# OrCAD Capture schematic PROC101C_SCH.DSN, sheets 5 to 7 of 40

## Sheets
5 30.PCIe INTERFACE: size C; title: PCIe INTERFACE; note: PROC067
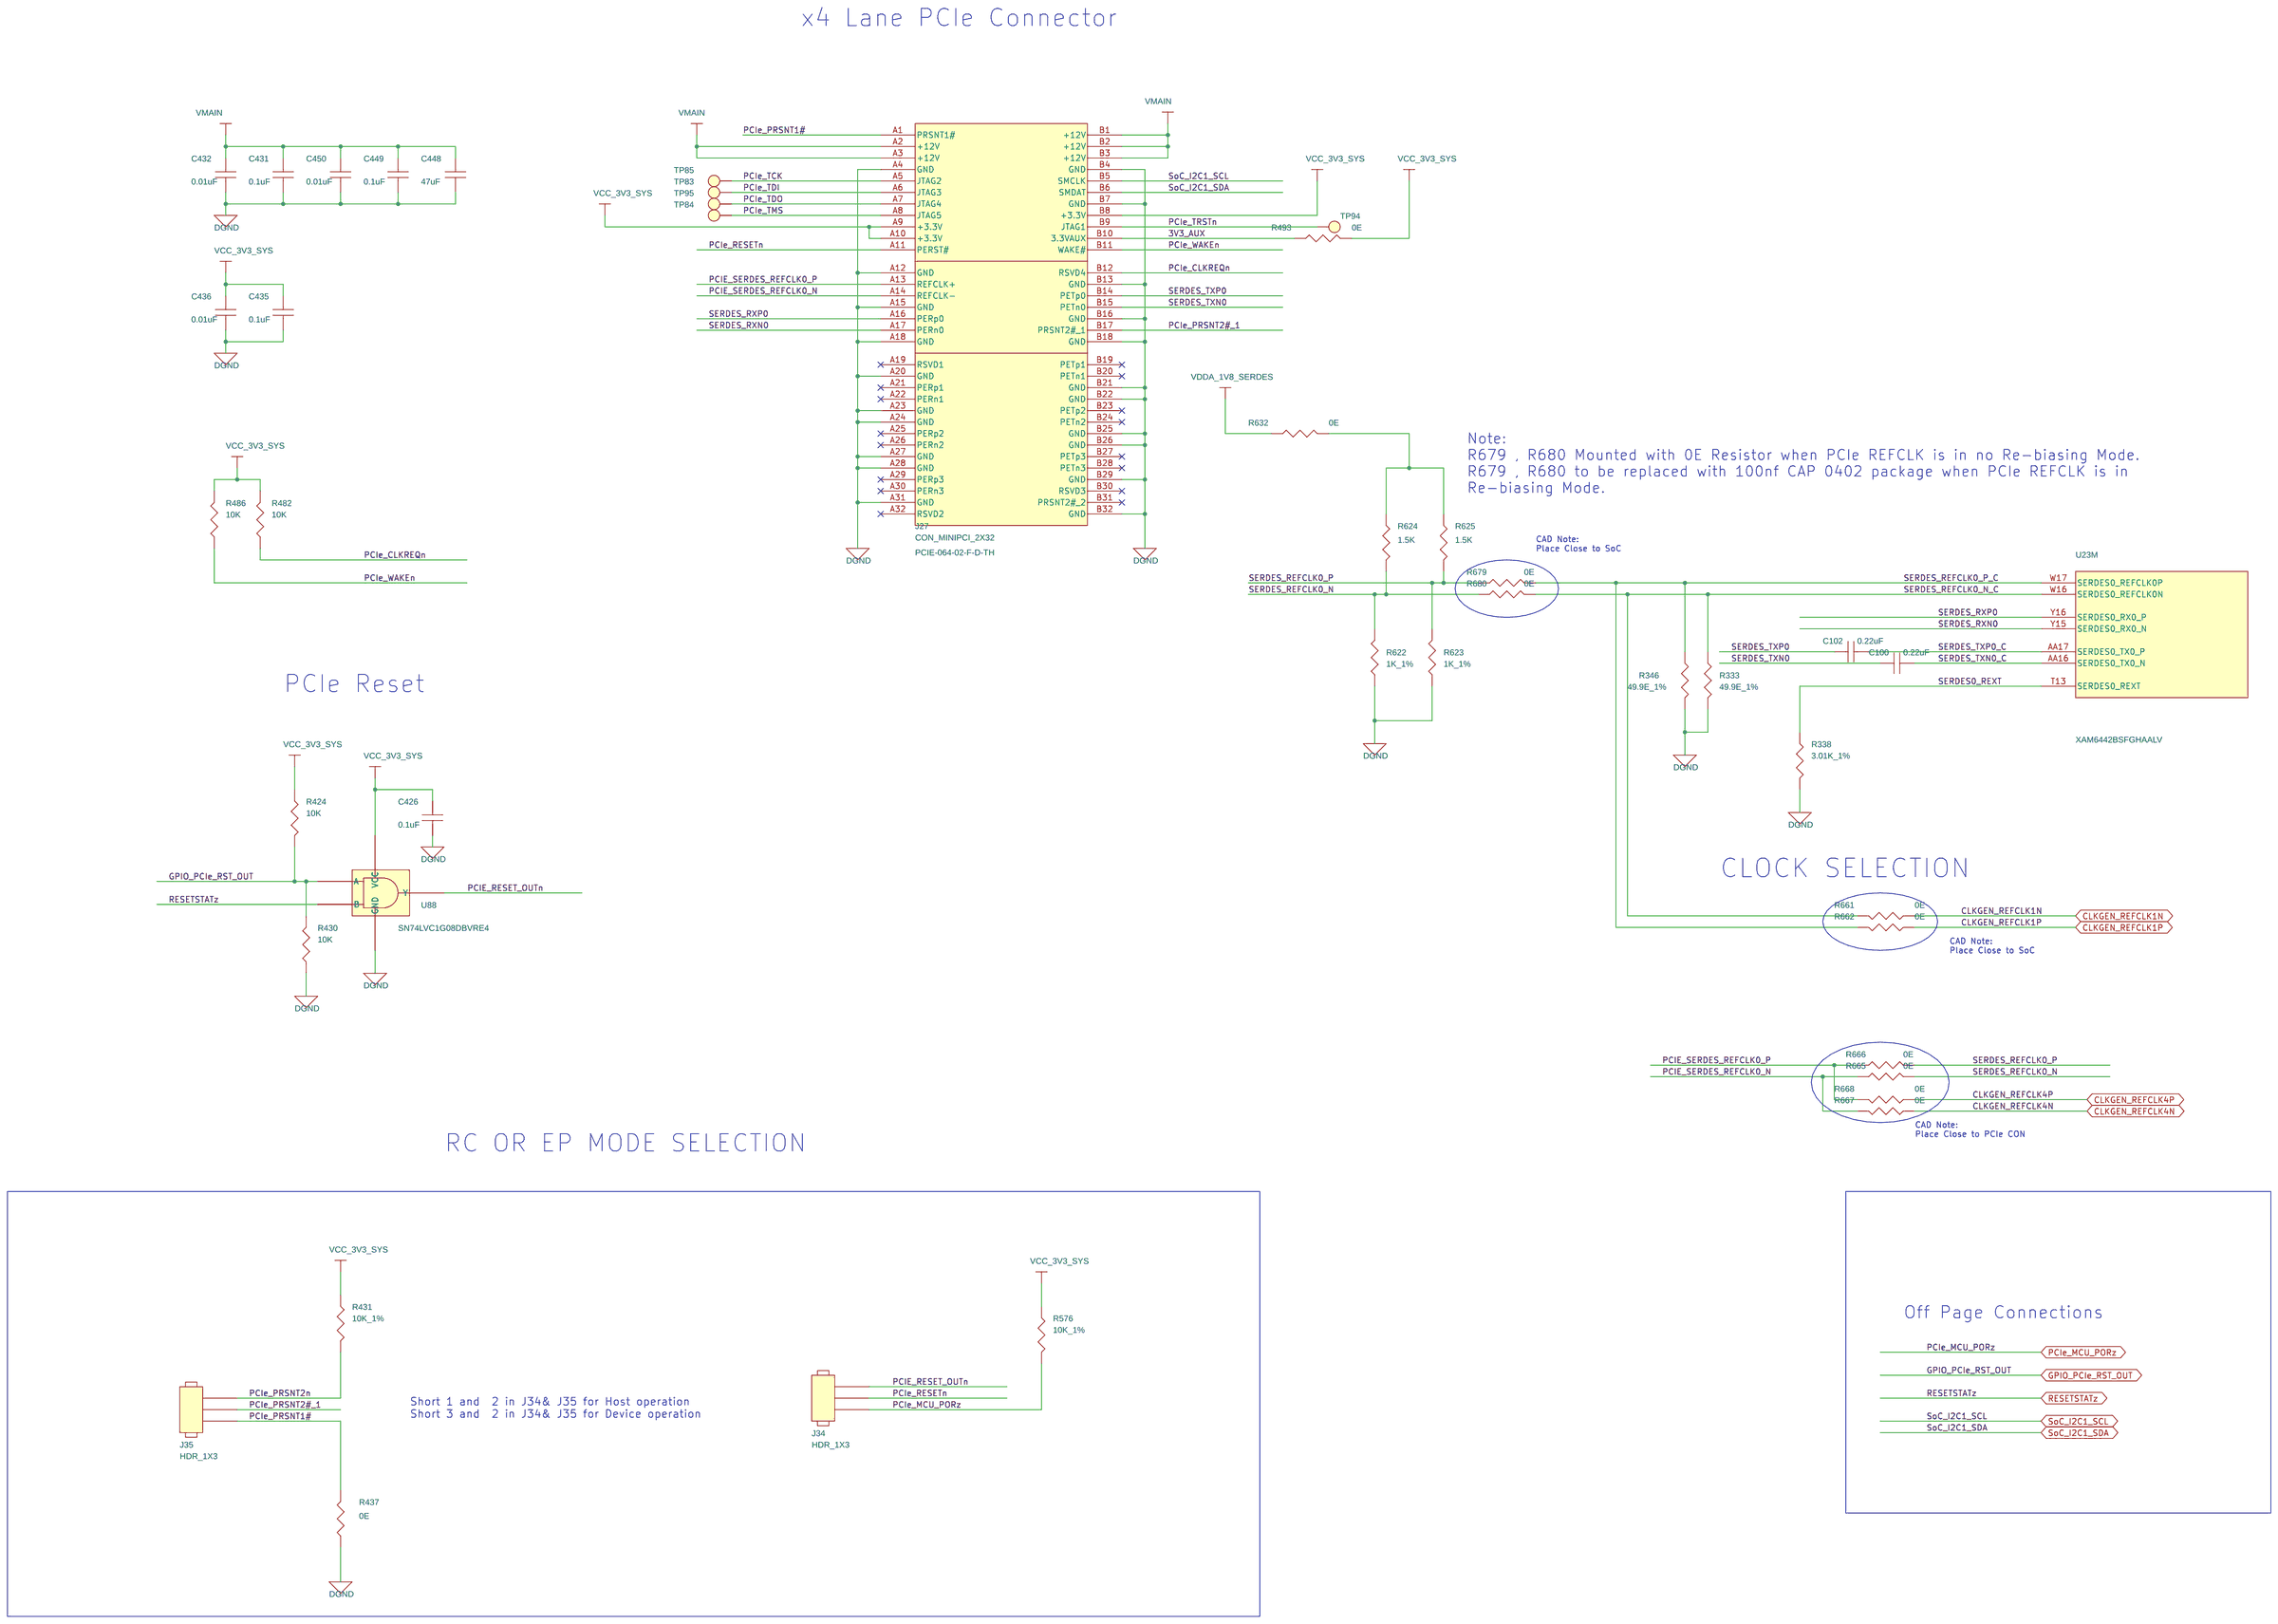
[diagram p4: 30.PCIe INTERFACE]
6 29. CAN & DISPLAY INTERFACE: size C; title: CAN & DISPLAY INTERFACE; note: MS_TI_MAXIE_APPLICATION_CARD_SCH_REVA
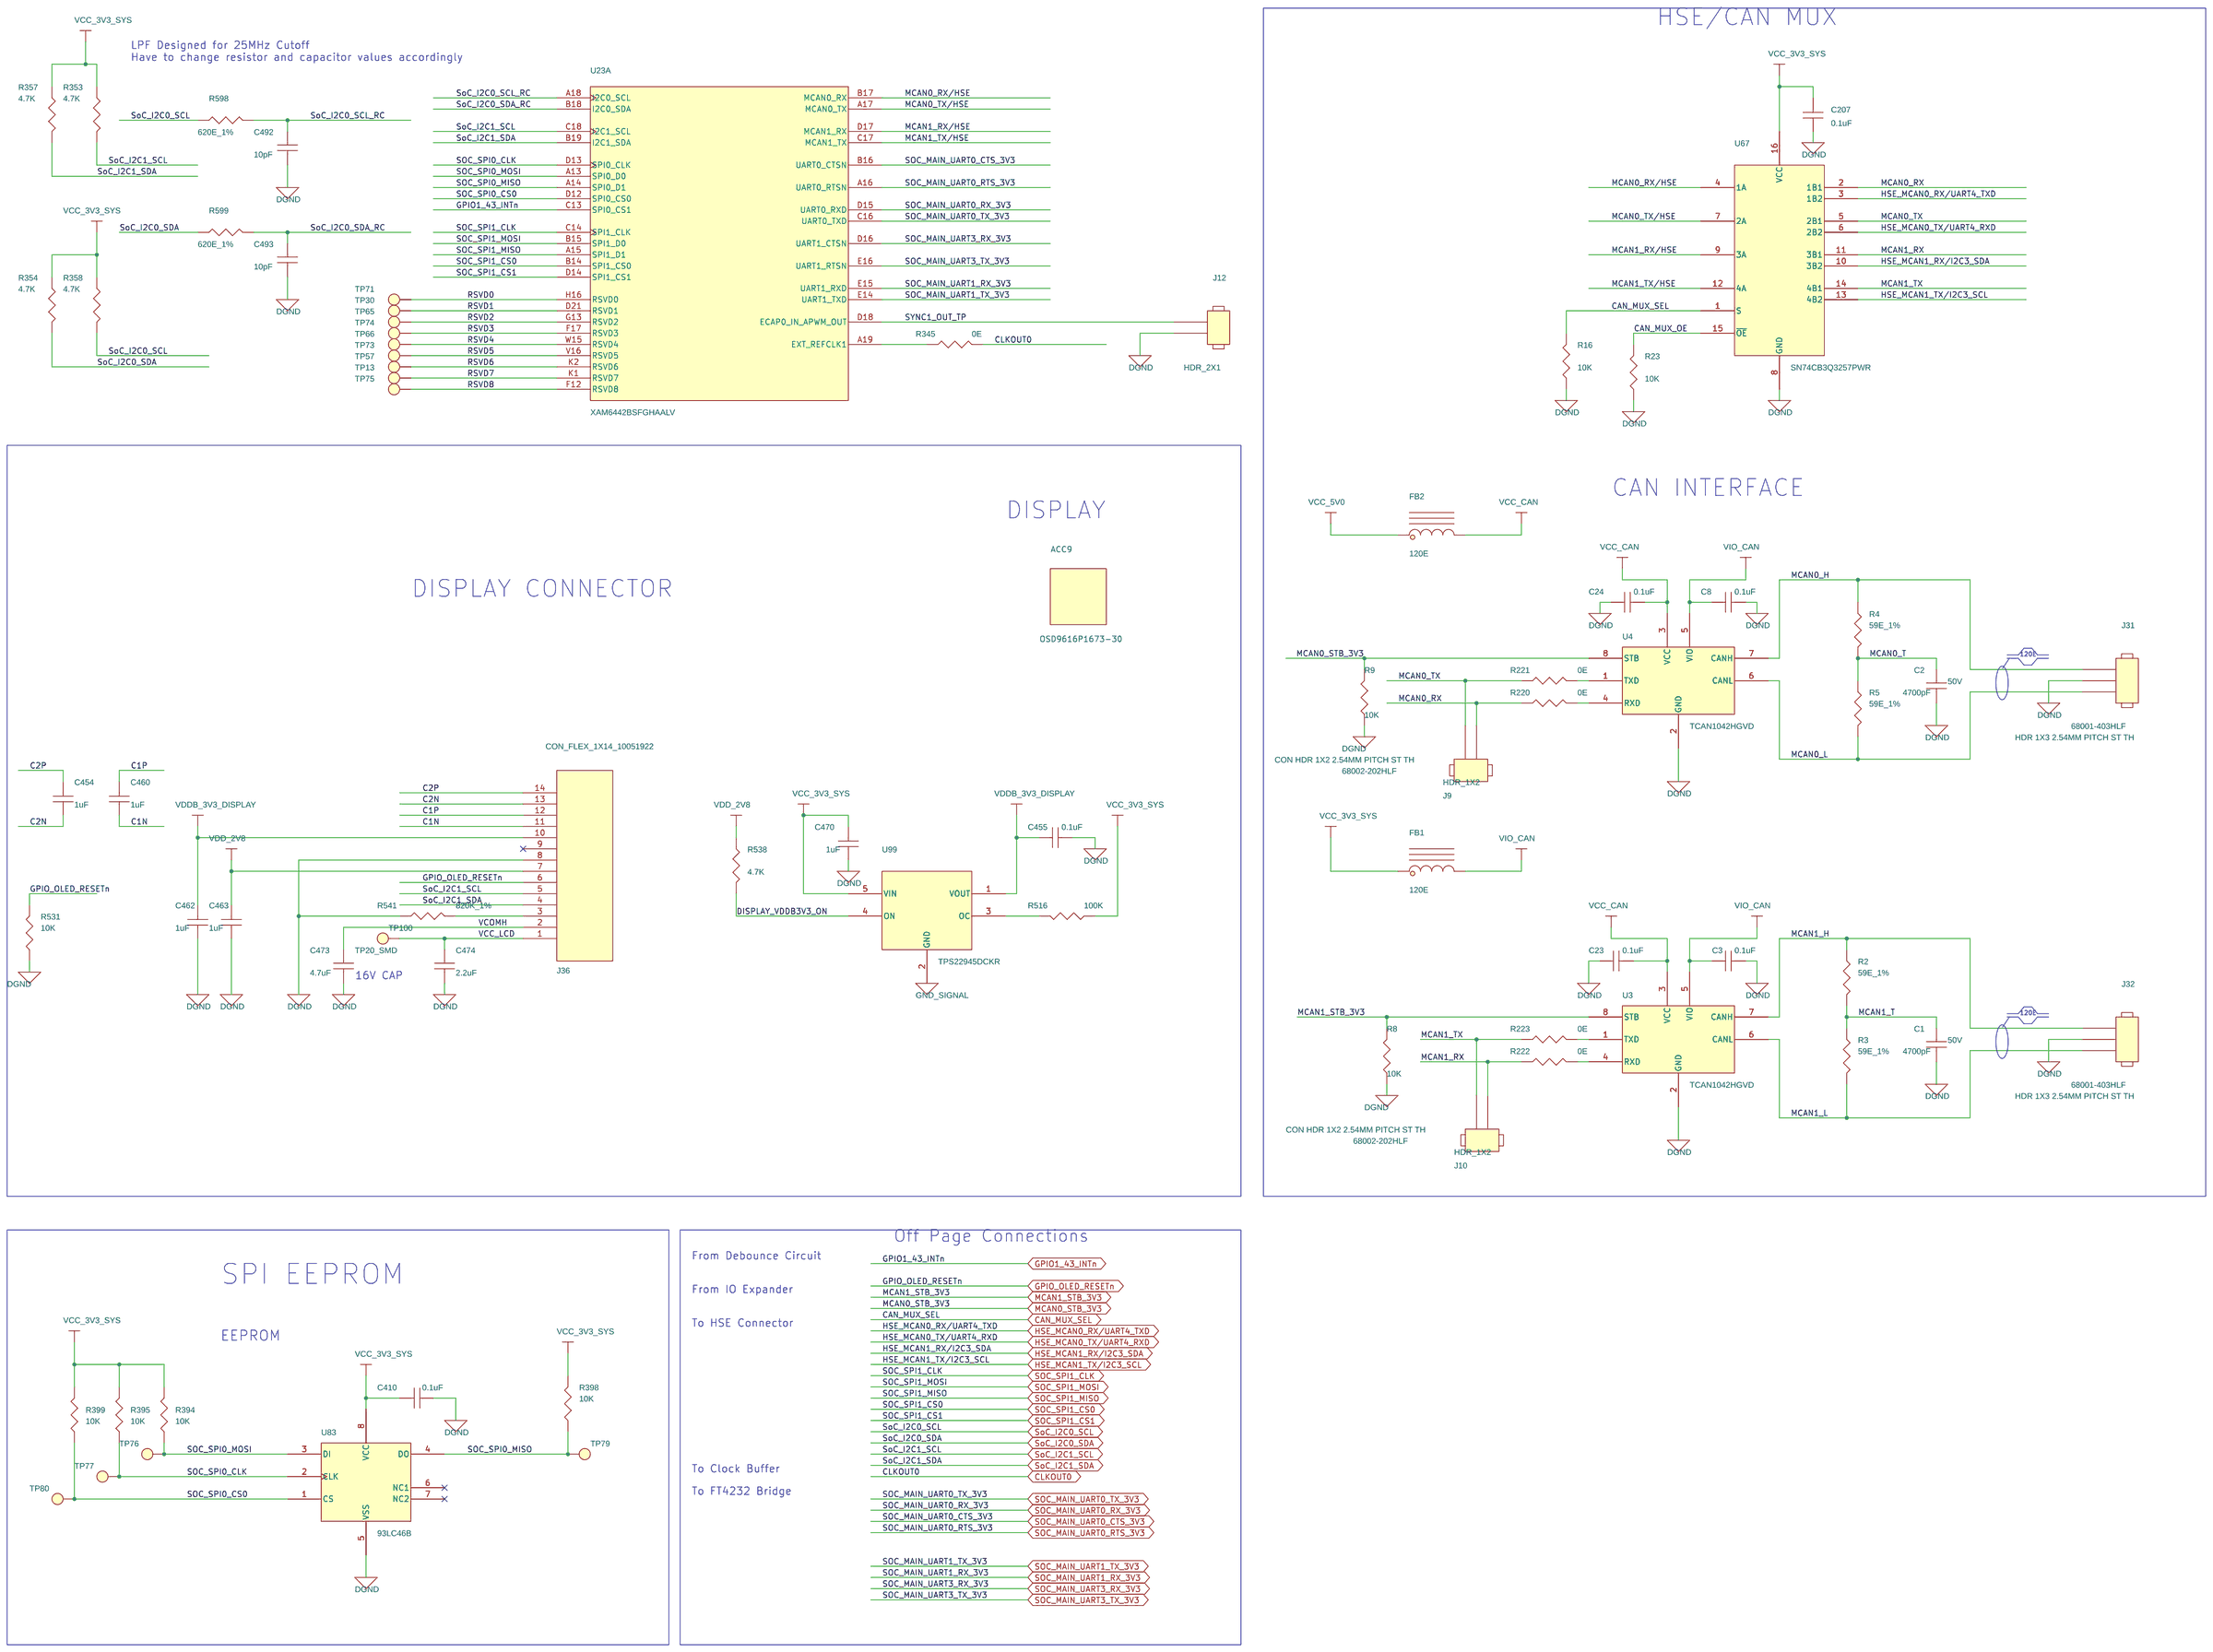
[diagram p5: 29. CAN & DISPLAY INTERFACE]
7 32.ETHERNET LED's&ADC CONNECTOR: size C; title: ETHERNET LEDs

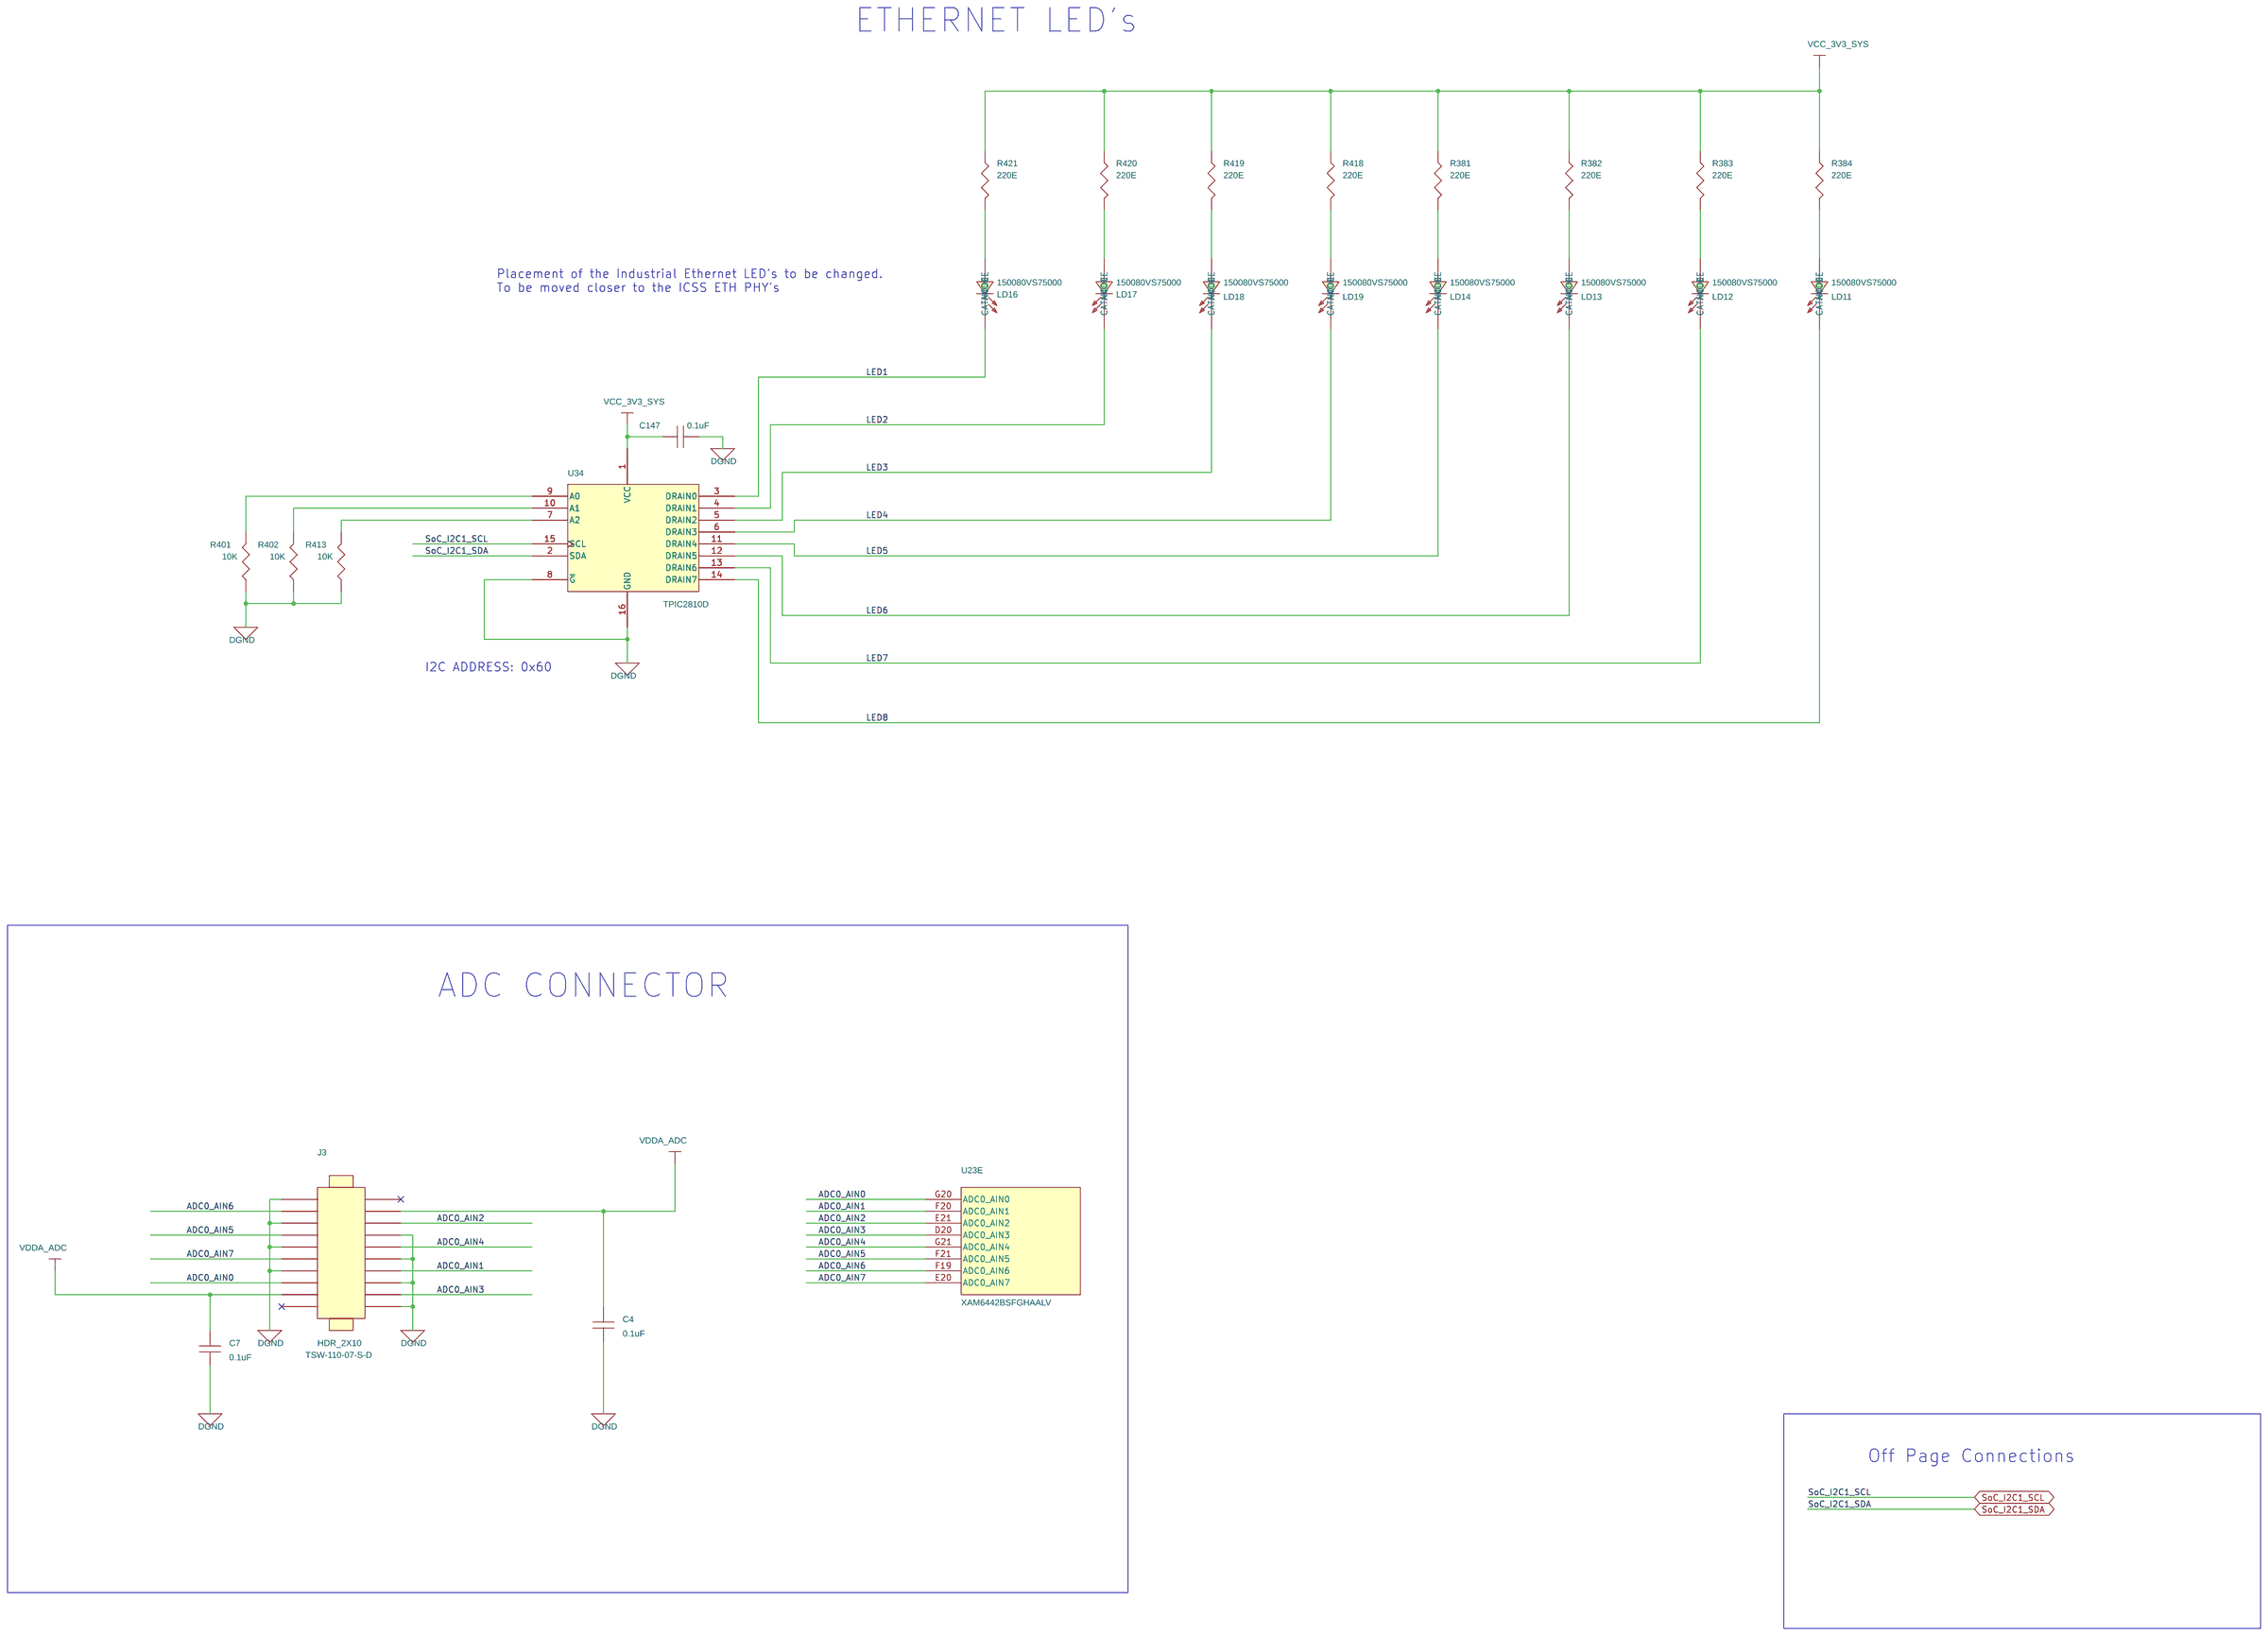
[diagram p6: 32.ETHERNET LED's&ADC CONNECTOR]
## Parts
sheet 28.GPMC & FSI CONNECTOR
U23  XAM6442BSFGHAALV  [FCBGA441_31-49_680X680_2-6]  (sections A,B,C,D,E,F,G,H,I,J,K,L,M,N,O,P)
sheet 29. CAN & DISPLAY INTERFACE
ACC9  OSD9616P1673-30  [NA]
C1  4700pF  [CAP0402_0-75]
C2  4700pF  [CAP0402_0-75]
C3  0.1uF  [CAP0402_0-75]
C8  0.1uF  [CAP0402_0-75]
C23  0.1uF  [CAP0402_0-75]
C24  0.1uF  [CAP0402_0-75]
C207  0.1uF  [CAP0402_0-75]
C410  0.1uF  [CAP0402_0-75]
C454  1uF  [CAP0402_0-75]
C455  0.1uF  [CAP0402_0-75]
C460  1uF  [CAP0402_0-75]
C462  1uF  [CAP0402_0-75]
C463  1uF  [CAP0402_0-75]
C470  1uF  [CAP0402_0-75]
C473  4.7uF  [CAP0603_1]
C474  2.2uF  [CAP0603_1]
C492  10pF  [CAP0402_0-75]
C493  10pF  [CAP0402_0-75]
FB1  120E  [IND0603_1]
FB2  120E  [IND0603_1]
J9  HDR_1X2  [HDR_1X2_68002-202_S_T_8-6]
J10  HDR_1X2  [HDR_1X2_68002-202_S_T_8-6]
J12  HDR_2X1  [HDR_2X1_100_S_T]
J31  HDR_1X3  [HDR_3X1_100_S_T]
J32  HDR_1X3  [HDR_3X1_100_S_T]
J36  CON_FLEX_1X14_10051922  [CON_FLEX1X14_10051922_S_R_S]
R2  59E_1%  [RES0402_0-5]
R3  59E_1%  [RES0402_0-5]
R4  59E_1%  [RES0402_0-5]
R5  59E_1%  [RES0402_0-5]
R8  10K  [RES0402_0-5]
R9  10K  [RES0402_0-5]
R16  10K  [RES0402_0-5]
R23  10K  [RES0402_0-5]
R220  0E  [RES0402_0-5]
R221  0E  [RES0402_0-5]
R222  0E  [RES0402_0-5]
R223  0E  [RES0402_0-5]
R345  0E  [RES0402_0-5]
R353  4.7K  [RES0402_0-5]
R354  4.7K  [RES0402_0-5]
R357  4.7K  [RES0402_0-5]
R358  4.7K  [RES0402_0-5]
R394  10K  [RES0402_0-5]
R395  10K  [RES0402_0-5]
R398  10K  [RES0402_0-5]
R399  10K  [RES0402_0-5]
R516  100K  [RES0402_0-5]
R531  10K  [RES0402_0-5]
R538  4.7K  [RES0402_0-5]
R541  820K_1%  [RES0402_0-5]
R598  620E_1%  [RES0402_0-5]
R599  620E_1%  [RES0402_0-5]
TP13  TP20_SMD  [TP20_SMD]
TP30  TP20_SMD  [TP20_SMD]
TP57  TP20_SMD  [TP20_SMD]
TP65  TP20_SMD  [TP20_SMD]
TP66  TP20_SMD  [TP20_SMD]
TP71  TP20_SMD  [TP20_SMD]
TP73  TP20_SMD  [TP20_SMD]
TP74  TP20_SMD  [TP20_SMD]
TP75  TP20_SMD  [TP20_SMD]
TP76  TP20_SMD  [TP20_SMD]
TP77  TP20_SMD  [TP20_SMD]
TP79  TP20_SMD  [TP20_SMD]
TP80  TP20_SMD  [TP20_SMD]
TP100  TP20_SMD  [TP20_SMD]
U3  TCAN1042HGVD  [SOIC8_1-8]
U4  TCAN1042HGVD  [SOIC8_1-8]
U67  SN74CB3Q3257PWR  [TSSOP16_25-59_205X180]
U83  93LC46B  [MSOP8_25-59_125X125_1-1]
U99  TPS22945DCKR  [SC70-5_1-1]
sheet 30.PCIe INTERFACE
C100  0.22uF  [CAP0201_0-5]
C102  0.22uF  [CAP0201_0-5]
C426  0.1uF  [CAP0402_0-75]
C431  0.1uF  [CAP0402_0-75]
C432  0.01uF  [CAP0402_0-75]
C435  0.1uF  [CAP0402_0-75]
C436  0.01uF  [CAP0402_0-75]
C448  47uF  [CAP1206_2]
C449  0.1uF  [CAP0402_0-75]
C450  0.01uF  [CAP0402_0-75]
J27  CON_MINIPCI_2X32  [CON_MINIPCI2X32_PCIE-064-02_S_S_T_11]
J34  HDR_1X3  [HDR_3X1_100_S_T]
J35  HDR_1X3  [HDR_3X1_100_S_T]
R333  49.9E_1%  [RES0402_0-5]
R338  3.01K_1%  [RES0402_0-5]
R346  49.9E_1%  [RES0402_0-5]
R424  10K  [RES0402_0-5]
R430  10K  [RES0402_0-5]
R431  10K_1%  [RES0402_0-5]
R437  0E  [RES0402_0-5]
R482  10K  [RES0402_0-5]
R486  10K  [RES0402_0-5]
R493  0E  [RES0402_0-5]
R576  10K_1%  [RES0402_0-5]
R622  1K_1%  [RES0402_0-5]
R623  1K_1%  [RES0402_0-5]
R624  1.5K  [RES0402_0-5]
R625  1.5K  [RES0402_0-5]
R632  0E  [RES0402_0-5]
R661  0E  [RES0402_0-5]
R662  0E  [RES0402_0-5]
R665  0E  [RES0402_0-5]
R666  0E  [RES0402_0-5]
R667  0E  [RES0402_0-5]
R668  0E  [RES0402_0-5]
R679  0E  [RES0402_0-5]
R680  0E  [RES0402_0-5]
TP83  TP20_SMD  [TP20_SMD]
TP84  TP20_SMD  [TP20_SMD]
TP85  TP20_SMD  [TP20_SMD]
TP94  TP20_SMD  [TP20_SMD]
TP95  TP20_SMD  [TP20_SMD]
U88  SN74LVC1G08DBVRE4  [SOT23-5]
sheet 32.ETHERNET LED's&ADC CONNECTOR
C4  0.1uF  [CAP0402_0-75]
C7  0.1uF  [CAP0402_0-75]
C147  0.1uF  [CAP0402_0-75]
J3  HDR_2X10  [HDR_2X10_TSW_100_S_T]
LD11  150080VS75000  [LED_150080VS75000_80X50_SMD_0-8]
LD12  150080VS75000  [LED_150080VS75000_80X50_SMD_0-8]
LD13  150080VS75000  [LED_150080VS75000_80X50_SMD_0-8]
LD14  150080VS75000  [LED_150080VS75000_80X50_SMD_0-8]
LD16  150080VS75000  [LED_150080VS75000_80X50_SMD_0-8]
LD17  150080VS75000  [LED_150080VS75000_80X50_SMD_0-8]
LD18  150080VS75000  [LED_150080VS75000_80X50_SMD_0-8]
LD19  150080VS75000  [LED_150080VS75000_80X50_SMD_0-8]
R381  220E  [RES0402_0-5]
R382  220E  [RES0402_0-5]
R383  220E  [RES0402_0-5]
R384  220E  [RES0402_0-5]
R401  10K  [RES0402_0-5]
R402  10K  [RES0402_0-5]
R413  10K  [RES0402_0-5]
R418  220E  [RES0402_0-5]
R419  220E  [RES0402_0-5]
R420  220E  [RES0402_0-5]
R421  220E  [RES0402_0-5]
U34  TPIC2810D  [SOIC16_1-8]

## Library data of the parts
U23 = XAM6442BSFGGAALV_BGA441: IC AM64x SoC MICROPROCESSOR BGA441; Chkd/date: ALVY/300322; Crtd /date: ALVY/300322; Custom_Duty: 15%; Customs_HS_Code: 85423100; Distributor_name: NA; Distributor_part_number: NA; Footprint Path: Y:\MIS_DATABASE\Library\ALTIUM_TOOL\PCB_FOOTPRINTS\Altium_Footprint_Lib.PcbLib; Height: 2.57MM; Library Path: Y:\MIS_DATABASE\Library\ALTIUM_TOOL\SCHEMATICS_PARTS\MS_MICROPROCESSOR_Library.schlib; Mfr_name: TEXAS INSTRUMENTS; Mistral Part No: 141220080002; Package: BGA441; Part_type: ICS\DIGITAL\MICROPROCESSOR; Project: AM64x-GP_EVM BRD; RoHS: NA; Temperature: NA; Tolerance: NA; Voltage: NA; Wattage: NA; Weight: NA; Datasheet: Y:\MIS_DATABASE\DATASHEETS\ICS\DIGITAL\MICROCONTROLLER\AM64-SoC_SVB.PDF
ACC9 = ACCESSORY: ACCESSORIE PASSIVE MATRIX MONOCHROME WHITE DISPLAY; Chkd/date: MANIRAJA/150221; Crtd /date: ALVY/150221; Mfr_name: OSD DISPLAYS; Mistral Part No: 160021020059; Part_type: ACCESSORIES; Project: TI_AM64x_EVM; Temperature: -40°C+70°C; Weight: 720mg; Datasheet: Y:\MIS_DATABASE\DATASHEETS\MISC\ACCESSORIES\OSD9616P1673-30.PDF
C1 C2 = CAP: CAP CERAMIC 4700pF 50V 10% X7R 0402; Chkd/date: MANIRAJA/170820; Crtd /date: ALVY/170820; Custom_Duty: 15%; Customs_HS_Code: 85322990; Distributor_name: DIGIKEY; Distributor_part_number: 732-7560-1-ND; Footprint Path: Y:\MIS_DATABASE\Library\ALTIUM_TOOL\PCB_FOOTPRINTS\Altium_Footprint_Lib.PcbLib; Height: 0.55MM; Library Path: Y:\MIS_DATABASE\Library\ALTIUM_TOOL\SCHEMATICS_PARTS\MS_DISCRETE_Library.schlib; Mfr_name: WURTH ELECTRONICS; Mfr_part_number: 885012205065; Mistral Part No: 120009030440-R; Package: 0402; Part_type: CAPACITORS\CERAMIC; Project: AM64x_EVM_BRD; RoHS: RoHS; Temperature: -55°C+125°C; Tolerance: 10%; Voltage: 50V; Wattage: NA; Weight: 12mg; Datasheet: Y:\MIS_DATABASE\DATASHEETS\CAPACITORS\885012205065.PDF
C3 C4 C7 C8 C23 C24 C147 C207 C410 C426 C431 C435 C449 C455 = CAP: CAP CERAMIC 0.1uF 25V 20% X5R 0402; Alt_Mfr_name: YAGEO AMERICA; Alt_Mfr_part_number: CC0402KRX5R8BB104; Chkd/date: MANIRAJA/170820; Crtd /date: ALVY/170820; Custom_Duty: 15%; Customs_HS_Code: 85322990; Distributor_name: DIGIKEY; Distributor_part_number: 732-7495-1-ND; Footprint Path: Y:\MIS_DATABASE\Library\ALTIUM_TOOL\PCB_FOOTPRINTS\Altium_Footprint_Lib.PcbLib; Height: 0.55MM; Library Path: Y:\MIS_DATABASE\Library\ALTIUM_TOOL\SCHEMATICS_PARTS\MS_DISCRETE_Library.schlib; Mfr_name: WURTH ELECTRONICS; Mfr_part_number: 885012105018; Mistral Part No: 120020080003-R; Package: 0402; Part_type: CAPACITORS\CERAMIC; Project: AM64x_EVM_BRD; RoHS: RoHS; Temperature: -55°C+85°C; Tolerance: 20%; Voltage: 25V; Wattage: NA; Weight: 0.65mg; Datasheet: Y:\MIS_DATABASE\DATASHEETS\CAPACITORS\885012105018.PDF
C454 C460 C462 C463 C470 = CAP: CAP CERAMIC 1uF 10V 20% X5R 0402; Chkd/date: MANIRAJA/210820; Crtd /date: ALVY/190820; Custom_Duty: 15%; Customs_HS_Code: 85322990; Distributor_name: DIGIKEY; Distributor_part_number: 732-7489-1-ND; Footprint Path: Y:\MIS_DATABASE\Library\ALTIUM_TOOL\PCB_FOOTPRINTS\Altium_Footprint_Lib.PcbLib; Height: 0.55MM; Library Path: Y:\MIS_DATABASE\Library\ALTIUM_TOOL\SCHEMATICS_PARTS\MS_DISCRETE_Library.schlib; Mfr_name: WURTH ELECTRONICS; Mfr_part_number: 885012105012; Mistral Part No: 120020080009-R; Package: 0402; Part_type: CAPACITORS\CERAMIC; Project: AM64x_EVM_BRD; RoHS: RoHS; Temperature: -55°C+85°C; Tolerance: 20%; Voltage: 10V; Wattage: NA; Weight: 0.65mg; Datasheet: Y:\MIS_DATABASE\DATASHEETS\CAPACITORS\885012105012.PDF
C473 = CAP: CAP CERAMIC 4.7uF 16V 10% X5R 0603; Chkd/date: MANIRAJA/131217; Crtd /date: ALVY/131217; Custom_Duty: 15%; Customs_HS_Code: 85322990; Distributor_name: DIGIKEY; Distributor_part_number: 311-1785-1-ND; Footprint Path: Y:\MIS_DATABASE\Library\ALTIUM_TOOL\PCB_FOOTPRINTS\Altium_Footprint_Lib.PcbLib; Height: 0.95MM; Library Path: Y:\MIS_DATABASE\Library\ALTIUM_TOOL\SCHEMATICS_PARTS\MS_DISCRETE_Library.schlib; Mfr_name: YAGEO AMERICA; Mfr_part_number: CC0603KRX5R7BB475; Mistral Part No: 120011050004-R; Package: 0603; Part_type: CAPACITORS\CERAMIC; Project: ASL_LIU_TYPE-II; RoHS: RoHS; Temperature: -55°C+85°C; Tolerance: 10%; Voltage: 16V; Wattage: NA; Weight: 2mg; Datasheet: Y:\MIS_DATABASE\DATASHEETS\CAPACITORS\YACC-X5R.PDF
C474 = CAP: CAP CERAMIC 2.2uF 35V 10% X5R 0603; Chkd/date: VASANTHA/270117; Crtd /date: MANIRAJA/270117; Custom_Duty: 15%; Customs_HS_Code: 85322990; Distributor_name: DIGIKEY; Distributor_part_number: 490-7204-1-ND; Footprint Path: Y:\MIS_DATABASE\Library\ALTIUM_TOOL\PCB_FOOTPRINTS\Altium_Footprint_Lib.PcbLib; Height: 0.90MM; Library Path: Y:\MIS_DATABASE\Library\ALTIUM_TOOL\SCHEMATICS_PARTS\MS_DISCRETE_Library.schlib; Mfr_name: MURATA; Mfr_part_number: GRM188R6YA225KA12D; Mistral Part No: 120017010016-R; Package: 0603; Part_type: CAPACITORS\CERAMIC; Project: SD820_NANO_SOM; RoHS: RoHS; Temperature: -55°C+85°C; Tolerance: 10%; Voltage: 35V; Wattage: NA; Weight: 6.3mg; Datasheet: Y:\MIS_DATABASE\DATASHEETS\CAPACITORS\MURATA-GXX-SER_NOV17.PDF
C492 C493 = CAP: CAP CERAMIC 10pF 16V 5% C0G(NP0) 0402; Chkd/date: MANIRAJA/100918; Crtd /date: ALVY/100918; Custom_Duty: 15%; Customs_HS_Code: 85322990; Distributor_name: DIGIKEY; Distributor_part_number: 732-7441-1-ND; Footprint Path: Y:\MIS_DATABASE\Library\ALTIUM_TOOL\PCB_FOOTPRINTS\Altium_Footprint_Lib.PcbLib; Height: 0.55MM; Library Path: Y:\MIS_DATABASE\Library\ALTIUM_TOOL\SCHEMATICS_PARTS\MS_DISCRETE_Library.schlib; Mfr_name: WURTH ELECTRONICS; Mfr_part_number: 885012005025; Mistral Part No: 120018030015-R; Package: 0402; Part_type: CAPACITORS\CERAMIC; Project: SMART-M_SCRIPTALK_PB; RoHS: RoHS; Temperature: -55°C+125°C; Tolerance: 5%; Voltage: 16V; Wattage: NA; Weight: 0.65mg; Datasheet: Y:\MIS_DATABASE\DATASHEETS\CAPACITORS\885012005025.PDF
FB1 FB2 = INDUCTOR_FERRITE: IND FERRITE BEAD CHIP 120E 2A 0603; Chkd/date: MANIRAJA/180820; Crtd /date: ALVY/180820; Custom_Duty: 24%; Customs_HS_Code: 85437099; Distributor_name: DIGIKEY; Distributor_part_number: 732-782631141CT-ND; Footprint Path: Y:\MIS_DATABASE\Library\ALTIUM_TOOL\PCB_FOOTPRINTS\Altium_Footprint_Lib.PcbLib; Height: 1.00MM; Library Path: Y:\MIS_DATABASE\Library\ALTIUM_TOOL\SCHEMATICS_PARTS\MS_FILTER_Library.schlib; Mfr_name: WURTH ELECTRONICS; Mfr_part_number: 782631141; Mistral Part No: 130020080015-R; Package: 0603; Part_type: INDUCTOR; Project: AM64x_EVM_BRD; RoHS: RoHS; Temperature: -55°C+125°C; Tolerance: 25%; Voltage: NA; Wattage: NA; Weight: NA; Datasheet: Y:\MIS_DATABASE\DATASHEETS\DISCRETES\INDUCTORS\782631141.PDF
J9 J10 = HEADER_2X1: CON HDR 1X2 2.54MM PITCH ST TH; Chkd/date: MANIRAJA/190118; Crtd /date: ALVY/190118; Custom_Duty: 24%; Customs_HS_Code: 85369090; Distributor_name: DIGIKEY; Distributor_part_number: 68002-202HLF-ND; Height: 8.58MM; Mfr_name: AMPHENOL; Mfr_part_number: 68002-202HLF; Mistral Part No: 150018010012-R; Package: THRU HOLE; Part_type: CONNECTOR\HEADERS; Project: TI_SVB_MAXWELL_DUT; RoHS: RoHS; Temperature: NA; Tolerance: NA; Voltage: NA; Wattage: NA; Weight: NA; Datasheet: Y:\MIS_DATABASE\DATASHEETS\CONNECTORS\68002.PDF
J12 = HEADER_2X1: CON HDR 2X1 2.54MM PITCH ST TH; Chkd/date: NAVEED/210714; Crtd /date: USMAN/031012; Custom_Duty: 24%; Customs_HS_Code: 85369090; Distributor_name: DIGIKEY; Distributor_part_number: WM8072-ND; Height: 5.60MM; Mfr_name: MOLEX; Mfr_part_number: 90120-0122; Mistral Part No: 150012100005-R; Package: THRU-HOLE; Part_type: CONNECTOR\HEADERS; Project: NPOL_FEP; RoHS: RoHS; Temperature: -55°C+125°C; Tolerance: NA; Voltage: NA; Wattage: NA; Weight: NA; Datasheet: Y:\MIS_DATABASE\DATASHEETS\CONNECTORS\90120-SERIES.PDF
J31 J32 = HEADER_3X1: HDR 1X3 2.54MM PITCH ST TH; Chkd/date: VASANTHA/290616; Crtd /date: VASANTHA/290616; Custom_Duty: 15%; Customs_HS_Code: 85322990; Distributor_name: DIGIKEY; Distributor_part_number: 609-3471-ND; Height: 8.58MM; Mfr_name: FCI; Mfr_part_number: 68001-403HLF; Mistral Part No: 150016060025-R; Package: THRU-HOLE; Part_type: CONNECTOR\HEADERS; Project: IKEYP; RoHS: RoHS; Temperature: -40°C+105°C; Tolerance: NA; Voltage: NA; Wattage: NA; Weight: NA; Datasheet: Y:\MIS_DATABASE\DATASHEETS\CONNECTORS\68000.PDF
J36 = CON_FLEX_14X1_FH19: CON FPC 1X14 0.50MM PITCH RT SMD; Chkd/date: VASANTHA/261115; Crtd /date: VASANTHA/261115; Custom_Duty: 24%; Customs_HS_Code: 85369090; Distributor_name: DIGIKEY; Distributor_part_number: 609-1237-1-ND; Height: 1.50MM; Mfr_name: FCI; Mfr_part_number: 10051922-1410ELF; Mistral Part No: 150015110023-R; Package: SMD; Part_type: CONNECTOR\FPC; Project: TI_C5545; RoHS: RoHS; Temperature: NA; Tolerance: NA; Voltage: NA; Wattage: NA; Weight: NA; Datasheet: Y:\MIS_DATABASE\DATASHEETS\CONNECTORS\10051922.PDF
R2-R5 = RESISTOR: RES 59E 1/10W 1% 0402; Chkd/date: MAZHAR/151208; Crtd /date: USMAN/031208; Custom_Duty: 15%; Customs_HS_Code: 85332119; Distributor_name: DIGIKEY; Distributor_part_number: P59.0LCT-ND; Footprint Path: Y:\MIS_DATABASE\Library\ALTIUM_TOOL\PCB_FOOTPRINTS\Altium_Footprint_Lib.PcbLib; Height: 0.40MM; Library Path: Y:\MIS_DATABASE\Library\ALTIUM_TOOL\SCHEMATICS_PARTS\MS_DISCRETE_Library.schlib; Mfr_name: PANASONIC-ECG; Mfr_part_number: ERJ-2RKF59R0X; Mistral Part No: 110009031010-R; Package: 0402; Part_type: RESISTORS\FIXED; Project: KHAN_HSST; RoHS: RoHS; Temperature: -55°C+155°C; Tolerance: 1%; Voltage: NA; Wattage: 1/10W; Weight: 0.8mg; Datasheet: Y:\MIS_DATABASE\DATASHEETS\RESISTORS\PAN-ERJSER_NOV17.PDF
R8 R9 R16 R23 R394 R395 R398 R399 R401 R402 R413 R424 R430 R482 R486 R531 = RESISTOR: RES 10K 1/16W 5% 0402; Chkd/date: VASANTHA/061216; Crtd /date: MAZHAR/230805; Custom_Duty: 15%; Customs_HS_Code: 85332119; Distributor_name: DIGIKEY; Distributor_part_number: 311-10KJRCT-ND; Footprint Path: Y:\MIS_DATABASE\Library\ALTIUM_TOOL\PCB_FOOTPRINTS\Altium_Footprint_Lib.PcbLib; Height: 0.40MM; Library Path: Y:\MIS_DATABASE\Library\ALTIUM_TOOL\SCHEMATICS_PARTS\MS_DISCRETE_Library.schlib; Mfr_name: YAGEO AMERICA; Mfr_part_number: RC0402JR-0710KL; Mistral Part No: 110011060021-R; Package: 0402; Part_type: RESISTORS\FIXED; Project: HSE; RoHS: RoHS; Temperature: -55°C+155°C; Tolerance: 5%; Voltage: NA; Wattage: 1/16W; Weight: 0.65mg; Datasheet: Y:\MIS_DATABASE\DATASHEETS\RESISTORS\RCXXXXL-SER_MAR18.PDF
R220-R223 R345 R437 R493 R632 R661 R662 R665-R668 R679 R680 = RESISTOR: RES 0E 1/16W JUMPER 0402; Chkd/date: VASANTHA/201216; Crtd /date: MUDDU/190810; Custom_Duty: 15%; Customs_HS_Code: 85332119; Distributor_name: DIGIKEY; Distributor_part_number: 541-0.0JCT-ND; Footprint Path: Y:\MIS_DATABASE\Library\ALTIUM_TOOL\PCB_FOOTPRINTS\Altium_Footprint_Lib.PcbLib; Height: 0.40MM; Library Path: Y:\MIS_DATABASE\Library\ALTIUM_TOOL\SCHEMATICS_PARTS\MS_DISCRETE_Library.schlib; Mfr_name: VISHAY; Mfr_part_number: CRCW04020000Z0ED; Mistral Part No: 110010080019-R; Package: 0402; Part_type: RESISTORS\FIXED; Project: PB_BUGBASE; RoHS: RoHS; Temperature: -55°C+155°C; Tolerance: NA; Voltage: NA; Wattage: 1/16W; Weight: 0.65mg; Datasheet: Y:\MIS_DATABASE\DATASHEETS\RESISTORS\CRCW0603.PDF
R353 R354 R357 R358 R538 = RESISTOR: RES 4.7K 1/16W 5% 0402; Chkd/date: VASANTHA/130516; Crtd /date: VASANTHA/130516; Custom_Duty: 15%; Customs_HS_Code: 85332119; Distributor_name: DIGIKEY; Distributor_part_number: 311-4.7KJRCT-ND; Footprint Path: Y:\MIS_DATABASE\Library\ALTIUM_TOOL\PCB_FOOTPRINTS\Altium_Footprint_Lib.PcbLib; Height: 0.40MM; Library Path: Y:\MIS_DATABASE\Library\ALTIUM_TOOL\SCHEMATICS_PARTS\MS_DISCRETE_Library.schlib; Mfr_name: YAGEO AMERICA; Mfr_part_number: RC0402JR-074K7L; Mistral Part No: 110011060001-R; Package: 0402; Part_type: RESISTORS\FIXED; Project: TMDXCSK368; RoHS: RoHS; Temperature: -55°C+155°C; Tolerance: 5%; Voltage: NA; Wattage: 1/16W; Weight: 0.65mg; Datasheet: Y:\MIS_DATABASE\DATASHEETS\RESISTORS\RCXXXXL-SER_MAR18.PDF
R516 = RESISTOR: RES 100K 1/16W 5% 0402; Chkd/date: VASANTHA/061216; Crtd /date: BAVISH/010611; Custom_Duty: 15%; Customs_HS_Code: 85332119; Distributor_name: DIGIKEY; Distributor_part_number: 541-100KJCT-ND; Footprint Path: Y:\MIS_DATABASE\Library\ALTIUM_TOOL\PCB_FOOTPRINTS\Altium_Footprint_Lib.PcbLib; Height: 0.40MM; Library Path: Y:\MIS_DATABASE\Library\ALTIUM_TOOL\SCHEMATICS_PARTS\MS_DISCRETE_Library.schlib; Mfr_name: VISHAY; Mfr_part_number: CRCW0402100KJNED; Mistral Part No: 110011060002-R; Package: 0402; Part_type: RESISTORS\FIXED; Project: AM4515_EVM_LCD; RoHS: RoHS; Temperature: -55°C+155°C; Tolerance: 5%; Voltage: NA; Wattage: 1/16W; Weight: 0.65mg; Datasheet: Y:\MIS_DATABASE\DATASHEETS\RESISTORS\CRCW0603.PDF
R541 = RESISTOR: RES 820K 1/10W 1% 0402; Chkd/date: SUHAS/270910; Crtd /date: MAZHAR/310809; Custom_Duty: 15%; Customs_HS_Code: 85332119; Distributor_name: DIGIKEY; Distributor_part_number: P820KLCT-ND; Footprint Path: Y:\MIS_DATABASE\Library\ALTIUM_TOOL\PCB_FOOTPRINTS\Altium_Footprint_Lib.PcbLib; Height: 0.40MM; Library Path: Y:\MIS_DATABASE\Library\ALTIUM_TOOL\SCHEMATICS_PARTS\MS_DISCRETE_Library.schlib; Mfr_name: PANASONIC-ECG; Mfr_part_number: ERJ-2RKF8203X; Mistral Part No: 110009080033-R; Package: 0402; Part_type: RESISTORS\FIXED; Project: BUG_BASE-II; RoHS: RoHS; Temperature: -55°C+155°C; Tolerance: 1%; Voltage: NA; Wattage: 1/10W; Weight: 0.8mg; Datasheet: Y:\MIS_DATABASE\DATASHEETS\RESISTORS\PAN-ERJSER_NOV17.PDF
R598 R599 = RESISTOR: RES 620E 1/10W 1% 0402; Chkd/date: USMAN/120313; Crtd /date: CHAITHANYA/270912; Custom_Duty: 15%; Customs_HS_Code: 85332119; Distributor_name: DIGIKEY; Distributor_part_number: P620LCT-ND; Footprint Path: Y:\MIS_DATABASE\Library\ALTIUM_TOOL\PCB_FOOTPRINTS\Altium_Footprint_Lib.PcbLib; Height: 0.40MM; Library Path: Y:\MIS_DATABASE\Library\ALTIUM_TOOL\SCHEMATICS_PARTS\MS_DISCRETE_Library.schlib; Mfr_name: PANASONIC-ECG; Mfr_part_number: ERJ-2RKF6200X; Mistral Part No: 110012090013-R; Package: 0402; Part_type: RESISTORS\FIXED; Project: ITS-CONTROLER_CARD; RoHS: RoHS; Temperature: -55°C+155°C; Tolerance: 1%; Voltage: NA; Wattage: 1/10W; Weight: 0.8mg; Datasheet: Y:\MIS_DATABASE\DATASHEETS\RESISTORS\PAN-ERJSER_NOV17.PDF
TP13 TP30 TP57 TP65 TP66 TP71 TP73-TP77 TP79 TP80 TP83-TP85 TP94 TP95 TP100 = TESTPOINT: TESTPOINT CIR 20 SMD; Chkd/date: SHREESHAIL/171006; Crtd /date: MAZHAR/171006; Custom_Duty: NA; Customs_HS_Code: NA; Distributor_name: NA; Distributor_part_number: NA; Footprint Path: Y:\MIS_DATABASE\Library\ALTIUM_TOOL\PCB_FOOTPRINTS\Altium_Footprint_Lib.PcbLib; Height: NA; Library Path: Y:\MIS_DATABASE\Library\ALTIUM_TOOL\SCHEMATICS_PARTS\MS_DISCRETE_Library.schlib; MECHANICAL 3D STEP FILE: NA; Mfr_name: LOCAL; Mistral Part No: NA; Package: SMD; Project: BT MODULE_CSRBC04; RoHS: NA; Temperature: NA; Tolerance: NA; Voltage: NA; Wattage: NA; Weight: NA; Datasheet: NA
U3 U4 = TCAN1042HGVD_SOIC8: IC FAULT PROTECTED CAN TRANSCEIVER WITH CAN FD SOIC8; Chkd/date: MANIRAJA/030717; Crtd /date: MANIRAJA/030717; Custom_Duty: 15%; Customs_HS_Code: 85423100; Distributor_name: DIGIKEY; Distributor_part_number: 296-43979-5-ND; Footprint Path: Y:\MIS_DATABASE\Library\ALTIUM_TOOL\PCB_FOOTPRINTS\Altium_Footprint_Lib.PcbLib; Height: 1.75MM; Library Path: Y:\MIS_DATABASE\Library\ALTIUM_TOOL\SCHEMATICS_PARTS\MS_TELECOM_Library.schlib; Mfr_name: TEXAS INSTRUMENTS; Mistral Part No: 143017070001-R; Package: SOIC8; Part_type: ICS\TELECOM\TRANSCEIVER; Project: TI_SVB_CONTROLLER CARD; RoHS: RoHS; Temperature: -55°C+125°C; Tolerance: NA; Voltage: NA; Wattage: NA; Weight: 540mg; Datasheet: Y:\MIS_DATABASE\DATASHEETS\ICS\DIGITAL\BUSTRANSCEIVER\TCAN1042.PDF
U67 = SN74CB3Q3257PWR_TSSOP16: IC 4BIT 1-OF-2 FET MULTIPLEXER/DEMULTIPLEXER TSSOP16; Chkd/date: SUHAS/251010; Crtd /date: USMAN/060109; Custom_Duty: 15%; Customs_HS_Code: 85423100; Distributor_name: DIGIKEY; Distributor_part_number: 296-19138-1-ND; Height: 1.20MM; Mfr_name: TEXAS INSTRUMENTS; Mistral Part No: 141009030117-R; Package: TSSOP16; Part_type: ICS\DIGITAL\COMBINATIONAL; Project: OMAP_EVM; RoHS: Sb/ Br FREE; Temperature: -40°C+85°C; Datasheet: Y:\MIS_DATABASE\DATASHEETS\ICS\DIGITAL\COMBINATIONAL\SN74CB3Q3257.PDF
U83 = 93LC46B_MSOP8: IC 1K MICROWIRE COMPATIBLE SERIAL EEPROM MSOP8; Chkd/date: MANIRAJA/150218; Crtd /date: ALVY/150218; Custom_Duty: 15%; Customs_HS_Code: 85423100; Distributor_name: DIGIKEY; Distributor_part_number: 93LC46B-I/MS-ND; Footprint Path: Y:\MIS_DATABASE\Library\ALTIUM_TOOL\PCB_FOOTPRINTS\Altium_Footprint_Lib.PcbLib; Height: 1.10MM; Library Path: Y:\MIS_DATABASE\Library\ALTIUM_TOOL\SCHEMATICS_PARTS\MS_MISCMEMORY_Library.schlib; Mfr_name: MICROCHIP; Mfr_part_number: 93LC46B-I/MS; Mistral Part No: 141118020002-R; Package: MSOP8; Part_type: ICS\DIGITAL\MEMORY; Project: TI_MAXIE_CPB; RoHS: RoHS; Temperature: -40°C+85°C; Tolerance: NA; Voltage: NA; Wattage: NA; Weight: 140mg; Datasheet: Y:\MIS_DATABASE\DATASHEETS\ICS\MEMORY\93LC46B.PDF
U99 = TPS22945DCKR_SC70-5: IC LOW INPUT VOLTAGE CURRENT LIMITED LOAD SWITCH SC70-5; Chkd/date: VASANTHA/010117; Crtd /date: USMAN/020409; Custom_Duty: 15%; Customs_HS_Code: 85423100; Distributor_name: DIGIKEY; Distributor_part_number: 296-24475-1-ND; Height: 1.10MM; Mfr_name: TEXAS INSTRUMENTS; Mistral Part No: 142009030143-R; Package: SC70-5; Part_type: ICS\POWER; Project: AXON; RoHS: RoHS; Temperature: -40°C+85°C; Tolerance: NA; Voltage: NA; Wattage: NA; Weight: 2.5mg; Datasheet: Y:\MIS_DATABASE\DATASHEETS\ICS\POWER\TPS2294.PDF
C100 C102 = CAP: CAP CERAMIC 0.22uF 6.3V 10% X6S 0201; Chkd/date: ALVY/290621; Crtd /date: MANIRAJA/290621; Custom_Duty: 15%; Customs_HS_Code: 85322990; Distributor_name: DIGIKEY; Distributor_part_number: 490-10392-1-ND; Footprint Path: Y:\MIS_DATABASE\Library\ALTIUM_TOOL\PCB_FOOTPRINTS\Altium_Footprint_Lib.PcbLib; Height: 0.33MM; Library Path: Y:\MIS_DATABASE\Library\ALTIUM_TOOL\SCHEMATICS_PARTS\MS_DISCRETE_Library.schlib; Mfr_name: MURATA; Mfr_part_number: GRM033C80J224KE90D; Mistral Part No: 120021060017-R; Package: 0201; Part_type: CAPACITORS\CERAMIC; Project: TI_J7AEP_EVM; RoHS: RoHS; Temperature: -55°C+105°C; Tolerance: 10%; Voltage: 6.3V; Wattage: NA; Weight: 0.33mg; Datasheet: Y:\MIS_DATABASE\DATASHEETS\CAPACITORS\GRM033C80J224KE90.PDF
C432 C436 C450 = CAP: CAP CERAMIC 0.01uF 25V 10% X7R 0402; Chkd/date: MANIRAJA/170820; Crtd /date: ALVY/170820; Custom_Duty: 15%; Customs_HS_Code: 85322990; Distributor_name: DIGIKEY; Distributor_part_number: 732-7545-1-ND; Footprint Path: Y:\MIS_DATABASE\Library\ALTIUM_TOOL\PCB_FOOTPRINTS\Altium_Footprint_Lib.PcbLib; Height: 0.55MM; Library Path: Y:\MIS_DATABASE\Library\ALTIUM_TOOL\SCHEMATICS_PARTS\MS_DISCRETE_Library.schlib; Mfr_name: WURTH ELECTRONICS; Mfr_part_number: 885012205050; Mistral Part No: 120011090040-R; Package: 0402; Part_type: CAPACITORS\CERAMIC; Project: AM64x_EVM_BRD; RoHS: RoHS; Temperature: -55°C+125°C; Tolerance: 10%; Voltage: 25V; Wattage: NA; Weight: 0.65mg; Datasheet: Y:\MIS_DATABASE\DATASHEETS\CAPACITORS\885012205050.PDF
C448 = CAP: CAP CERAMIC 47uF 25V 20% X5R 1206; Chkd/date: MANIRAJA/230118; Crtd /date: MANIRAJA/230118; Custom_Duty: 15%; Customs_HS_Code: 85322990; Distributor_name: DIGIKEY; Distributor_part_number: 490-16268-1-ND; Footprint Path: Y:\MIS_DATABASE\Library\ALTIUM_TOOL\PCB_FOOTPRINTS\Altium_Footprint_Lib.PcbLib; Height: 1.80MM; Library Path: Y:\MIS_DATABASE\Library\ALTIUM_TOOL\SCHEMATICS_PARTS\MS_DISCRETE_Library.schlib; Mfr_name: MURATA; Mfr_part_number: GRM31CR61E476ME44L; Mistral Part No: 120013050002-R; Package: 1206; Part_type: CAPACITORS\CERAMIC; Project: TI_MAXIE_CPB; RoHS: RoHS; Temperature: -55°C+85°C; Tolerance: 20%; Voltage: 25V; Wattage: NA; Weight: 40mg; Datasheet: Y:\MIS_DATABASE\DATASHEETS\CAPACITORS\MURATA-GXX-SER_NOV17.PDF
J27 = CON_MINIPCI_32X2: CON MINIPCI 2X32 1.00MM PITCH SOCKET ST TH; Chkd/date: MANIRAJA/101017; Crtd /date: MANIRAJA/101017; Custom_Duty: 24%; Customs_HS_Code: 85369090; Distributor_name: DIGIKEY; Distributor_part_number: SAM9742-ND; Height: 11.00MM; Mfr_name: SAMTEC; Mfr_part_number: PCIE-064-02-F-D-TH; Mistral Part No: 150017100015-R; Package: THRU-HOLE; Part_type: CONNECTOR\PCI; Project: TI_SVB_MAXWELL_SPM; RoHS: RoHS; TEXT: PCIe x2; Temperature: -55°C+125°C; Tolerance: NA; Voltage: NA; Wattage: NA; Weight: NA; Datasheet: Y:\MIS_DATABASE\DATASHEETS\CONNECTORS\SAMTEC-PCIE-TH.PDF
J34 J35 = HEADER_3X1: HDR 1X3 2.54MM PITCH ST TH; Chkd/date: VASANTHA/290616; Crtd /date: VASANTHA/290616; Custom_Duty: 15%; Customs_HS_Code: 85322990; Distributor_name: DIGIKEY; Distributor_part_number: 609-3471-ND; Height: 8.58MM; Mfr_name: FCI; Mfr_part_number: 68001-403HLF; Mistral Part No: 150016060025-R; Package: THRU-HOLE; Part_type: CONNECTOR\HEADERS; Project: IKEYP; RoHS: RoHS; TEXT: REST; TEXT1: INT; TEXT2: EXT; Temperature: -40°C+105°C; Tolerance: NA; Voltage: NA; Wattage: NA; Weight: NA; Datasheet: Y:\MIS_DATABASE\DATASHEETS\CONNECTORS\68000.PDF
R333 R346 = RESISTOR: RES 49.9E 1/16W 1% 0402; Chkd/date: MANIRAJA/210519; Crtd /date: MANIRAJA/210519; Custom_Duty: 15%; Customs_HS_Code: 85332119; Distributor_name: DIGIKEY; Distributor_part_number: 541-3967-1-ND; Footprint Path: Y:\MIS_DATABASE\Library\ALTIUM_TOOL\PCB_FOOTPRINTS\Altium_Footprint_Lib.PcbLib; Height: 0.35MM; Library Path: Y:\MIS_DATABASE\Library\ALTIUM_TOOL\SCHEMATICS_PARTS\MS_DISCRETE_Library.schlib; Mfr_name: VISHAY; Mfr_part_number: CRCW040249R9FKEDC; Mistral Part No: 110009030846-R; Package: 0402; Part_type: RESISTORS\FIXED; Project: RFSU_RFTJ_CARD; RoHS: RoHS; Temperature: -55°C+155°C; Tolerance: 1%; Voltage: NA; Wattage: 1/16W; Weight: 0.65mg; Datasheet: Y:\MIS_DATABASE\DATASHEETS\RESISTORS\CRCW_C-SER.PDF
R338 = RESISTOR: RES 3.01K 1/16W 1% 0402; Chkd/date: MANIRAJA/150620; Crtd /date: ALVY/120620; Custom_Duty: 15%; Customs_HS_Code: 85332119; Distributor_name: DIGIKEY; Distributor_part_number: 541-3.01KLCT-ND; Footprint Path: Y:\MIS_DATABASE\Library\ALTIUM_TOOL\PCB_FOOTPRINTS\Altium_Footprint_Lib.PcbLib; Height: 0.40MM; Library Path: Y:\MIS_DATABASE\Library\ALTIUM_TOOL\SCHEMATICS_PARTS\MS_DISCRETE_Library.schlib; Mfr_name: VISHAY; Mfr_part_number: CRCW04023K01FKED; Mistral Part No: 110020060037-R; Package: 0402; Part_type: RESISTORS\FIXED; Project: AM64x-GP_EVM BRD; RoHS: RoHS; Temperature: -55°C+155°C; Tolerance: 1%; Voltage: NA; Wattage: 1/16W; Weight: 0.65mg; Datasheet: Y:\MIS_DATABASE\DATASHEETS\RESISTORS\CRCW0603.PDF
R431 R576 = RESISTOR: RES 10K 1/16W 1% 0402; Chkd/date: VASANTHA/201216; Crtd /date: GEETHA/290506; Custom_Duty: 15%; Customs_HS_Code: 85332119; Distributor_name: DIGIKEY; Distributor_part_number: 311-10.0KLRTR-ND; Footprint Path: Y:\MIS_DATABASE\Library\ALTIUM_TOOL\PCB_FOOTPRINTS\Altium_Footprint_Lib.PcbLib; Height: 0.40MM; Library Path: Y:\MIS_DATABASE\Library\ALTIUM_TOOL\SCHEMATICS_PARTS\MS_DISCRETE_Library.schlib; Mfr_name: YAGEO AMERICA; Mfr_part_number: RC0402FR-0710KL; Mistral Part No: 110015090015-R; Package: 0402; Part_type: RESISTORS\FIXED; Project: VOCERA; RoHS: RoHS; Temperature: -55°C+155°C; Tolerance: 1%; Voltage: NA; Wattage: 1/16W; Weight: 0.65mg; Datasheet: Y:\MIS_DATABASE\DATASHEETS\RESISTORS\RCXXXXL-SER_MAR18.PDF
R622 R623 = RESISTOR: RES 1K 1/10W 1% 0402; Chkd/date: VASANTHA/281216; Crtd /date: MAZHAR/150506; Custom_Duty: 15%; Customs_HS_Code: 85332119; Distributor_name: DIGIKEY; Distributor_part_number: P1.00KLCT-ND; Footprint Path: Y:\MIS_DATABASE\Library\ALTIUM_TOOL\PCB_FOOTPRINTS\Altium_Footprint_Lib.PcbLib; Height: 0.40MM; Library Path: Y:\MIS_DATABASE\Library\ALTIUM_TOOL\SCHEMATICS_PARTS\MS_DISCRETE_Library.schlib; Mfr_name: PANASONIC-ECG; Mfr_part_number: ERJ-2RKF1001X; Mistral Part No: 110009030411-R; Package: 0402; Part_type: RESISTORS\FIXED; Project: VOCERA; RoHS: RoHS; Temperature: -55°C+155°C; Tolerance: 1%; Voltage: NA; Wattage: 1/10W; Weight: 0.8mg; Datasheet: Y:\MIS_DATABASE\DATASHEETS\RESISTORS\PAN-ERJSER_NOV17.PDF
R624 R625 = RESISTOR: RES 1.5K 1/16W 5% 0402; Chkd/date: MANIRAJA/310718; Crtd /date: BAVISH/021210; Custom_Duty: 15%; Customs_HS_Code: 85332119; Distributor_name: DIGIKEY; Distributor_part_number: 311-1.5KJRCT-ND; Footprint Path: Y:\MIS_DATABASE\Library\ALTIUM_TOOL\PCB_FOOTPRINTS\Altium_Footprint_Lib.PcbLib; Height: 0.40MM; Library Path: Y:\MIS_DATABASE\Library\ALTIUM_TOOL\SCHEMATICS_PARTS\MS_DISCRETE_Library.schlib; Mfr_name: YAGEO AMERICA; Mfr_part_number: RC0402JR-071K5L; Mistral Part No: 110010120012-R; Package: 0402; Part_type: RESISTORS\FIXED; Project: TE4; RoHS: RoHS; Temperature: -55°C+155°C; Tolerance: 5%; Voltage: NA; Wattage: 1/16W; Weight: 0.65mg; Datasheet: Y:\MIS_DATABASE\DATASHEETS\RESISTORS\RCXXXXL-SER_MAR18.PDF
U88 = SN74LVC1G08DBVRE4_SOT23-5: IC SINGLE 2-INPUT POSITIVE AND GATE SOT23-5; Chkd/date: SUHAS/221010; Crtd /date: USMAN/151008; Custom_Duty: 15%; Customs_HS_Code: 85423100; Distributor_name: DIGIKEY; Distributor_part_number: SN74LVC1G08DBVRE4-ND; Height: 1.45MM; Mfr_name: TEXAS INSTRUMENTS; Mistral Part No: 141009060026-R; Part_type: ICS\DIGITAL\GATES; Project: KHAN_MAIN; RoHS: Sb/ Br FREE; Temperature: -40°C+85°C; Datasheet: Y:\MIS_DATABASE\DATASHEETS\ICS\DIGITAL\GATES\SN74LVC1G08.PDF
J3 = HEADER_10X2: CON HDR 2X10 2.54MM PITCH ST TH; Chkd/date: NAVEED/140515; Crtd /date: MAZHAR/020909; Custom_Duty: 0.24; Customs_HS_Code: 85369090; Distributor_name: DIGIKEY; Distributor_part_number: SAM1032-10-ND; Height: 5.02MM; Mfr_name: SAMTEC; Mfr_part_number: TSW-110-07-S-D; Mistral Part No: 150009090001-R; Package: THRU-HOLE; Part_type: CONNECTOR\HEADERS; Project: SMART VIEW_NVR; RoHS: RoHS; Temperature: NA; Tolerance: NA; Voltage: NA; Wattage: NA; Weight: NA; Datasheet: Y:\MIS_DATABASE\DATASHEETS\CONNECTORS\TSW-106-23-T-S.PDF
LD11-LD14 LD16-LD19 = DIODE_LED: DIODE LED BRIGHT GREEN SMD; Chkd/date: MANIRAJA/180820; Crtd /date: ALVY/180820; Custom_Duty: 24%; Customs_HS_Code: 85439000; Distributor_name: DIGIKEY; Distributor_part_number: 732-4986-1-ND; Footprint Path: Y:\MIS_DATABASE\Library\ALTIUM_TOOL\PCB_FOOTPRINTS\Altium_Footprint_Lib.PcbLib; Height: 0.80MM; Library Path: Y:\MIS_DATABASE\Library\ALTIUM_TOOL\SCHEMATICS_PARTS\MS_OPTO_Library.schlib; Mfr_name: WURTH ELECTRONICS; Mistral Part No: 130020080012-R; Package: SMD; Part_type: OPTO\LED; Project: AM64x_EVM_BRD; RoHS: RoHS; Temperature: -40°C+85°C; Tolerance: NA; Voltage: NA; Wattage: NA; Weight: 10mg; Datasheet: Y:\MIS_DATABASE\DATASHEETS\DISCRETES\LEDS\150080VS75000.PDF
R381-R384 R418-R421 = RESISTOR: RES 220E 1/10W 5% 0402; Chkd/date: VASANTHA/291216; Crtd /date: GEETHA/260406; Custom_Duty: 15%; Customs_HS_Code: 85332119; Distributor_name: DIGIKEY; Distributor_part_number: P220JCT-ND; Footprint Path: Y:\MIS_DATABASE\Library\ALTIUM_TOOL\PCB_FOOTPRINTS\Altium_Footprint_Lib.PcbLib; Height: 0.40MM; Library Path: Y:\MIS_DATABASE\Library\ALTIUM_TOOL\SCHEMATICS_PARTS\MS_DISCRETE_Library.schlib; Mfr_name: PANASONIC-ECG; Mfr_part_number: ERJ-2GEJ221X; Mistral Part No: 110009030506-R; Package: 0402; Part_type: RESISTORS\FIXED; Project: RED EYE; RoHS: RoHS; Temperature: -55°C+155°C; Tolerance: 5%; Voltage: NA; Wattage: 1/10W; Weight: 0.8mg; Datasheet: Y:\MIS_DATABASE\DATASHEETS\RESISTORS\PAN-ERJSER_NOV17.PDF
U34 = TPIC2810D_SOIC16: IC 8-BIT LED DRIVER WITH I2C INTERFACE SOIC16; Chkd/date: MANIRAJA/230817; Crtd /date: MANIRAJA/220817; Custom_Duty: 15%; Customs_HS_Code: 85423100; Distributor_name: DIGIKEY; Distributor_part_number: 296-13746-5-ND; Height: 1.75MM; Mfr_name: TEXAS INSTRUMENTS; Mistral Part No: 141017080026-R; Package: SOIC16; Part_type: ICS\INTERFACE; Project: TI_MAXIE_CPB; RoHS: RoHS; Temperature: -40°C+125°C; Tolerance: NA; Voltage: NA; Wattage: NA; Weight: NA; Datasheet: Y:\MIS_DATABASE\DATASHEETS\ICS\INTERFACE\TPIC2810D.PDF

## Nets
3V3_AUX: J27.B10(3.3VAUX) R493.2
DGND: C1.2 C2.2 C3.2 C4.1 C7.1 C8.2 C23.1 C24.1 C147.2 C207.1 C410.1 C426.2 C431.2 C432.2 C435.2 C436.2 C448.2 C449.2 C450.2 C455.2 C462.1 C463.1 C470.1 C473.2 C474.2 C492.2 C493.2 J3.1 J3.5 J3.8 J3.9 J3.12 J3.13 J3.16 J3.20 J12.2 J27.A4(GND) J27.A12(GND) J27.A15(GND) J27.A18(GND) J27.A20(GND) J27.A23(GND) J27.A24(GND) J27.A27(GND) J27.A28(GND) J27.A31(GND) J27.B4(GND) J27.B7(GND) J27.B13(GND) J27.B16(GND) J27.B18(GND) J27.B21(GND) J27.B22(GND) J27.B25(GND) J27.B26(GND) J27.B29(GND) J27.B32(GND) J31.2 J32.2 J36.8 R8.1 R9.1 R16.2 R23.2 R333.2 R338.2 R346.2 R401.1 R402.1 R413.1 R430.2 R437.1 R531.1 R541.1 R622.1 R623.1 U3.2(GND) U4.2(GND) U34.8(~{G}) U34.16(GND) U67.8(GND) U83.5(VSS) U88.3(GND) U99.2(GND) ; also on sheet 2 3 4 8 9 10 11 12 13 14 15 16 17 18 19 20 21 22 23 24 25 26 27 28 29 30 39 40
VCC_3V3_SYS: C147.1 C207.2 C410.2 C426.1 C435.1 C436.1 C470.2 FB1.1 J27.A9(+3.3V) J27.A10(+3.3V) J27.B8(+3.3V) R353.1 R354.1 R357.1 R358.1 R381.1 R382.1 R383.1 R384.1 R394.2 R395.2 R398.2 R399.2 R418.1 R419.1 R420.1 R421.1 R424.1 R431.1 R482.2 R486.2 R493.1 R516.1 R576.1 U34.1(VCC) U67.16(VCC) U83.8(VCC) U88.5(VCC) U99.5(VIN) ; also on sheet 2 8 10 11 12 13 14 15 16 17 18 19 20 21 23 24 25 26 27 29 30 39 40
VCC_5V0: FB2.1 ; also on sheet 4 17 18 20 25
VCC_CAN: C23.2 C24.2 FB2.2 U3.3(VCC) U4.3(VCC)
VCC_LCD: C474.1 J36.1 TP100.1(TP)
VDD_2V8: C463.2 J36.7 R538.1 ; also on sheet 16
VDDA_1V8_SERDES: R632.2 ; also on sheet 4
VDDA_ADC: C4.2 C7.2 J3.4 J3.17 ; also on sheet 4
VDDB_3V3_DISPLAY: C455.1 C462.2 J36.10 U99.1(VOUT)
ADC0_AIN0: J3.15 U23.G20(ADC0_AIN0)
ADC0_AIN1: J3.14 U23.F20(ADC0_AIN1)
ADC0_AIN2: J3.6 U23.E21(ADC0_AIN2)
ADC0_AIN3: J3.18 U23.D20(ADC0_AIN3)
ADC0_AIN4: J3.10 U23.G21(ADC0_AIN4)
ADC0_AIN5: J3.7 U23.F21(ADC0_AIN5)
ADC0_AIN6: J3.3 U23.F19(ADC0_AIN6)
ADC0_AIN7: J3.11 U23.E20(ADC0_AIN7)
C1N: C460.1 J36.11
C1P: C460.2 J36.12
C2N: C454.1 J36.13
C2P: C454.2 J36.14
CAN_MUX_OE: R23.1 U67.15(~{OE})
CAN_MUX_SEL: R16.1 U67.1(S) ; also on sheet 13
CLKGEN_REFCLK1N: R661.1 ; also on sheet 11
CLKGEN_REFCLK1P: R662.1 ; also on sheet 11
CLKGEN_REFCLK4N: R667.1 ; also on sheet 11
CLKGEN_REFCLK4P: R668.1 ; also on sheet 11
CLKOUT0: R345.2 ; also on sheet 11
DISPLAY_VDDB3V3_ON: R538.2 U99.4(ON)
GPIO1_43_INTn: U23.C13(SPI0_CS1) ; also on sheet 25
GPIO_OLED_RESETn: J36.6 R531.2 ; also on sheet 13
GPIO_PCIe_RST_OUT: R424.2 R430.1 U88.1(A) ; also on sheet 13
HSE_MCAN0_RX/UART4_TXD: U67.3(1B2) ; also on sheet 18
HSE_MCAN0_TX/UART4_RXD: U67.6(2B2) ; also on sheet 18
HSE_MCAN1_RX/I2C3_SDA: U67.10(3B2) ; also on sheet 18
HSE_MCAN1_TX/I2C3_SCL: U67.13(4B2) ; also on sheet 18
LED1: LD16.1(CATHODE) U34.3(DRAIN0)
LED2: LD17.1(CATHODE) U34.4(DRAIN1)
LED3: LD18.1(CATHODE) U34.5(DRAIN2)
LED4: LD19.1(CATHODE) U34.6(DRAIN3)
LED5: LD14.1(CATHODE) U34.11(DRAIN4)
LED6: LD13.1(CATHODE) U34.12(DRAIN5)
LED7: LD12.1(CATHODE) U34.13(DRAIN6)
LED8: LD11.1(CATHODE) U34.14(DRAIN7)
MCAN0_H: J31.1 R4.1 U4.7(CANH)
MCAN0_L: J31.3 R5.2 U4.6(CANL)
MCAN0_RX: J9.1 R220.1 U67.2(1B1)
MCAN0_RX/HSE: U23.B17(MCAN0_RX) U67.4(1A)
MCAN0_STB_3V3: R9.2 U4.8(STB) ; also on sheet 13
MCAN0_T: C2.1 R4.2 R5.1
MCAN0_TX: J9.2 R221.1 U67.5(2B1)
MCAN0_TX/HSE: U23.A17(MCAN0_TX) U67.7(2A)
MCAN1_H: J32.1 R2.1 U3.7(CANH)
MCAN1_L: J32.3 R3.2 U3.6(CANL)
MCAN1_RX: J10.1 R222.1 U67.11(3B1)
MCAN1_RX/HSE: U23.D17(MCAN1_RX) U67.9(3A)
MCAN1_STB_3V3: R8.2 U3.8(STB) ; also on sheet 13
MCAN1_T: C1.1 R2.2 R3.1
MCAN1_TX: J10.2 R223.1 U67.14(4B1)
MCAN1_TX/HSE: U23.C17(MCAN1_TX) U67.12(4A)
PCIe_CLKREQn: J27.B12(RSVD4) R482.1
PCIe_MCU_PORz: J34.3 R576.2 ; also on sheet 12
PCIe_PRSNT1#: J27.A1(PRSNT1#) J35.3 R437.2
PCIe_PRSNT2#_1: J27.B17(PRSNT2#_1) J35.2
PCIe_PRSNT2n: J35.1 R431.2
PCIE_RESET_OUTn: J34.1 U88.4(Y)
PCIe_RESETn: J27.A11(PERST#) J34.2
PCIE_SERDES_REFCLK0_N: J27.A14(REFCLK-) R665.1 R667.2
PCIE_SERDES_REFCLK0_P: J27.A13(REFCLK+) R666.1 R668.2
PCIe_TCK: J27.A5(JTAG2) TP85.1(TP)
PCIe_TDI: J27.A6(JTAG3) TP83.1(TP)
PCIe_TDO: J27.A7(JTAG4) TP95.1(TP)
PCIe_TMS: J27.A8(JTAG5) TP84.1(TP)
PCIe_TRSTn: J27.B9(JTAG1) TP94.1(TP)
PCIe_WAKEn: J27.B11(WAKE#) R486.1
RESETSTATz: U88.2(B) ; also on sheet 11 12 13 21 24 29
RSVD0: TP71.1(TP) U23.H16(RSVD0)
RSVD1: TP30.1(TP) U23.D21(RSVD1)
RSVD2: TP65.1(TP) U23.G13(RSVD2)
RSVD3: TP74.1(TP) U23.F17(RSVD3)
RSVD4: TP66.1(TP) U23.W15(RSVD4)
RSVD5: TP73.1(TP) U23.V16(RSVD5)
RSVD6: TP57.1(TP) U23.K2(RSVD6)
RSVD7: TP13.1(TP) U23.K1(RSVD7)
RSVD8: TP75.1(TP) U23.F12(RSVD8)
SERDES0_REXT: R338.1 U23.T13(SERDES0_REXT)
SERDES_REFCLK0_N: R622.2 R624.2 R665.2 R680.1
SERDES_REFCLK0_N_C: R333.1 R661.2 R680.2 U23.W16(SERDES0_REFCLK0N)
SERDES_REFCLK0_P: R623.2 R625.2 R666.2 R679.1
SERDES_REFCLK0_P_C: R346.1 R662.2 R679.2 U23.W17(SERDES0_REFCLK0P)
SERDES_RXN0: J27.A17(PERn0) U23.Y15(SERDES0_RX0_N)
SERDES_RXP0: J27.A16(PERp0) U23.Y16(SERDES0_RX0_P)
SERDES_TXN0: C100.1 J27.B15(PETn0)
SERDES_TXN0_C: C100.2 U23.AA16(SERDES0_TX0_N)
SERDES_TXP0: C102.1 J27.B14(PETp0)
SERDES_TXP0_C: C102.2 U23.AA17(SERDES0_TX0_P)
SoC_I2C0_SCL: R358.2 R598.1 ; also on sheet 10 13 18
SoC_I2C0_SCL_RC: C492.1 R598.2 U23.A18(I2C0_SCL)
SoC_I2C0_SDA: R354.2 R599.1 ; also on sheet 10 13 18
SoC_I2C0_SDA_RC: C493.1 R599.2 U23.B18(I2C0_SDA)
SoC_I2C1_SCL: J27.B5(SMCLK) J36.5 R353.2 U23.C18(I2C1_SCL) U34.15(SCL) ; also on sheet 10 11 13 14 30
SoC_I2C1_SDA: J27.B6(SMDAT) J36.4 R357.2 U23.B19(I2C1_SDA) U34.2(SDA) ; also on sheet 10 11 13 14 30
SOC_MAIN_UART0_CTS_3V3: U23.B16(UART0_CTSN) ; also on sheet 23
SOC_MAIN_UART0_RTS_3V3: U23.A16(UART0_RTSN) ; also on sheet 23
SOC_MAIN_UART0_RX_3V3: U23.D15(UART0_RXD) ; also on sheet 23
SOC_MAIN_UART0_TX_3V3: U23.C16(UART0_TXD) ; also on sheet 23
SOC_MAIN_UART1_RX_3V3: U23.E15(UART1_RXD) ; also on sheet 23
SOC_MAIN_UART1_TX_3V3: U23.E14(UART1_TXD) ; also on sheet 23
SOC_MAIN_UART3_RX_3V3: U23.D16(UART1_CTSN) ; also on sheet 23
SOC_MAIN_UART3_TX_3V3: U23.E16(UART1_RTSN) ; also on sheet 23
SOC_SPI0_CLK: R395.1 TP77.1(TP) U23.D13(SPI0_CLK) U83.2(CLK)
SOC_SPI0_CS0: R399.1 TP80.1(TP) U23.D12(SPI0_CS0) U83.1(CS)
SOC_SPI0_MISO: R398.1 TP79.1(TP) U23.A14(SPI0_D1) U83.4(DO)
SOC_SPI0_MOSI: R394.1 TP76.1(TP) U23.A13(SPI0_D0) U83.3(DI)
SOC_SPI1_CLK: U23.C14(SPI1_CLK) ; also on sheet 18
SOC_SPI1_CS0: U23.B14(SPI1_CS0) ; also on sheet 18
SOC_SPI1_CS1: U23.D14(SPI1_CS1) ; also on sheet 18
SOC_SPI1_MISO: U23.A15(SPI1_D1) ; also on sheet 18
SOC_SPI1_MOSI: U23.B15(SPI1_D0) ; also on sheet 18
SYNC1_OUT_TP: J12.1 U23.D18(ECAP0_IN_APWM_OUT)
VCOMH: C473.1 J36.2
VIO_CAN: C3.1 C8.1 FB1.2 U3.5(VIO) U4.5(VIO)
VMAIN: C431.1 C432.1 C448.1 C449.1 C450.1 J27.A2(+12V) J27.A3(+12V) J27.B1(+12V) J27.B2(+12V) J27.B3(+12V) ; also on sheet 4 8 16 17
N17247526: LD16.2(ANODE) R421.2
N17247539: LD17.2(ANODE) R420.2
N17247599: LD18.2(ANODE) R419.2
N17247637: LD19.2(ANODE) R418.2
N17247662: LD14.2(ANODE) R381.2
N17247701: LD13.2(ANODE) R382.2
N17247743: LD12.2(ANODE) R383.2
N17247786: LD11.2(ANODE) R384.2
N17248427: R413.2 U34.7(A2)
N17248432: R402.2 U34.10(A1)
N17248439: R401.2 U34.9(A0)
N25657961: J36.3 R541.2
N25658118: R516.2 U99.3(OC)
N26118637: R221.2 U4.1(TXD)
N26118639: R220.2 U4.4(RXD)
N26120249: R223.2 U3.1(TXD)
N26120251: R222.2 U3.4(RXD)
N28887698: R624.1 R625.1 R632.1
N29650235: R345.1 U23.A19(EXT_REFCLK1)

Not connected (* = marked no-connect by the designer): J3 2* 19*; J27 A19(RSVD1)* A21(PERp1)* A22(PERn1)* A25(PERp2)* A26(PERn2)* A29(PERp3)* A30(PERn3)* A32(RSVD2)* B19(PETp1)* B20(PETn1)* B23(PETp2)* B24(PETn2)* B27(PETp3)* B28(PETn3)* B30(RSVD3)* B31(PRSNT2#_2)*; J36 9*; U83 6(NC1)* 7(NC2)*

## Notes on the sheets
sheet 5
- x4 Lane PCIe Connector
- Note:
  R679 , R680 Mounted with 0E Resistor when PCIe REFCLK is in no Re-biasing Mode.
  R679 , R680 to be replaced with 100nf CAP 0402 package when PCIe REFCLK is in
  Re-biasing Mode.
- CAD Note:
  Place Close to SoC
- PCIe Reset
- CLOCK SELECTION
- CAD Note:
  Place Close to SoC
- CAD Note:
  Place Close to PCIe CON
- RC OR EP MODE SELECTION
- Off Page Connections
- Short 1 and  2 in J34& J35 for Host operation
  Short 3 and  2 in J34& J35 for Device operation
sheet 6
- HSE/CAN MUX
- LPF Designed for 25MHz Cutoff
  Have to change resistor and capacitor values accordingly
- CAN INTERFACE
- DISPLAY
- DISPLAY CONNECTOR
- 120E
- 16V CAP
- 120E
- Off Page Connections
- SPI EEPROM
- From Debounce Circuit
- From IO Expander
- To HSE Connector
- EEPROM
- To Clock Buffer
- To FT4232 Bridge
sheet 7
- ETHERNET LED's
- Placement of the Industrial Ethernet LED's to be changed.
  To be moved closer to the ICSS ETH PHY's
- I2C ADDRESS: 0x60
- ADC CONNECTOR
- Off Page Connections
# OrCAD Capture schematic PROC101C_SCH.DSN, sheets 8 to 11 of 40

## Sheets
8 36. MAIN INPUT 12V DC: size C; title: MAIN 12V POWERSUPPLY
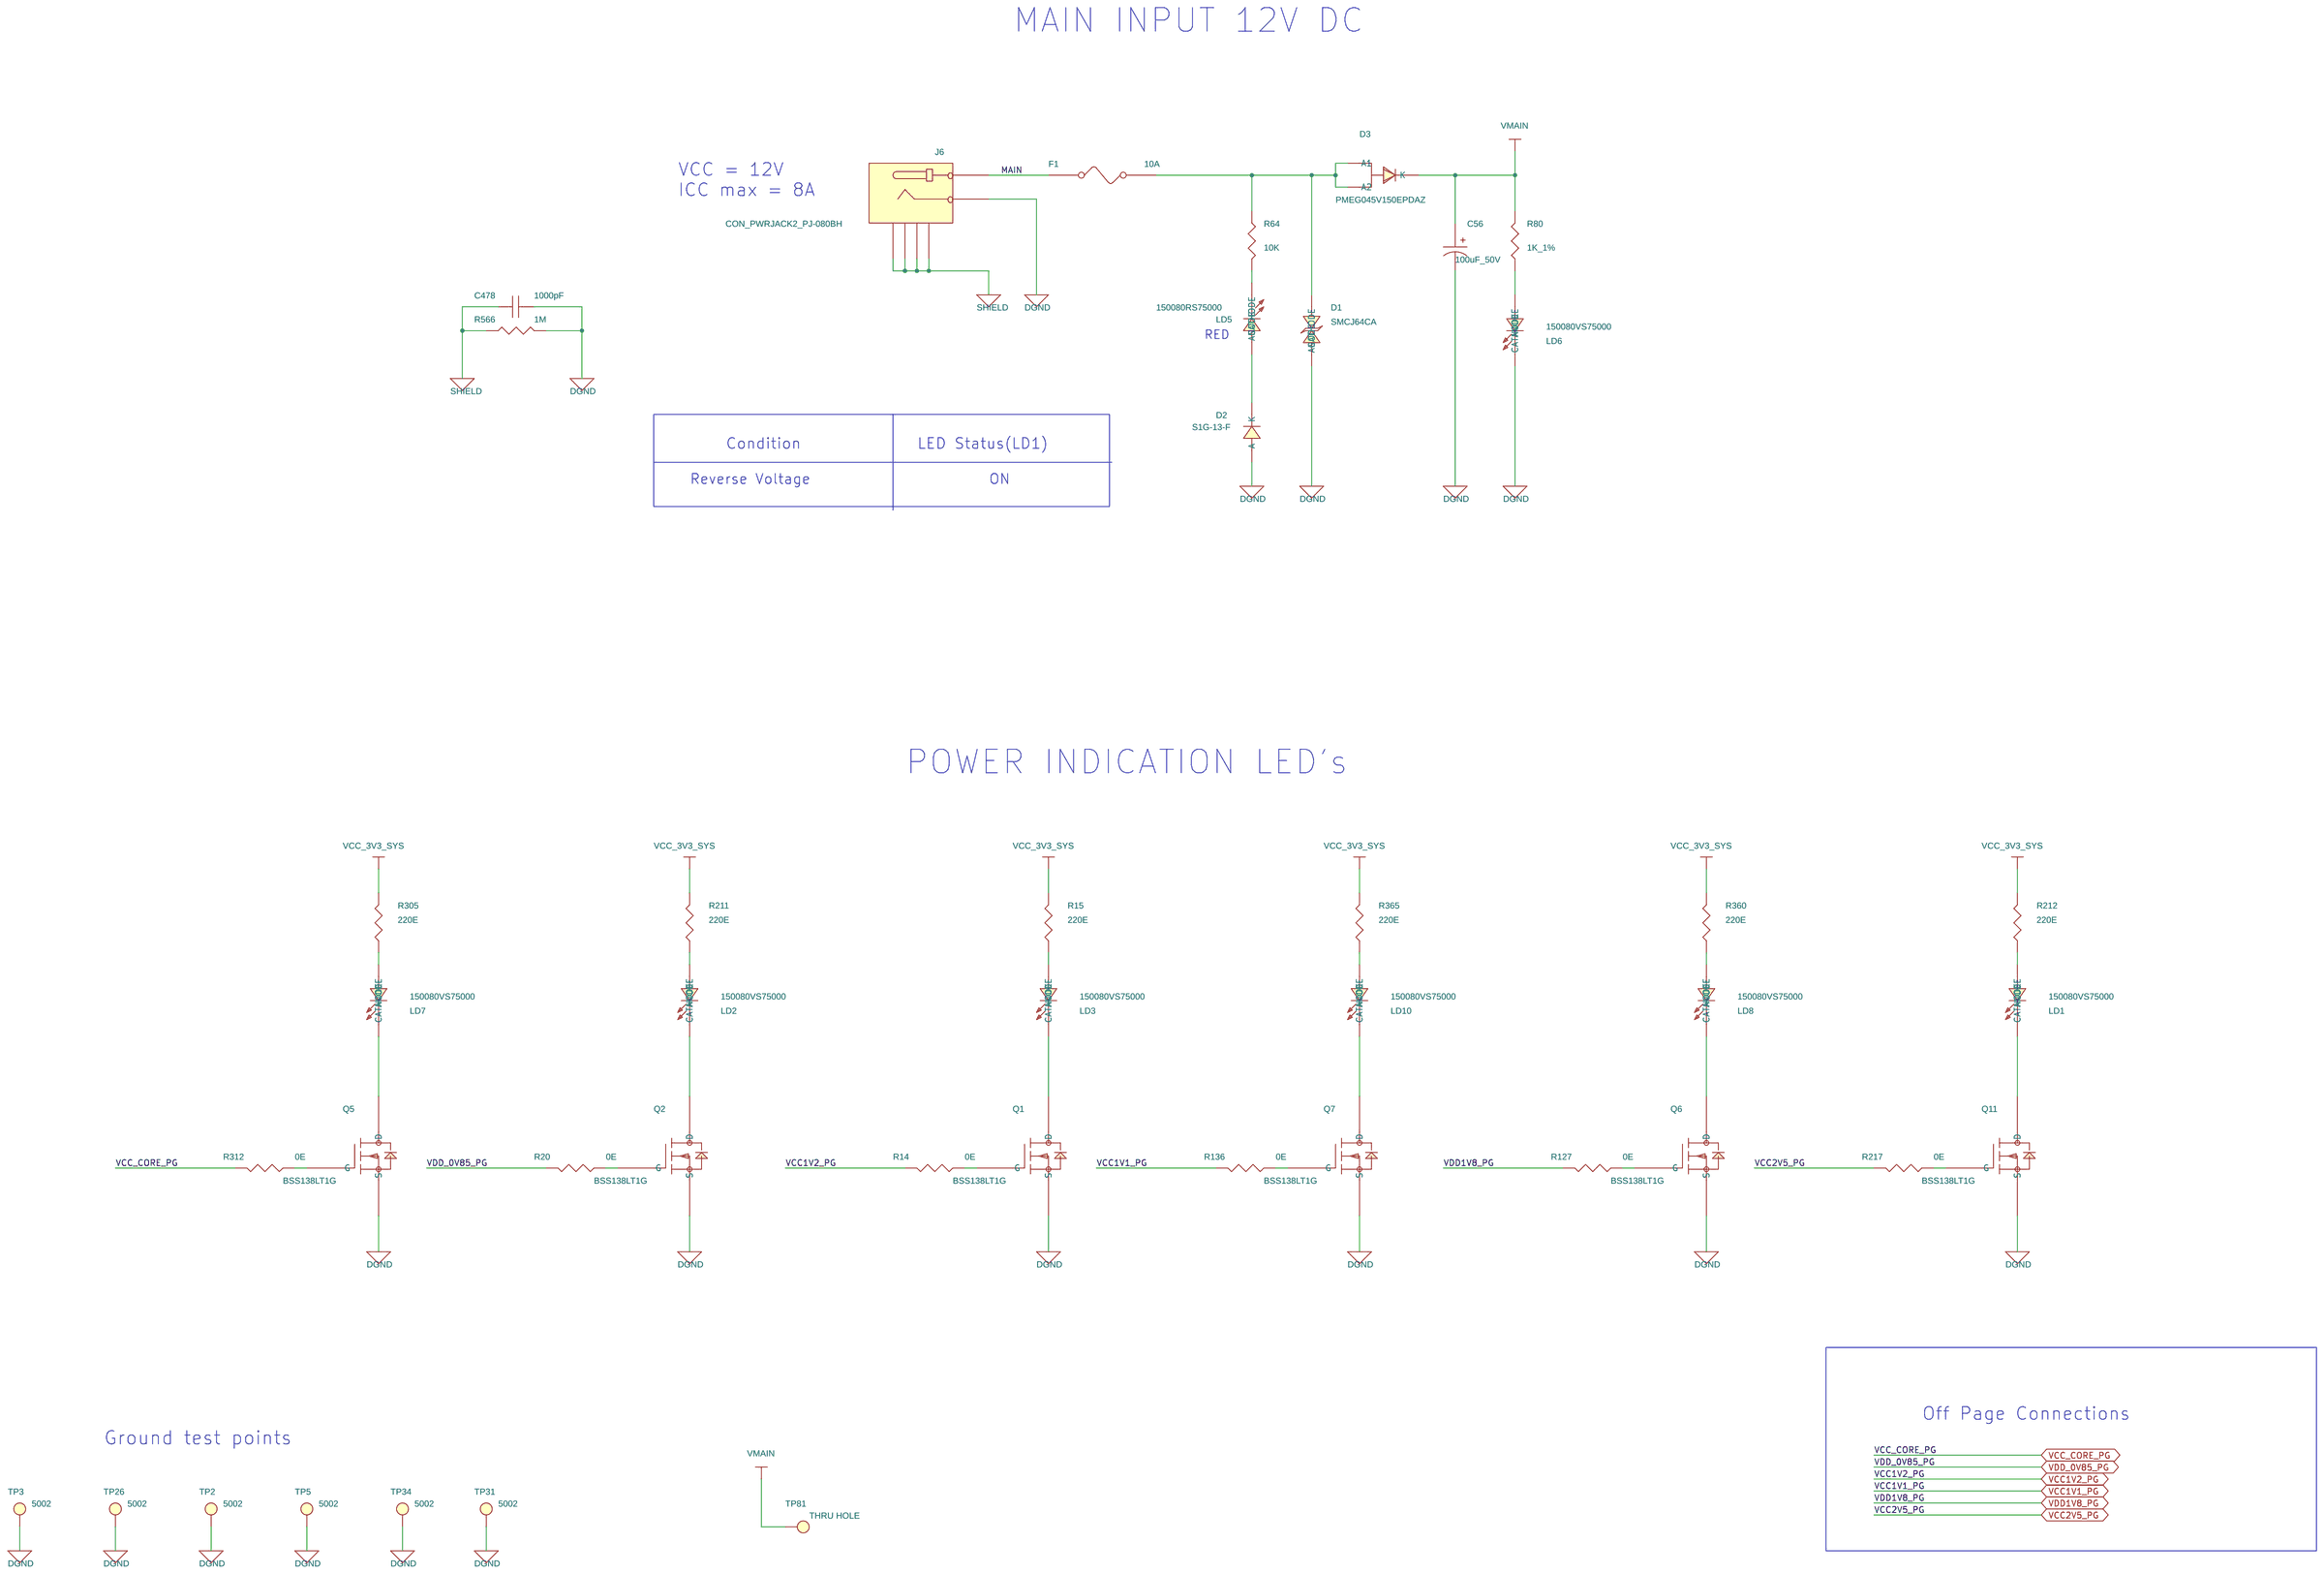
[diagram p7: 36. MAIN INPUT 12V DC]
9 11.SOC VSS: size C; title: SOC VSS
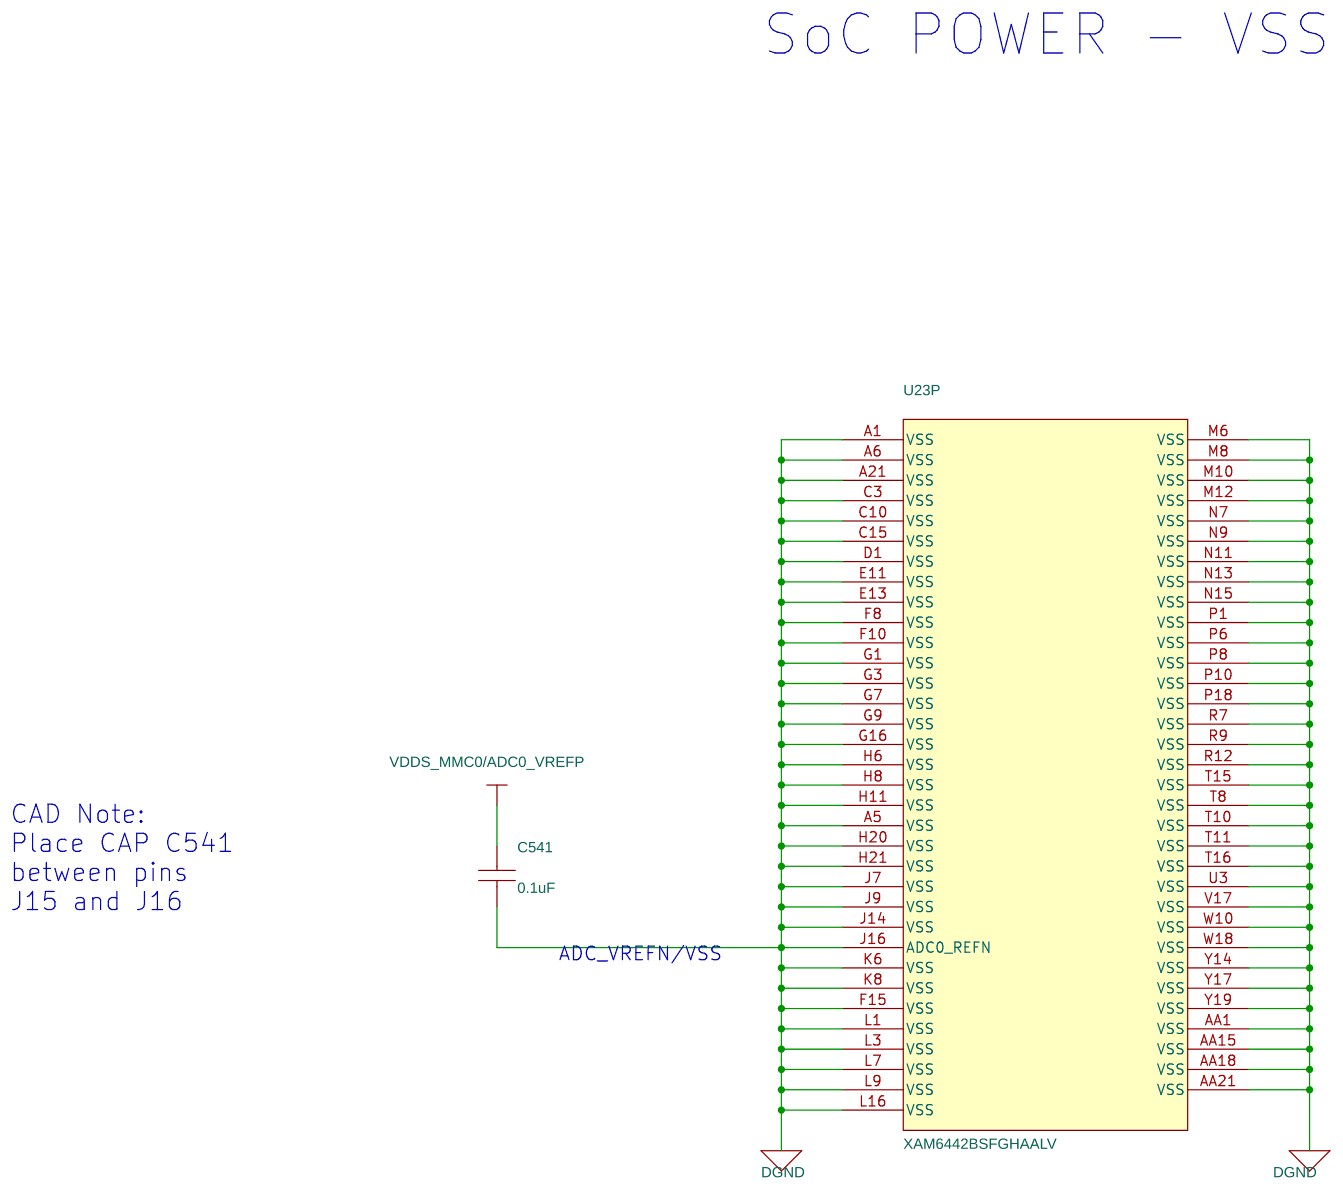
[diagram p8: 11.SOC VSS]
10 15.EEPROM,PRESENCE DETECT&TEMP: size C; title: EEPROM,PRESENCE DETECTION & TEMP SENSOR
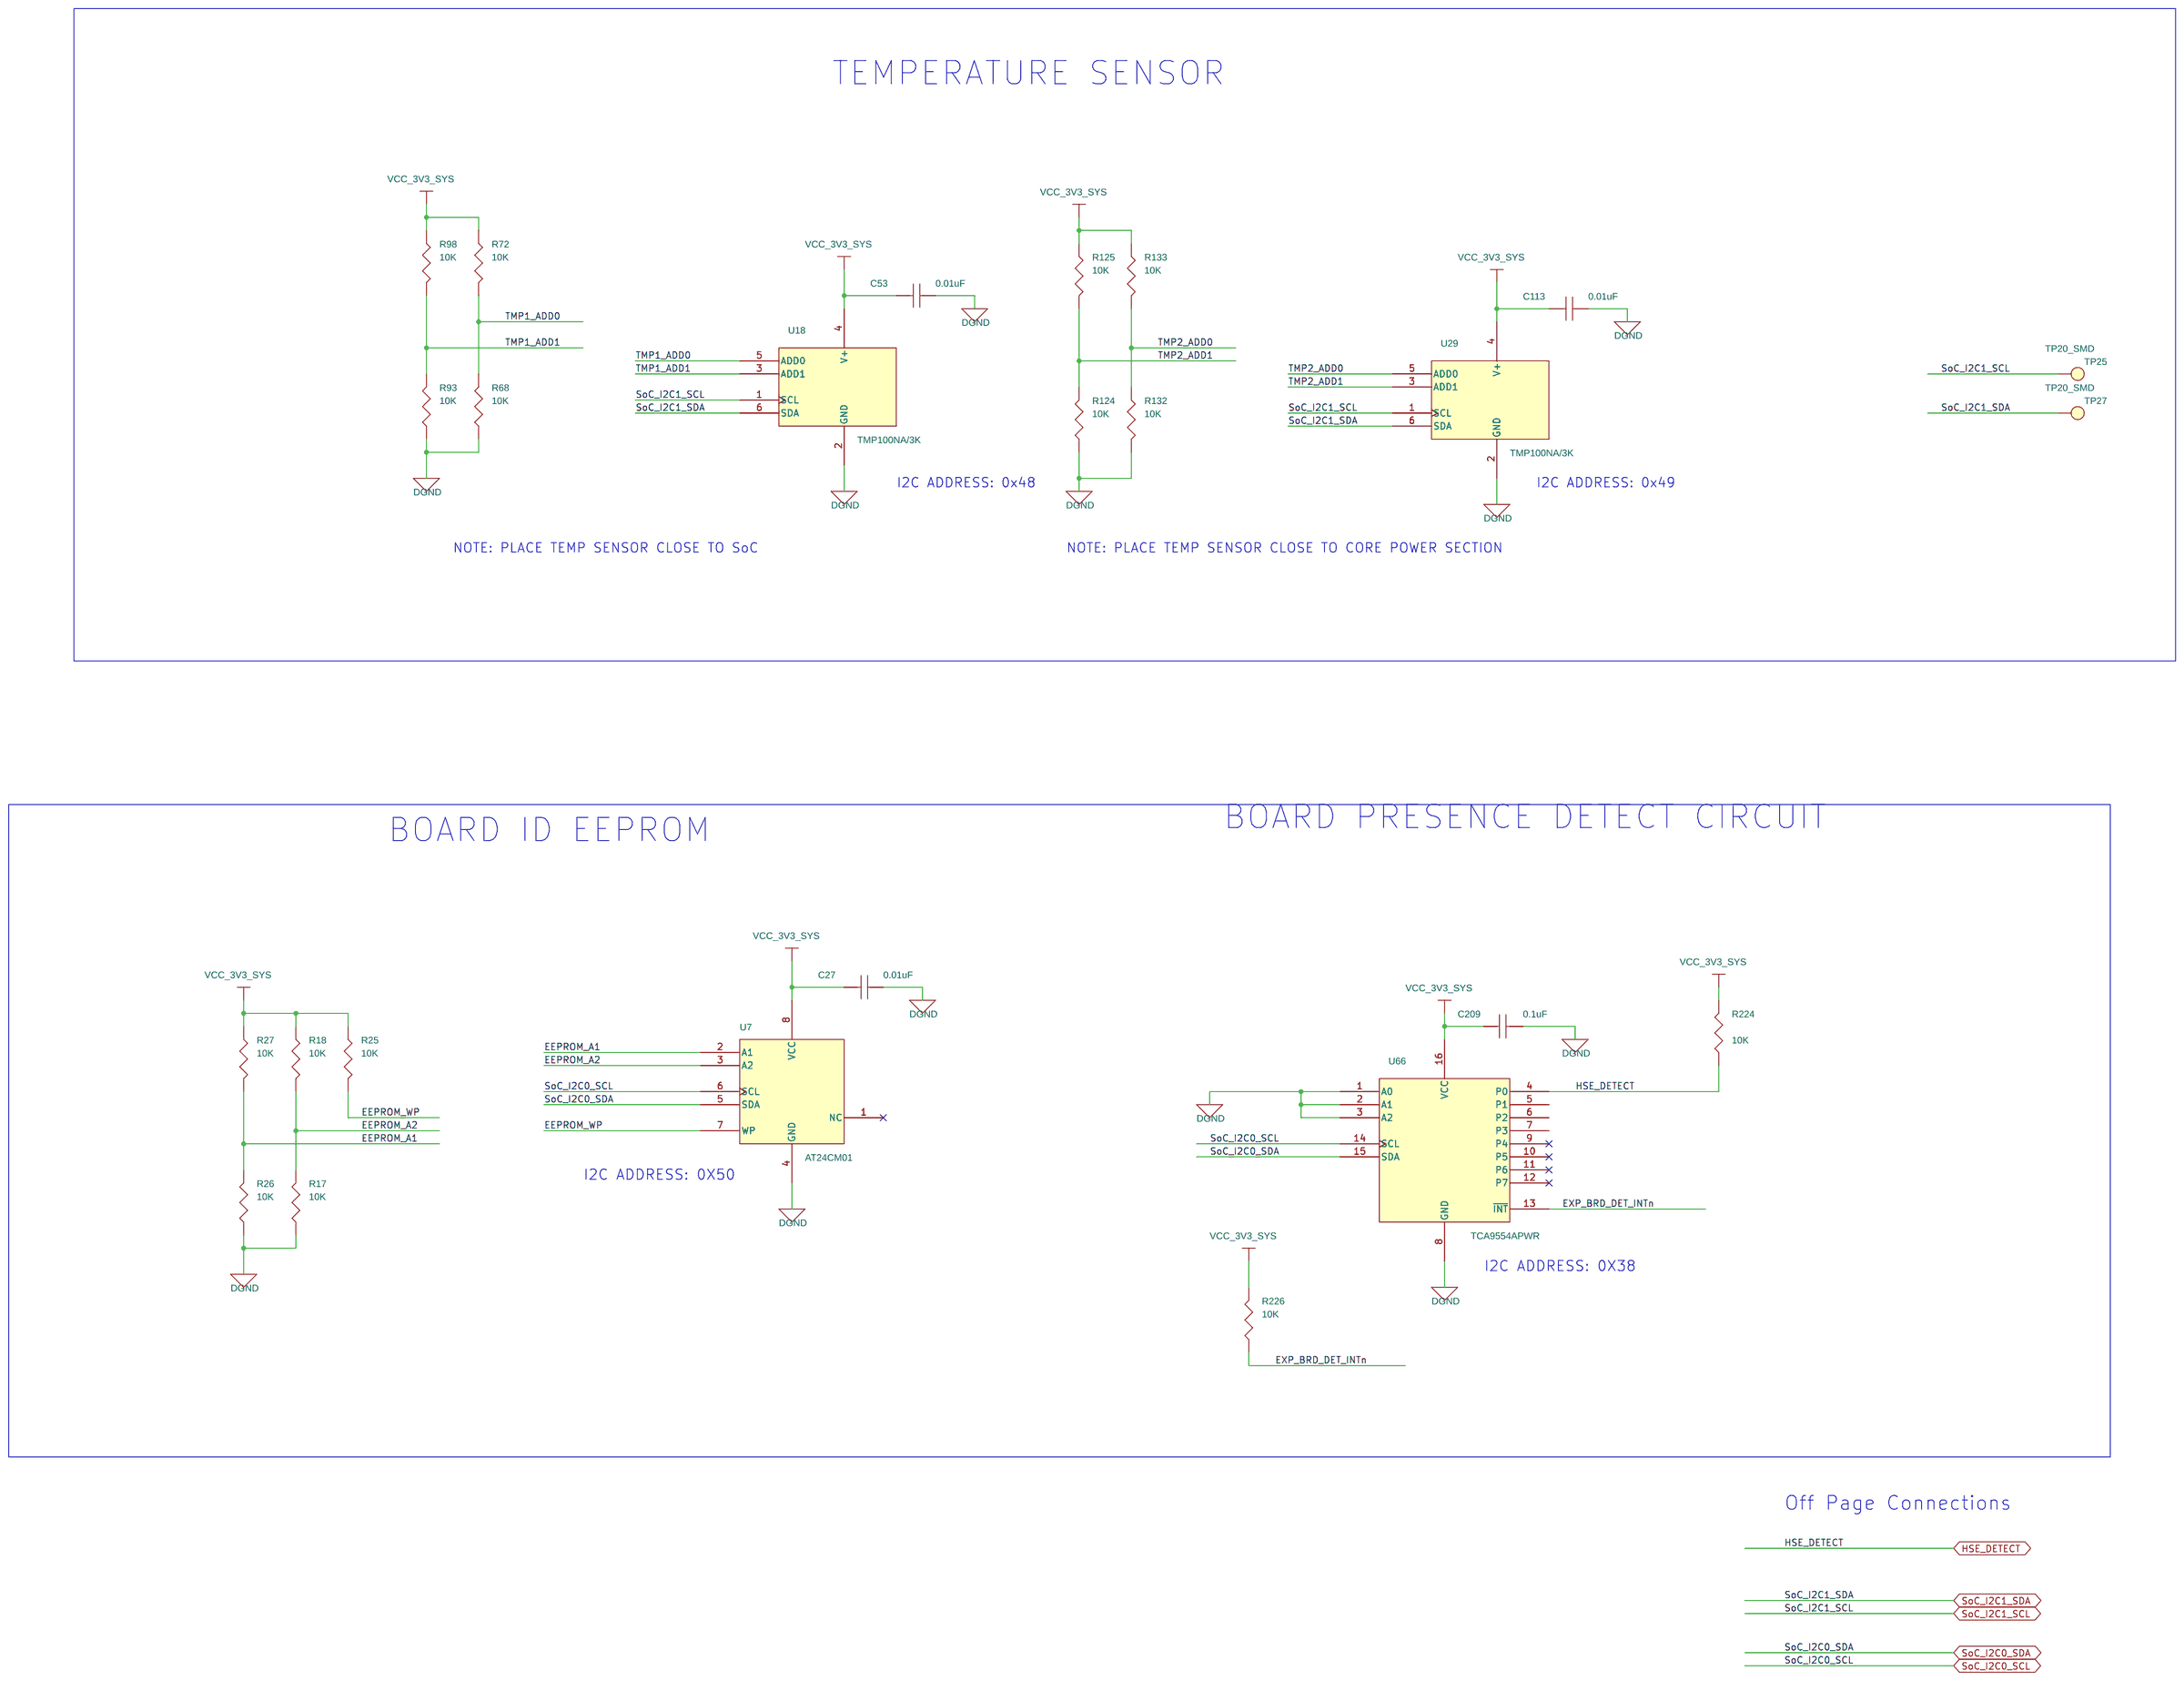
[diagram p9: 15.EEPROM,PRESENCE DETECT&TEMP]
11 31.ETHERNET & PCIe CLOCK BUFFER: size C; title: ETHERNET PHY & PCIe CLOCK GENERATOR

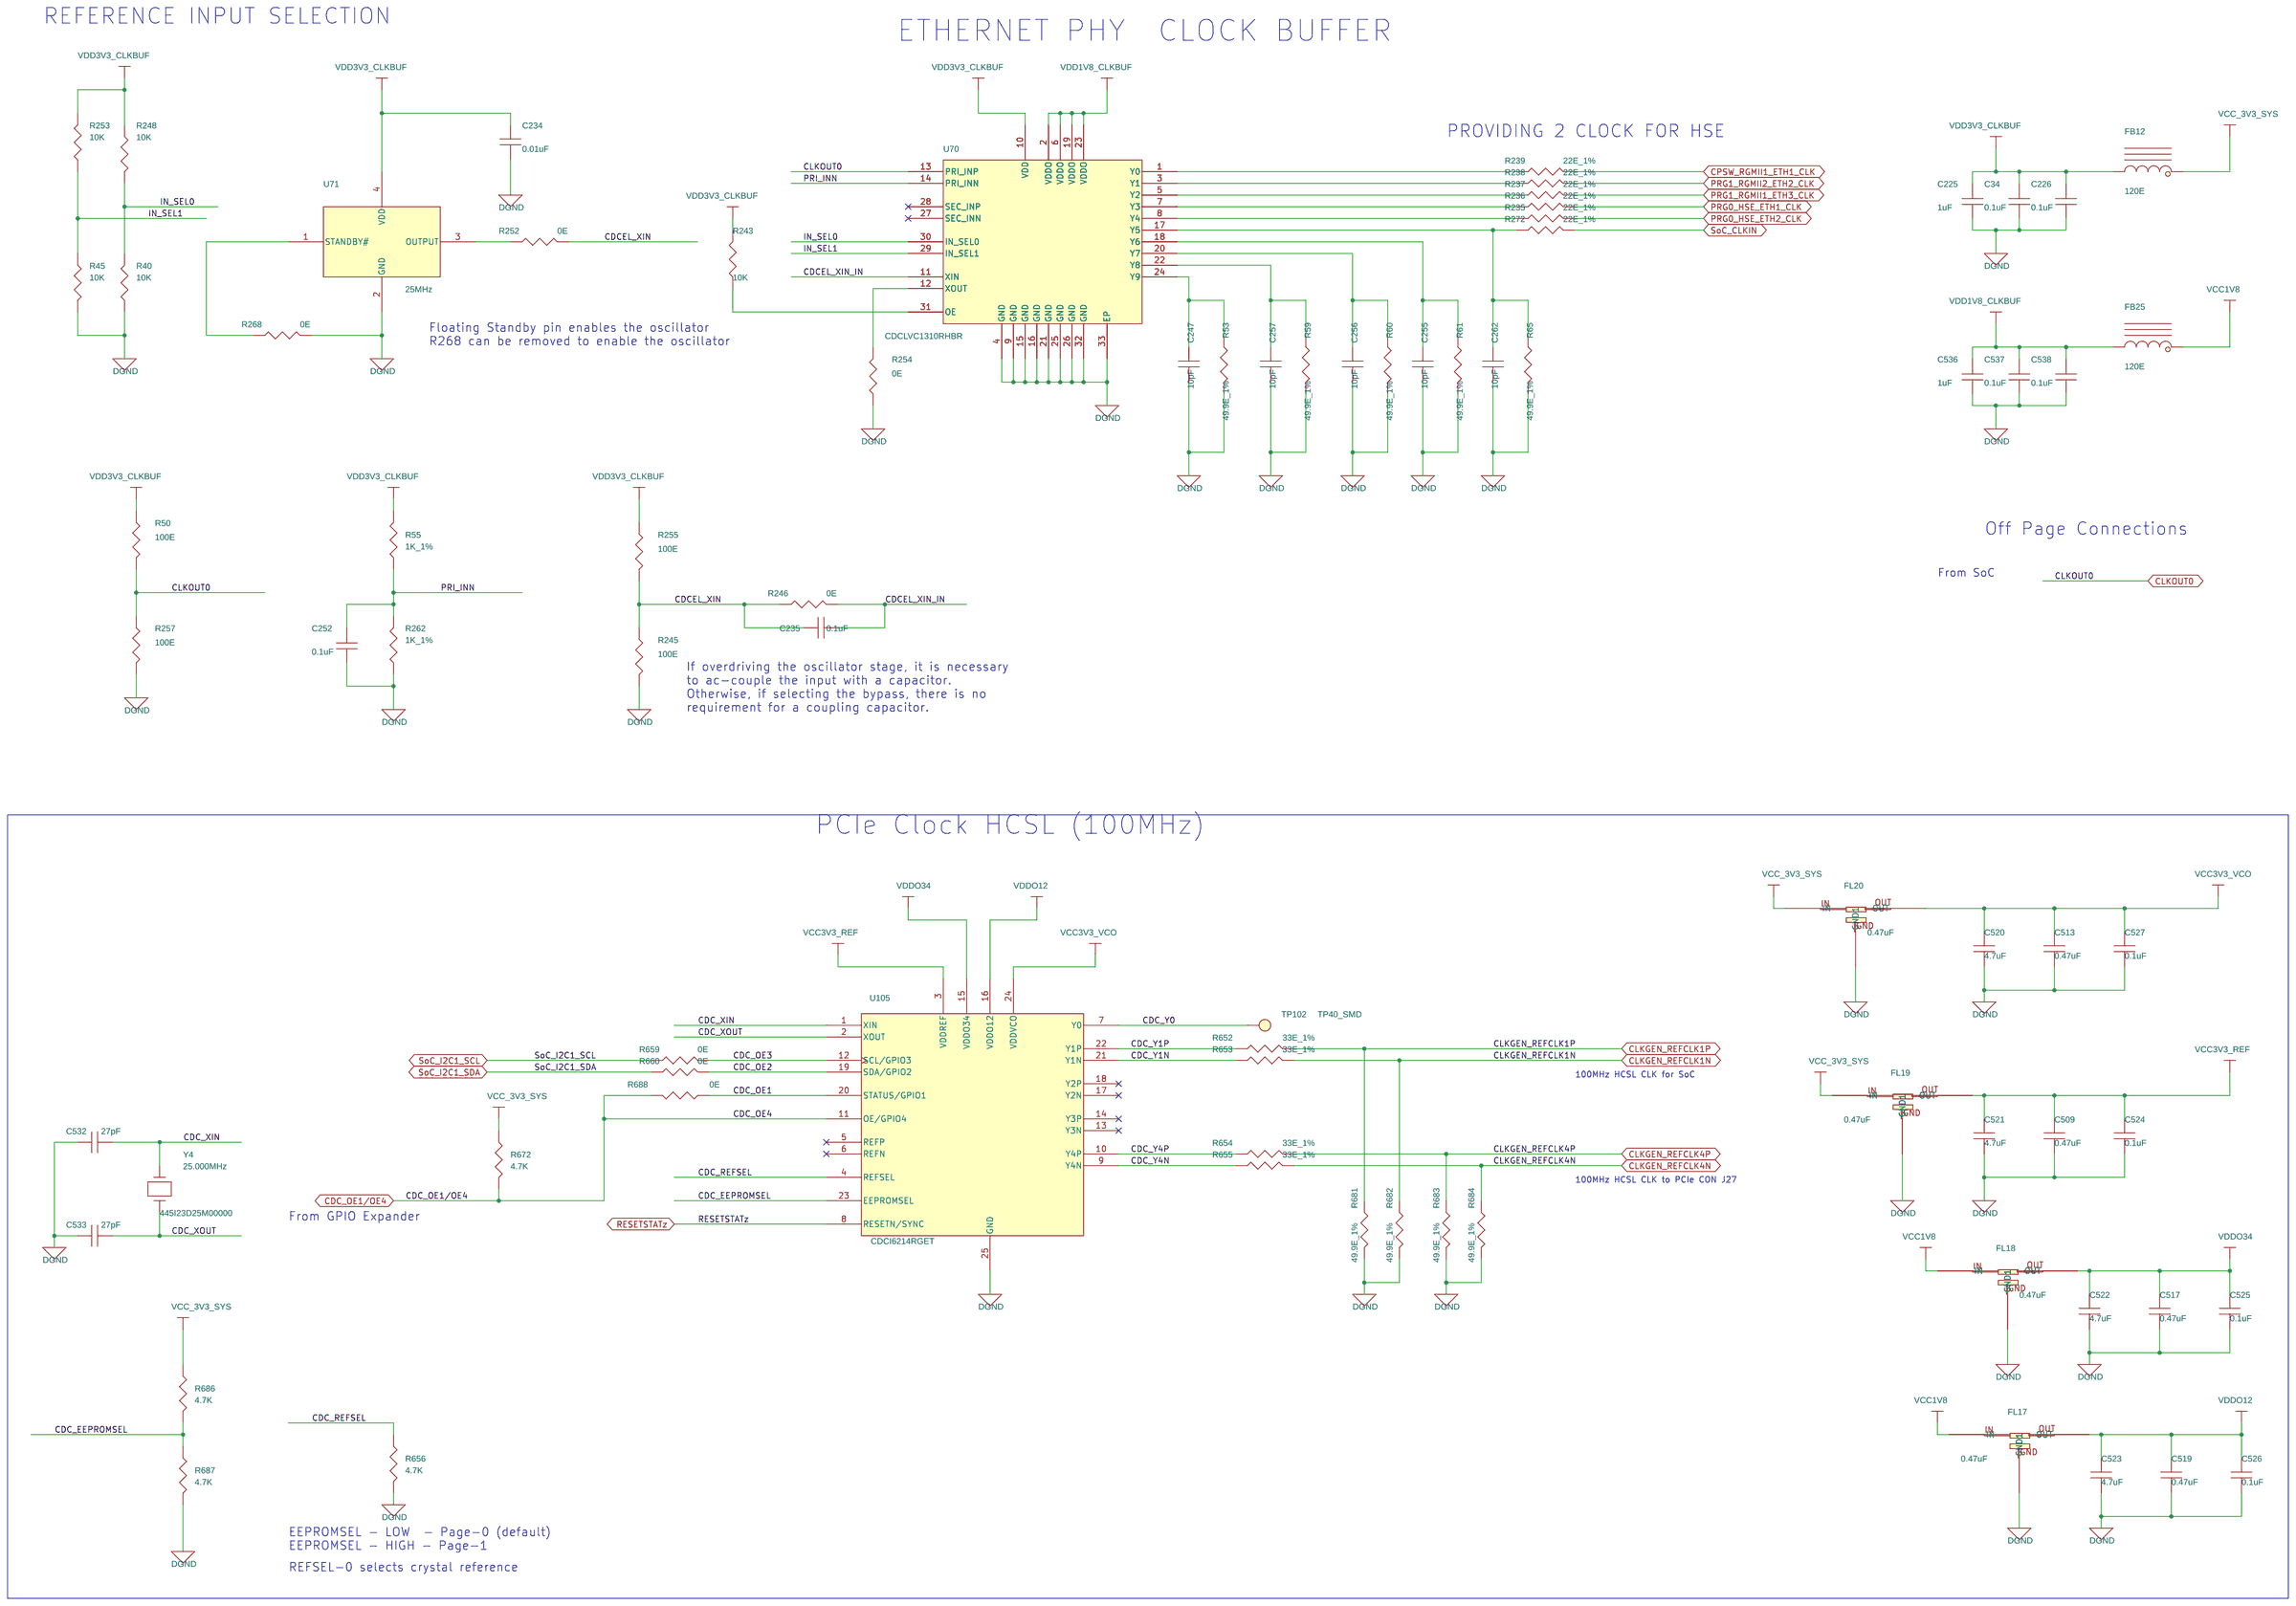
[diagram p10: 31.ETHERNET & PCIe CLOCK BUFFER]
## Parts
sheet 11.SOC VSS
C541  0.1uF  [CAP0201_0-5]
sheet 15.EEPROM,PRESENCE DETECT&TEMP
C27  0.01uF  [CAP0402_0-75]
C53  0.01uF  [CAP0402_0-75]
C113  0.01uF  [CAP0402_0-75]
C209  0.1uF  [CAP0402_0-75]
R17  10K  [RES0402_0-5]
R18  10K  [RES0402_0-5]
R25  10K  [RES0402_0-5]
R26  10K  [RES0402_0-5]
R27  10K  [RES0402_0-5]
R68  10K  [RES0402_0-5]
R72  10K  [RES0402_0-5]
R93  10K  [RES0402_0-5]
R98  10K  [RES0402_0-5]
R124  10K  [RES0402_0-5]
R125  10K  [RES0402_0-5]
R132  10K  [RES0402_0-5]
R133  10K  [RES0402_0-5]
R224  10K  [RES0402_0-5]
R226  10K  [RES0402_0-5]
TP25  TP20_SMD  [TP20_SMD]
TP27  TP20_SMD  [TP20_SMD]
U7  AT24CM01  [TSSOP8_25-59_125X180_1-2]
U18  TMP100NA/3K  [SOT23-6_1-5]
U29  TMP100NA/3K  [SOT23-6_1-5]
U66  TCA9554APWR  [TSSOP16_25-59_205X180_1-2]
sheet 28.GPMC & FSI CONNECTOR
U23  XAM6442BSFGHAALV  [FCBGA441_31-49_680X680_2-6]  (sections A,B,C,D,E,F,G,H,I,J,K,L,M,N,O,P)
sheet 31.ETHERNET & PCIe CLOCK BUFFER
C34  0.1uF  [CAP0402_0-75]
C225  1uF  [CAP0402_0-75]
C226  0.1uF  [CAP0402_0-75]
C234  0.01uF  [CAP0201_0-5]
C235  0.1uF  [CAP0402_0-75]
C247  10pF  [CAP0402_0-75]
C252  0.1uF  [CAP0402_0-75]
C255  10pF  [CAP0402_0-75]
C256  10pF  [CAP0402_0-75]
C257  10pF  [CAP0402_0-75]
C262  10pF  [CAP0402_0-75]
C509  0.47uF  [CAP0402_0-75]
C513  0.47uF  [CAP0402_0-75]
C517  0.47uF  [CAP0402_0-75]
C519  0.47uF  [CAP0402_0-75]
C520  4.7uF  [CAP0402_0-75]
C521  4.7uF  [CAP0402_0-75]
C522  4.7uF  [CAP0402_0-75]
C523  4.7uF  [CAP0402_0-75]
C524  0.1uF  [CAP0402_0-75]
C525  0.1uF  [CAP0402_0-75]
C526  0.1uF  [CAP0402_0-75]
C527  0.1uF  [CAP0402_0-75]
C532  27pF  [CAP0402_0-75]
C533  27pF  [CAP0402_0-75]
C536  1uF  [CAP0402_0-75]
C537  0.1uF  [CAP0402_0-75]
C538  0.1uF  [CAP0402_0-75]
FB12  120E  [IND0603_1]
FB25  120E  [IND0603_1]
FL17  0.47uF  [EMIFIL_NFM21P_0805]
FL18  0.47uF  [EMIFIL_NFM21P_0805]
FL19  0.47uF  [EMIFIL_NFM21P_0805]
FL20  0.47uF  [EMIFIL_NFM21P_0805]
R40  10K  [RES0402_0-5]
R45  10K  [RES0402_0-5]
R50  100E  [RES0402_0-5]
R53  49.9E_1%  [RES0402_0-5]
R55  1K_1%  [RES0402_0-5]
R59  49.9E_1%  [RES0402_0-5]
R60  49.9E_1%  [RES0402_0-5]
R61  49.9E_1%  [RES0402_0-5]
R65  49.9E_1%  [RES0402_0-5]
R235  22E_1%  [RES0402_0-5]
R236  22E_1%  [RES0402_0-5]
R237  22E_1%  [RES0402_0-5]
R238  22E_1%  [RES0402_0-5]
R239  22E_1%  [RES0402_0-5]
R243  10K  [RES0402_0-5]
R245  100E  [RES0402_0-5]
R246  0E  [RES0402_0-5]
R248  10K  [RES0402_0-5]
R252  0E  [RES0402_0-5]
R253  10K  [RES0402_0-5]
R254  0E  [RES0402_0-5]
R255  100E  [RES0402_0-5]
R257  100E  [RES0402_0-5]
R262  1K_1%  [RES0402_0-5]
R268  0E  [RES0402_0-5]
R272  22E_1%  [RES0402_0-5]
R652  33E_1%  [RES0402_0-5]
R653  33E_1%  [RES0402_0-5]
R654  33E_1%  [RES0402_0-5]
R655  33E_1%  [RES0402_0-5]
R656  4.7K  [RES0402_0-5]
R659  0E  [RES0402_0-5]
R660  0E  [RES0402_0-5]
R672  4.7K  [RES0402_0-5]
R681  49.9E_1%  [RES0402_0-5]
R682  49.9E_1%  [RES0402_0-5]
R683  49.9E_1%  [RES0402_0-5]
R684  49.9E_1%  [RES0402_0-5]
R686  4.7K  [RES0402_0-5]
R687  4.7K  [RES0402_0-5]
R688  0E  [RES0402_0-5]
TP102  TP40_SMD  [TP40_SMD]
U70  CDCLVC1310RHBR  [QFN32_19-68_200X200_1]
U71  25MHz  [OSC4_ASFLMB_200X130_SMD]
U105  CDCI6214RGET  [QFN24_19-68_160X160_1]
Y4  25.000MHz  [XTAL_ABM3_205X130_SMD_1-4]
sheet 36. MAIN INPUT 12V DC
C56  100uF_50V  [CAPAE_D8CASE_8]
C478  1000pF  [CAP1206_1-75]
D1  SMCJ64CA  [DIO_SMC]
D2  S1G-13-F  [DIO_SMA]
D3  PMEG045V150EPDAZ  [CFP15_PMEG045V150EPD_0-9]
F1  10A  [FUSE_397_410X110_SMD_2-9]
J6  CON_PWRJACK2_PJ-080BH  [CON_PWRJACK2_PJ-080BH_P_R_T_13-4]
LD1  150080VS75000  [LED_150080VS75000_80X50_SMD_0-8]
LD2  150080VS75000  [LED_150080VS75000_80X50_SMD_0-8]
LD3  150080VS75000  [LED_150080VS75000_80X50_SMD_0-8]
LD5  150080RS75000  [LED_150080VS75000_80X50_SMD_0-8]
LD6  150080VS75000  [LED_150080VS75000_80X50_SMD_0-8]
LD7  150080VS75000  [LED_150080VS75000_80X50_SMD_0-8]
LD8  150080VS75000  [LED_150080VS75000_80X50_SMD_0-8]
LD10  150080VS75000  [LED_150080VS75000_80X50_SMD_0-8]
Q1  BSS138LT1G  [SOT23-123_1-2]
Q2  BSS138LT1G  [SOT23-123_1-2]
Q5  BSS138LT1G  [SOT23-123_1-2]
Q6  BSS138LT1G  [SOT23-123_1-2]
Q7  BSS138LT1G  [SOT23-123_1-2]
Q11  BSS138LT1G  [SOT23-123_1-2]
R14  0E  [RES0402_0-5]
R15  220E  [RES0402_0-5]
R20  0E  [RES0402_0-5]
R64  10K  [RES1206_0-75]
R80  1K_1%  [RES0402_0-5]
R127  0E  [RES0402_0-5]
R136  0E  [RES0402_0-5]
R211  220E  [RES0402_0-5]
R212  220E  [RES0402_0-5]
R217  0E  [RES0402_0-5]
R305  220E  [RES0402_0-5]
R312  0E  [RES0402_0-5]
R360  220E  [RES0402_0-5]
R365  220E  [RES0402_0-5]
R566  1M  [RES0603_0-75]
TP2  5002  [TP_CIR67D40_TH_4-6]
TP3  5002  [TP_CIR67D40_TH_4-6]
TP5  5002  [TP_CIR67D40_TH_4-6]
TP26  5002  [TP_CIR67D40_TH_4-6]
TP31  5002  [TP_CIR67D40_TH_4-6]
TP34  5002  [TP_CIR67D40_TH_4-6]
TP81  THRU HOLE  [TP_40X65]

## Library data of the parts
C541 = CAP: CAP CERAMIC 0.1uF 16V 10% X5R 0201; Chkd/date: MANIRAJA/120218; Crtd /date: MANIRAJA/120218; Custom_Duty: 15%; Customs_HS_Code: 85322990; Distributor_name: DIGIKEY; Distributor_part_number: 490-16742-1-ND; Footprint Path: Y:\MIS_DATABASE\Library\ALTIUM_TOOL\PCB_FOOTPRINTS\Altium_Footprint_Lib.PcbLib; Height: 0.33MM; Library Path: Y:\MIS_DATABASE\Library\ALTIUM_TOOL\SCHEMATICS_PARTS\MS_DISCRETE_Library.schlib; Mfr_name: MURATA; Mfr_part_number: GRM033R61C104KE84J; Mistral Part No: 120009030072-R; Package: 0201; Part_type: CAPACITORS\CERAMIC; Project: TI_MAXIE_CPB; RoHS: RoHS; Temperature: -55°C+85°C; Tolerance: 10%; Voltage: 16V; Wattage: NA; Weight: 0.33mg; Datasheet: Y:\MIS_DATABASE\DATASHEETS\CAPACITORS\GRM033R61C104KE84.PDF
C27 C53 C113 = CAP: CAP CERAMIC 0.01uF 25V 10% X7R 0402; Chkd/date: MANIRAJA/170820; Crtd /date: ALVY/170820; Custom_Duty: 15%; Customs_HS_Code: 85322990; Distributor_name: DIGIKEY; Distributor_part_number: 732-7545-1-ND; Footprint Path: Y:\MIS_DATABASE\Library\ALTIUM_TOOL\PCB_FOOTPRINTS\Altium_Footprint_Lib.PcbLib; Height: 0.55MM; Library Path: Y:\MIS_DATABASE\Library\ALTIUM_TOOL\SCHEMATICS_PARTS\MS_DISCRETE_Library.schlib; Mfr_name: WURTH ELECTRONICS; Mfr_part_number: 885012205050; Mistral Part No: 120011090040-R; Package: 0402; Part_type: CAPACITORS\CERAMIC; Project: AM64x_EVM_BRD; RoHS: RoHS; Temperature: -55°C+125°C; Tolerance: 10%; Voltage: 25V; Wattage: NA; Weight: 0.65mg; Datasheet: Y:\MIS_DATABASE\DATASHEETS\CAPACITORS\885012205050.PDF
C34 C209 C226 C235 C252 C524-C527 C537 C538 = CAP: CAP CERAMIC 0.1uF 25V 20% X5R 0402; Alt_Mfr_name: YAGEO AMERICA; Alt_Mfr_part_number: CC0402KRX5R8BB104; Chkd/date: MANIRAJA/170820; Crtd /date: ALVY/170820; Custom_Duty: 15%; Customs_HS_Code: 85322990; Distributor_name: DIGIKEY; Distributor_part_number: 732-7495-1-ND; Footprint Path: Y:\MIS_DATABASE\Library\ALTIUM_TOOL\PCB_FOOTPRINTS\Altium_Footprint_Lib.PcbLib; Height: 0.55MM; Library Path: Y:\MIS_DATABASE\Library\ALTIUM_TOOL\SCHEMATICS_PARTS\MS_DISCRETE_Library.schlib; Mfr_name: WURTH ELECTRONICS; Mfr_part_number: 885012105018; Mistral Part No: 120020080003-R; Package: 0402; Part_type: CAPACITORS\CERAMIC; Project: AM64x_EVM_BRD; RoHS: RoHS; Temperature: -55°C+85°C; Tolerance: 20%; Voltage: 25V; Wattage: NA; Weight: 0.65mg; Datasheet: Y:\MIS_DATABASE\DATASHEETS\CAPACITORS\885012105018.PDF
R17 R18 R25-R27 R40 R45 R68 R72 R93 R98 R124 R125 R132 R133 R224 R226 R243 R248 R253 = RESISTOR: RES 10K 1/16W 5% 0402; Chkd/date: VASANTHA/061216; Crtd /date: MAZHAR/230805; Custom_Duty: 15%; Customs_HS_Code: 85332119; Distributor_name: DIGIKEY; Distributor_part_number: 311-10KJRCT-ND; Footprint Path: Y:\MIS_DATABASE\Library\ALTIUM_TOOL\PCB_FOOTPRINTS\Altium_Footprint_Lib.PcbLib; Height: 0.40MM; Library Path: Y:\MIS_DATABASE\Library\ALTIUM_TOOL\SCHEMATICS_PARTS\MS_DISCRETE_Library.schlib; Mfr_name: YAGEO AMERICA; Mfr_part_number: RC0402JR-0710KL; Mistral Part No: 110011060021-R; Package: 0402; Part_type: RESISTORS\FIXED; Project: HSE; RoHS: RoHS; Temperature: -55°C+155°C; Tolerance: 5%; Voltage: NA; Wattage: 1/16W; Weight: 0.65mg; Datasheet: Y:\MIS_DATABASE\DATASHEETS\RESISTORS\RCXXXXL-SER_MAR18.PDF
TP25 TP27 = TESTPOINT: TESTPOINT CIR 20 SMD; Chkd/date: SHREESHAIL/171006; Crtd /date: MAZHAR/171006; Custom_Duty: NA; Customs_HS_Code: NA; Distributor_name: NA; Distributor_part_number: NA; Footprint Path: Y:\MIS_DATABASE\Library\ALTIUM_TOOL\PCB_FOOTPRINTS\Altium_Footprint_Lib.PcbLib; Height: NA; Library Path: Y:\MIS_DATABASE\Library\ALTIUM_TOOL\SCHEMATICS_PARTS\MS_DISCRETE_Library.schlib; MECHANICAL 3D STEP FILE: NA; Mfr_name: LOCAL; Mistral Part No: NA; Package: SMD; Project: BT MODULE_CSRBC04; RoHS: NA; Temperature: NA; Tolerance: NA; Voltage: NA; Wattage: NA; Weight: NA; Datasheet: NA
U7 = AT24HC04B-TH-B_TSSOP8: IC 1MBIT I2C SERIAL EEPROM TSSOP8; Chkd/date: NAVEED/241114; Crtd /date: VASANTHA/230914; Custom_Duty: 15%; Customs_HS_Code: 85423100; Distributor_name: DIGIKEY; Distributor_part_number: AT24CM01-XHD-TCT-ND; Height: 1.20MM; Mfr_name: ATMEL; Mfr_part_number: AT24CM01-XHD-T; Mistral Part No: 141114090006-R; Package: TSSOP8; Part_type: ICS\DIGITAL\MEMORY; Project: GALILEO_EVM; RoHS: RoHS; Temperature: -40°C+85°C; Tolerance: NA; Voltage: NA; Wattage: NA; Weight: 158mg; Datasheet: Y:\MIS_DATABASE\DATASHEETS\ICS\MEMORY\AT24CM01.PDF
U18 U29 = TMP100NA_3K_SOT23-6: IC TEMPERATURE SENSOR WITH I2C AND SMBUS INTERFACE SOT23-6; Chkd/date: MANIRAJA/290817; Crtd /date: MANIRAJA/290817; Custom_Duty: 15%; Customs_HS_Code: 85423100; Distributor_name: DIGIKEY; Distributor_part_number: 296-26833-1-ND; Height: 1.45MM; Library Ref: TMP100NA/3K_SOT23-6; Mfr_name: TEXAS INSTRUMENTS; Mistral Part No: 141017080030-R; Package: SOT23-6; Part_type: ICS\DIGITAL\PERIPHERAL; Project: TI_MAXIE_CPB; RoHS: RoHS; Temperature: -55°C+125°C; Tolerance: NA; Voltage: NA; Wattage: NA; Weight: 120mg; Datasheet: Y:\MIS_DATABASE\DATASHEETS\ICS\DIGITAL\PERIPHERAL\TMP10XX.PDF
U66 = TCA9554APWR_TSSOP16: IC 8-BIT I2C AND SMBUS I/O EXPANDER WITH INTERRUPT O/P TSSOP16; Chkd/date: MANIRAJA/110917; Crtd /date: MANIRAJA/110917; Custom_Duty: 15%; Customs_HS_Code: 85423100; Distributor_name: DIGIKEY; Distributor_part_number: 296-28120-1-ND; Height: 1.20MM; Mfr_name: TEXAS INSTRUMENTS; Mistral Part No: 141017090007-R; Package: TSSOP16; Part_type: ICS\DIGITAL\BUSTRANSCEIVER; Project: TI_MAXIE_CPB; RoHS: RoHS; Temperature: -40°C+85°C; Tolerance: NA; Voltage: NA; Wattage: NA; Weight: 173mg; Datasheet: Y:\MIS_DATABASE\DATASHEETS\ICS\DIGITAL\BUSTRANSCEIVER\TCA9554.PDF
U23 = XAM6442BSFGGAALV_BGA441: IC AM64x SoC MICROPROCESSOR BGA441; Chkd/date: ALVY/300322; Crtd /date: ALVY/300322; Custom_Duty: 15%; Customs_HS_Code: 85423100; Distributor_name: NA; Distributor_part_number: NA; Footprint Path: Y:\MIS_DATABASE\Library\ALTIUM_TOOL\PCB_FOOTPRINTS\Altium_Footprint_Lib.PcbLib; Height: 2.57MM; Library Path: Y:\MIS_DATABASE\Library\ALTIUM_TOOL\SCHEMATICS_PARTS\MS_MICROPROCESSOR_Library.schlib; Mfr_name: TEXAS INSTRUMENTS; Mistral Part No: 141220080002; Package: BGA441; Part_type: ICS\DIGITAL\MICROPROCESSOR; Project: AM64x-GP_EVM BRD; RoHS: NA; Temperature: NA; Tolerance: NA; Voltage: NA; Wattage: NA; Weight: NA; Datasheet: Y:\MIS_DATABASE\DATASHEETS\ICS\DIGITAL\MICROCONTROLLER\AM64-SoC_SVB.PDF
C225 C536 = CAP: CAP CERAMIC 1uF 10V 20% X5R 0402; Chkd/date: MANIRAJA/210820; Crtd /date: ALVY/190820; Custom_Duty: 15%; Customs_HS_Code: 85322990; Distributor_name: DIGIKEY; Distributor_part_number: 732-7489-1-ND; Footprint Path: Y:\MIS_DATABASE\Library\ALTIUM_TOOL\PCB_FOOTPRINTS\Altium_Footprint_Lib.PcbLib; Height: 0.55MM; Library Path: Y:\MIS_DATABASE\Library\ALTIUM_TOOL\SCHEMATICS_PARTS\MS_DISCRETE_Library.schlib; Mfr_name: WURTH ELECTRONICS; Mfr_part_number: 885012105012; Mistral Part No: 120020080009-R; Package: 0402; Part_type: CAPACITORS\CERAMIC; Project: AM64x_EVM_BRD; RoHS: RoHS; Temperature: -55°C+85°C; Tolerance: 20%; Voltage: 10V; Wattage: NA; Weight: 0.65mg; Datasheet: Y:\MIS_DATABASE\DATASHEETS\CAPACITORS\885012105012.PDF
C234 = CAP: CAP CERAMIC 0.01uF 25V 10% X5R 0201; Chkd/date: MANIRAJA/230118; Crtd /date: MANIRAJA/230118; Custom_Duty: 15%; Customs_HS_Code: 85322990; Distributor_name: DIGIKEY; Distributor_part_number: GRM033R61E103KA12J-ND; Footprint Path: Y:\MIS_DATABASE\Library\ALTIUM_TOOL\PCB_FOOTPRINTS\Altium_Footprint_Lib.PcbLib; Height: 0.33MM; Library Path: Y:\MIS_DATABASE\Library\ALTIUM_TOOL\SCHEMATICS_PARTS\MS_DISCRETE_Library.schlib; Mfr_name: MURATA; Mfr_part_number: GRM033R61E103KA12J; Mistral Part No: 120018010007-R; Package: 0201; Part_type: CAPACITORS\CERAMIC; Project: TI_MAXIE_CPB; RoHS: RoHS; Temperature: -55°C+85°C; Tolerance: 10%; Voltage: 25V; Wattage: NA; Weight: 0.33mg; Datasheet: Y:\MIS_DATABASE\DATASHEETS\CAPACITORS\GRM033R61E103KA12.PDF
C247 C255-C257 C262 = CAP: CAP CERAMIC 10pF 16V 5% C0G(NP0) 0402; Chkd/date: MANIRAJA/100918; Crtd /date: ALVY/100918; Custom_Duty: 15%; Customs_HS_Code: 85322990; Distributor_name: DIGIKEY; Distributor_part_number: 732-7441-1-ND; Footprint Path: Y:\MIS_DATABASE\Library\ALTIUM_TOOL\PCB_FOOTPRINTS\Altium_Footprint_Lib.PcbLib; Height: 0.55MM; Library Path: Y:\MIS_DATABASE\Library\ALTIUM_TOOL\SCHEMATICS_PARTS\MS_DISCRETE_Library.schlib; Mfr_name: WURTH ELECTRONICS; Mfr_part_number: 885012005025; Mistral Part No: 120018030015-R; Package: 0402; Part_type: CAPACITORS\CERAMIC; Project: SMART-M_SCRIPTALK_PB; RoHS: RoHS; Temperature: -55°C+125°C; Tolerance: 5%; Voltage: 16V; Wattage: NA; Weight: 0.65mg; Datasheet: Y:\MIS_DATABASE\DATASHEETS\CAPACITORS\885012005025.PDF
C509 C513 C517 C519 = CAP: CAP CERAMIC 0.47uF 10V 10% X7S AUTO 0402; Chkd/date: MANIRAJA/190220; Crtd /date: ALVY/190220; Custom_Duty: 15%; Customs_HS_Code: 85322990; Distributor_name: DIGIKEY; Distributor_part_number: 445-16100-1-ND; Footprint Path: Y:\MIS_DATABASE\Library\ALTIUM_TOOL\PCB_FOOTPRINTS\Altium_Footprint_Lib.PcbLib; Height: 0.55MM; Library Path: Y:\MIS_DATABASE\Library\ALTIUM_TOOL\SCHEMATICS_PARTS\MS_DISCRETE_Library.schlib; Mfr_name: TDK CORPORATION; Mfr_part_number: CGA2B3X7S1A474K050BB; Mistral Part No: 120018090057-R; Package: 0402; Part_type: CAPACITORS\CERAMIC; Project: TI_MAXIE_CPB; RoHS: RoHS; Temperature: -55°C+125°C; Tolerance: 10%; Voltage: 10V; Wattage: NA; Weight: 0.65mg; Datasheet: Y:\MIS_DATABASE\DATASHEETS\CAPACITORS\CGA2B3X7S1A474K050BB.PDF
C520-C523 = CAP: CAP CERAMIC 4.7uF 10V 20% X5R 0402; Chkd/date: MANIRAJA/230118; Crtd /date: MANIRAJA/230118; Custom_Duty: 15%; Customs_HS_Code: 85322990; Distributor_name: DIGIKEY; Distributor_part_number: 478-10791-1-ND; Footprint Path: Y:\MIS_DATABASE\Library\ALTIUM_TOOL\PCB_FOOTPRINTS\Altium_Footprint_Lib.PcbLib; Height: 0.71MM; Library Path: Y:\MIS_DATABASE\Library\ALTIUM_TOOL\SCHEMATICS_PARTS\MS_DISCRETE_Library.schlib; Mfr_name: AVX CORPORATION; Mfr_part_number: 0402ZD475MAT2A; Mistral Part No: 120012060002-R; Package: 0402; Part_type: CAPACITORS\CERAMIC; Project: TI_MAXIE_CPB; RoHS: RoHS; Temperature: -55°C+85°C; Tolerance: 20%; Voltage: 10V; Wattage: NA; Weight: 0.65mg; Datasheet: Y:\MIS_DATABASE\DATASHEETS\CAPACITORS\AVX_MLC.PDF
C532 C533 = CAP: CAP CERAMIC 27pF 16V 5% C0G(NP0) 0402; Chkd/date: ALVY/100221; Crtd /date: MANIRAJA/100221; Custom_Duty: 15%; Customs_HS_Code: 85322990; Distributor_name: DIGIKEY; Distributor_part_number: 478-0402YA270JAT2ACT-ND; Footprint Path: Y:\MIS_DATABASE\Library\ALTIUM_TOOL\PCB_FOOTPRINTS\Altium_Footprint_Lib.PcbLib; Height: 0.56MM; Library Path: Y:\MIS_DATABASE\Library\ALTIUM_TOOL\SCHEMATICS_PARTS\MS_DISCRETE_Library.schlib; Mfr_name: AVX CORPORATION; Mfr_part_number: 0402YA270JAT2A; Mistral Part No: 120021020020-R; Package: 0402; Part_type: CAPACITORS\CERAMIC; Project: TI_AM64x_EVM; RoHS: RoHS; Temperature: -55°C+125°C; Tolerance: 5%; Voltage: 16V; Wattage: NA; Weight: 1.5mg; Datasheet: Y:\MIS_DATABASE\DATASHEETS\CAPACITORS\AVX_MLC.PDF
FB12 FB25 = INDUCTOR_FERRITE: IND FERRITE BEAD CHIP 120E 2A 0603; Chkd/date: MANIRAJA/180820; Crtd /date: ALVY/180820; Custom_Duty: 24%; Customs_HS_Code: 85437099; Distributor_name: DIGIKEY; Distributor_part_number: 732-782631141CT-ND; Footprint Path: Y:\MIS_DATABASE\Library\ALTIUM_TOOL\PCB_FOOTPRINTS\Altium_Footprint_Lib.PcbLib; Height: 1.00MM; Library Path: Y:\MIS_DATABASE\Library\ALTIUM_TOOL\SCHEMATICS_PARTS\MS_FILTER_Library.schlib; Mfr_name: WURTH ELECTRONICS; Mfr_part_number: 782631141; Mistral Part No: 130020080015-R; Package: 0603; Part_type: INDUCTOR; Project: AM64x_EVM_BRD; RoHS: RoHS; Temperature: -55°C+125°C; Tolerance: 25%; Voltage: NA; Wattage: NA; Weight: NA; Datasheet: Y:\MIS_DATABASE\DATASHEETS\DISCRETES\INDUCTORS\782631141.PDF
FL17-FL20 = CAP_FILTER: PASSIVE FILTER EMI 0.47uF 0805; Chkd/date: RAGESH/121010; Crtd /date: MUDDU/010210; Custom_Duty: 24%; Customs_HS_Code: 85437099; Distributor_name: DIGIKEY; Distributor_part_number: 490-2537-1-ND; Height: 0.95MM; Mfr_name: MURATA; Mfr_part_number: NFM21PC474R1C3D; Mistral Part No: 130010010009; Package: 0805; Part_type: MISC\FILTER; Project: KOPIN_MODULS; Temperature: -55°C+125°C; Weight: NA; Datasheet: Y:\MIS_DATABASE\DATASHEETS\ICS\MISC\NFM21P.PDF
R50 R245 R255 R257 = RESISTOR: RES 100E 1/16W 5% 0402; Chkd/date: MANIRAJA/230817; Crtd /date: MANIRAJA/230817; Custom_Duty: 15%; Customs_HS_Code: 85332119; Distributor_name: DIGIKEY; Distributor_part_number: 541-100JCT-ND; Footprint Path: Y:\MIS_DATABASE\Library\ALTIUM_TOOL\PCB_FOOTPRINTS\Altium_Footprint_Lib.PcbLib; Height: 0.40MM; Library Path: Y:\MIS_DATABASE\Library\ALTIUM_TOOL\SCHEMATICS_PARTS\MS_DISCRETE_Library.schlib; Mfr_name: VISHAY; Mfr_part_number: CRCW0402100RJNED; Mistral Part No: 110014060039-R; Package: 0402; Part_type: RESISTORS\FIXED; Project: TI_MAXIE_CPB; RoHS: RoHS; Temperature: -55°C+155°C; Tolerance: 5%; Voltage: NA; Wattage: 1/16W; Weight: 0.65mg; Datasheet: Y:\MIS_DATABASE\DATASHEETS\RESISTORS\CRCW0603.PDF
R53 R59-R61 R65 R681-R684 = RESISTOR: RES 49.9E 1/16W 1% 0402; Chkd/date: MANIRAJA/210519; Crtd /date: MANIRAJA/210519; Custom_Duty: 15%; Customs_HS_Code: 85332119; Distributor_name: DIGIKEY; Distributor_part_number: 541-3967-1-ND; Footprint Path: Y:\MIS_DATABASE\Library\ALTIUM_TOOL\PCB_FOOTPRINTS\Altium_Footprint_Lib.PcbLib; Height: 0.35MM; Library Path: Y:\MIS_DATABASE\Library\ALTIUM_TOOL\SCHEMATICS_PARTS\MS_DISCRETE_Library.schlib; Mfr_name: VISHAY; Mfr_part_number: CRCW040249R9FKEDC; Mistral Part No: 110009030846-R; Package: 0402; Part_type: RESISTORS\FIXED; Project: RFSU_RFTJ_CARD; RoHS: RoHS; Temperature: -55°C+155°C; Tolerance: 1%; Voltage: NA; Wattage: 1/16W; Weight: 0.65mg; Datasheet: Y:\MIS_DATABASE\DATASHEETS\RESISTORS\CRCW_C-SER.PDF
R55 R80 R262 = RESISTOR: RES 1K 1/10W 1% 0402; Chkd/date: VASANTHA/281216; Crtd /date: MAZHAR/150506; Custom_Duty: 15%; Customs_HS_Code: 85332119; Distributor_name: DIGIKEY; Distributor_part_number: P1.00KLCT-ND; Footprint Path: Y:\MIS_DATABASE\Library\ALTIUM_TOOL\PCB_FOOTPRINTS\Altium_Footprint_Lib.PcbLib; Height: 0.40MM; Library Path: Y:\MIS_DATABASE\Library\ALTIUM_TOOL\SCHEMATICS_PARTS\MS_DISCRETE_Library.schlib; Mfr_name: PANASONIC-ECG; Mfr_part_number: ERJ-2RKF1001X; Mistral Part No: 110009030411-R; Package: 0402; Part_type: RESISTORS\FIXED; Project: VOCERA; RoHS: RoHS; Temperature: -55°C+155°C; Tolerance: 1%; Voltage: NA; Wattage: 1/10W; Weight: 0.8mg; Datasheet: Y:\MIS_DATABASE\DATASHEETS\RESISTORS\PAN-ERJSER_NOV17.PDF
R235-R239 R272 = RESISTOR: RES 22E 1/16W 1% 0402; Chkd/date: SUHAS/290910; Crtd /date: MAZHAR/090909; Cust_part_number: 4700-80047E; Custom_Duty: 15%; Customs_HS_Code: 85332119; Distributor_name: DIGIKEY; Distributor_part_number: 311-22.0LRCT-ND; Footprint Path: Y:\MIS_DATABASE\Library\ALTIUM_TOOL\PCB_FOOTPRINTS\Altium_Footprint_Lib.PcbLib; Height: 0.40MM; Library Path: Y:\MIS_DATABASE\Library\ALTIUM_TOOL\SCHEMATICS_PARTS\MS_DISCRETE_Library.schlib; Mfr_name: YAGEO AMERICA; Mfr_part_number: RC0402FR-0722RL; Mistral Part No: 110009090004-R; Package: 0402; Part_type: RESISTORS\FIXED; Project: VMEFMCD; RoHS: RoHS; SIGNAL_MODEL: RESISTOR_RES0402_22E_22E; Temperature: -55°C+155°C; Tolerance: 1%; Voltage: NA; Wattage: 1/16W; Weight: 0.65mg; Datasheet: Y:\MIS_DATABASE\DATASHEETS\RESISTORS\RCXXXXL-SER_MAR18.PDF
R14 R20 R127 R136 R217 R246 R252 R254 R268 R312 R659 R660 R688 = RESISTOR: RES 0E 1/16W JUMPER 0402; Chkd/date: VASANTHA/201216; Crtd /date: MUDDU/190810; Custom_Duty: 15%; Customs_HS_Code: 85332119; Distributor_name: DIGIKEY; Distributor_part_number: 541-0.0JCT-ND; Footprint Path: Y:\MIS_DATABASE\Library\ALTIUM_TOOL\PCB_FOOTPRINTS\Altium_Footprint_Lib.PcbLib; Height: 0.40MM; Library Path: Y:\MIS_DATABASE\Library\ALTIUM_TOOL\SCHEMATICS_PARTS\MS_DISCRETE_Library.schlib; Mfr_name: VISHAY; Mfr_part_number: CRCW04020000Z0ED; Mistral Part No: 110010080019-R; Package: 0402; Part_type: RESISTORS\FIXED; Project: PB_BUGBASE; RoHS: RoHS; Temperature: -55°C+155°C; Tolerance: NA; Voltage: NA; Wattage: 1/16W; Weight: 0.65mg; Datasheet: Y:\MIS_DATABASE\DATASHEETS\RESISTORS\CRCW0603.PDF
R652-R655 = RESISTOR: RES 33E 1/10W 1% 0402; Chkd/date: VASANTHA/061216; Crtd /date: JEBRAN/171114; Custom_Duty: 15%; Customs_HS_Code: 85332119; Distributor_name: DIGIKEY; Distributor_part_number: P33.0LCT-ND; Footprint Path: Y:\MIS_DATABASE\Library\ALTIUM_TOOL\PCB_FOOTPRINTS\Altium_Footprint_Lib.PcbLib; Height: 0.40MM; Library Path: Y:\MIS_DATABASE\Library\ALTIUM_TOOL\SCHEMATICS_PARTS\MS_DISCRETE_Library.schlib; Mfr_name: PANASONIC-ECG; Mfr_part_number: ERJ-2RKF33R0X; Mistral Part No: 110014110006-R; Package: 0402; Part_type: RESISTORS\FIXED; Project: ZK BIOMETRIC; RoHS: RoHS; Temperature: -55°C+155°C; Tolerance: 1%; Voltage: NA; Wattage: 1/10W; Weight: 0.8mg; Datasheet: Y:\MIS_DATABASE\DATASHEETS\RESISTORS\PAN-ERJSER_NOV17.PDF
R656 R672 R686 R687 = RESISTOR: RES 4.7K 1/16W 5% 0402; Chkd/date: VASANTHA/130516; Crtd /date: VASANTHA/130516; Custom_Duty: 15%; Customs_HS_Code: 85332119; Distributor_name: DIGIKEY; Distributor_part_number: 311-4.7KJRCT-ND; Footprint Path: Y:\MIS_DATABASE\Library\ALTIUM_TOOL\PCB_FOOTPRINTS\Altium_Footprint_Lib.PcbLib; Height: 0.40MM; Library Path: Y:\MIS_DATABASE\Library\ALTIUM_TOOL\SCHEMATICS_PARTS\MS_DISCRETE_Library.schlib; Mfr_name: YAGEO AMERICA; Mfr_part_number: RC0402JR-074K7L; Mistral Part No: 110011060001-R; Package: 0402; Part_type: RESISTORS\FIXED; Project: TMDXCSK368; RoHS: RoHS; Temperature: -55°C+155°C; Tolerance: 5%; Voltage: NA; Wattage: 1/16W; Weight: 0.65mg; Datasheet: Y:\MIS_DATABASE\DATASHEETS\RESISTORS\RCXXXXL-SER_MAR18.PDF
TP102 = TESTPOINT: TESTPOINT CIR 40 SMD; Chkd/date: MAZHAR/190505; Crtd /date: MAZHAR/190505; Distributor_name: NA; Distributor_part_number: NA; Footprint Path: Y:\MIS_DATABASE\Library\ALTIUM_TOOL\PCB_FOOTPRINTS\Altium_Footprint_Lib.PcbLib; Height: NA; Library Path: Y:\MIS_DATABASE\Library\ALTIUM_TOOL\SCHEMATICS_PARTS\MS_DISCRETE_Library.schlib; MECHANICAL 3D STEP FILE: NA; Mfr_name: LOCAL; Mistral Part No: 130009030933; Package: SMD; Project: RAINIER-3; RoHS: NA; Temperature: NA; Tolerance: NA; Voltage: NA; Wattage: NA; Weight: NA; Datasheet: NA
U70 = CDCLVC1310RHBR_VQFN32: IC LOW JITTER,LOW POWER CLK BUFFER LEVEL TRANSLATOR VQFN32; Chkd/date: MANIRAJA/061017; Crtd /date: MANIRAJA/061017; Custom_Duty: 15%; Customs_HS_Code: 85423100; Distributor_name: DIGIKEY; Distributor_part_number: 296-30105-1-ND; Height: 1.00MM; Mfr_name: TEXAS INSTRUMENTS; Mistral Part No: 141017100003-R; Package: VQFN32; Part_type: ICS\INTERFACE\LEVEL TRANSLATOR; Project: TI_MAXIE_CPB; RoHS: RoHS; Temperature: -40°C+85°C; Tolerance: NA; Voltage: NA; Wattage: NA; Weight: 72.2mg; Datasheet: Y:\MIS_DATABASE\DATASHEETS\ICS\INTERFACE\CDCLVC1310RHBR.PDF
U71 = OSC_ASFLMB_SMD4: OSC 25MHz 15pF SMD; Chkd/date: USMAN/231113; Crtd /date: USMAN/231113; Custom_Duty: 24%; Customs_HS_Code: 85437099; Distributor_name: DIGIKEY; Distributor_part_number: 535-11025-1-ND; Height: 0.90MM; Mfr_name: ABRACON CORPORATION; Mfr_part_number: ASFLMB-25.000MHZ-LY-T; Mistral Part No: 130013110024-R; Package: SMD; Part_type: OSCILLATORS; Project: DMP; RoHS: RoHS; Temperature: -40°C+85°C; Tolerance: NA; Voltage: NA; Wattage: NA; Weight: NA; Datasheet: Y:\MIS_DATABASE\DATASHEETS\MISC\CRY_OSC\ASFLMB.PDF
U105 = CDCI6214RGET_VQFN24: IC PCIE GEN4 CLOCK GENERATOR WITH PROGRAMMABLE O/P AND EEPROM VQFN24; Chkd/date: MANIRAJA/051017; Crtd /date: MANIRAJA/051017; Custom_Duty: 15%; Customs_HS_Code: 85423100; Distributor_name: NA; Distributor_part_number: NA; Height: 1.00MM; Mfr_name: TEXAS INSTRUMENTS; Mistral Part No: 141017100002-R; Package: VQFN24; Part_type: ICS\DIGITAL\PERIPHERAL; Project: TI_SVB_MAXWELL_DUT; RoHS: RoHS; Temperature: -40°C+85°C; Tolerance: NA; Voltage: NA; Wattage: NA; Weight: NA; Datasheet: Y:\MIS_DATABASE\DATASHEETS\ICS\DIGITAL\PERIPHERAL\CDCI6214.PDF
Y4 = CRY: CRY 25.000MHz 18pF SMD; Chkd/date: VASANTHA/110316; Crtd /date: JEBRAN/090216; Custom_Duty: 24%; Customs_HS_Code: 85439000; Distributor_name: DIGIKEY; Distributor_part_number: CTX1175CT-ND; Footprint Path: Y:\MIS_DATABASE\Library\ALTIUM_TOOL\PCB_FOOTPRINTS\Altium_Footprint_Lib.PcbLib; Height: 1.35MM; Library Path: Y:\MIS_DATABASE\Library\ALTIUM_TOOL\SCHEMATICS_PARTS\MS_DISCRETE_Library.schlib; Mfr_name: CTS; Mfr_part_number: 445I23D25M00000; Mistral Part No: 130016020016-R; Package: SMD; Part_type: CRYSTAL; Project: PDI_MINIPCB; RoHS: RoHS; Temperature: -40°C+85°C; Tolerance: NA; Voltage: NA; Wattage: NA; Weight: 50mg; Datasheet: Y:\MIS_DATABASE\DATASHEETS\MISC\CRY_OSC\445.PDF
C56 = CAP_POL: CAP ELECTROLYTIC 100uF 50V 20% D8CASE_6666; Chkd/date: MANIRAJA/051018; Crtd /date: ALVY/051018; Custom_Duty: 15%; Customs_HS_Code: 85322990; Distributor_name: DIGIKEY; Distributor_part_number: PCE5024CT-ND; Footprint Path: Y:\MIS_DATABASE\Library\ALTIUM_TOOL\PCB_FOOTPRINTS\Altium_Footprint_Lib.PcbLib; Height: 8.00MM; Library Path: Y:\MIS_DATABASE\Library\ALTIUM_TOOL\SCHEMATICS_PARTS\MS_DISCRETE_Library.schlib; Mfr_name: PANASONIC-ECG; Mfr_part_number: EEE-FTH101XAP; Mistral Part No: 120018100013-R; Package: D8CASE_6666; Part_type: CAPACITORS\ELECTROLYTIC; Project: TI_J7_SVB-DUT; RoHS: RoHS; Temperature: -55°C+105°C; Tolerance: 20%; Voltage: 50V; Wattage: NA; Weight: 440mg; Datasheet: Y:\MIS_DATABASE\DATASHEETS\CAPACITORS\FTV-SER.PDF
C478 = CAP: CAP CERAMIC 1000pF 2KV 10% X7R 1206; Chkd/date: SHREESHAIL/291106; Crtd /date: MAZHAR/281106; Custom_Duty: 15%; Customs_HS_Code: 85322990; Distributor_name: DIGIKEY; Distributor_part_number: 478-2956-1-ND; Footprint Path: Y:\MIS_DATABASE\Library\ALTIUM_TOOL\PCB_FOOTPRINTS\Altium_Footprint_Lib.PcbLib; Height: 1.52MM; Library Path: Y:\MIS_DATABASE\Library\ALTIUM_TOOL\SCHEMATICS_PARTS\MS_DISCRETE_Library.schlib; Mfr_name: AVX CORPORATION; Mfr_part_number: 1206GC102KAT1A; Mistral Part No: 120015080006-R; Package: 1206; Part_type: CAPACITORS\CERAMIC; Project: ADR1B; RoHS: RoHS; Temperature: -55°C+125°C; Tolerance: 10%; Voltage: 2KV; Wattage: NA; Weight: 16.2mg; Datasheet: Y:\MIS_DATABASE\DATASHEETS\CAPACITORS\AVX_HV-MLC.PDF
D1 = DIODE_TVS_DUAL: DIODE TVS BI-DIE 1500W 64V SMC; Chkd/date: VASANTHA/101015; Crtd /date: VASANTHA/101015; Custom_Duty: 15%; Customs_HS_Code: 85412900; Distributor_name: DIGIKEY; Distributor_part_number: SMCJ64CALFCT-ND; Height: 2.62MM; Mfr_name: LITTLE FUSE; Mistral Part No: 130015100009-R; Package: SMC; Part_type: DIODE\TVS; Project: GALILEO_EVM; RoHS: RoHS; Temperature: -55°C+150°C; Tolerance: NA; Voltage: 64V; Wattage: NA; Weight: NA; Datasheet: Y:\MIS_DATABASE\DATASHEETS\DISCRETES\DIODES\LTFUSE-SMCJ.PDF
D2 = DIODE: DIODE RECTIFIER 400V 1A SMA; Chkd/date: SUHAS/061010; Crtd /date: USMAN/220808; Custom_Duty: 15%; Customs_HS_Code: 85412900; Distributor_name: DIGIKEY; Distributor_part_number: S1G-FDICT-ND; Height: 2.30MM; Mfr_name: DIODES INC; Mistral Part No: 130009030153; Package: SMA; Part_type: DIODE\RECTIFIER; Project: CPB; Temperature: -65°C+150°C; Voltage: 400V; Weight: 0.0064g; Datasheet: Y:\MIS_DATABASE\DATASHEETS\DISCRETES\DIODES\S1.PDF
D3 = DIODE_SCHOTTKY_POWERMITE-3: DIODE SCHOTTKY RECTIFIER 45V 15A CFP15 (SOT1289); Chkd/date: MANIRAJA/070220; Crtd /date: ALVY/070220; Custom_Duty: 15%; Customs_HS_Code: 85412900; Distributor_name: DIGIKEY; Distributor_part_number: 1727-1905-1-ND; Footprint Path: Y:\MIS_DATABASE\Library\ALTIUM_TOOL\PCB_FOOTPRINTS\Altium_Footprint_Lib.PcbLib; Height: 0.82MM; Library Path: Y:\MIS_DATABASE\Library\ALTIUM_TOOL\SCHEMATICS_PARTS\MS_DISCRETE_Library.schlib; Mfr_name: NEXPERIA; Mistral Part No: 130020020003-R; Package: CFP15; Part_type: DIODE\SCHOTTKY; Project: TI_MAXIE_CPB; RoHS: RoHS; Temperature: -55°C+175°C; Tolerance: NA; Voltage: NA; Wattage: NA; Weight: 87.3mg; Datasheet: Y:\MIS_DATABASE\DATASHEETS\DISCRETES\DIODES\PMEG045V150EPD.PDF
F1 = FUSE: FUSE 10A 60V FAST SMD; Chkd/date: RAGESH/151010; Crtd /date: MAZHAR/220907; Distributor_name: DIGIKEY; Distributor_part_number: TR2/1025FA10-R-ND; Height: 2.90MM; Mfr_name: COOPER BUSSMANN; Mfr_part_number: 1025FA10-R; Mistral Part No: 130009030821-R; Package: SMD; Project: SMART VIEW_NVR; RoHS: RoHS; Voltage: 60V; Datasheet: Y:\MIS_DATABASE\DATASHEETS\MISC\FUSE\1025FA-SER.PDF
J6 = CON_PWRJACK2_PJ-082BH: CON POWER JACK 2POS MALE RT TH; Chkd/date: ALVY/100221; Crtd /date: MANIRAJA/100221; Custom_Duty: 24%; Customs_HS_Code: 85369090; Distributor_name: DIGIKEY; Distributor_part_number: CP-080BHCT-ND; Footprint Path: Y:\MIS_DATABASE\Library\ALTIUM_TOOL\PCB_FOOTPRINTS\Altium_Footprint_Lib.PcbLib; Height: 13.40MM; Library Path: Y:\MIS_DATABASE\Library\ALTIUM_TOOL\SCHEMATICS_PARTS\MS_CONNECTOR_Library.schlib; Mfr_name: CUI INC; Mfr_part_number: PJ-080BH; Mistral Part No: 150021020035-R; Package: THRU-HOLE; Part_type: CONNECTOR\JACK; Project: TI_AM64x_EVM; RoHS: RoHS; Temperature: -25°C+85°C; Tolerance: NA; Voltage: NA; Wattage: NA; Weight: 9090mg; Datasheet: Y:\MIS_DATABASE\DATASHEETS\CONNECTORS\PJ-080BH.PDF
LD1-LD3 LD6-LD8 LD10 = DIODE_LED: DIODE LED BRIGHT GREEN SMD; Chkd/date: MANIRAJA/180820; Crtd /date: ALVY/180820; Custom_Duty: 24%; Customs_HS_Code: 85439000; Distributor_name: DIGIKEY; Distributor_part_number: 732-4986-1-ND; Footprint Path: Y:\MIS_DATABASE\Library\ALTIUM_TOOL\PCB_FOOTPRINTS\Altium_Footprint_Lib.PcbLib; Height: 0.80MM; Library Path: Y:\MIS_DATABASE\Library\ALTIUM_TOOL\SCHEMATICS_PARTS\MS_OPTO_Library.schlib; Mfr_name: WURTH ELECTRONICS; Mistral Part No: 130020080012-R; Package: SMD; Part_type: OPTO\LED; Project: AM64x_EVM_BRD; RoHS: RoHS; Temperature: -40°C+85°C; Tolerance: NA; Voltage: NA; Wattage: NA; Weight: 10mg; Datasheet: Y:\MIS_DATABASE\DATASHEETS\DISCRETES\LEDS\150080VS75000.PDF
LD5 = DIODE_LED: DIODE LED RED SMD; Chkd/date: MANIRAJA/180820; Crtd /date: ALVY/180820; Custom_Duty: 24%; Customs_HS_Code: 85439000; Distributor_name: DIGIKEY; Distributor_part_number: 732-4984-1-ND; Footprint Path: Y:\MIS_DATABASE\Library\ALTIUM_TOOL\PCB_FOOTPRINTS\Altium_Footprint_Lib.PcbLib; Height: 0.80MM; Library Path: Y:\MIS_DATABASE\Library\ALTIUM_TOOL\SCHEMATICS_PARTS\MS_OPTO_Library.schlib; Mfr_name: WURTH ELECTRONICS; Mistral Part No: 130020080013-R; Package: SMD; Part_type: OPTO\LED; Project: AM64x_EVM_BRD; RoHS: RoHS; Temperature: -40°C+85°C; Tolerance: NA; Voltage: NA; Wattage: NA; Weight: 25mg; Datasheet: Y:\MIS_DATABASE\DATASHEETS\DISCRETES\LEDS\150080RS75000.PDF
Q1 Q2 Q5-Q7 Q11 = MOSFET_BSS138LT1G: IC MOSFET N-CHANNEL 50V 200mA SOT23-3; Chkd/date: MANIRAJA/250219; Crtd /date: JEBRAN/060416; Custom_Duty: 15%; Customs_HS_Code: 85423100; Distributor_name: DIGIKEY; Distributor_part_number: BSS138LT1GOSCT-ND; Footprint Path: Y:\MIS_DATABASE\Library\ALTIUM_TOOL\PCB_FOOTPRINTS\Altium_Footprint_Lib.PcbLib; Height: 1.11MM; Library Path: Y:\MIS_DATABASE\Library\ALTIUM_TOOL\SCHEMATICS_PARTS\MS_MOSFET_Library.schlib; Library Ref: MOSFET_BSS138W; Mfr_name: ON SEMICONDUCTOR; Mistral Part No: 142016040001-R; Package: SOT23-3; Part_type: ICS\POWER\MOSFET; Project: LRDE_ABCM; RoHS: RoHS; Temperature: -55°C+150°C; Tolerance: NA; Voltage: NA; Wattage: NA; Weight: 8mg; Datasheet: Y:\MIS_DATABASE\DATASHEETS\DISCRETES\TRANSISTORS_FETS\BSS138LT1G.PDF
R15 R211 R212 R305 R360 R365 = RESISTOR: RES 220E 1/10W 5% 0402; Chkd/date: VASANTHA/291216; Crtd /date: GEETHA/260406; Custom_Duty: 15%; Customs_HS_Code: 85332119; Distributor_name: DIGIKEY; Distributor_part_number: P220JCT-ND; Footprint Path: Y:\MIS_DATABASE\Library\ALTIUM_TOOL\PCB_FOOTPRINTS\Altium_Footprint_Lib.PcbLib; Height: 0.40MM; Library Path: Y:\MIS_DATABASE\Library\ALTIUM_TOOL\SCHEMATICS_PARTS\MS_DISCRETE_Library.schlib; Mfr_name: PANASONIC-ECG; Mfr_part_number: ERJ-2GEJ221X; Mistral Part No: 110009030506-R; Package: 0402; Part_type: RESISTORS\FIXED; Project: RED EYE; RoHS: RoHS; Temperature: -55°C+155°C; Tolerance: 5%; Voltage: NA; Wattage: 1/10W; Weight: 0.8mg; Datasheet: Y:\MIS_DATABASE\DATASHEETS\RESISTORS\PAN-ERJSER_NOV17.PDF
R64 = RESISTOR: RES 10K 2/3W 5% 1206; Chkd/date: VASANTHA/101015; Crtd /date: VASANTHA/101015; Custom_Duty: 15%; Customs_HS_Code: 85332119; Distributor_name: DIGIKEY; Distributor_part_number: P10KALCT-ND; Footprint Path: Y:\MIS_DATABASE\Library\ALTIUM_TOOL\PCB_FOOTPRINTS\Altium_Footprint_Lib.PcbLib; Height: 0.70MM; Library Path: Y:\MIS_DATABASE\Library\ALTIUM_TOOL\SCHEMATICS_PARTS\MS_DISCRETE_Library.schlib; Mfr_name: PANASONIC-ECG; Mfr_part_number: ERJ-P08J103V; Mistral Part No: 110015090016-R; Package: 1206; Part_type: RESISTORS\FIXED; Project: GALILEO_EVM; RoHS: RoHS; Temperature: -55°C+155°C; Tolerance: 5%; Voltage: NA; Wattage: 2/3W; Weight: 10mg; Datasheet: Y:\MIS_DATABASE\DATASHEETS\RESISTORS\ERJ-PA_P0-SER.PDF
R566 = RESISTOR: RES 1M 1/10W 5% 0603; Chkd/date: VASANTHA/060217; Crtd /date: USMAN/111207; Custom_Duty: 15%; Customs_HS_Code: 85332119; Distributor_name: DIGIKEY; Distributor_part_number: P1.0MGCT-ND; Footprint Path: Y:\MIS_DATABASE\Library\ALTIUM_TOOL\PCB_FOOTPRINTS\Altium_Footprint_Lib.PcbLib; Height: 0.55MM; Library Path: Y:\MIS_DATABASE\Library\ALTIUM_TOOL\SCHEMATICS_PARTS\MS_DISCRETE_Library.schlib; Mfr_name: PANASONIC-ECG; Mfr_part_number: ERJ-3GEYJ105V; Mistral Part No: 110009030413-R; Package: 0603; Part_type: RESISTORS\FIXED; Project: BSN; RoHS: RoHS; Temperature: -55°C+155°C; Tolerance: 5%; Voltage: NA; Wattage: 1/10W; Weight: 2mg; Datasheet: Y:\MIS_DATABASE\DATASHEETS\RESISTORS\PAN-ERJSER_NOV17.PDF
TP2 TP3 TP5 TP26 TP31 TP34 = TESTPOINT: ACCESSORIE PC TEST POINT; Chkd/date: VASANTHA/121216; Crtd /date: MANIRAJA/121216; Custom_Duty: NA; Customs_HS_Code: NA; Distributor_name: DIGIKEY; Distributor_part_number: 36-5002-ND; Footprint Path: Y:\MIS_DATABASE\Library\ALTIUM_TOOL\PCB_FOOTPRINTS\Altium_Footprint_Lib.PcbLib; Height: 4.57MM; Library Path: Y:\MIS_DATABASE\Library\ALTIUM_TOOL\SCHEMATICS_PARTS\MS_DISCRETE_Library.schlib; Mfr_name: KEYSTONE; Mistral Part No: 160016120008-R; Package: NA; Part_type: ACCESSORIES; Project: EPOS_EVM; RoHS: RoHS; Temperature: NA; Tolerance: NA; Voltage: NA; Wattage: NA; Weight: NA; Datasheet: Y:\MIS_DATABASE\DATASHEETS\MISC\ACCESSORIES\5002.PDF
TP81 = TESTPOINT: TESTPOINT 1.0MM DRILL PTH; Chkd/date: MAZHAR/271211; Crtd /date: SHREESHAIL/041005; Distributor_name: NA; Distributor_part_number: NA; Height: NA; Mfr_name: LOCAL; Mistral Part No: 130009030938; Package: THRU-HOLE; Project: HSE; Datasheet: NA

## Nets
DGND: C27.1 C34.1 C53.1 C56.2 C113.1 C209.2 C225.1 C226.1 C234.2 C247.2 C252.1 C255.2 C256.2 C257.2 C262.2 C478.2 C509.2 C513.2 C517.2 C519.2 C520.2 C521.2 C522.2 C523.2 C524.2 C525.2 C526.2 C527.2 C532.1 C533.1 C536.1 C537.1 C538.1 C541.2 D1.2(ANODE) D2.2(A) FL17.2(GND1) FL18.2(GND1) FL19.2(GND1) FL20.2(GND1) J6.2 LD6.1(CATHODE) Q1.2(S) Q2.2(S) Q5.2(S) Q6.2(S) Q7.2(S) Q11.2(S) R17.1 R26.1 R40.1 R45.2 R53.2 R59.2 R60.2 R61.2 R65.2 R68.1 R93.1 R124.1 R132.2 R245.2 R254.1 R257.2 R262.1 R268.2 R566.2 R656.2 R681.2 R682.2 R683.2 R684.2 R687.2 TP2.1(TP) TP3.1(TP) TP5.1(TP) TP26.1(TP) TP31.1(TP) TP34.1(TP) U7.4(GND) U18.2(GND) U23.A1(VSS) U23.A5(VSS) U23.A6(VSS) U23.A21(VSS) U23.AA1(VSS) U23.AA15(VSS) U23.AA18(VSS) U23.AA21(VSS) U23.C3(VSS) U23.C10(VSS) U23.C15(VSS) U23.D1(VSS) U23.E11(VSS) U23.E13(VSS) U23.F8(VSS) U23.F10(VSS) U23.F15(VSS) U23.G1(VSS) U23.G3(VSS) U23.G7(VSS) U23.G9(VSS) U23.G16(VSS) U23.H6(VSS) U23.H8(VSS) U23.H11(VSS) U23.H20(VSS) U23.H21(VSS) U23.J7(VSS) U23.J9(VSS) U23.J14(VSS) U23.J16(ADC0_REFN) U23.K6(VSS) U23.K8(VSS) U23.L1(VSS) U23.L3(VSS) U23.L7(VSS) U23.L9(VSS) U23.L16(VSS) U23.M6(VSS) U23.M8(VSS) U23.M10(VSS) U23.M12(VSS) U23.N7(VSS) U23.N9(VSS) U23.N11(VSS) U23.N13(VSS) U23.N15(VSS) U23.P1(VSS) U23.P6(VSS) U23.P8(VSS) U23.P10(VSS) U23.P18(VSS) U23.R7(VSS) U23.R9(VSS) U23.R12(VSS) U23.T8(VSS) U23.T10(VSS) U23.T11(VSS) U23.T15(VSS) U23.T16(VSS) U23.U3(VSS) U23.V17(VSS) U23.W10(VSS) U23.W18(VSS) U23.Y14(VSS) U23.Y17(VSS) U23.Y19(VSS) U29.2(GND) U66.1(A0) U66.2(A1) U66.3(A2) U66.8(GND) U70.4(GND) U70.9(GND) U70.15(GND) U70.16(GND) U70.21(GND) U70.25(GND) U70.26(GND) U70.32(GND) U70.33(EP) U71.2(GND) U105.25(GND) ; also on sheet 2 3 4 5 6 7 12 13 14 15 16 17 18 19 20 21 22 23 24 25 26 27 28 29 30 39 40
VCC1V1_PG: R136.2 ; also on sheet 16
VCC1V2_PG: R14.2 ; also on sheet 15
VCC1V8: FB25.1 FL17.1(IN) FL18.1(IN) ; also on sheet 12 13 14 15 18 21 24
VCC2V5_PG: R217.2 ; also on sheet 16
VCC3V3_REF: C509.1 C521.1 C524.1 FL19.3(OUT) U105.3(VDDREF)
VCC3V3_VCO: C513.1 C520.1 C527.1 FL20.3(OUT) U105.24(VDDVCO)
VCC_3V3_SYS: C27.2 C53.2 C113.2 C209.1 FB12.1 FL19.1(IN) FL20.1(IN) R15.2 R18.1 R25.1 R27.1 R72.1 R98.1 R125.1 R133.1 R211.2 R212.2 R224.2 R226.2 R305.2 R360.2 R365.2 R672.1 R686.1 U7.8(VCC) U18.4(V+) U29.4(V+) U66.16(VCC) ; also on sheet 2 5 6 7 12 13 14 15 16 17 18 19 20 21 23 24 25 26 27 29 30 39 40
VCC_CORE_PG: R312.2 ; also on sheet 15 17
VDD1V8_CLKBUF: C536.2 C537.2 C538.2 FB25.2 U70.2(VDDO) U70.6(VDDO) U70.19(VDDO) U70.23(VDDO)
VDD1V8_PG: R127.2 ; also on sheet 15
VDD3V3_CLKBUF: C34.2 C225.2 C226.2 C234.1 FB12.2 R50.1 R55.2 R243.2 R248.1 R253.2 R255.1 U70.10(VDD) U71.4(VDD)
VDD_0V85_PG: R20.2 ; also on sheet 15
VDDO12: C519.1 C523.1 C526.1 FL17.3(OUT) U105.16(VDDO12)
VDDO34: C517.1 C522.1 C525.1 FL18.3(OUT) U105.15(VDDO34)
CDC_EEPROMSEL: R686.2 R687.1 U105.23(EEPROMSEL)
CDC_OE1: R688.1 U105.20(STATUS/GPIO1)
CDC_OE1/OE4: R672.2 R688.2 U105.11(OE/GPIO4) ; also on sheet 13
CDC_OE2: R660.2 U105.19(SDA/GPIO2)
CDC_OE3: R659.2 U105.12(SCL/GPIO3)
CDC_REFSEL: R656.1 U105.4(REFSEL)
CDC_XIN: C532.2 U105.1(XIN) Y4.2
CDC_XOUT: C533.2 U105.2(XOUT) Y4.1
CDC_Y0: TP102.1(TP) U105.7(Y0)
CDC_Y1N: R653.1 U105.21(Y1N)
CDC_Y1P: R652.1 U105.22(Y1P)
CDC_Y4N: R655.1 U105.9(Y4N)
CDC_Y4P: R654.1 U105.10(Y4P)
CDCEL_XIN: C235.2 R245.1 R246.1 R252.2 R255.2
CDCEL_XIN_IN: C235.1 R246.2 U70.11(XIN)
CLKGEN_REFCLK1N: R653.2 R682.1 ; also on sheet 5
CLKGEN_REFCLK1P: R652.2 R681.1 ; also on sheet 5
CLKGEN_REFCLK4N: R655.2 R684.1 ; also on sheet 5
CLKGEN_REFCLK4P: R654.2 R683.1 ; also on sheet 5
CLKOUT0: R50.2 R257.1 U70.13(PRI_INP) ; also on sheet 6
CPSW_RGMII1_ETH1_CLK: R239.2 ; also on sheet 2
EEPROM_A1: R26.2 R27.2 U7.2(A1)
EEPROM_A2: R17.2 R18.2 U7.3(A2)
EEPROM_WP: R25.2 U7.7(WP)
EXP_BRD_DET_INTn: R226.1 U66.13(~{INT})
HSE_DETECT: R224.1 U66.4(P0) ; also on sheet 18
IN_SEL0: R40.2 R248.2 U70.30(IN_SEL0)
IN_SEL1: R45.1 R253.1 U70.29(IN_SEL1)
MAIN: F1.1 J6.1
PRG0_HSE_ETH1_CLK: R236.2 ; also on sheet 18
PRG0_HSE_ETH2_CLK: R235.2 ; also on sheet 18
PRG1_RGMII1_ETH3_CLK: R237.2 ; also on sheet 40
PRG1_RGMII2_ETH2_CLK: R238.2 ; also on sheet 39
PRI_INN: C252.2 R55.1 R262.2 U70.14(PRI_INN)
RESETSTATz: U105.8(RESETN/SYNC) ; also on sheet 5 12 13 21 24 29
SHIELD: C478.1 J6.SH1 J6.SH2 J6.SH3 J6.SH4 R566.1
SoC_CLKIN: R272.2 ; also on sheet 12
SoC_I2C0_SCL: U7.6(SCL) U66.14(SCL) ; also on sheet 6 13 18
SoC_I2C0_SDA: U7.5(SDA) U66.15(SDA) ; also on sheet 6 13 18
SoC_I2C1_SCL: R659.1 TP25.1(TP) U18.1(SCL) U29.1(SCL) ; also on sheet 5 6 7 13 14 30
SoC_I2C1_SDA: R660.1 TP27.1(TP) U18.6(SDA) U29.6(SDA) ; also on sheet 5 6 7 13 14 30
TMP1_ADD0: R68.2 R72.2 U18.5(ADD0)
TMP1_ADD1: R93.2 R98.2 U18.3(ADD1)
TMP2_ADD0: R132.1 R133.2 U29.5(ADD0)
TMP2_ADD1: R124.2 R125.2 U29.3(ADD1)
VDDS_MMC0/ADC0_VREFP: C541.1 ; also on sheet 4
VMAIN: C56.1 D3.3(K) R80.2 TP81.1(TP) ; also on sheet 4 5 16 17
N16248811: C256.1 R60.1 U70.20(Y7)
N16248833: C255.1 R61.1 U70.18(Y6)
N16248855: C262.1 R65.1 R272.1 U70.17(Y5)
N16248877: R235.1 U70.8(Y4)
N16248899: R236.1 U70.7(Y3)
N16248921: R237.1 U70.5(Y2)
N16248943: R238.1 U70.3(Y1)
N16248965: R239.1 U70.1(Y0)
N18321769: R243.1 U70.31(OE)
N18546005: D1.1(CATHODE) D3.1(A1) D3.2(A2) F1.2 R64.1
N18546027: LD5.1(CATHODE) R64.2
N18546044: D2.1(K) LD5.2(ANODE)
N23484157: C247.1 R53.1 U70.24(Y9)
N23484680: C257.1 R59.1 U70.22(Y8)
N25209998: R268.1 U71.1(STANDBY#)
N25294505: LD6.2(ANODE) R80.1
N25526660: R254.2 U70.12(XOUT)
N26145534: Q5.1(G) R312.1
N26145544: LD7.2(ANODE) R305.1
N26145600: Q2.1(G) R20.1
N26145606: LD2.2(ANODE) R211.1
N26145666: Q1.1(G) R14.1
N26145672: LD3.2(ANODE) R15.1
N26145732: Q7.1(G) R136.1
N26145738: LD10.2(ANODE) R365.1
N26145798: Q6.1(G) R127.1
N26145804: LD8.2(ANODE) R360.1
N26145856: Q11.1(G) R217.1
N26145862: LD1.2(ANODE) R212.1
N27030520: R252.1 U71.3(OUTPUT)
N28118242: LD7.1(CATHODE) Q5.3(D)
N28118245: LD2.1(CATHODE) Q2.3(D)
N28118248: LD3.1(CATHODE) Q1.3(D)
N28118251: LD10.1(CATHODE) Q7.3(D)
N28118254: LD8.1(CATHODE) Q6.3(D)
N28118257: LD1.1(CATHODE) Q11.3(D)

Not connected (* = marked no-connect by the designer): U7 1(NC)*; U66 5(P1) 6(P2) 7(P3) 9(P4)* 10(P5)* 11(P6)* 12(P7)*; U70 27(SEC_INN)* 28(SEC_INP)*; U105 5(REFP)* 6(REFN)* 13(Y3N)* 14(Y3P)* 17(Y2N)* 18(Y2P)*

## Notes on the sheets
sheet 8
- MAIN INPUT 12V DC
- VCC = 12V
  ICC max = 8A
- RED
- Condition
- LED Status(LD1)
- Reverse Voltage
- ON
- POWER INDICATION LED's
- Off Page Connections
- Ground test points
sheet 9
- SoC POWER - VSS
- CAD Note:
  Place CAP C541
  between pins
  J15 and J16
- ADC_VREFN/VSS
sheet 10
- TEMPERATURE SENSOR
- I2C ADDRESS: 0x48
- I2C ADDRESS: 0x49
- NOTE: PLACE TEMP SENSOR CLOSE TO SoC
- NOTE: PLACE TEMP SENSOR CLOSE TO CORE POWER SECTION
- BOARD ID EEPROM
- BOARD PRESENCE DETECT CIRCUIT
- I2C ADDRESS: 0X50
- I2C ADDRESS: 0X38
- Off Page Connections
sheet 11
- REFERENCE INPUT SELECTION
- ETHERNET PHY  CLOCK BUFFER
- PROVIDING 2 CLOCK FOR HSE
- Floating Standby pin enables the oscillator
  R268 can be removed to enable the oscillator
- Off Page Connections
- From SoC
- If overdriving the oscillator stage, it is necessary
  to ac-couple the input with a capacitor.
  Otherwise, if selecting the bypass, there is no
  requirement for a coupling capacitor.
- PCIe Clock HCSL (100MHz)
- 100MHz HCSL CLK for SoC
- 100MHz HCSL CLK to PCIe CON J27
- From GPIO Expander
- EEPROMSEL - LOW  - Page-0 (default)
  EEPROMSEL - HIGH - Page-1
- REFSEL-0 selects crystal reference
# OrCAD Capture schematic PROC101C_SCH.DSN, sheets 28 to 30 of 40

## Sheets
28 22. XDS110 DEBUGGER: size C; title: XDS110 DEBUGGER
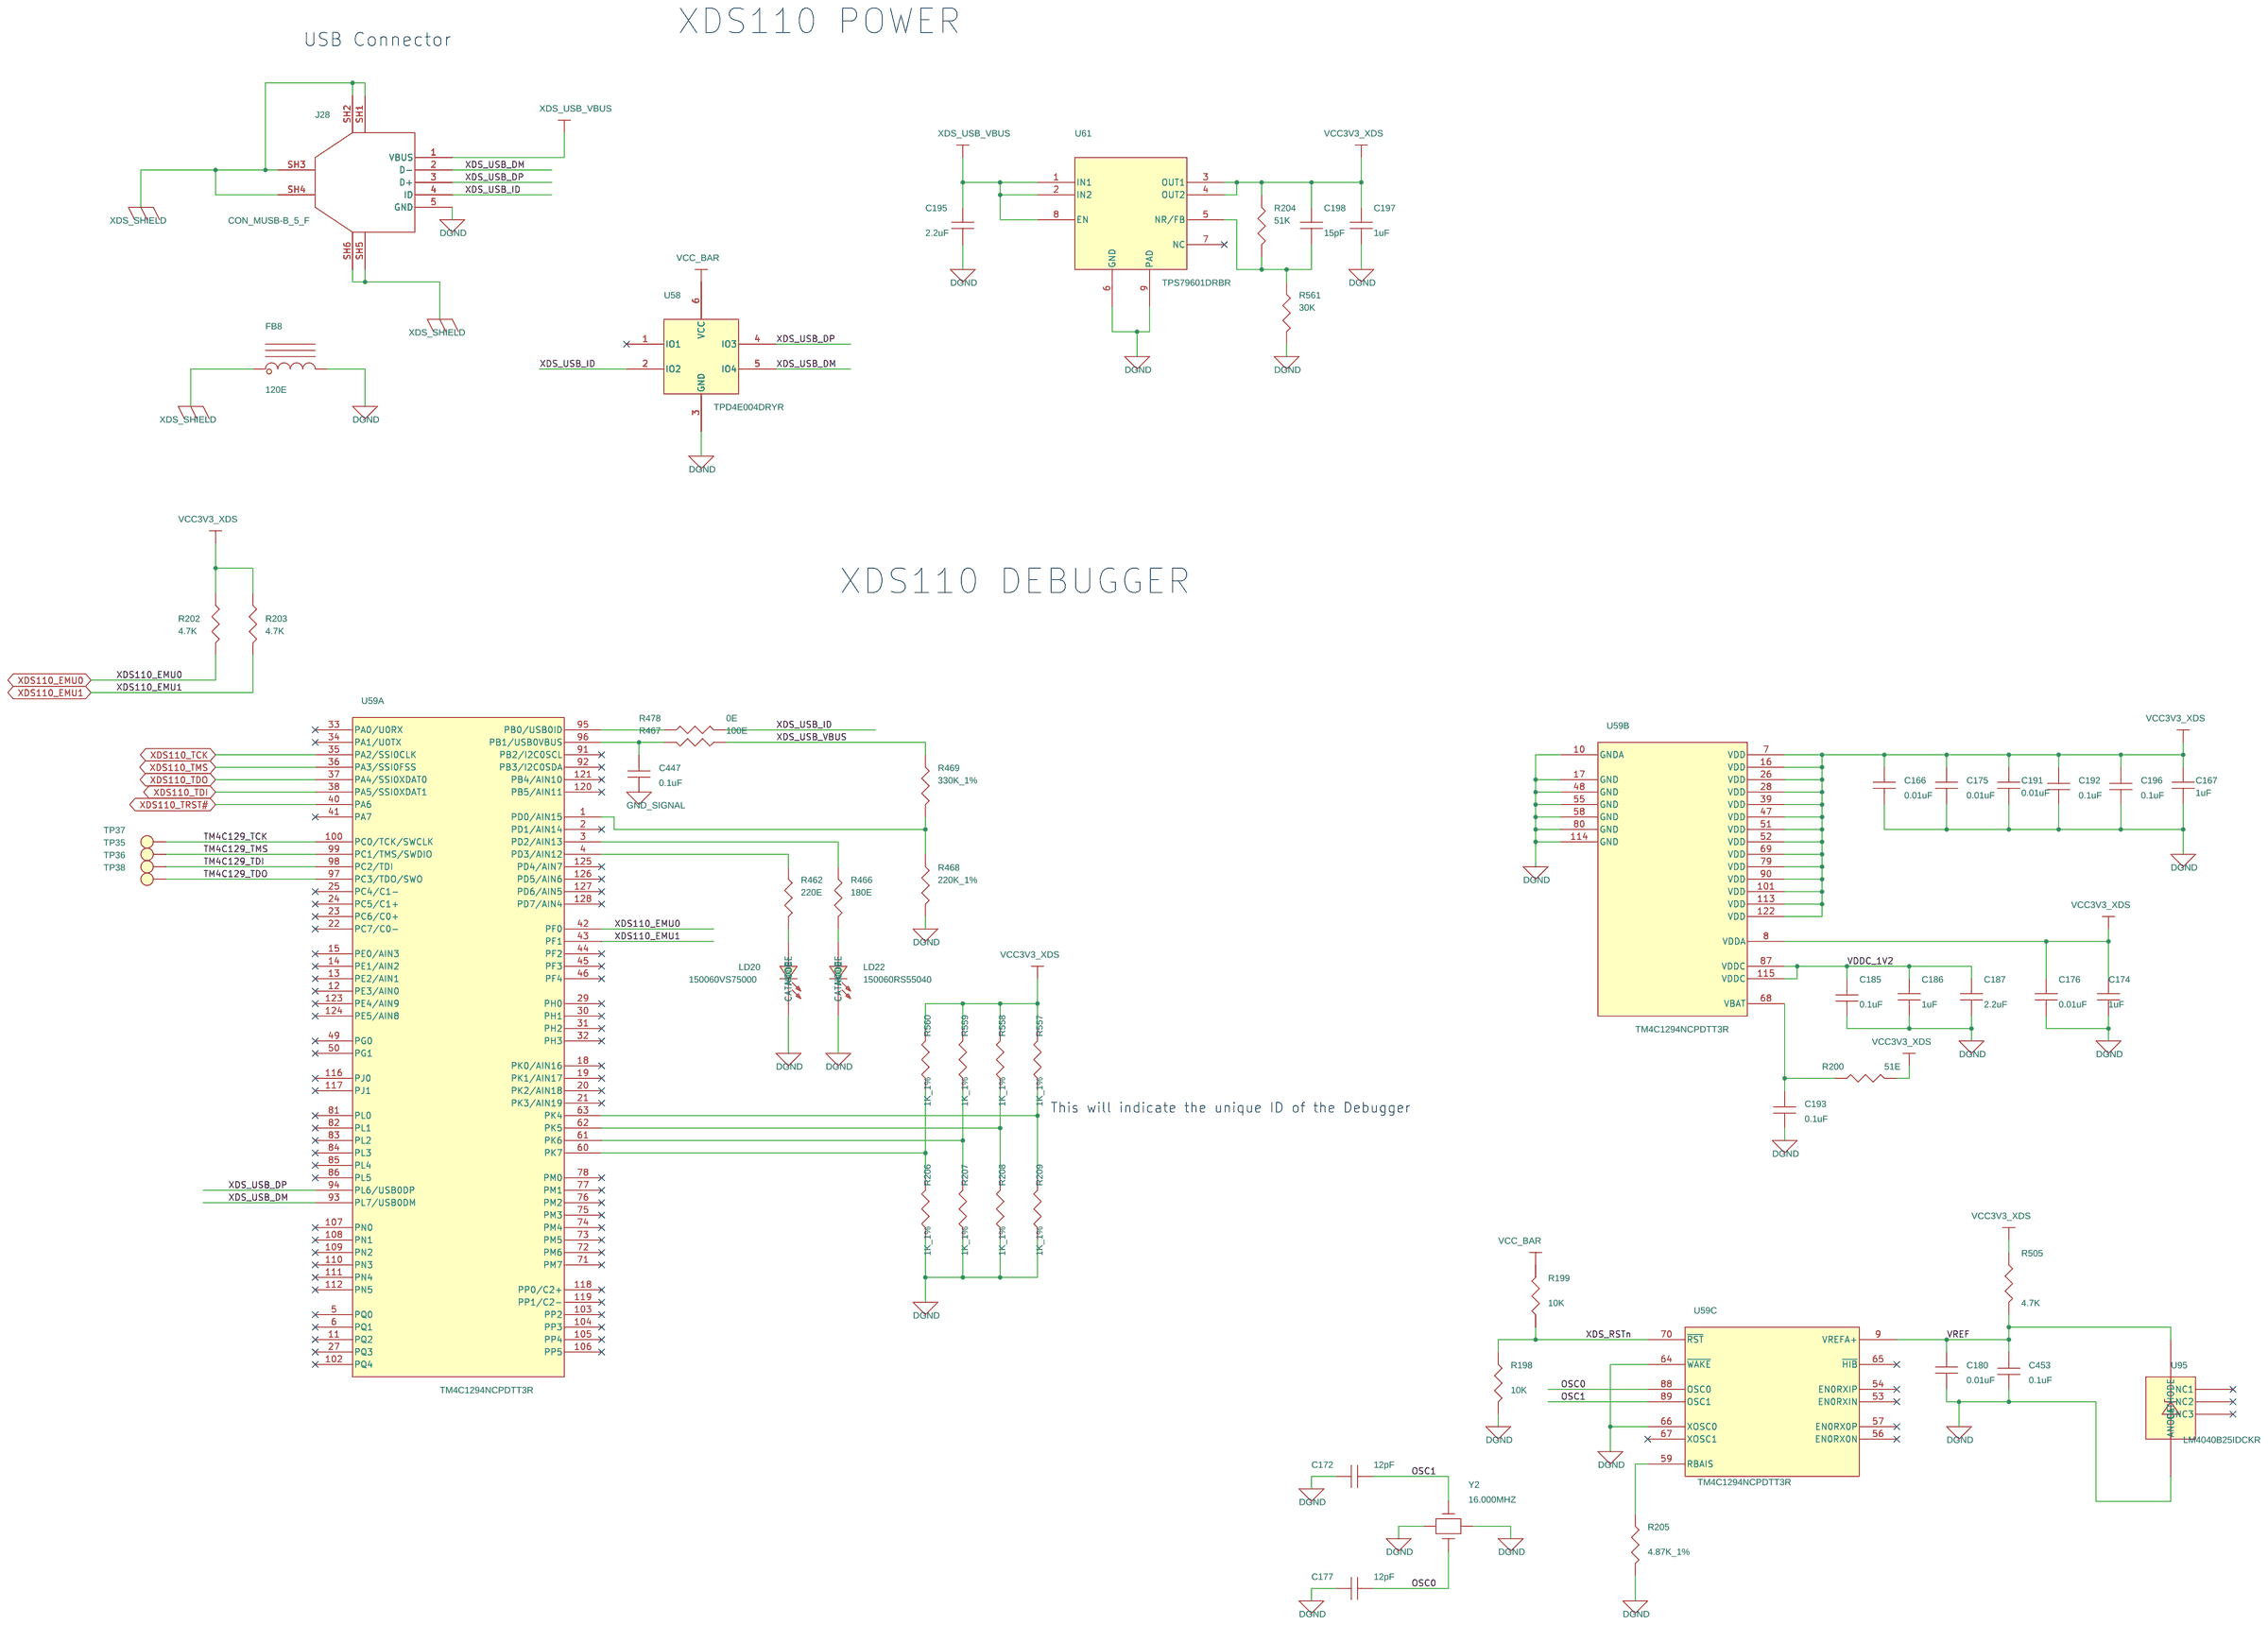
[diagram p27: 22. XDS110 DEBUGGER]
29 20. BOOT MODE BUFFER & SWITCHES: size C; title: BOOT MODE BUFFER & SWITCHES
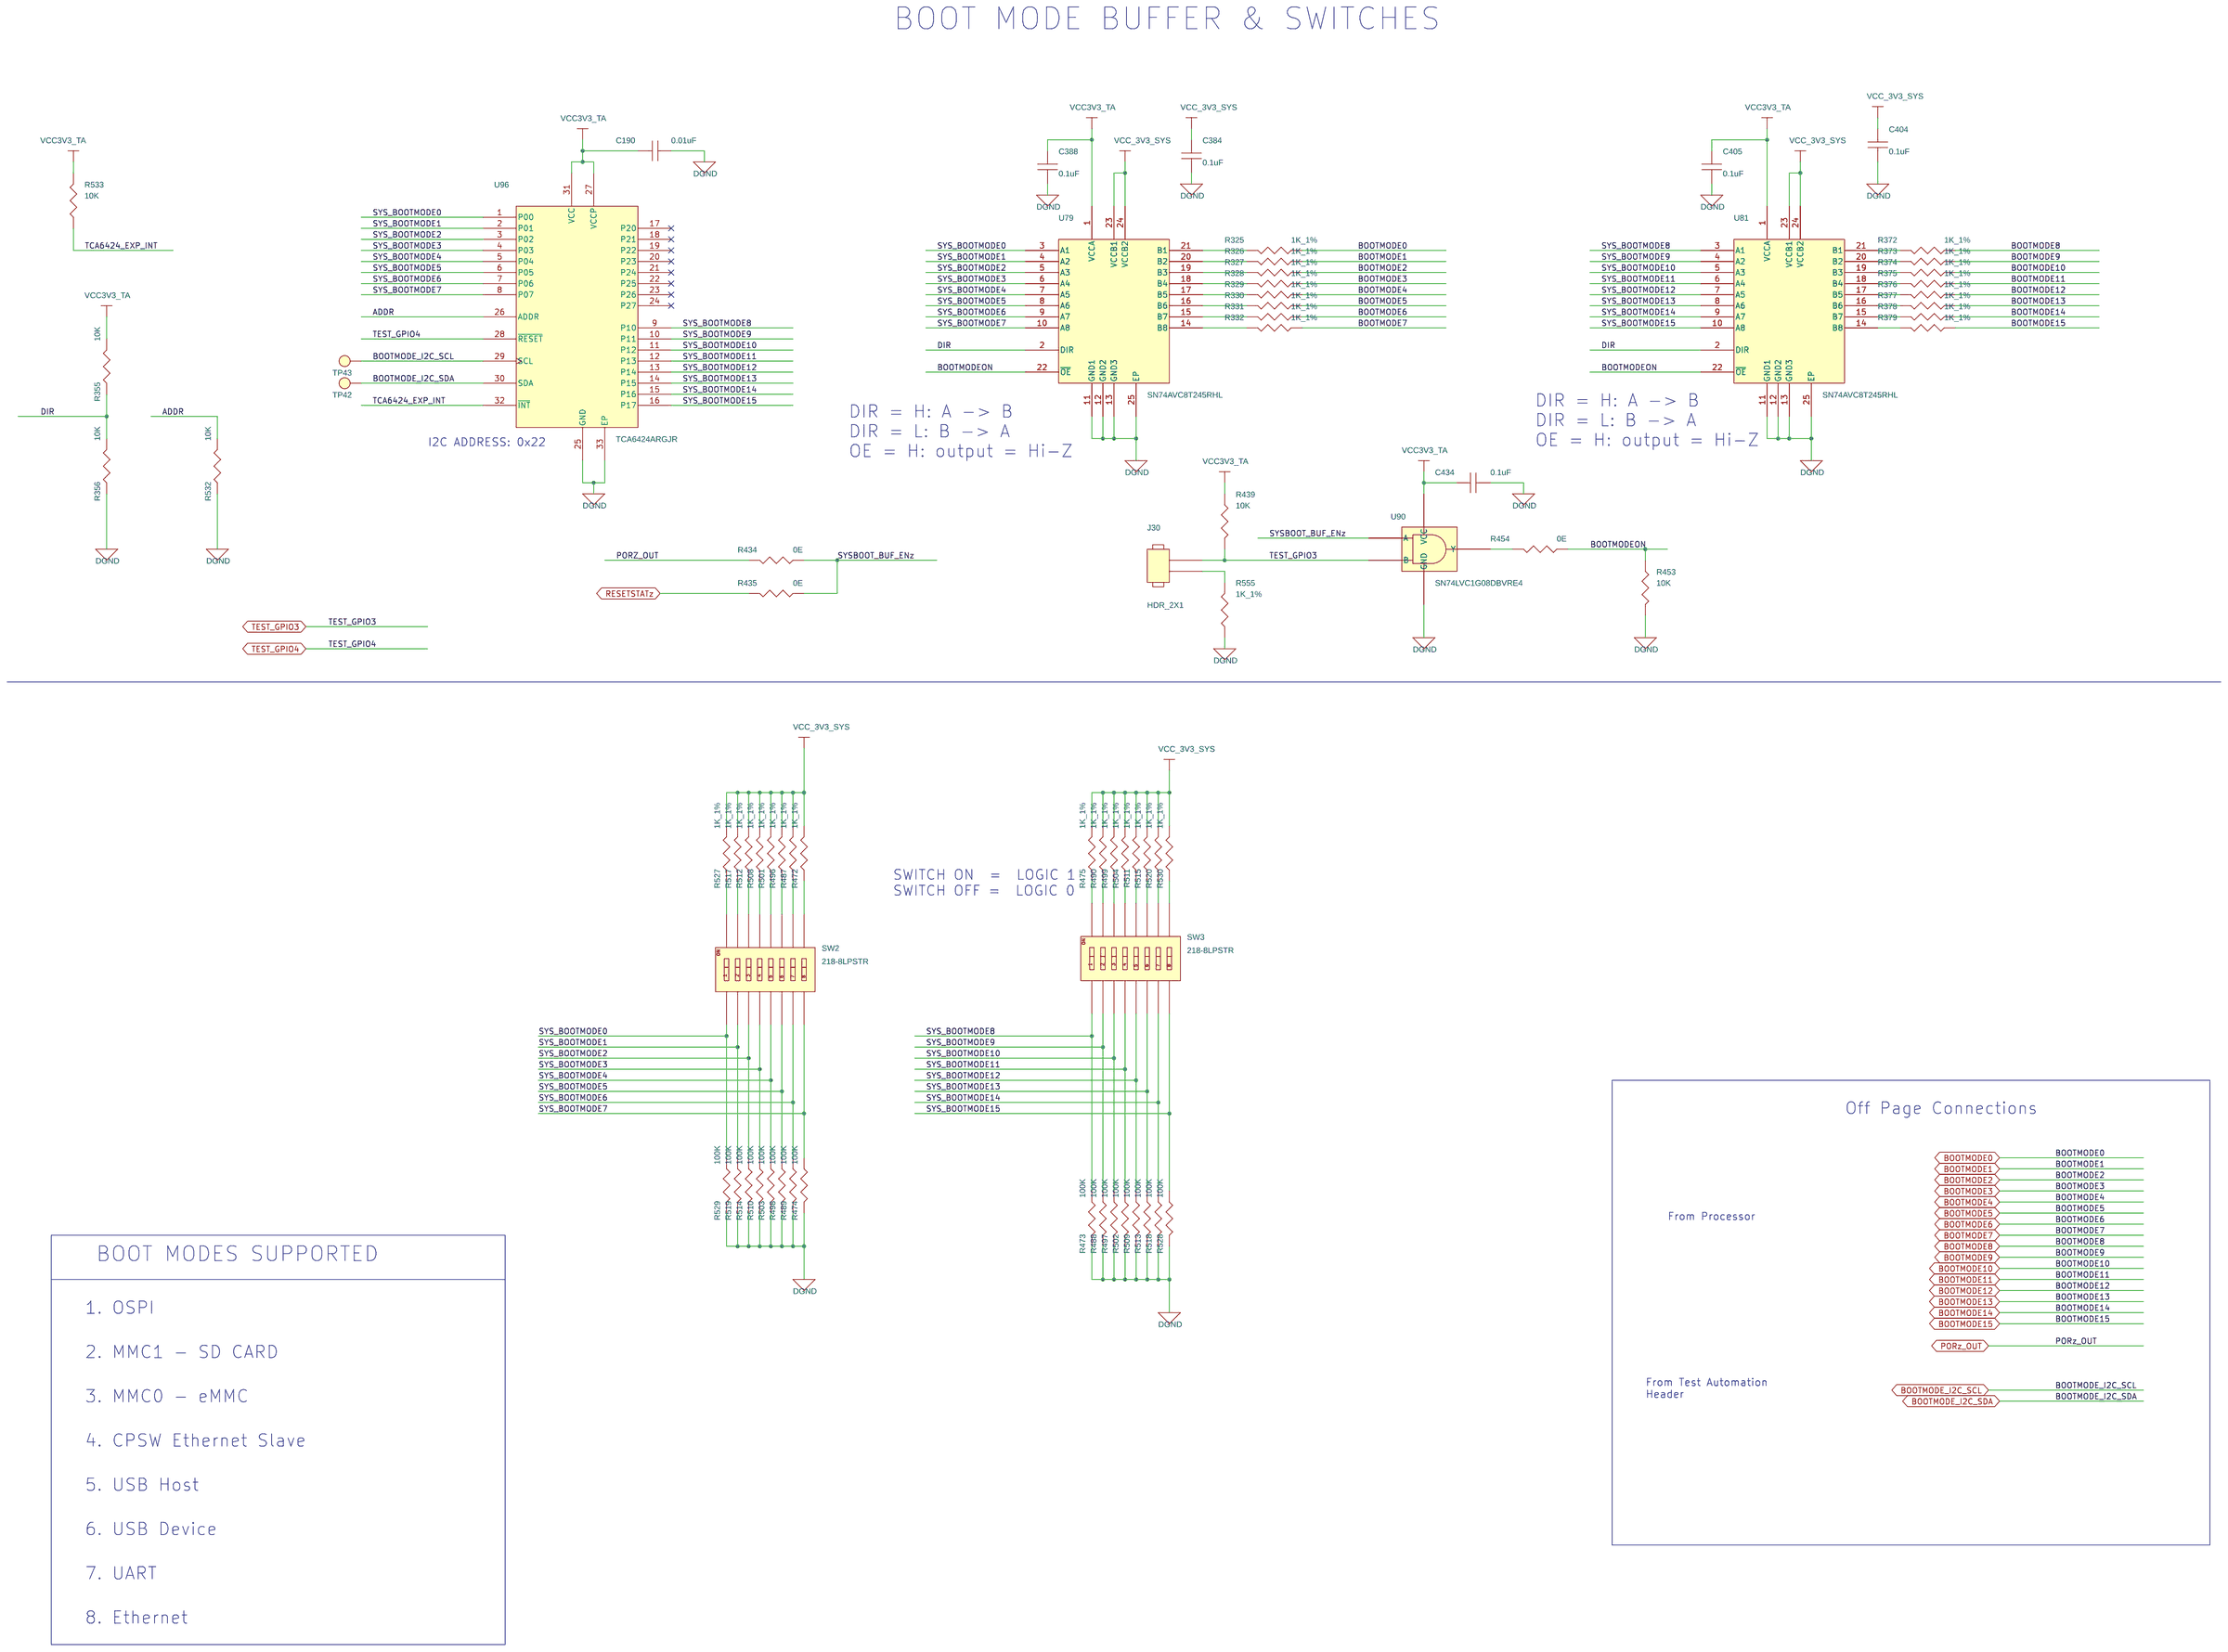
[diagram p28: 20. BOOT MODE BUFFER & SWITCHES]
30 19. TEST AUTOMATION: size C; title: TEST AUTOMATION

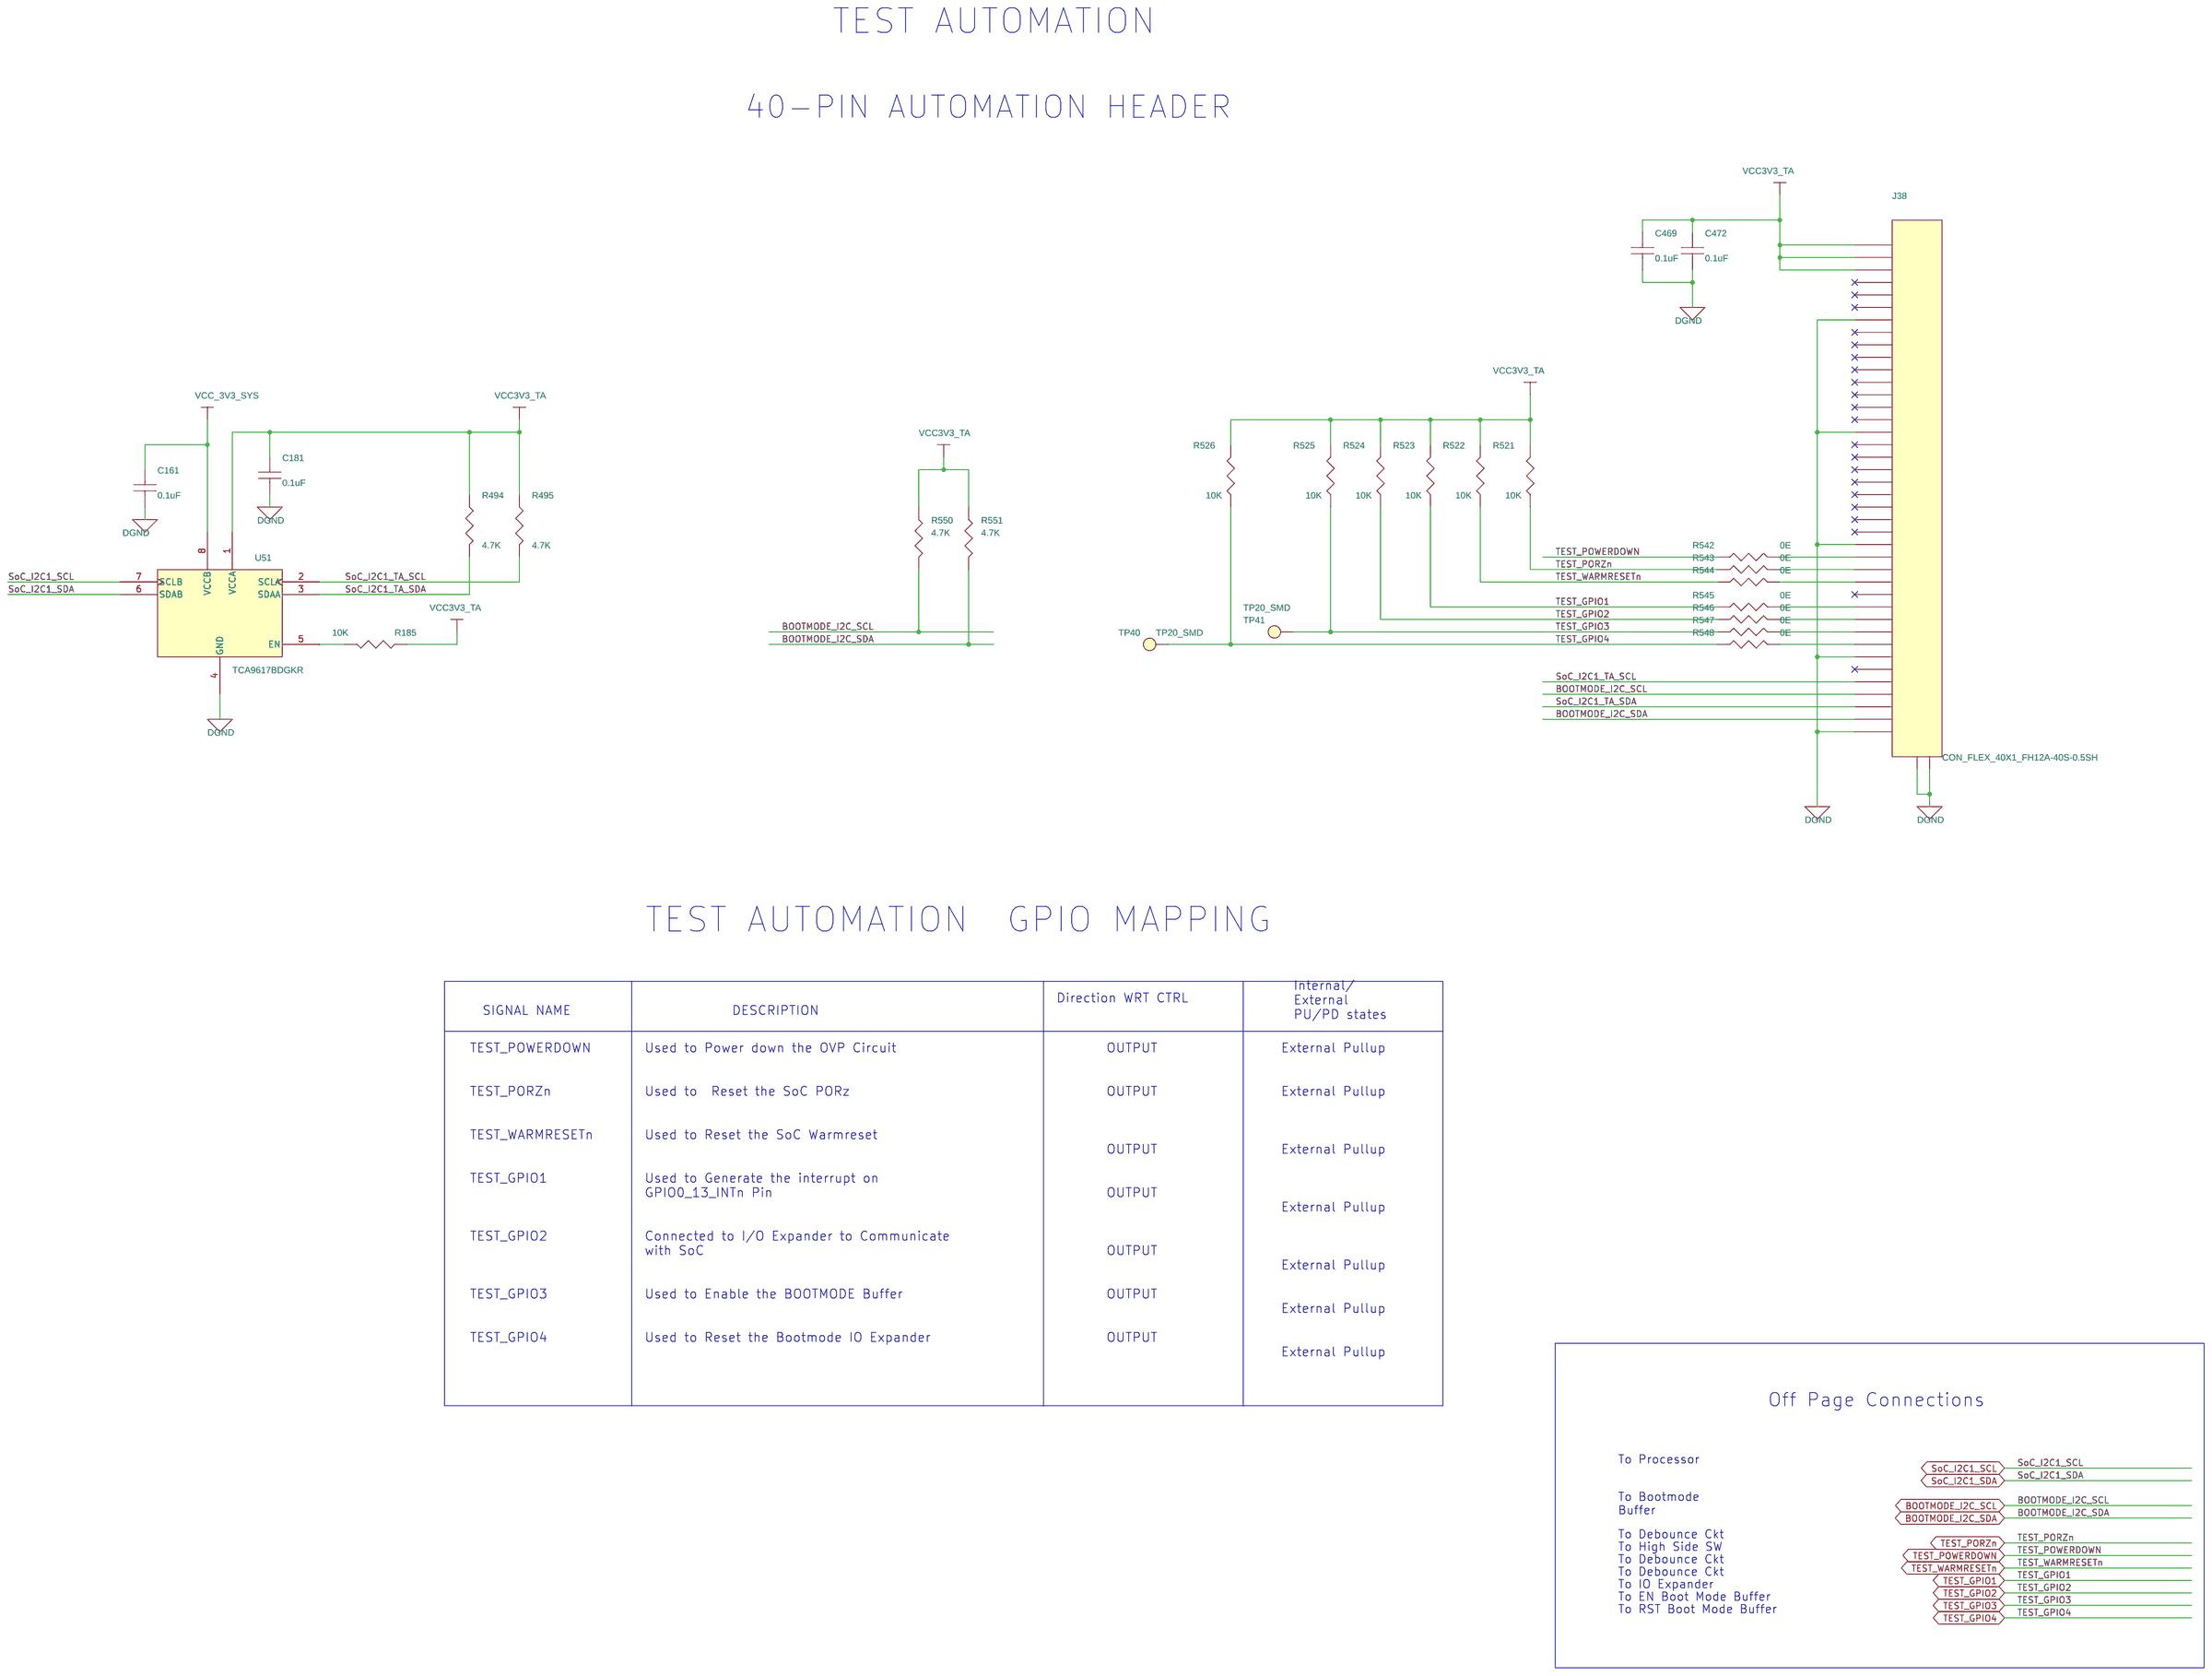
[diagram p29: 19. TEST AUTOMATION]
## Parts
sheet 19. TEST AUTOMATION
C161  0.1uF  [CAP0402_0-75]
C181  0.1uF  [CAP0402_0-75]
C469  0.1uF  [CAP0402_0-75]
C472  0.1uF  [CAP0402_0-75]
J38  CON_FLEX_40X1_FH12A-40S-0.5SH  [CON_FLEX40X1_FH12A_S_R_S]
R185  10K  [RES0402_0-5]
R494  4.7K  [RES0402_0-5]
R495  4.7K  [RES0402_0-5]
R521  10K  [RES0402_0-5]
R522  10K  [RES0402_0-5]
R523  10K  [RES0402_0-5]
R524  10K  [RES0402_0-5]
R525  10K  [RES0402_0-5]
R526  10K  [RES0402_0-5]
R542  0E  [RES0402_0-5]
R543  0E  [RES0402_0-5]
R544  0E  [RES0402_0-5]
R545  0E  [RES0402_0-5]
R546  0E  [RES0402_0-5]
R547  0E  [RES0402_0-5]
R548  0E  [RES0402_0-5]
R550  4.7K  [RES0402_0-5]
R551  4.7K  [RES0402_0-5]
TP40  TP20_SMD  [TP20_SMD]
TP41  TP20_SMD  [TP20_SMD]
U51  TCA9617BDGKR  [VSSOP8_25-59_120X120_1-1]
sheet 20. BOOT MODE BUFFER & SWITCHES
C190  0.01uF  [CAP0402_0-75]
C384  0.1uF  [CAP0402_0-75]
C388  0.1uF  [CAP0402_0-75]
C404  0.1uF  [CAP0402_0-75]
C405  0.1uF  [CAP0402_0-75]
C434  0.1uF  [CAP0402_0-75]
J30  HDR_2X1  [HDR_2X1_100_S_T_10-8]
R325  1K_1%  [RES0402_0-5]
R326  1K_1%  [RES0402_0-5]
R327  1K_1%  [RES0402_0-5]
R328  1K_1%  [RES0402_0-5]
R329  1K_1%  [RES0402_0-5]
R330  1K_1%  [RES0402_0-5]
R331  1K_1%  [RES0402_0-5]
R332  1K_1%  [RES0402_0-5]
R355  10K  [RES0402_0-5]
R356  10K  [RES0402_0-5]
R372  1K_1%  [RES0402_0-5]
R373  1K_1%  [RES0402_0-5]
R374  1K_1%  [RES0402_0-5]
R375  1K_1%  [RES0402_0-5]
R376  1K_1%  [RES0402_0-5]
R377  1K_1%  [RES0402_0-5]
R378  1K_1%  [RES0402_0-5]
R379  1K_1%  [RES0402_0-5]
R434  0E  [RES0402_0-5]
R435  0E  [RES0402_0-5]
R439  10K  [RES0402_0-5]
R453  10K  [RES0402_0-5]
R454  0E  [RES0402_0-5]
R472  1K_1%  [RES0402_0-5]
R473  100K  [RES0402_0-5]
R474  100K  [RES0402_0-5]
R475  1K_1%  [RES0402_0-5]
R487  1K_1%  [RES0402_0-5]
R488  100K  [RES0402_0-5]
R489  100K  [RES0402_0-5]
R490  1K_1%  [RES0402_0-5]
R496  1K_1%  [RES0402_0-5]
R497  100K  [RES0402_0-5]
R498  100K  [RES0402_0-5]
R499  1K_1%  [RES0402_0-5]
R501  1K_1%  [RES0402_0-5]
R502  100K  [RES0402_0-5]
R503  100K  [RES0402_0-5]
R504  1K_1%  [RES0402_0-5]
R508  1K_1%  [RES0402_0-5]
R509  100K  [RES0402_0-5]
R510  100K  [RES0402_0-5]
R511  1K_1%  [RES0402_0-5]
R512  1K_1%  [RES0402_0-5]
R513  100K  [RES0402_0-5]
R514  100K  [RES0402_0-5]
R515  1K_1%  [RES0402_0-5]
R517  1K_1%  [RES0402_0-5]
R518  100K  [RES0402_0-5]
R519  100K  [RES0402_0-5]
R520  1K_1%  [RES0402_0-5]
R527  1K_1%  [RES0402_0-5]
R528  100K  [RES0402_0-5]
R529  100K  [RES0402_0-5]
R530  1K_1%  [RES0402_0-5]
R532  10K  [RES0402_0-5]
R533  10K  [RES0402_0-5]
R555  1K_1%  [RES0402_0-5]
SW2  218-8LPSTR  [SW8_218-8LPST_450X230_SMD_2-7]
SW3  218-8LPSTR  [SW8_218-8LPST_450X230_SMD_2-7]
TP42  TP20_SMD  [TP20_SMD]
TP43  TP20_SMD  [TP20_SMD]
U79  SN74AVC8T245RHL  [QFN24_19-68_220X140_1]
U81  SN74AVC8T245RHL  [QFN24_19-68_220X140_1]
U90  SN74LVC1G08DBVRE4  [SOT23-5]
U96  TCA6424ARGJR  [QFN32_19-68_200X200]
sheet 22. XDS110 DEBUGGER
C166  0.01uF  [CAP0402_0-75]
C167  1uF  [CAP0402_0-75]
C172  12pF  [CAP0201_0-5]
C174  1uF  [CAP0402_0-75]
C175  0.01uF  [CAP0402_0-75]
C176  0.01uF  [CAP0402_0-75]
C177  12pF  [CAP0201_0-5]
C180  0.01uF  [CAP0402_0-75]
C185  0.1uF  [CAP0402_0-75]
C186  1uF  [CAP0402_0-75]
C187  2.2uF  [CAP0402_0-75]
C191  0.01uF  [CAP0402_0-75]
C192  0.1uF  [CAP0402_0-75]
C193  0.1uF  [CAP0402_0-75]
C195  2.2uF  [CAP0402_0-75]
C196  0.1uF  [CAP0402_0-75]
C197  1uF  [CAP0402_0-75]
C198  15pF  [CAP0402_0-75]
C447  0.1uF  [CAP0402_0-75]
C453  0.1uF  [CAP0402_0-75]
FB8  120E  [IND0603_1]
J28  CON_MUSB-B_5_F  [CON_MUSBB5_1051640001_S_R_S_2-5]
LD20  150060VS75000  [LED_150060SS75000_70X40_SMD_0-8]
LD22  150060RS55040  [LED_150060RS55040_70X40_SMD_0-5]
R198  10K  [RES0402_0-5]
R199  10K  [RES0402_0-5]
R200  51E  [RES0402_0-5]
R202  4.7K  [RES0402_0-5]
R203  4.7K  [RES0402_0-5]
R204  51K  [RES0402_0-5]
R205  4.87K_1%  [RES0402_0-5]
R206  1K_1%  [RES0402_0-5]
R207  1K_1%  [RES0402_0-5]
R208  1K_1%  [RES0402_0-5]
R209  1K_1%  [RES0402_0-5]
R462  220E  [RES0402_0-5]
R466  180E  [RES0402_0-5]
R467  100E  [RES0402_0-5]
R468  220K_1%  [RES0402_0-5]
R469  330K_1%  [RES0402_0-5]
R478  0E  [RES0402_0-5]
R505  4.7K  [RES0402_0-5]
R557  1K_1%  [RES0402_0-5]
R558  1K_1%  [RES0402_0-5]
R559  1K_1%  [RES0402_0-5]
R560  1K_1%  [RES0402_0-5]
R561  30K  [RES0402_0-5]
TP35  TP20_SMD  [TP20_SMD]
TP36  TP20_SMD  [TP20_SMD]
TP37  TP20_SMD  [TP20_SMD]
TP38  TP20_SMD  [TP20_SMD]
U58  TPD4E004DRYR  [SON6_19-68_40X60_PB_0-6]
U59  TM4C1294NCPDTT3R  [TQFP128_15-74_550X550_1-2]  (sections A,B,C)
U61  TPS79601DRBR  [SON8_25-59_130X130_1]
U95  LM4040B25IDCKR  [SC70-5_1-1]
Y2  16.000MHZ  [XTAL4_NX3225GA_130X100_SMD_0-9]

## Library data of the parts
C161 C181 C185 C192 C193 C196 C384 C388 C404 C405 C434 C447 C453 C469 C472 = CAP: CAP CERAMIC 0.1uF 25V 20% X5R 0402; Alt_Mfr_name: YAGEO AMERICA; Alt_Mfr_part_number: CC0402KRX5R8BB104; Chkd/date: MANIRAJA/170820; Crtd /date: ALVY/170820; Custom_Duty: 15%; Customs_HS_Code: 85322990; Distributor_name: DIGIKEY; Distributor_part_number: 732-7495-1-ND; Footprint Path: Y:\MIS_DATABASE\Library\ALTIUM_TOOL\PCB_FOOTPRINTS\Altium_Footprint_Lib.PcbLib; Height: 0.55MM; Library Path: Y:\MIS_DATABASE\Library\ALTIUM_TOOL\SCHEMATICS_PARTS\MS_DISCRETE_Library.schlib; Mfr_name: WURTH ELECTRONICS; Mfr_part_number: 885012105018; Mistral Part No: 120020080003-R; Package: 0402; Part_type: CAPACITORS\CERAMIC; Project: AM64x_EVM_BRD; RoHS: RoHS; Temperature: -55°C+85°C; Tolerance: 20%; Voltage: 25V; Wattage: NA; Weight: 0.65mg; Datasheet: Y:\MIS_DATABASE\DATASHEETS\CAPACITORS\885012105018.PDF
J38 = CON_FLEX_40X1_FH12A-40S-0.5SH: CON FPC 40X1 0.50MM PITCH RT TOP SMD; Chkd/date: SHREESHAIL/201106; Crtd /date: MAZHAR/171106; Custom_Duty: 24%; Customs_HS_Code: 85369090; Distributor_name: DIGIKEY; Distributor_part_number: HFK40CT-ND; Height: 2.00MM; Mfr_name: HIROSE ELECTRIC EUROPE; Mfr_part_number: FH12A-40S-0.5SH(55); Mistral Part No: 150009030176-R; Package: SMD; Part_type: CONNECTOR\FPC; Project: PMP LCD BOARD; Datasheet: Y:\MIS_DATABASE\DATASHEETS\CONNECTORS\FH12SERIES.PDF
R185 R198 R199 R355 R356 R439 R453 R521-R526 R532 R533 = RESISTOR: RES 10K 1/16W 5% 0402; Chkd/date: VASANTHA/061216; Crtd /date: MAZHAR/230805; Custom_Duty: 15%; Customs_HS_Code: 85332119; Distributor_name: DIGIKEY; Distributor_part_number: 311-10KJRCT-ND; Footprint Path: Y:\MIS_DATABASE\Library\ALTIUM_TOOL\PCB_FOOTPRINTS\Altium_Footprint_Lib.PcbLib; Height: 0.40MM; Library Path: Y:\MIS_DATABASE\Library\ALTIUM_TOOL\SCHEMATICS_PARTS\MS_DISCRETE_Library.schlib; Mfr_name: YAGEO AMERICA; Mfr_part_number: RC0402JR-0710KL; Mistral Part No: 110011060021-R; Package: 0402; Part_type: RESISTORS\FIXED; Project: HSE; RoHS: RoHS; Temperature: -55°C+155°C; Tolerance: 5%; Voltage: NA; Wattage: 1/16W; Weight: 0.65mg; Datasheet: Y:\MIS_DATABASE\DATASHEETS\RESISTORS\RCXXXXL-SER_MAR18.PDF
R202 R203 R494 R495 R505 R550 R551 = RESISTOR: RES 4.7K 1/16W 5% 0402; Chkd/date: VASANTHA/130516; Crtd /date: VASANTHA/130516; Custom_Duty: 15%; Customs_HS_Code: 85332119; Distributor_name: DIGIKEY; Distributor_part_number: 311-4.7KJRCT-ND; Footprint Path: Y:\MIS_DATABASE\Library\ALTIUM_TOOL\PCB_FOOTPRINTS\Altium_Footprint_Lib.PcbLib; Height: 0.40MM; Library Path: Y:\MIS_DATABASE\Library\ALTIUM_TOOL\SCHEMATICS_PARTS\MS_DISCRETE_Library.schlib; Mfr_name: YAGEO AMERICA; Mfr_part_number: RC0402JR-074K7L; Mistral Part No: 110011060001-R; Package: 0402; Part_type: RESISTORS\FIXED; Project: TMDXCSK368; RoHS: RoHS; Temperature: -55°C+155°C; Tolerance: 5%; Voltage: NA; Wattage: 1/16W; Weight: 0.65mg; Datasheet: Y:\MIS_DATABASE\DATASHEETS\RESISTORS\RCXXXXL-SER_MAR18.PDF
R434 R435 R454 R478 R542-R548 = RESISTOR: RES 0E 1/16W JUMPER 0402; Chkd/date: VASANTHA/201216; Crtd /date: MUDDU/190810; Custom_Duty: 15%; Customs_HS_Code: 85332119; Distributor_name: DIGIKEY; Distributor_part_number: 541-0.0JCT-ND; Footprint Path: Y:\MIS_DATABASE\Library\ALTIUM_TOOL\PCB_FOOTPRINTS\Altium_Footprint_Lib.PcbLib; Height: 0.40MM; Library Path: Y:\MIS_DATABASE\Library\ALTIUM_TOOL\SCHEMATICS_PARTS\MS_DISCRETE_Library.schlib; Mfr_name: VISHAY; Mfr_part_number: CRCW04020000Z0ED; Mistral Part No: 110010080019-R; Package: 0402; Part_type: RESISTORS\FIXED; Project: PB_BUGBASE; RoHS: RoHS; Temperature: -55°C+155°C; Tolerance: NA; Voltage: NA; Wattage: 1/16W; Weight: 0.65mg; Datasheet: Y:\MIS_DATABASE\DATASHEETS\RESISTORS\CRCW0603.PDF
TP35-TP38 TP40-TP43 = TESTPOINT: TESTPOINT CIR 20 SMD; Chkd/date: SHREESHAIL/171006; Crtd /date: MAZHAR/171006; Custom_Duty: NA; Customs_HS_Code: NA; Distributor_name: NA; Distributor_part_number: NA; Footprint Path: Y:\MIS_DATABASE\Library\ALTIUM_TOOL\PCB_FOOTPRINTS\Altium_Footprint_Lib.PcbLib; Height: NA; Library Path: Y:\MIS_DATABASE\Library\ALTIUM_TOOL\SCHEMATICS_PARTS\MS_DISCRETE_Library.schlib; MECHANICAL 3D STEP FILE: NA; Mfr_name: LOCAL; Mistral Part No: NA; Package: SMD; Project: BT MODULE_CSRBC04; RoHS: NA; Temperature: NA; Tolerance: NA; Voltage: NA; Wattage: NA; Weight: NA; Datasheet: NA
U51 = TCA9617BDGKR_VSSOP8: IC FM+I2C BUS REPEATER LEVEL TRANSLATOR VSSOP8; Chkd/date: MANIRAJA/131017; Crtd /date: MANIRAJA/131017; Custom_Duty: 15%; Customs_HS_Code: 85423100; Distributor_name: DIGIKEY; Distributor_part_number: 296-40579-1-ND; Height: 1.10MM; Mfr_name: TEXAS INSTRUMENTS; Mistral Part No: 141017100010-R; Package: VSSOP8; Part_type: ICS\INTERFACE\LEVEL TRANSLATOR; Project: TI_MAXIE_CPB; RoHS: RoHS; Temperature: -40°C+85°C; Tolerance: NA; Voltage: NA; Wattage: NA; Weight: NA; Datasheet: Y:\MIS_DATABASE\DATASHEETS\ICS\INTERFACE\TCA9617B.PDF
C166 C175 C176 C180 C190 C191 = CAP: CAP CERAMIC 0.01uF 25V 10% X7R 0402; Chkd/date: MANIRAJA/170820; Crtd /date: ALVY/170820; Custom_Duty: 15%; Customs_HS_Code: 85322990; Distributor_name: DIGIKEY; Distributor_part_number: 732-7545-1-ND; Footprint Path: Y:\MIS_DATABASE\Library\ALTIUM_TOOL\PCB_FOOTPRINTS\Altium_Footprint_Lib.PcbLib; Height: 0.55MM; Library Path: Y:\MIS_DATABASE\Library\ALTIUM_TOOL\SCHEMATICS_PARTS\MS_DISCRETE_Library.schlib; Mfr_name: WURTH ELECTRONICS; Mfr_part_number: 885012205050; Mistral Part No: 120011090040-R; Package: 0402; Part_type: CAPACITORS\CERAMIC; Project: AM64x_EVM_BRD; RoHS: RoHS; Temperature: -55°C+125°C; Tolerance: 10%; Voltage: 25V; Wattage: NA; Weight: 0.65mg; Datasheet: Y:\MIS_DATABASE\DATASHEETS\CAPACITORS\885012205050.PDF
J30 = HEADER_2X1: CON HDR 2X1 2.54MM PITCH ST TH; Chkd/date: VASANTHA/060117; Crtd /date: MAZHAR/280405; Custom_Duty: 24%; Customs_HS_Code: 85369090; Distributor_name: DIGIKEY; Distributor_part_number: WM4000-ND; Footprint Path: Y:\MIS_DATABASE\Library\ALTIUM_TOOL\PCB_FOOTPRINTS\Altium_Footprint_Lib.PcbLib; Height: 10.79MM; Library Path: Y:\MIS_DATABASE\Library\ALTIUM_TOOL\SCHEMATICS_PARTS\MS_Connector_Library.schlib; Mfr_name: MOLEX; Mfr_part_number: 22-03-2021; Mistral Part No: 150009030246-R; Package: THRU-HOLE; Part_type: CONNECTOR\HEADERS; Project: FPGA EXTENDER CARD; RoHS: RoHS; Temperature: -0°C+75°C; Tolerance: NA; Voltage: NA; Wattage: NA; Weight: 139gm; Datasheet: Y:\MIS_DATABASE\DATASHEETS\CONNECTORS\HEADER_X4030.PDF
R206-R209 R325-R332 R372-R379 R472 R475 R487 R490 R496 R499 R501 R504 R508 R511 R512 R515 R517 R520 R527 R530 R555 R557-R560 = RESISTOR: RES 1K 1/10W 1% 0402; Chkd/date: VASANTHA/281216; Crtd /date: MAZHAR/150506; Custom_Duty: 15%; Customs_HS_Code: 85332119; Distributor_name: DIGIKEY; Distributor_part_number: P1.00KLCT-ND; Footprint Path: Y:\MIS_DATABASE\Library\ALTIUM_TOOL\PCB_FOOTPRINTS\Altium_Footprint_Lib.PcbLib; Height: 0.40MM; Library Path: Y:\MIS_DATABASE\Library\ALTIUM_TOOL\SCHEMATICS_PARTS\MS_DISCRETE_Library.schlib; Mfr_name: PANASONIC-ECG; Mfr_part_number: ERJ-2RKF1001X; Mistral Part No: 110009030411-R; Package: 0402; Part_type: RESISTORS\FIXED; Project: VOCERA; RoHS: RoHS; Temperature: -55°C+155°C; Tolerance: 1%; Voltage: NA; Wattage: 1/10W; Weight: 0.8mg; Datasheet: Y:\MIS_DATABASE\DATASHEETS\RESISTORS\PAN-ERJSER_NOV17.PDF
R473 R474 R488 R489 R497 R498 R502 R503 R509 R510 R513 R514 R518 R519 R528 R529 = RESISTOR: RES 100K 1/16W 5% 0402; Chkd/date: VASANTHA/061216; Crtd /date: BAVISH/010611; Custom_Duty: 15%; Customs_HS_Code: 85332119; Distributor_name: DIGIKEY; Distributor_part_number: 541-100KJCT-ND; Footprint Path: Y:\MIS_DATABASE\Library\ALTIUM_TOOL\PCB_FOOTPRINTS\Altium_Footprint_Lib.PcbLib; Height: 0.40MM; Library Path: Y:\MIS_DATABASE\Library\ALTIUM_TOOL\SCHEMATICS_PARTS\MS_DISCRETE_Library.schlib; Mfr_name: VISHAY; Mfr_part_number: CRCW0402100KJNED; Mistral Part No: 110011060002-R; Package: 0402; Part_type: RESISTORS\FIXED; Project: AM4515_EVM_LCD; RoHS: RoHS; Temperature: -55°C+155°C; Tolerance: 5%; Voltage: NA; Wattage: 1/16W; Weight: 0.65mg; Datasheet: Y:\MIS_DATABASE\DATASHEETS\RESISTORS\CRCW0603.PDF
SW2 SW3 = SW8_218-8LPSTR: SWITCH DIP SPST HALF PITCH 8POS SMD; Chkd/date: MANIRAJA/230817; Crtd /date: MANIRAJA/230817; Custom_Duty: 24%; Customs_HS_Code: 85369090; Distributor_name: DIGIKEY; Distributor_part_number: CT3112CT-ND; Height: 2.65MM; Mfr_name: CTS; Mistral Part No: 130017080019-R; Package: SMD; Part_type: ELECTRO-MECHANICAL\SWITCH; Project: TI_RF_DC CARD; RoHS: RoHS; Temperature: -55°C+85°C; Tolerance: NA; Voltage: NA; Wattage: NA; Weight: NA; Datasheet: Y:\MIS_DATABASE\DATASHEETS\MISC\SWITCHES\128-12LPST.PDF
U79 U81 = SN74AVC8T245RHL_QFN24: IC BUS TRANSCEIVER 8-BIT DUAL-SUPPLY QFN24; Chkd/date: VASANTHA/231216; Crtd /date: BAVISH/290411; Custom_Duty: 15%; Customs_HS_Code: 85423100; Distributor_name: DIGIKEY; Distributor_part_number: 296-17859-1-ND; Height: 1.00MM; Mfr_name: TEXAS INSTRUMENTS; Mfr_part_number: SN74AVC8T245RHLR; Mistral Part No: 143011040001-R; Package: QFN24; Part_type: ICS\TELECOM\TRANSCEIVER; Project: OMAPL1_PEC20; RoHS: RoHS; Temperature: -40°C+85°C; Tolerance: NA; Voltage: NA; Wattage: NA; Weight: NA; Datasheet: Y:\MIS_DATABASE\DATASHEETS\ICS\DIGITAL\BUSTRANSCEIVER\SN74AVC8T245.PDF
U90 = SN74LVC1G08DBVRE4_SOT23-5: IC SINGLE 2-INPUT POSITIVE AND GATE SOT23-5; Chkd/date: SUHAS/221010; Crtd /date: USMAN/151008; Custom_Duty: 15%; Customs_HS_Code: 85423100; Distributor_name: DIGIKEY; Distributor_part_number: SN74LVC1G08DBVRE4-ND; Height: 1.45MM; Mfr_name: TEXAS INSTRUMENTS; Mistral Part No: 141009060026-R; Part_type: ICS\DIGITAL\GATES; Project: KHAN_MAIN; RoHS: Sb/ Br FREE; Temperature: -40°C+85°C; Datasheet: Y:\MIS_DATABASE\DATASHEETS\ICS\DIGITAL\GATES\SN74LVC1G08.PDF
U96 = TCA6424ARGJR_QFN32: IC I2C I/O EXPANDER 24B UQFN32; Chkd/date: NAVEED/100715; Crtd /date: NAVEED/100914; Custom_Duty: 15%; Customs_HS_Code: 85423100; Distributor_name: DIGIKEY; Distributor_part_number: 296-27844-1-ND; Height: 0.60MM; Mfr_name: TEXAS INSTRUMENTS; Mistral Part No: 141014090009-R; Package: UQFN32; Part_type: ICS\DIGITAL\BUSTRANSCEIVER; Project: ZK_BIOMETRIC; RoHS: RoHS; Temperature: -40°C+85°C; Weight: NA; Datasheet: Y:\MIS_DATABASE\DATASHEETS\ICS\DIGITAL\BUSTRANSCEIVER\TCA6424AR.PDF
C167 C174 C186 C197 = CAP: CAP CERAMIC 1uF 10V 20% X5R 0402; Chkd/date: MANIRAJA/210820; Crtd /date: ALVY/190820; Custom_Duty: 15%; Customs_HS_Code: 85322990; Distributor_name: DIGIKEY; Distributor_part_number: 732-7489-1-ND; Footprint Path: Y:\MIS_DATABASE\Library\ALTIUM_TOOL\PCB_FOOTPRINTS\Altium_Footprint_Lib.PcbLib; Height: 0.55MM; Library Path: Y:\MIS_DATABASE\Library\ALTIUM_TOOL\SCHEMATICS_PARTS\MS_DISCRETE_Library.schlib; Mfr_name: WURTH ELECTRONICS; Mfr_part_number: 885012105012; Mistral Part No: 120020080009-R; Package: 0402; Part_type: CAPACITORS\CERAMIC; Project: AM64x_EVM_BRD; RoHS: RoHS; Temperature: -55°C+85°C; Tolerance: 20%; Voltage: 10V; Wattage: NA; Weight: 0.65mg; Datasheet: Y:\MIS_DATABASE\DATASHEETS\CAPACITORS\885012105012.PDF
C172 C177 = CAP: CAP CERAMIC 12pF 25V 5% C0G(NP0) 0201; Chkd/date: MANIRAJA/020620; Crtd /date: ALVY/300520; Custom_Duty: 15%; Customs_HS_Code: 85322990; Distributor_name: DIGIKEY; Distributor_part_number: 490-3144-1-ND; Footprint Path: Y:\MIS_DATABASE\Library\ALTIUM_TOOL\PCB_FOOTPRINTS\Altium_Footprint_Lib.PcbLib; Height: 0.33MM; Library Path: Y:\MIS_DATABASE\Library\ALTIUM_TOOL\SCHEMATICS_PARTS\MS_DISCRETE_Library.schlib; Mfr_name: MURATA; Mfr_part_number: GRM0335C1E120JA01D; Mistral Part No: 120009030213-R; Package: 0201; Part_type: CAPACITORS\CERAMIC; Project: QCS610_NANOSOM; RoHS: RoHS; Temperature: -55°C+125°C; Tolerance: 5%; Voltage: 25V; Wattage: NA; Weight: 0.33mg; Datasheet: Y:\MIS_DATABASE\DATASHEETS\CAPACITORS\GRM0335C1E120JA01.PDF
C187 C195 = CAP: CAP CERAMIC 2.2uF 10V 20% X5R 0402; Chkd/date: MANIRAJA/170820; Crtd /date: ALVY/170820; Custom_Duty: 15%; Customs_HS_Code: 85322990; Distributor_name: DIGIKEY; Distributor_part_number: 732-7490-1-ND; Footprint Path: Y:\MIS_DATABASE\Library\ALTIUM_TOOL\PCB_FOOTPRINTS\Altium_Footprint_Lib.PcbLib; Height: 0.55MM; Library Path: Y:\MIS_DATABASE\Library\ALTIUM_TOOL\SCHEMATICS_PARTS\MS_DISCRETE_Library.schlib; Mfr_name: WURTH ELECTRONICS; Mfr_part_number: 885012105013; Mistral Part No: 120019040036-R; Package: 0402; Part_type: CAPACITORS\CERAMIC; Project: AM64x_EVM_BRD; RoHS: RoHS; Temperature: -55°C+85°C; Tolerance: 20%; Voltage: 10V; Wattage: NA; Weight: 0.65mg; Datasheet: Y:\MIS_DATABASE\DATASHEETS\CAPACITORS\885012105013.PDF
C198 = CAP: CAP CERAMIC 15pF 25V 5% C0G(NP0) 0402; Chkd/date: MANIRAJA/170820; Crtd /date: ALVY/170820; Custom_Duty: 15%; Customs_HS_Code: 85322990; Distributor_name: DIGIKEY; Distributor_part_number: 732-7456-1-ND; Footprint Path: Y:\MIS_DATABASE\Library\ALTIUM_TOOL\PCB_FOOTPRINTS\Altium_Footprint_Lib.PcbLib; Height: 0.55MM; Library Path: Y:\MIS_DATABASE\Library\ALTIUM_TOOL\SCHEMATICS_PARTS\MS_DISCRETE_Library.schlib; Mfr_name: WURTH ELECTRONICS; Mfr_part_number: 885012005041; Mistral Part No: 120020020004-R; Package: 0402; Part_type: CAPACITORS\CERAMIC; Project: AM64x_EVM_BRD; RoHS: RoHS; Temperature: -55°C+125°C; Tolerance: 5%; Voltage: 25V; Wattage: NA; Weight: 0.65mg; Datasheet: Y:\MIS_DATABASE\DATASHEETS\CAPACITORS\885012005041.PDF
FB8 = INDUCTOR_FERRITE: IND FERRITE BEAD CHIP 120E 2A 0603; Chkd/date: MANIRAJA/180820; Crtd /date: ALVY/180820; Custom_Duty: 24%; Customs_HS_Code: 85437099; Distributor_name: DIGIKEY; Distributor_part_number: 732-782631141CT-ND; Footprint Path: Y:\MIS_DATABASE\Library\ALTIUM_TOOL\PCB_FOOTPRINTS\Altium_Footprint_Lib.PcbLib; Height: 1.00MM; Library Path: Y:\MIS_DATABASE\Library\ALTIUM_TOOL\SCHEMATICS_PARTS\MS_FILTER_Library.schlib; Mfr_name: WURTH ELECTRONICS; Mfr_part_number: 782631141; Mistral Part No: 130020080015-R; Package: 0603; Part_type: INDUCTOR; Project: AM64x_EVM_BRD; RoHS: RoHS; Temperature: -55°C+125°C; Tolerance: 25%; Voltage: NA; Wattage: NA; Weight: NA; Datasheet: Y:\MIS_DATABASE\DATASHEETS\DISCRETES\INDUCTORS\782631141.PDF
J28 = CON_MUSB-B_5_1051640001: CON MICRO USB-B TYPE 5POS FEMALE RT SMD; Chkd/date: MANIRAJA/230817; Crtd /date: MANIRAJA/230817; Custom_Duty: 24%; Customs_HS_Code: 85369090; Distributor_name: DIGIKEY; Distributor_part_number: WM11263CT-ND; Height: 2.45MM; Mfr_name: MOLEX; Mfr_part_number: 1051640001; Mistral Part No: 150017080018-R; Package: SMD; Part_type: CONNECTOR\USB; Project: TI_MAXIE_CPB; RoHS: RoHS; Temperature: -35°C+85°C; Tolerance: NA; Voltage: NA; Wattage: NA; Weight: 234mg; Datasheet: Y:\MIS_DATABASE\DATASHEETS\CONNECTORS\1051640001.PDF
LD20 = DIODE_LED: DIODE LED BRIGHT GREEN SMD; Chkd/date: MANIRAJA/220720; Crtd /date: ALVY/210720; Custom_Duty: 24%; Customs_HS_Code: 85439000; Distributor_name: DIGIKEY; Distributor_part_number: 732-4980-1-ND; Footprint Path: Y:\MIS_DATABASE\Library\ALTIUM_TOOL\PCB_FOOTPRINTS\Altium_Footprint_Lib.PcbLib; Height: 0.80MM; Library Path: Y:\MIS_DATABASE\Library\ALTIUM_TOOL\SCHEMATICS_PARTS\MS_OPTO_Library.schlib; Mfr_name: WURTH ELECTRONICS; Mistral Part No: 130020070019-R; Package: SMD; Part_type: OPTO\LED; Project: AM64x-IO LINK BRD; RoHS: RoHS; Temperature: -40°C+85°C; Tolerance: NA; Voltage: NA; Wattage: NA; Weight: 25mg; Datasheet: Y:\MIS_DATABASE\DATASHEETS\DISCRETES\LEDS\150060VS75000.PDF
LD22 = DIODE_LED: DIODE LED RED SMD; Chkd/date: MANIRAJA/180820; Crtd /date: ALVY/180820; Custom_Duty: 24%; Customs_HS_Code: 85439000; Distributor_name: DIGIKEY; Distributor_part_number: 732-12015-1-ND; Footprint Path: Y:\MIS_DATABASE\Library\ALTIUM_TOOL\PCB_FOOTPRINTS\Altium_Footprint_Lib.PcbLib; Height: 0.50MM; Library Path: Y:\MIS_DATABASE\Library\ALTIUM_TOOL\SCHEMATICS_PARTS\MS_OPTO_Library.schlib; Mfr_name: WURTH ELECTRONICS; Mistral Part No: 130020080014-R; Package: SMD; Part_type: OPTO\LED; Project: AM64x_EVM_BRD; RoHS: RoHS; Temperature: -40°C+85°C; Tolerance: NA; Voltage: NA; Wattage: NA; Weight: 29mg; Datasheet: Y:\MIS_DATABASE\DATASHEETS\DISCRETES\LEDS\150060RS55040.PDF
R200 = RESISTOR: RES 51E 1/10W 5% 0402; Chkd/date: VASANTHA/291216; Crtd /date: MAZHAR/120505; Custom_Duty: 15%; Customs_HS_Code: 85332119; Distributor_name: DIGIKEY; Distributor_part_number: P51JCT-ND; Footprint Path: Y:\MIS_DATABASE\Library\ALTIUM_TOOL\PCB_FOOTPRINTS\Altium_Footprint_Lib.PcbLib; Height: 0.40MM; Library Path: Y:\MIS_DATABASE\Library\ALTIUM_TOOL\SCHEMATICS_PARTS\MS_DISCRETE_Library.schlib; Mfr_name: PANASONIC-ECG; Mfr_part_number: ERJ-2GEJ510X; Mistral Part No: 110009030962-R; Package: 0402; Part_type: RESISTORS\FIXED; Project: CTP02_REVA_BASE; RoHS: RoHS; Temperature: -55°C+155°C; Tolerance: 5%; Voltage: NA; Wattage: 1/10W; Weight: 0.8mg; Datasheet: Y:\MIS_DATABASE\DATASHEETS\RESISTORS\PAN-ERJSER_NOV17.PDF
R204 = RESISTOR: RES 51K 1/16W 5% 0402; Chkd/date: MANIRAJA/230817; Crtd /date: MANIRAJA/230817; Custom_Duty: 15%; Customs_HS_Code: 85332119; Distributor_name: DIGIKEY; Distributor_part_number: 541-51KJCT-ND; Footprint Path: Y:\MIS_DATABASE\Library\ALTIUM_TOOL\PCB_FOOTPRINTS\Altium_Footprint_Lib.PcbLib; Height: 0.40MM; Library Path: Y:\MIS_DATABASE\Library\ALTIUM_TOOL\SCHEMATICS_PARTS\MS_DISCRETE_Library.schlib; Mfr_name: VISHAY; Mfr_part_number: CRCW040251K0JNED; Mistral Part No: 110009030966-R; Package: 0402; Part_type: RESISTORS\FIXED; Project: TI_MAXIE_CPB; RoHS: RoHS; Temperature: -55°C+155°C; Tolerance: 5%; Voltage: NA; Wattage: 1/16W; Weight: 0.65mg; Datasheet: Y:\MIS_DATABASE\DATASHEETS\RESISTORS\CRCW0603.PDF
R205 = RESISTOR: RES 4.87K 1/16W 1% 0402; Chkd/date: ALVY/091220; Crtd /date: MANIRAJA/091220; Custom_Duty: 15%; Customs_HS_Code: 85332119; Distributor_name: DIGIKEY; Distributor_part_number: YAG3175CT-ND; Footprint Path: Y:\MIS_DATABASE\Library\ALTIUM_TOOL\PCB_FOOTPRINTS\Altium_Footprint_Lib.PcbLib; Height: 0.40MM; Library Path: Y:\MIS_DATABASE\Library\ALTIUM_TOOL\SCHEMATICS_PARTS\MS_DISCRETE_Library.schlib; Mfr_name: YAGEO AMERICA; Mfr_part_number: RC0402FR-074K87L; Mistral Part No: 110019090012-R; Package: 0402; Part_type: RESISTORS\FIXED; Project: TI_AM243x LP EVM; RoHS: RoHS; Temperature: -55°C+155°C; Tolerance: 1%; Voltage: NA; Wattage: 1/16W; Weight: 0.65mg; Datasheet: Y:\MIS_DATABASE\DATASHEETS\RESISTORS\RCXXXXL-SER_MAR18.PDF
R462 = RESISTOR: RES 220E 1/10W 5% 0402; Chkd/date: VASANTHA/291216; Crtd /date: GEETHA/260406; Custom_Duty: 15%; Customs_HS_Code: 85332119; Distributor_name: DIGIKEY; Distributor_part_number: P220JCT-ND; Footprint Path: Y:\MIS_DATABASE\Library\ALTIUM_TOOL\PCB_FOOTPRINTS\Altium_Footprint_Lib.PcbLib; Height: 0.40MM; Library Path: Y:\MIS_DATABASE\Library\ALTIUM_TOOL\SCHEMATICS_PARTS\MS_DISCRETE_Library.schlib; Mfr_name: PANASONIC-ECG; Mfr_part_number: ERJ-2GEJ221X; Mistral Part No: 110009030506-R; Package: 0402; Part_type: RESISTORS\FIXED; Project: RED EYE; RoHS: RoHS; Temperature: -55°C+155°C; Tolerance: 5%; Voltage: NA; Wattage: 1/10W; Weight: 0.8mg; Datasheet: Y:\MIS_DATABASE\DATASHEETS\RESISTORS\PAN-ERJSER_NOV17.PDF
R466 = RESISTOR: RES 180E 1/10W 5% 0402; Chkd/date: MAZHAR/150709; Crtd /date: GEETHA/280406; Custom_Duty: 15%; Customs_HS_Code: 85332119; Distributor_name: DIGIKEY; Distributor_part_number: P180JCT-ND; Footprint Path: Y:\MIS_DATABASE\Library\ALTIUM_TOOL\PCB_FOOTPRINTS\Altium_Footprint_Lib.PcbLib; Height: 0.40MM; Library Path: Y:\MIS_DATABASE\Library\ALTIUM_TOOL\SCHEMATICS_PARTS\MS_DISCRETE_Library.schlib; Mfr_name: PANASONIC-ECG; Mfr_part_number: ERJ-2GEJ181X; Mistral Part No: 110009030371-R; Package: 0402; Part_type: RESISTORS\FIXED; Project: RED EYE; RoHS: RoHS; Temperature: -55°C+155°C; Tolerance: 5%; Voltage: NA; Wattage: 1/10W; Weight: 0.8mg; Datasheet: Y:\MIS_DATABASE\DATASHEETS\RESISTORS\PAN-ERJSER_NOV17.PDF
R467 = RESISTOR: RES 100E 1/16W 5% 0402; Chkd/date: MANIRAJA/230817; Crtd /date: MANIRAJA/230817; Custom_Duty: 15%; Customs_HS_Code: 85332119; Distributor_name: DIGIKEY; Distributor_part_number: 541-100JCT-ND; Footprint Path: Y:\MIS_DATABASE\Library\ALTIUM_TOOL\PCB_FOOTPRINTS\Altium_Footprint_Lib.PcbLib; Height: 0.40MM; Library Path: Y:\MIS_DATABASE\Library\ALTIUM_TOOL\SCHEMATICS_PARTS\MS_DISCRETE_Library.schlib; Mfr_name: VISHAY; Mfr_part_number: CRCW0402100RJNED; Mistral Part No: 110014060039-R; Package: 0402; Part_type: RESISTORS\FIXED; Project: TI_MAXIE_CPB; RoHS: RoHS; Temperature: -55°C+155°C; Tolerance: 5%; Voltage: NA; Wattage: 1/16W; Weight: 0.65mg; Datasheet: Y:\MIS_DATABASE\DATASHEETS\RESISTORS\CRCW0603.PDF
R468 = RESISTOR: RES 220K 1/16W 1% 0402; Chkd/date: MANIRAJA/230817; Crtd /date: MANIRAJA/230817; Custom_Duty: 15%; Customs_HS_Code: 85332119; Distributor_name: DIGIKEY; Distributor_part_number: 541-220KLCT-ND; Footprint Path: Y:\MIS_DATABASE\Library\ALTIUM_TOOL\PCB_FOOTPRINTS\Altium_Footprint_Lib.PcbLib; Height: 0.40MM; Library Path: Y:\MIS_DATABASE\Library\ALTIUM_TOOL\SCHEMATICS_PARTS\MS_DISCRETE_Library.schlib; Mfr_name: VISHAY; Mfr_part_number: CRCW0402220KFKED; Mistral Part No: 110017080025-R; Package: 0402; Part_type: RESISTORS\FIXED; Project: TI_MAXIE_CPB; RoHS: RoHS; Temperature: -55°C+155°C; Tolerance: 1%; Voltage: NA; Wattage: 1/16W; Weight: 0.65mg; Datasheet: Y:\MIS_DATABASE\DATASHEETS\RESISTORS\CRCW0603.PDF
R469 = RESISTOR: RES 330K 1/16W 1% 0402; Chkd/date: MANIRAJA/230817; Crtd /date: MANIRAJA/230817; Custom_Duty: 15%; Customs_HS_Code: 85332119; Distributor_name: DIGIKEY; Distributor_part_number: 541-330KLCT-ND; Footprint Path: Y:\MIS_DATABASE\Library\ALTIUM_TOOL\PCB_FOOTPRINTS\Altium_Footprint_Lib.PcbLib; Height: 0.40MM; Library Path: Y:\MIS_DATABASE\Library\ALTIUM_TOOL\SCHEMATICS_PARTS\MS_DISCRETE_Library.schlib; Mfr_name: VISHAY; Mfr_part_number: CRCW0402330KFKED; Mistral Part No: 110017080024-R; Package: 0402; Part_type: RESISTORS\FIXED; Project: TI_MAXIE_CPB; RoHS: RoHS; Temperature: -55°C+155°C; Tolerance: 1%; Voltage: NA; Wattage: 1/16W; Weight: 0.65mg; Datasheet: Y:\MIS_DATABASE\DATASHEETS\RESISTORS\CRCW0603.PDF
R561 = RESISTOR: RES 30K 1/16W 5% 0402; Chkd/date: MANIRAJA/230817; Crtd /date: MANIRAJA/230817; Custom_Duty: 15%; Customs_HS_Code: 85332119; Distributor_name: DIGIKEY; Distributor_part_number: 541-30KJCT-ND; Footprint Path: Y:\MIS_DATABASE\Library\ALTIUM_TOOL\PCB_FOOTPRINTS\Altium_Footprint_Lib.PcbLib; Height: 0.40MM; Library Path: Y:\MIS_DATABASE\Library\ALTIUM_TOOL\SCHEMATICS_PARTS\MS_DISCRETE_Library.schlib; Mfr_name: VISHAY; Mfr_part_number: CRCW040230K0JNED; Mistral Part No: 110017080023-R; Package: 0402; Part_type: RESISTORS\FIXED; Project: TI_MAXIE_CPB; RoHS: RoHS; Temperature: -55°C+155°C; Tolerance: 5%; Voltage: NA; Wattage: 1/16W; Weight: 0.65mg; Datasheet: Y:\MIS_DATABASE\DATASHEETS\RESISTORS\CRCW0603.PDF
U58 = TPD4E004_SON6: IC 4-CH ESD PROTECTION ARRAY FOR HIGH SPEED DATA INTERFACE SON6; Chkd/date: MANIRAJA/100320; Crtd /date: MUDDU/010310; Custom_Duty: 15%; Customs_HS_Code: 85423100; Distributor_name: DIGIKEY; Distributor_part_number: 296-23618-1-ND; Footprint Path: Y:\MIS_DATABASE\Library\ALTIUM_TOOL\PCB_FOOTPRINTS\Altium_Footprint_Lib.PcbLib; Height: 0.60MM; Library Path: Y:\MIS_DATABASE\Library\ALTIUM_TOOL\SCHEMATICS_PARTS\MS_MISCINTERFACE_Library.schlib; Mfr_name: TEXAS INSTRUMENTS; Mistral Part No: 141010020012-R; Package: SON6; Part_type: ICS\INTERFACE; Project: BUG_BASE-II; RoHS: RoHS; Temperature: -40°C+85°C; Tolerance: NA; Voltage: NA; Wattage: NA; Weight: 3.2mg; Datasheet: Y:\MIS_DATABASE\DATASHEETS\ICS\INTERFACE\TPD4E004-SER.PDF
U59 = TM4C1294NCPDTT3R_TQFP128: IC 32-BIT MICROCONTROLLER WITH 1MB FLASH TQFP128; Chkd/date: MANIRAJA/220817; Crtd /date: MANIRAJA/220817; Custom_Duty: 15%; Customs_HS_Code: 85423100; Distributor_name: DIGIKEY; Distributor_part_number: TM4C1294NCPDTT3R-ND; Height: 1.20MM; Mfr_name: TEXAS INSTRUMENTS; Mistral Part No: 141217080002-R; Package: TQF9128; Part_type: ICS\DIGITAL\MICROCONTROLLER; Project: TI_MAXIE_CPB; RoHS: RoHS; Temperature: -40°C+105°C; Tolerance: NA; Voltage: NA; Wattage: NA; Weight: 503.5mg; Datasheet: Y:\MIS_DATABASE\DATASHEETS\ICS\DIGITAL\MICROCONTROLLER\TM4C1294NCPD.PDF
U61 = TPS79601DRBR_SON8: IC 1A HIGH PSRR RF ADJ LDO LINEAR REGULATOR SON8; Chkd/date: MANIRAJA/030518; Crtd /date: MAZHAR/280809; Custom_Duty: 15%; Customs_HS_Code: 85423100; Distributor_name: DIGIKEY; Distributor_part_number: 296-23107-1-ND; Footprint Path: Y:\MIS_DATABASE\Library\ALTIUM_TOOL\PCB_FOOTPRINTS\Altium_Footprint_Lib.PcbLib; Height: 1.00MM; Library Path: Y:\MIS_DATABASE\Library\ALTIUM_TOOL\SCHEMATICS_PARTS\MS_MISCPOWER_Library.schlib; Mfr_name: TEXAS INSTRUMENTS; Mistral Part No: 142009080012-R; Package: SON8; Part_type: ICS\POWER\VOLTAGE REGULATOR; Project: DIO_TXRX; RoHS: RoHS; Temperature: -40°C+125°C; Tolerance: NA; Voltage: NA; Wattage: NA; Weight: 24mg; Datasheet: Y:\MIS_DATABASE\DATASHEETS\MISC\REGULATORS\TPS796XX.PDF
U95 = LM4040B25IDCKR_SC70-5: IC PRECISION MICROPOWER SHUNT VOLTAGE REFERENCE SC70-5; Chkd/date: MANIRAJA/230817; Crtd /date: MANIRAJA/230817; Custom_Duty: 15%; Customs_HS_Code: 85423100; Distributor_name: DIGIKEY; Distributor_part_number: 296-20873-1-ND; Height: 1.10MM; Mfr_name: TEXAS INSTRUMENTS; Mistral Part No: 142017080015-R; Package: SC70-5; Part_type: ICS\POWER\VOLTAGE REGULATOR; Project: TI_MAXIE_CPB; RoHS: RoHS; Temperature: -40°C+85°C; Tolerance: NA; Voltage: NA; Wattage: NA; Weight: 30mg; Datasheet: Y:\MIS_DATABASE\DATASHEETS\ICS\POWER\LM4040B25I.PDF
Y2 = CRY4_13: CRY 16.000MHz SMD; Chkd/date: MANIRAJA/230817; Crtd /date: MANIRAJA/230817; Custom_Duty: 24%; Customs_HS_Code: 85439000; Distributor_name: DIGIKEY; Distributor_part_number: 644-1157-1-ND; Height: 0.90MM; Mfr_name: NDK; Mfr_part_number: NX3225GA-16.000M-STD-CRG-1; Mistral Part No: 130017080024-R; Package: SMD; Part_type: CRYSTAL; Project: TI_MAXIE_CPB; RoHS: RoHS; Temperature: -40°C+85°C; Tolerance: NA; Voltage: NA; Wattage: NA; Weight: NA; Datasheet: Y:\MIS_DATABASE\DATASHEETS\MISC\CRY_OSC\NX3225GA.PDF

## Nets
DGND: C161.2 C166.2 C167.2 C172.1 C174.2 C175.2 C176.2 C177.1 C180.2 C181.2 C185.1 C186.2 C187.2 C190.1 C191.2 C192.1 C193.1 C195.2 C196.1 C197.2 C384.2 C388.2 C404.2 C405.2 C434.2 C447.1 C453.1 C469.2 C472.2 FB8.2 J28.5(GND) J38.7 J38.16 J38.25 J38.34 J38.40 J38.41 J38.42 LD20.1(CATHODE) LD22.1(CATHODE) R198.2 R205.2 R206.1 R207.1 R208.1 R209.1 R356.1 R453.2 R468.2 R473.2 R474.2 R488.2 R489.2 R497.2 R498.2 R502.2 R503.2 R509.2 R510.2 R513.2 R514.2 R518.2 R519.2 R528.2 R529.2 R532.1 R555.1 R561.2 U51.4(GND) U58.3(GND) U59.10(GNDA) U59.17(GND) U59.48(GND) U59.55(GND) U59.58(GND) U59.64(~{WAKE}) U59.66(XOSC0) U59.80(GND) U59.114(GND) U61.6(GND) U61.9(PAD) U79.11(GND1) U79.12(GND2) U79.13(GND3) U79.25(EP) U81.11(GND1) U81.12(GND2) U81.13(GND3) U81.25(EP) U90.3(GND) U95.1(ANODE) U96.25(GND) U96.33(EP) Y2.2 Y2.4 ; also on sheet 2 3 4 5 6 7 8 9 10 11 12 13 14 15 16 17 18 19 20 21 22 23 24 25 26 27 39 40
VCC3V3_TA: C181.1 C190.2 C388.1 C405.1 C434.1 C469.1 C472.1 J38.1 J38.2 J38.3 R185.2 R355.2 R439.1 R494.1 R495.1 R521.2 R522.2 R523.2 R524.2 R525.2 R526.2 R533.2 R550.1 R551.1 U51.1(VCCA) U79.1(VCCA) U81.1(VCCA) U90.5(VCC) U96.27(VCCP) U96.31(VCC) ; also on sheet 16 17
VCC3V3_XDS: C166.1 C167.1 C174.1 C175.1 C176.1 C191.1 C192.2 C196.2 C197.1 C198.1 R199.2 R200.2 R202.1 R203.1 R204.1 R505.1 R557.2 R558.2 R559.2 R560.2 U59.7(VDD) U59.8(VDDA) U59.16(VDD) U59.26(VDD) U59.28(VDD) U59.39(VDD) U59.47(VDD) U59.51(VDD) U59.52(VDD) U59.69(VDD) U59.79(VDD) U59.90(VDD) U59.101(VDD) U59.113(VDD) U59.122(VDD) U61.3(OUT1) U61.4(OUT2) ; also on sheet 27
VCC_3V3_SYS: C161.1 C384.1 C404.1 R472.2 R475.2 R487.2 R490.2 R496.2 R499.2 R501.2 R504.2 R508.2 R511.2 R512.2 R515.2 R517.2 R520.2 R527.2 R530.2 U51.8(VCCB) U79.23(VCCB1) U79.24(VCCB2) U81.23(VCCB1) U81.24(VCCB2) ; also on sheet 2 5 6 7 8 10 11 12 13 14 15 16 17 18 19 20 21 23 24 25 26 27 39 40
VDDC_1V2: C185.2 C186.1 C187.1 U59.87(VDDC) U59.115(VDDC)
ADDR: R532.2 U96.26(ADDR)
BOOTMODE0: R325.1 ; also on sheet 19
BOOTMODE1: R326.1 ; also on sheet 19
BOOTMODE2: R327.1 ; also on sheet 19
BOOTMODE3: R328.1 ; also on sheet 19
BOOTMODE4: R329.1 ; also on sheet 19
BOOTMODE5: R330.1 ; also on sheet 19
BOOTMODE6: R331.1 ; also on sheet 19
BOOTMODE7: R332.1 ; also on sheet 19
BOOTMODE8: R372.1 ; also on sheet 19
BOOTMODE9: R373.1 ; also on sheet 19
BOOTMODE10: R374.1 ; also on sheet 19
BOOTMODE11: R375.1 ; also on sheet 19
BOOTMODE12: R376.1 ; also on sheet 19
BOOTMODE13: R377.1 ; also on sheet 19
BOOTMODE14: R378.1 ; also on sheet 19
BOOTMODE15: R379.1 ; also on sheet 19
BOOTMODE_I2C_SCL: J38.37 R550.2 TP43.1(TP) U96.29(SCL)
BOOTMODE_I2C_SDA: J38.39 R551.2 TP42.1(TP) U96.30(SDA)
BOOTMODEON: R453.1 R454.1 U79.22(~{OE}) U81.22(~{OE})
DIR: R355.1 R356.2 U79.2(DIR) U81.2(DIR)
OSC0: C177.2 U59.88(OSC0) Y2.1
OSC1: C172.2 U59.89(OSC1) Y2.3
PORz_OUT: R434.2 ; also on sheet 2 12 24 39 40
RESETSTATz: R435.2 ; also on sheet 5 11 12 13 21 24
SoC_I2C1_SCL: U51.7(SCLB) ; also on sheet 5 6 7 10 11 13 14
SoC_I2C1_SDA: U51.6(SDAB) ; also on sheet 5 6 7 10 11 13 14
SoC_I2C1_TA_SCL: J38.36 R495.2 U51.2(SCLA)
SoC_I2C1_TA_SDA: J38.38 R494.2 U51.3(SDAA)
SYS_BOOTMODE0: R529.1 SW2.1 U79.3(A1) U96.1(P00)
SYS_BOOTMODE1: R519.1 SW2.2 U79.4(A2) U96.2(P01)
SYS_BOOTMODE2: R514.1 SW2.3 U79.5(A3) U96.3(P02)
SYS_BOOTMODE3: R510.1 SW2.4 U79.6(A4) U96.4(P03)
SYS_BOOTMODE4: R503.1 SW2.5 U79.7(A5) U96.5(P04)
SYS_BOOTMODE5: R498.1 SW2.6 U79.8(A6) U96.6(P05)
SYS_BOOTMODE6: R489.1 SW2.7 U79.9(A7) U96.7(P06)
SYS_BOOTMODE7: R474.1 SW2.8 U79.10(A8) U96.8(P07)
SYS_BOOTMODE8: R473.1 SW3.1 U81.3(A1) U96.9(P10)
SYS_BOOTMODE9: R488.1 SW3.2 U81.4(A2) U96.10(P11)
SYS_BOOTMODE10: R497.1 SW3.3 U81.5(A3) U96.11(P12)
SYS_BOOTMODE11: R502.1 SW3.4 U81.6(A4) U96.12(P13)
SYS_BOOTMODE12: R509.1 SW3.5 U81.7(A5) U96.13(P14)
SYS_BOOTMODE13: R513.1 SW3.6 U81.8(A6) U96.14(P15)
SYS_BOOTMODE14: R518.1 SW3.7 U81.9(A7) U96.15(P16)
SYS_BOOTMODE15: R528.1 SW3.8 U81.10(A8) U96.16(P17)
SYSBOOT_BUF_ENz: R434.1 R435.1 U90.1(A)
TCA6424_EXP_INT: R533.1 U96.32(~{INT})
TEST_GPIO1: R523.1 R545.1 ; also on sheet 25
TEST_GPIO2: R524.1 R546.1 ; also on sheet 13
TEST_GPIO3: J30.1 R439.2 R525.1 R547.1 TP41.1(TP) U90.2(B)
TEST_GPIO4: R526.1 R548.1 TP40.1(TP) U96.28(~{RESET})
TEST_PORZn: R521.1 R543.1 ; also on sheet 25
TEST_POWERDOWN: R542.1 ; also on sheet 17
TEST_WARMRESETn: R522.1 R544.1 ; also on sheet 25
TM4C129_TCK: TP37.1(TP) U59.100(PC0/TCK/SWCLK)
TM4C129_TDI: TP36.1(TP) U59.98(PC2/TDI)
TM4C129_TDO: TP38.1(TP) U59.97(PC3/TDO/SWO)
TM4C129_TMS: TP35.1(TP) U59.99(PC1/TMS/SWDIO)
VREF: C180.1 C453.2 R505.2 U59.9(VREFA+) U95.3(CATHODE)
XDS110_EMU0: R202.2 U59.42(PF0) ; also on sheet 27
XDS110_EMU1: R203.2 U59.43(PF1) ; also on sheet 27
XDS110_TCK: U59.35(PA2/SSI0CLK) ; also on sheet 27
XDS110_TDI: U59.38(PA5/SSI0XDAT1) ; also on sheet 27
XDS110_TDO: U59.37(PA4/SSI0XDAT0) ; also on sheet 27
XDS110_TMS: U59.36(PA3/SSI0FSS) ; also on sheet 27
XDS110_TRST#: U59.40(PA6) ; also on sheet 27
XDS_RSTn: R198.1 R199.1 U59.70(~{RST})
XDS_SHIELD: FB8.1 J28.SH1 J28.SH2 J28.SH3 J28.SH4 J28.SH5 J28.SH6
XDS_USB_DM: J28.2(D-) U58.5(IO4) U59.93(PL7/USB0DM)
XDS_USB_DP: J28.3(D+) U58.4(IO3) U59.94(PL6/USB0DP)
XDS_USB_ID: J28.4(ID) R478.2 U58.2(IO2)
XDS_USB_VBUS: C195.1 J28.1(VBUS) R467.1 R469.1 U58.6(VCC) U61.1(IN1) U61.2(IN2) U61.8(EN)
N15202140: R478.1 U59.95(PB0/USB0ID)
N15204440: C198.2 R204.2 R561.1 U61.5(NR/FB)
N15205319: C193.2 R200.1 U59.68(VBAT)
N15212041: R205.1 U59.59(RBAIS)
N15239696: C447.2 R467.2 U59.96(PB1/USB0VBUS)
N15241750: R468.1 R469.2 U59.1(PD0/AIN15)
N15242949: R466.1 U59.3(PD2/AIN13)
N15242980: LD22.2(ANODE) R466.2
N15243226: R462.1 U59.4(PD3/AIN12)
N15365714: J38.27 R543.2
N15365947: J38.30 R545.2
N15366015: J38.31 R546.2
N15366091: J38.32 R547.2
N15584817: R508.1 SW2.13
N15584821: R512.1 SW2.14
N15584825: R517.1 SW2.15
N15584829: R527.1 SW2.16
N15591045: R472.1 SW2.9
N15591049: R487.1 SW2.10
N15591053: R496.1 SW2.11
N15591057: R501.1 SW2.12
N16303893: R515.1 SW3.11
N16303897: R511.1 SW3.12
N16303901: R504.1 SW3.13
N16303905: R499.1 SW3.14
N16303921: R530.1 SW3.9
N16303925: R520.1 SW3.10
N16679303: R206.2 R560.1 U59.60(PK7)
N16679944: R209.2 R557.1 U59.63(PK4)
N16679981: R207.2 R559.1 U59.61(PK6)
N16680014: R208.2 R558.1 U59.62(PK5)
N17211229: J38.33 R548.2
N17546132: J38.26 R542.2
N17546158: J38.28 R544.2
N18867885: R325.2 U79.21(B1)
N18867903: R326.2 U79.20(B2)
N18867905: R327.2 U79.19(B3)
N18867915: R328.2 U79.18(B4)
N18867925: R329.2 U79.17(B5)
N18867943: R330.2 U79.16(B6)
N18867953: R331.2 U79.15(B7)
N18867955: R332.2 U79.14(B8)
N24658557: LD20.2(ANODE) R462.2
N26140693: R372.2 U81.21(B1)
N26140695: R373.2 U81.20(B2)
N26140697: R374.2 U81.19(B3)
N26140699: R375.2 U81.18(B4)
N26140701: R376.2 U81.17(B5)
N26140703: R377.2 U81.16(B6)
N26140705: R378.2 U81.15(B7)
N26140707: R379.2 U81.14(B8)
N26149805: R454.2 U90.4(Y)
N26149864: J30.2 R555.2
N26219977: R490.1 SW3.15
N26220001: R475.1 SW3.16
N26442461: R185.1 U51.5(EN)

Not connected (* = marked no-connect by the designer): J38 4* 5* 6* 8* 9* 10* 11* 12* 13* 14* 15* 17* 18* 19* 20* 21* 22* 23* 24* 29* 35*; U58 1(IO1)*; U59 2(PD1/AIN14)* 5(PQ0)* 6(PQ1)* 11(PQ2)* 12(PE3/AIN0)* 13(PE2/AIN1)* 14(PE1/AIN2)* 15(PE0/AIN3)* 18(PK0/AIN16)* 19(PK1/AIN17)* 20(PK2/AIN18)* 21(PK3/AIN19)* 22(PC7/C0-)* 23(PC6/C0+)* 24(PC5/C1+)* 25(PC4/C1-)* 27(PQ3)* 29(PH0)* 30(PH1)* 31(PH2)* 32(PH3)* 33(PA0/U0RX)* 34(PA1/U0TX)* 41(PA7)* 44(PF2)* 45(PF3)* 46(PF4)* 49(PG0)* 50(PG1)* 53(EN0RXIN)* 54(EN0RXIP)* 56(EN0RX0N)* 57(EN0RX0P)* 65(~{HIB})* 67(XOSC1)* 71(PM7)* 72(PM6)* 73(PM5)* 74(PM4)* 75(PM3)* 76(PM2)* 77(PM1)* 78(PM0)* 81(PL0)* 82(PL1)* 83(PL2)* 84(PL3)* 85(PL4)* 86(PL5)* 91(PB2/I2C0SCL)* 92(PB3/I2C0SDA)* 102(PQ4)* 103(PP2)* 104(PP3)* 105(PP4)* 106(PP5)* 107(PN0)* 108(PN1)* 109(PN2)* 110(PN3)* 111(PN4)* 112(PN5)* 116(PJ0)* 117(PJ1)* 118(PP0/C2+)* 119(PP1/C2-)* 120(PB5/AIN11)* 121(PB4/AIN10)* 123(PE4/AIN9)* 124(PE5/AIN8)* 125(PD4/AIN7)* 126(PD5/AIN6)* 127(PD6/AIN5)* 128(PD7/AIN4)*; U61 7(NC)*; U95 2(NC1)* 4(NC2)* 5(NC3)*; U96 17(P20)* 18(P21)* 19(P22)* 20(P23)* 21(P24)* 22(P25)* 23(P26)* 24(P27)*

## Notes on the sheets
sheet 28
- XDS110 POWER
- USB Connector
- XDS110 DEBUGGER
- This will indicate the unique ID of the Debugger
sheet 29
- BOOT MODE BUFFER & SWITCHES
- DIR = H: A -> B
  DIR = L: B -> A
  OE = H: output = Hi-Z
- DIR = H: A -> B
  DIR = L: B -> A
  OE = H: output = Hi-Z
- I2C ADDRESS: 0x22
- SWITCH ON  =  LOGIC 1
  SWITCH OFF =  LOGIC 0
- Off Page Connections
- From Processor
- BOOT MODES SUPPORTED
- 1. OSPI
- 2. MMC1 - SD CARD
- From Test Automation
  Header
- 3. MMC0 - eMMC
- 4. CPSW Ethernet Slave
- 5. USB Host
- 6. USB Device
- 7. UART
- 8. Ethernet
sheet 30
- TEST AUTOMATION
- 40-PIN AUTOMATION HEADER
- TEST AUTOMATION  GPIO MAPPING
- Internal/
  External
  PU/PD states
- Direction WRT CTRL
- SIGNAL NAME
- DESCRIPTION
- TEST_POWERDOWN
  TEST_PORZn
  TEST_WARMRESETn
  TEST_GPIO1
  TEST_GPIO2
  TEST_GPIO3
  TEST_GPIO4
- Used to Power down the OVP Circuit
  Used to  Reset the SoC PORz
  Used to Reset the SoC Warmreset
  Used to Generate the interrupt on
  GPIO0_13_INTn Pin
  Connected to I/O Expander to Communicate
  with SoC
  Used to Enable the BOOTMODE Buffer
  Used to Reset the Bootmode IO Expander
- OUTPUT
  OUTPUT
  OUTPUT
  OUTPUT
  OUTPUT
  OUTPUT
  OUTPUT
- External Pullup
  External Pullup
  External Pullup
  External Pullup
  External Pullup
  External Pullup
  External Pullup
- Off Page Connections
- To Processor
- To Bootmode
  Buffer
- To Debounce Ckt
- To High Side SW
- To Debounce Ckt
- To Debounce Ckt
- To IO Expander
- To EN Boot Mode Buffer
- To RST Boot Mode Buffer
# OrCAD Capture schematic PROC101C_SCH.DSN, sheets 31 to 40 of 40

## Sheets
31 40. HARDWARE SCHEMATICS: title: HARDWARE SCHEMATICS
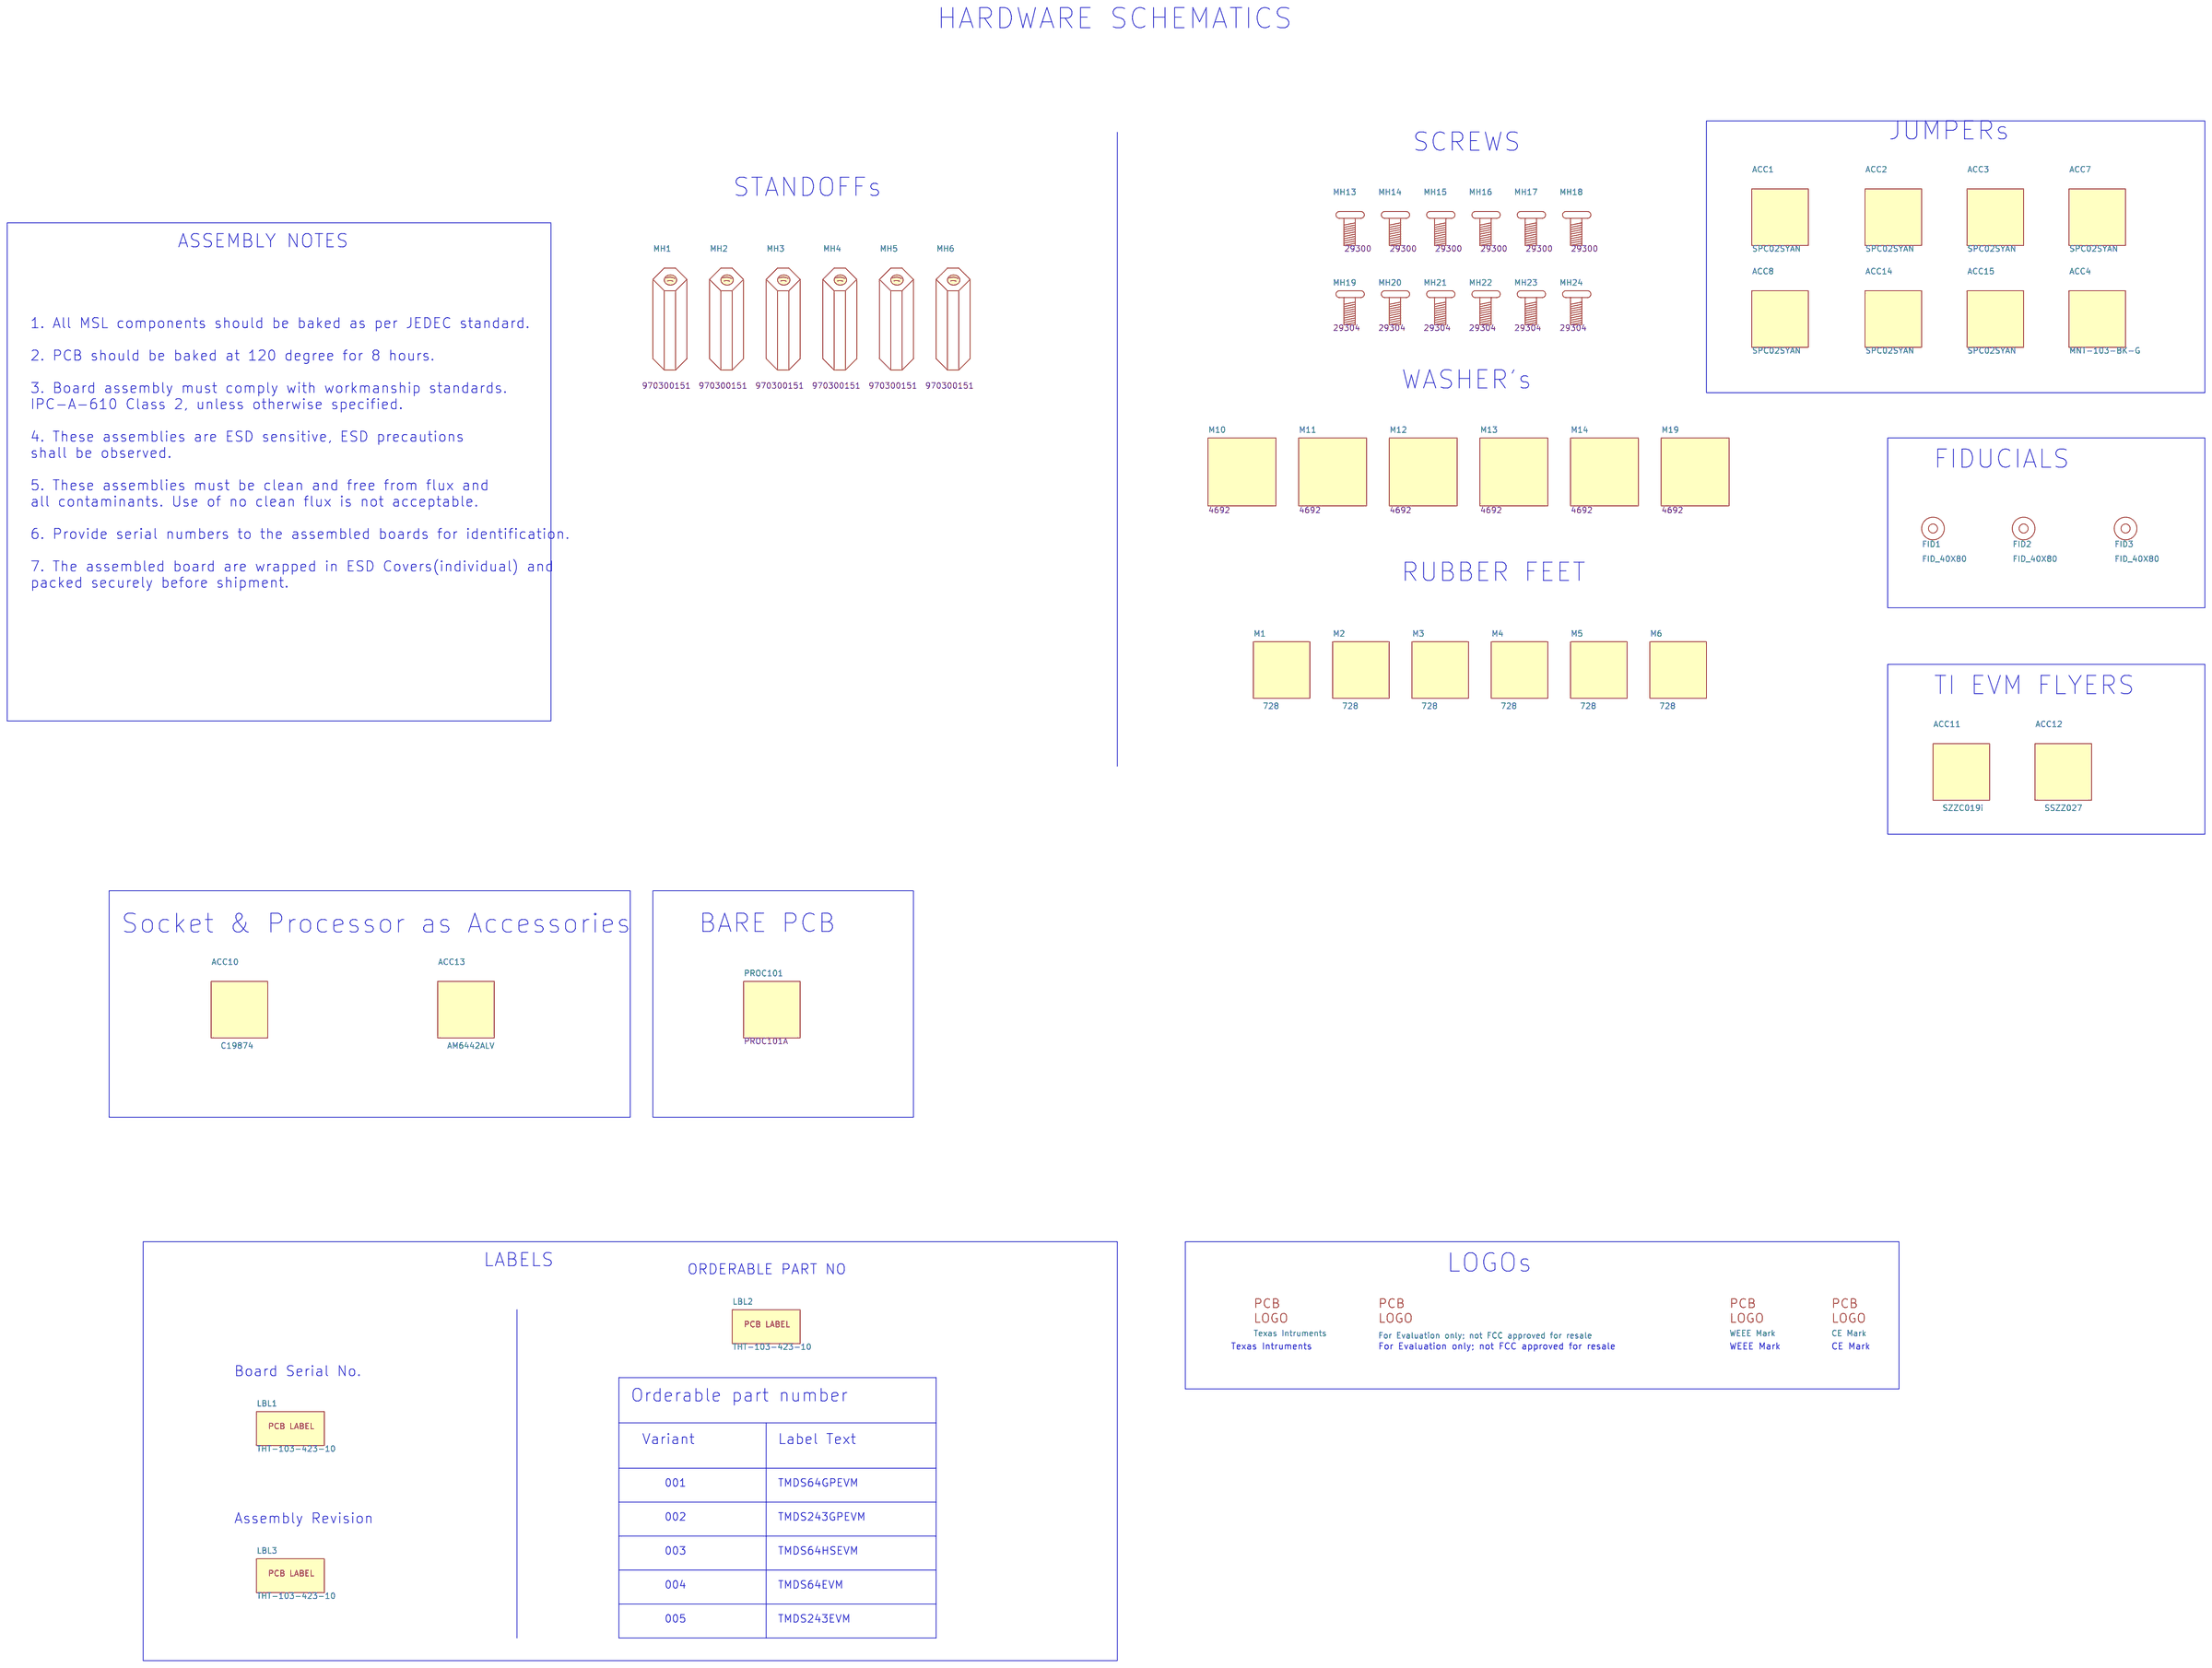
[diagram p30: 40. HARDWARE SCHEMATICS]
32 07. GPIO MAPPING TABLE: title: GPIO  MAPPING TABLE
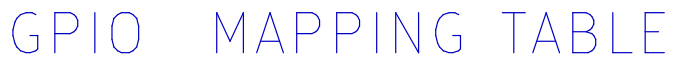
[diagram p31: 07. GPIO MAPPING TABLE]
33 08. I2C TREE: title: I2C TREE
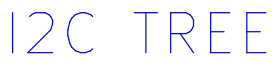
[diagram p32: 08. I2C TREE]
34 06. POWER SEQUENCE: title: POWER SEQUENCE
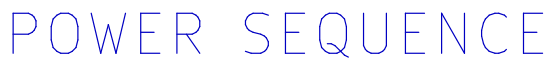
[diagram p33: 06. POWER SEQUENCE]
35 05. POWER FLOW DIAGRAM: title: POWER FLOW DIAGRAM
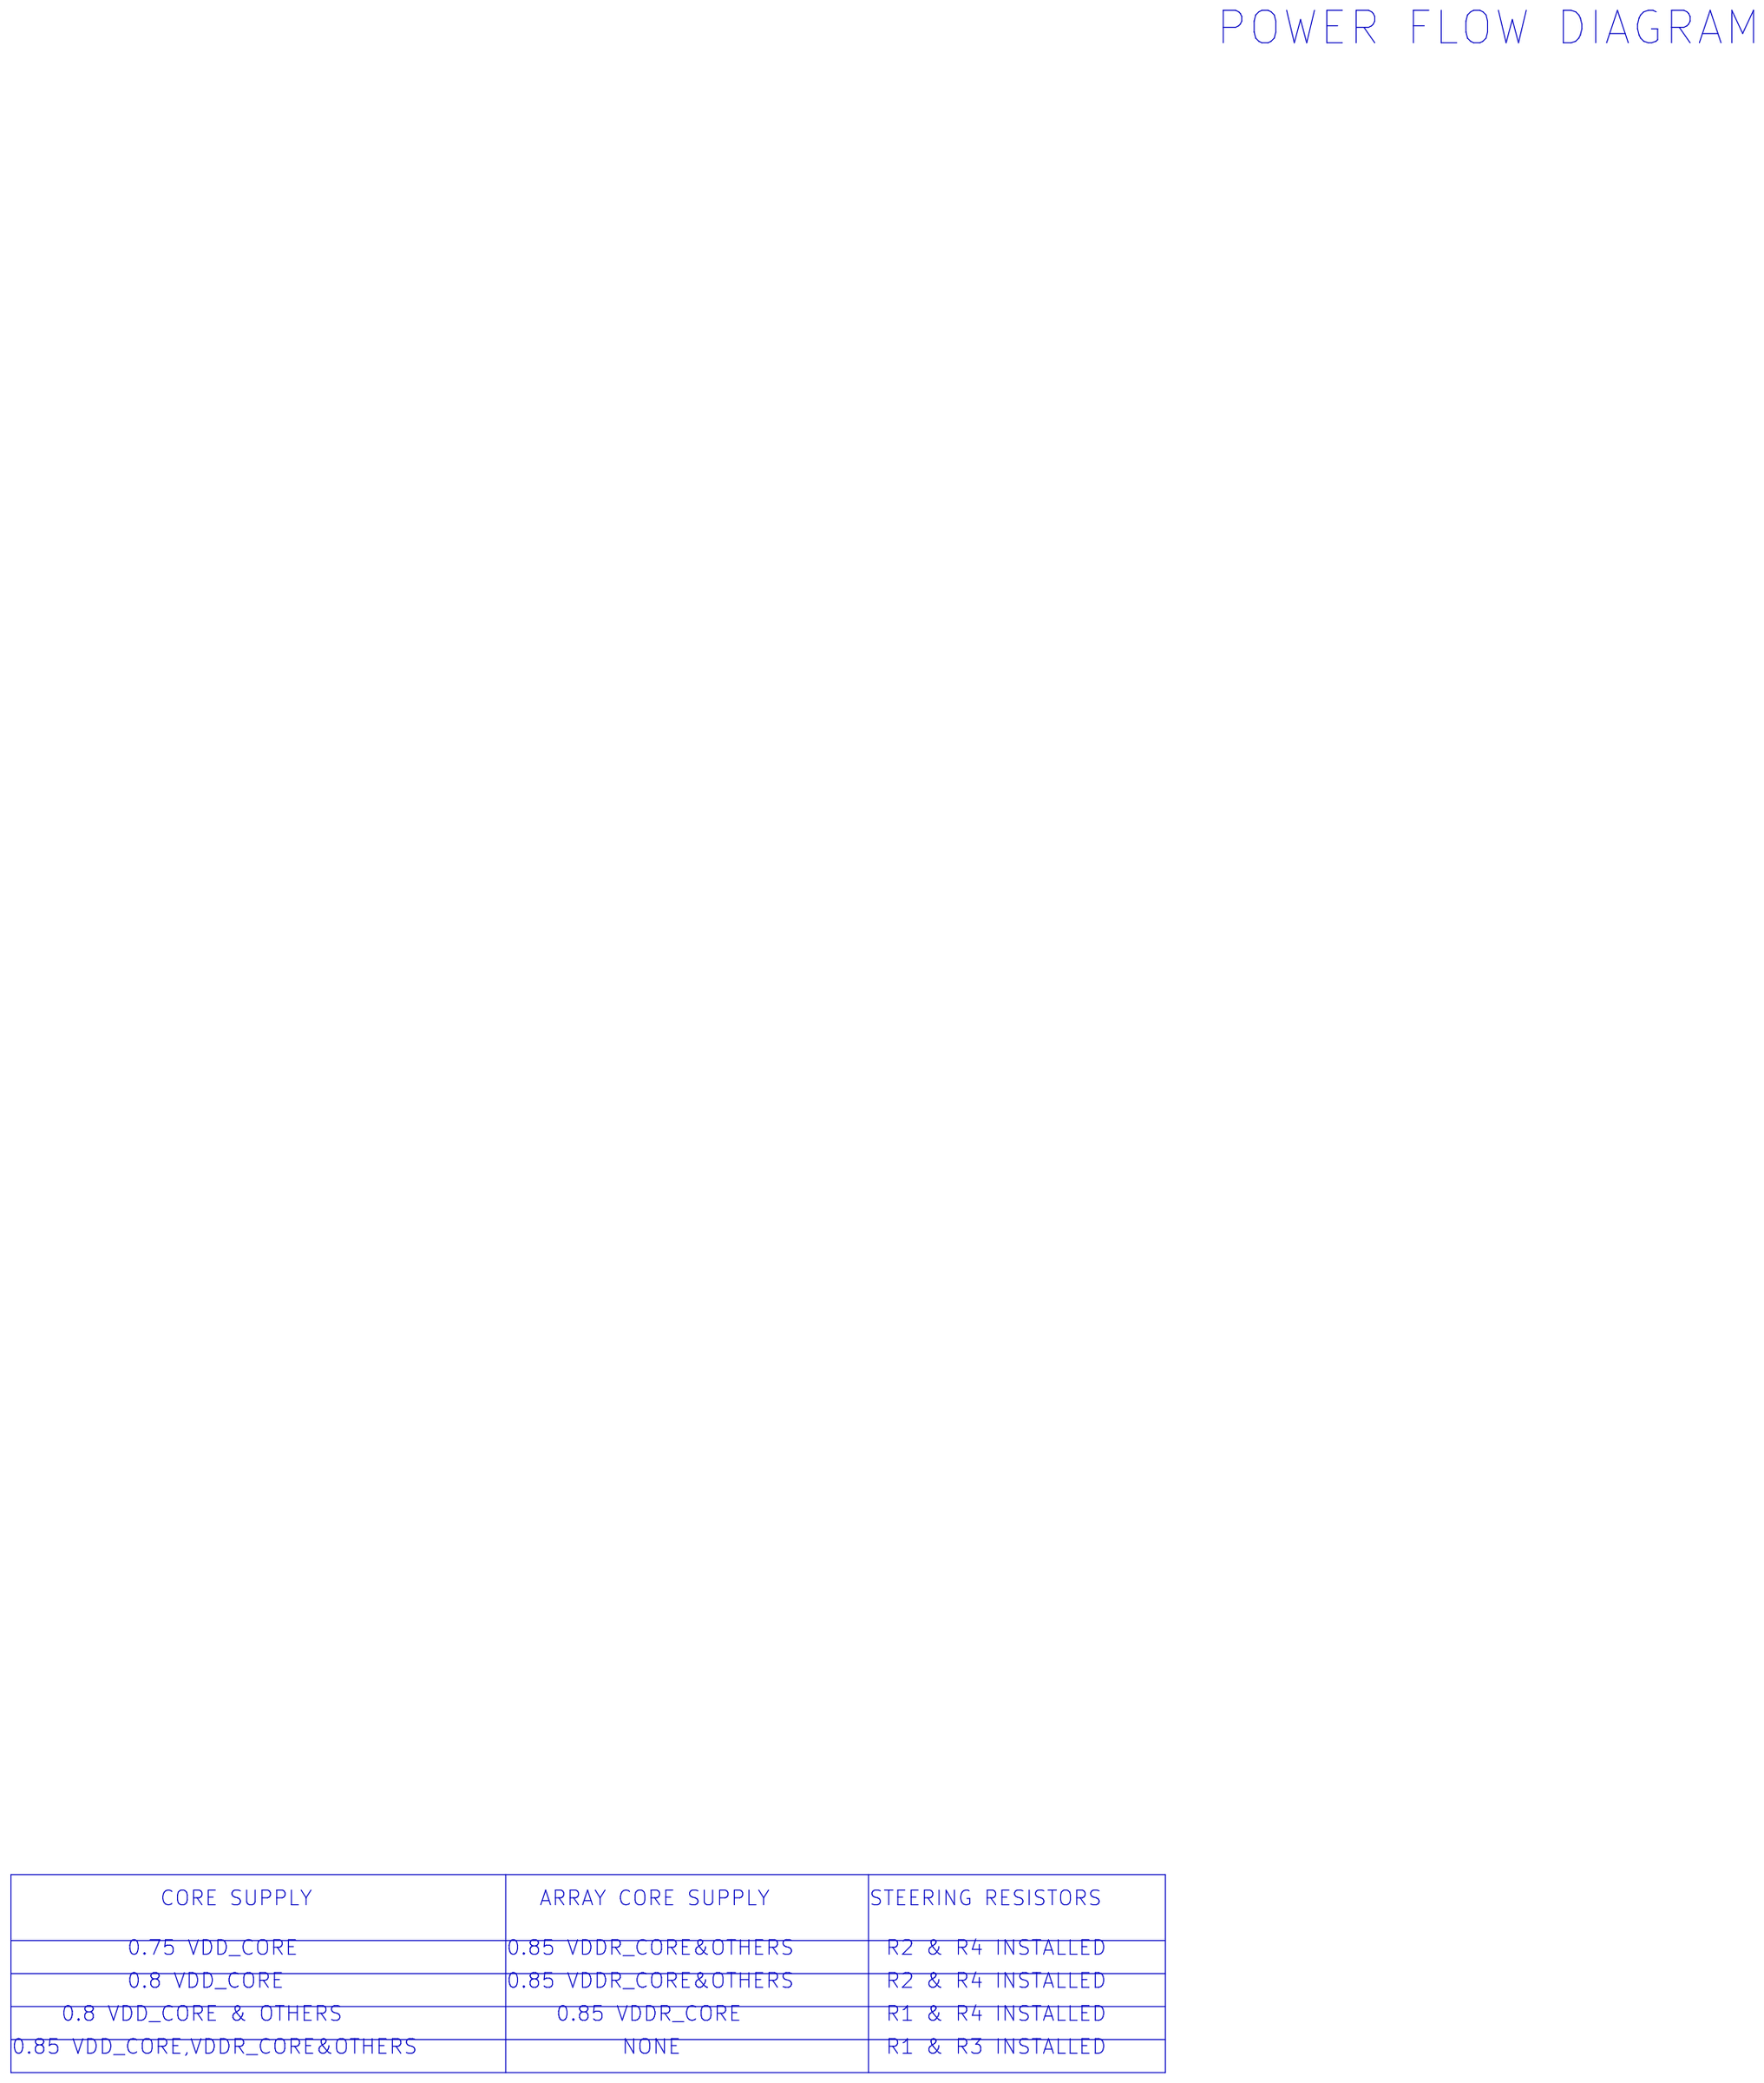
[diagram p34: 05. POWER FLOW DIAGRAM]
36 03.BLOCK_DIAGRAM_AM64x_EVM: title: BLOCK DIAGRAM_CP BOARD
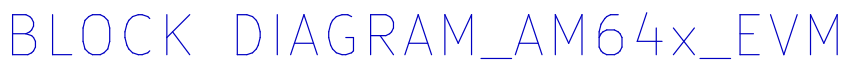
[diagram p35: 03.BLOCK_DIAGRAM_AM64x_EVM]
37 01. TABLE OF CONTENTS: title: TABLE OF CONTENTS
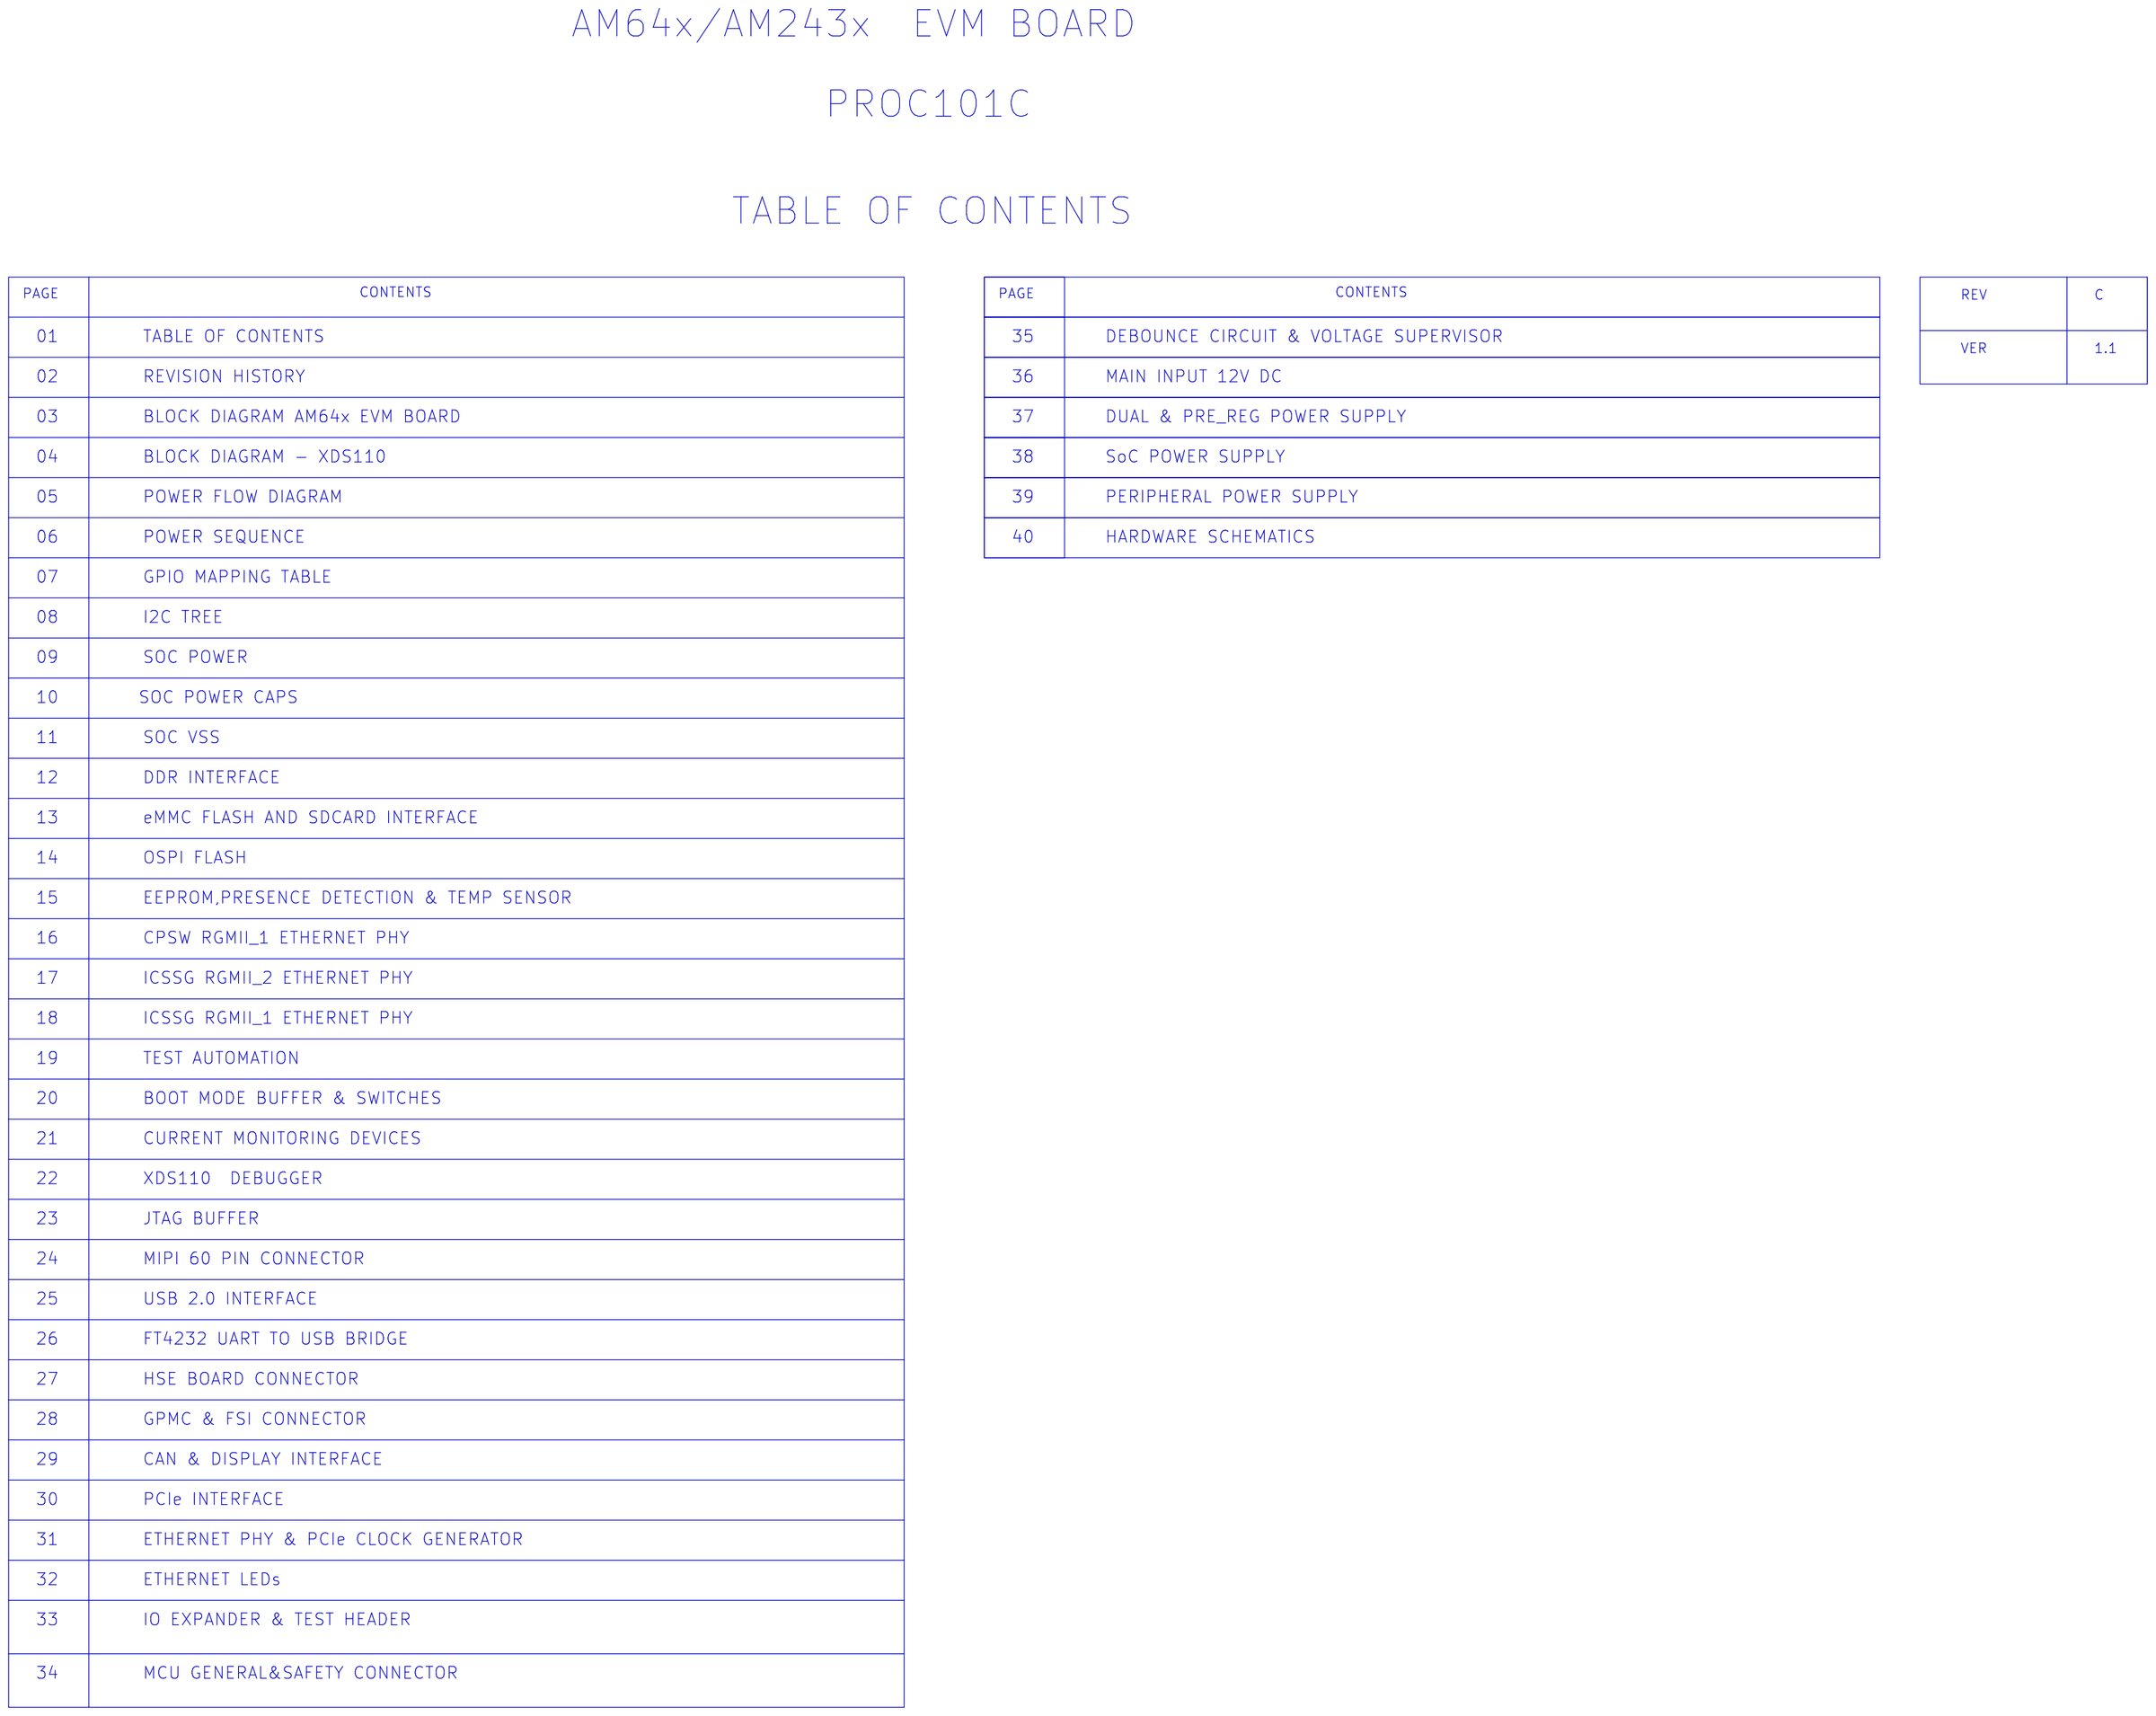
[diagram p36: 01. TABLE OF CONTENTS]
38 02. REVISION HISTORY: title: REVISION HISTORY
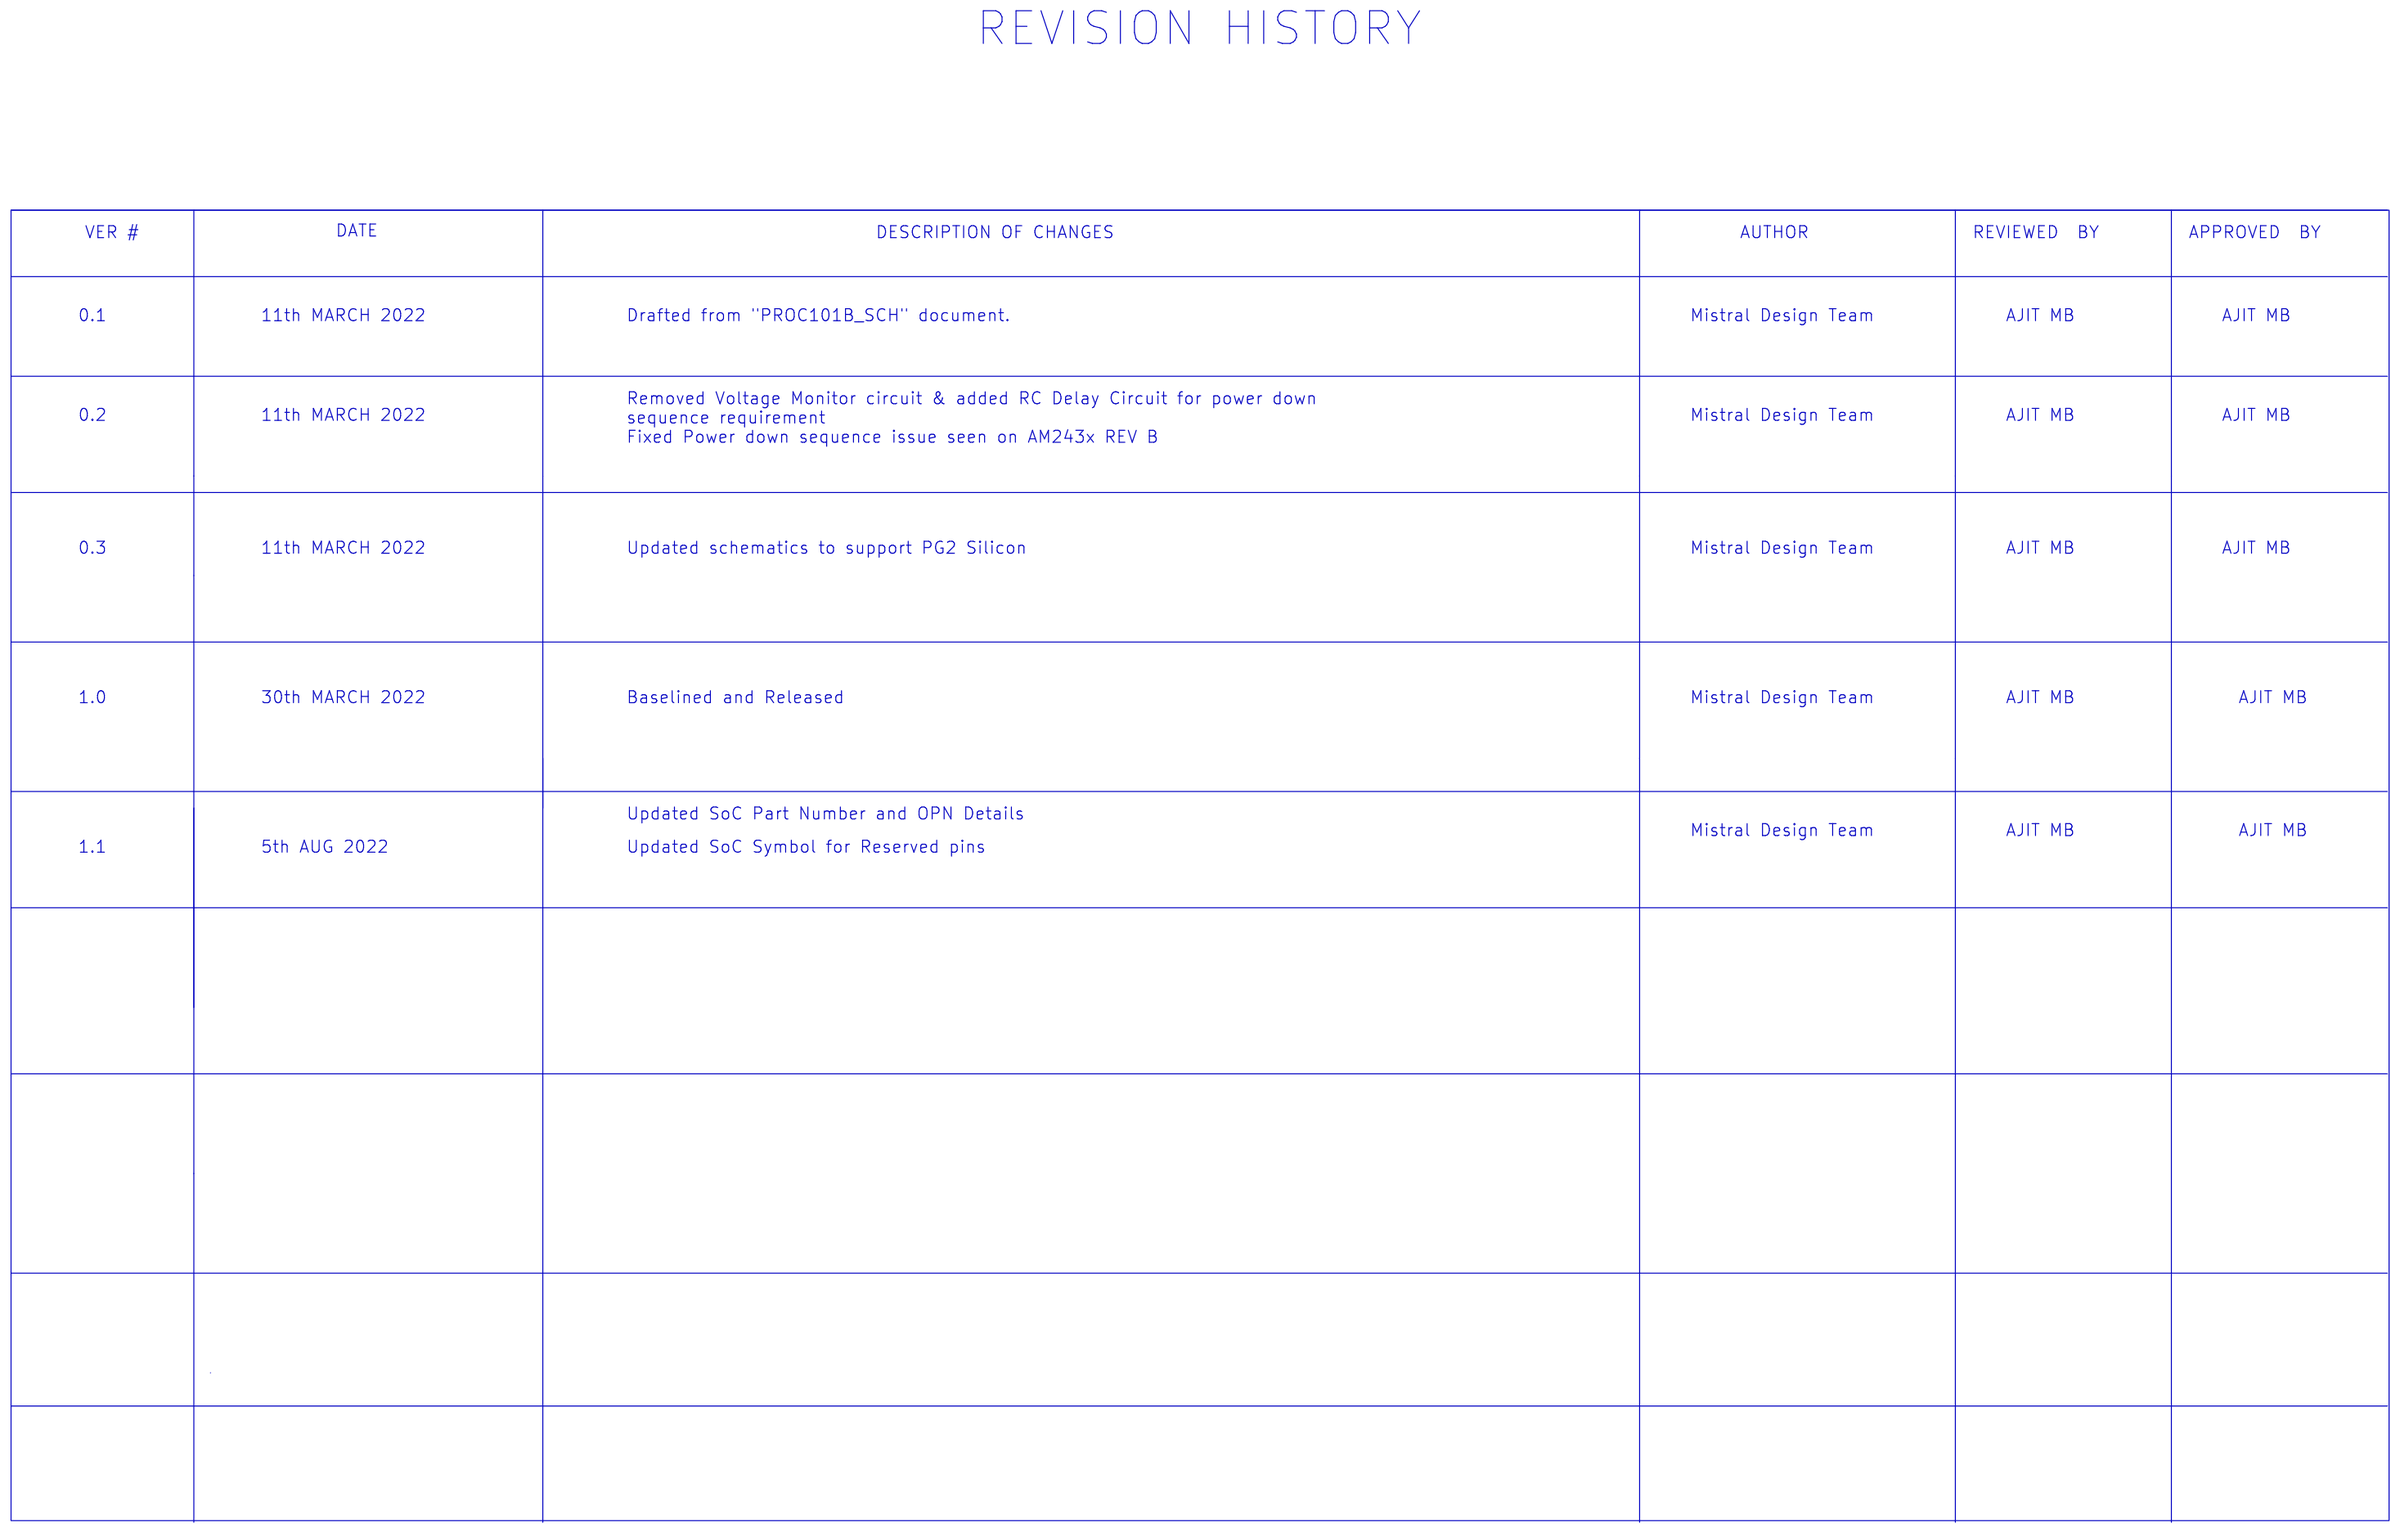
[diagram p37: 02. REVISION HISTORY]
39 17. ICSSG RGMII_2 ETHERNET PHY: size C; title: ICSSG1 RGMII_2 ETHERNET PHY
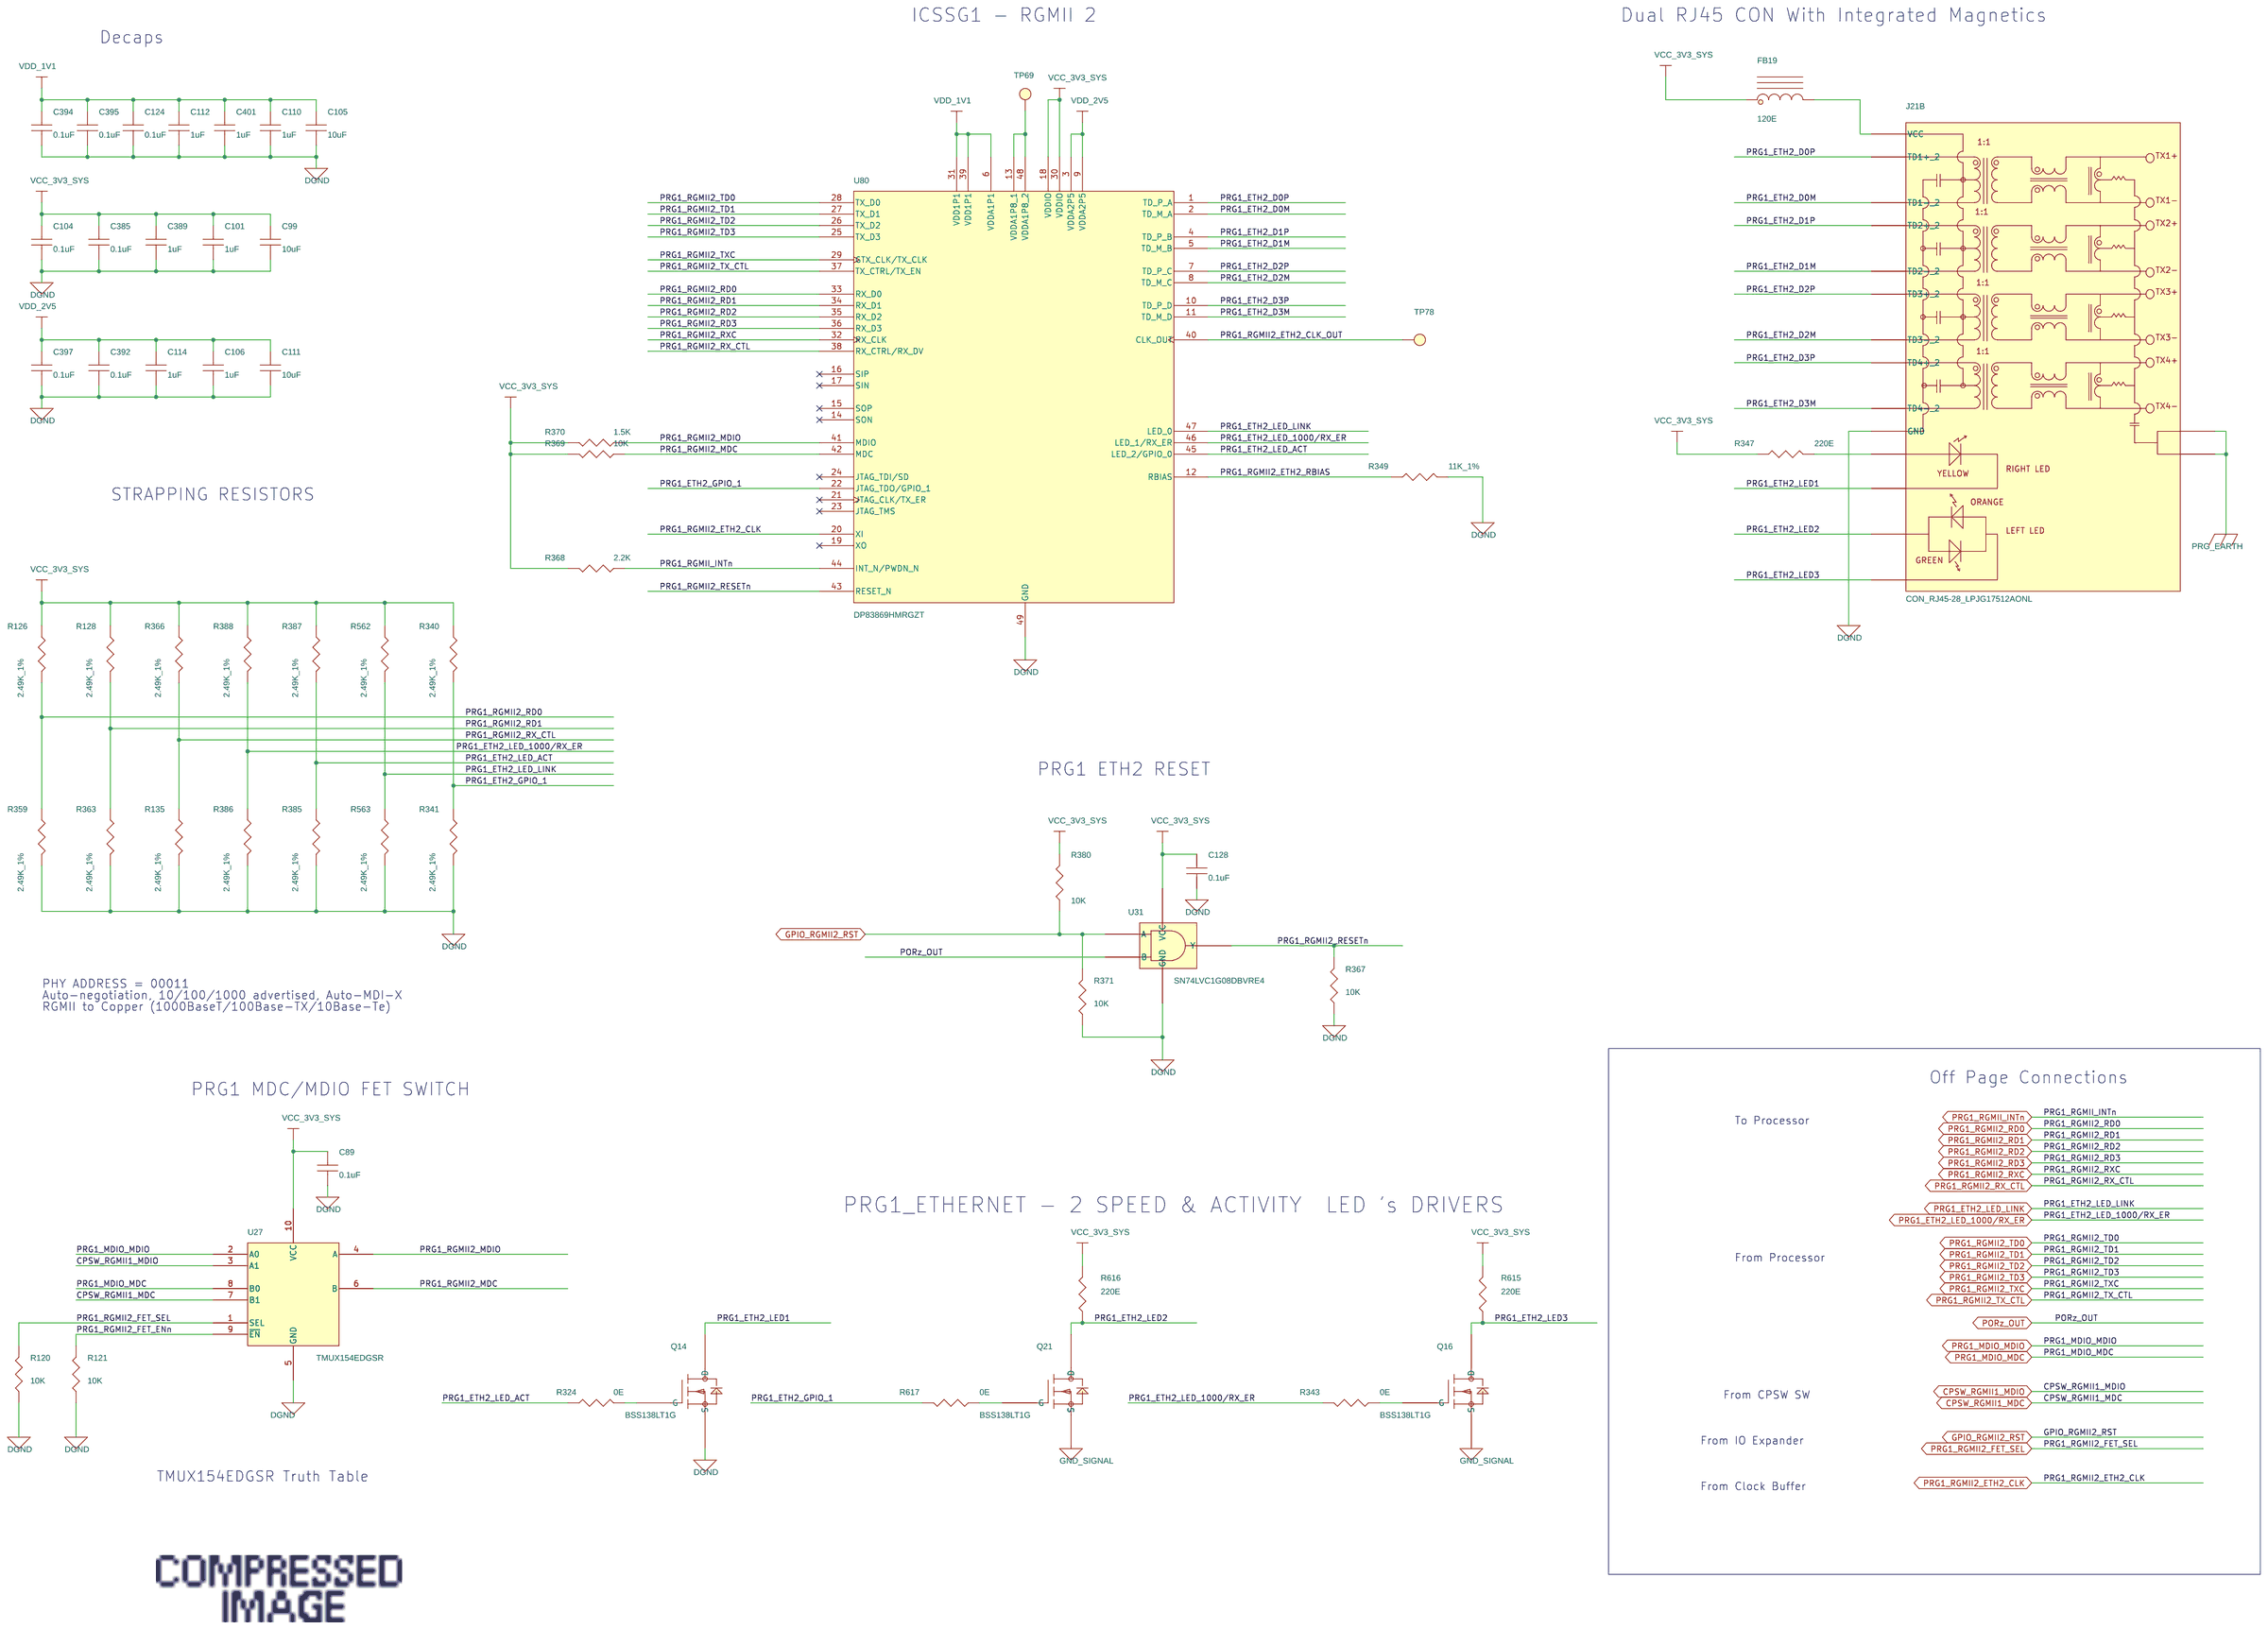
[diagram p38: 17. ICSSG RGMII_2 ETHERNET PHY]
40 18. ICSSG RGMII_1 ETHERNET PHY: size C; title: ICSSG2 RGMII_1 ETHERNET PHY

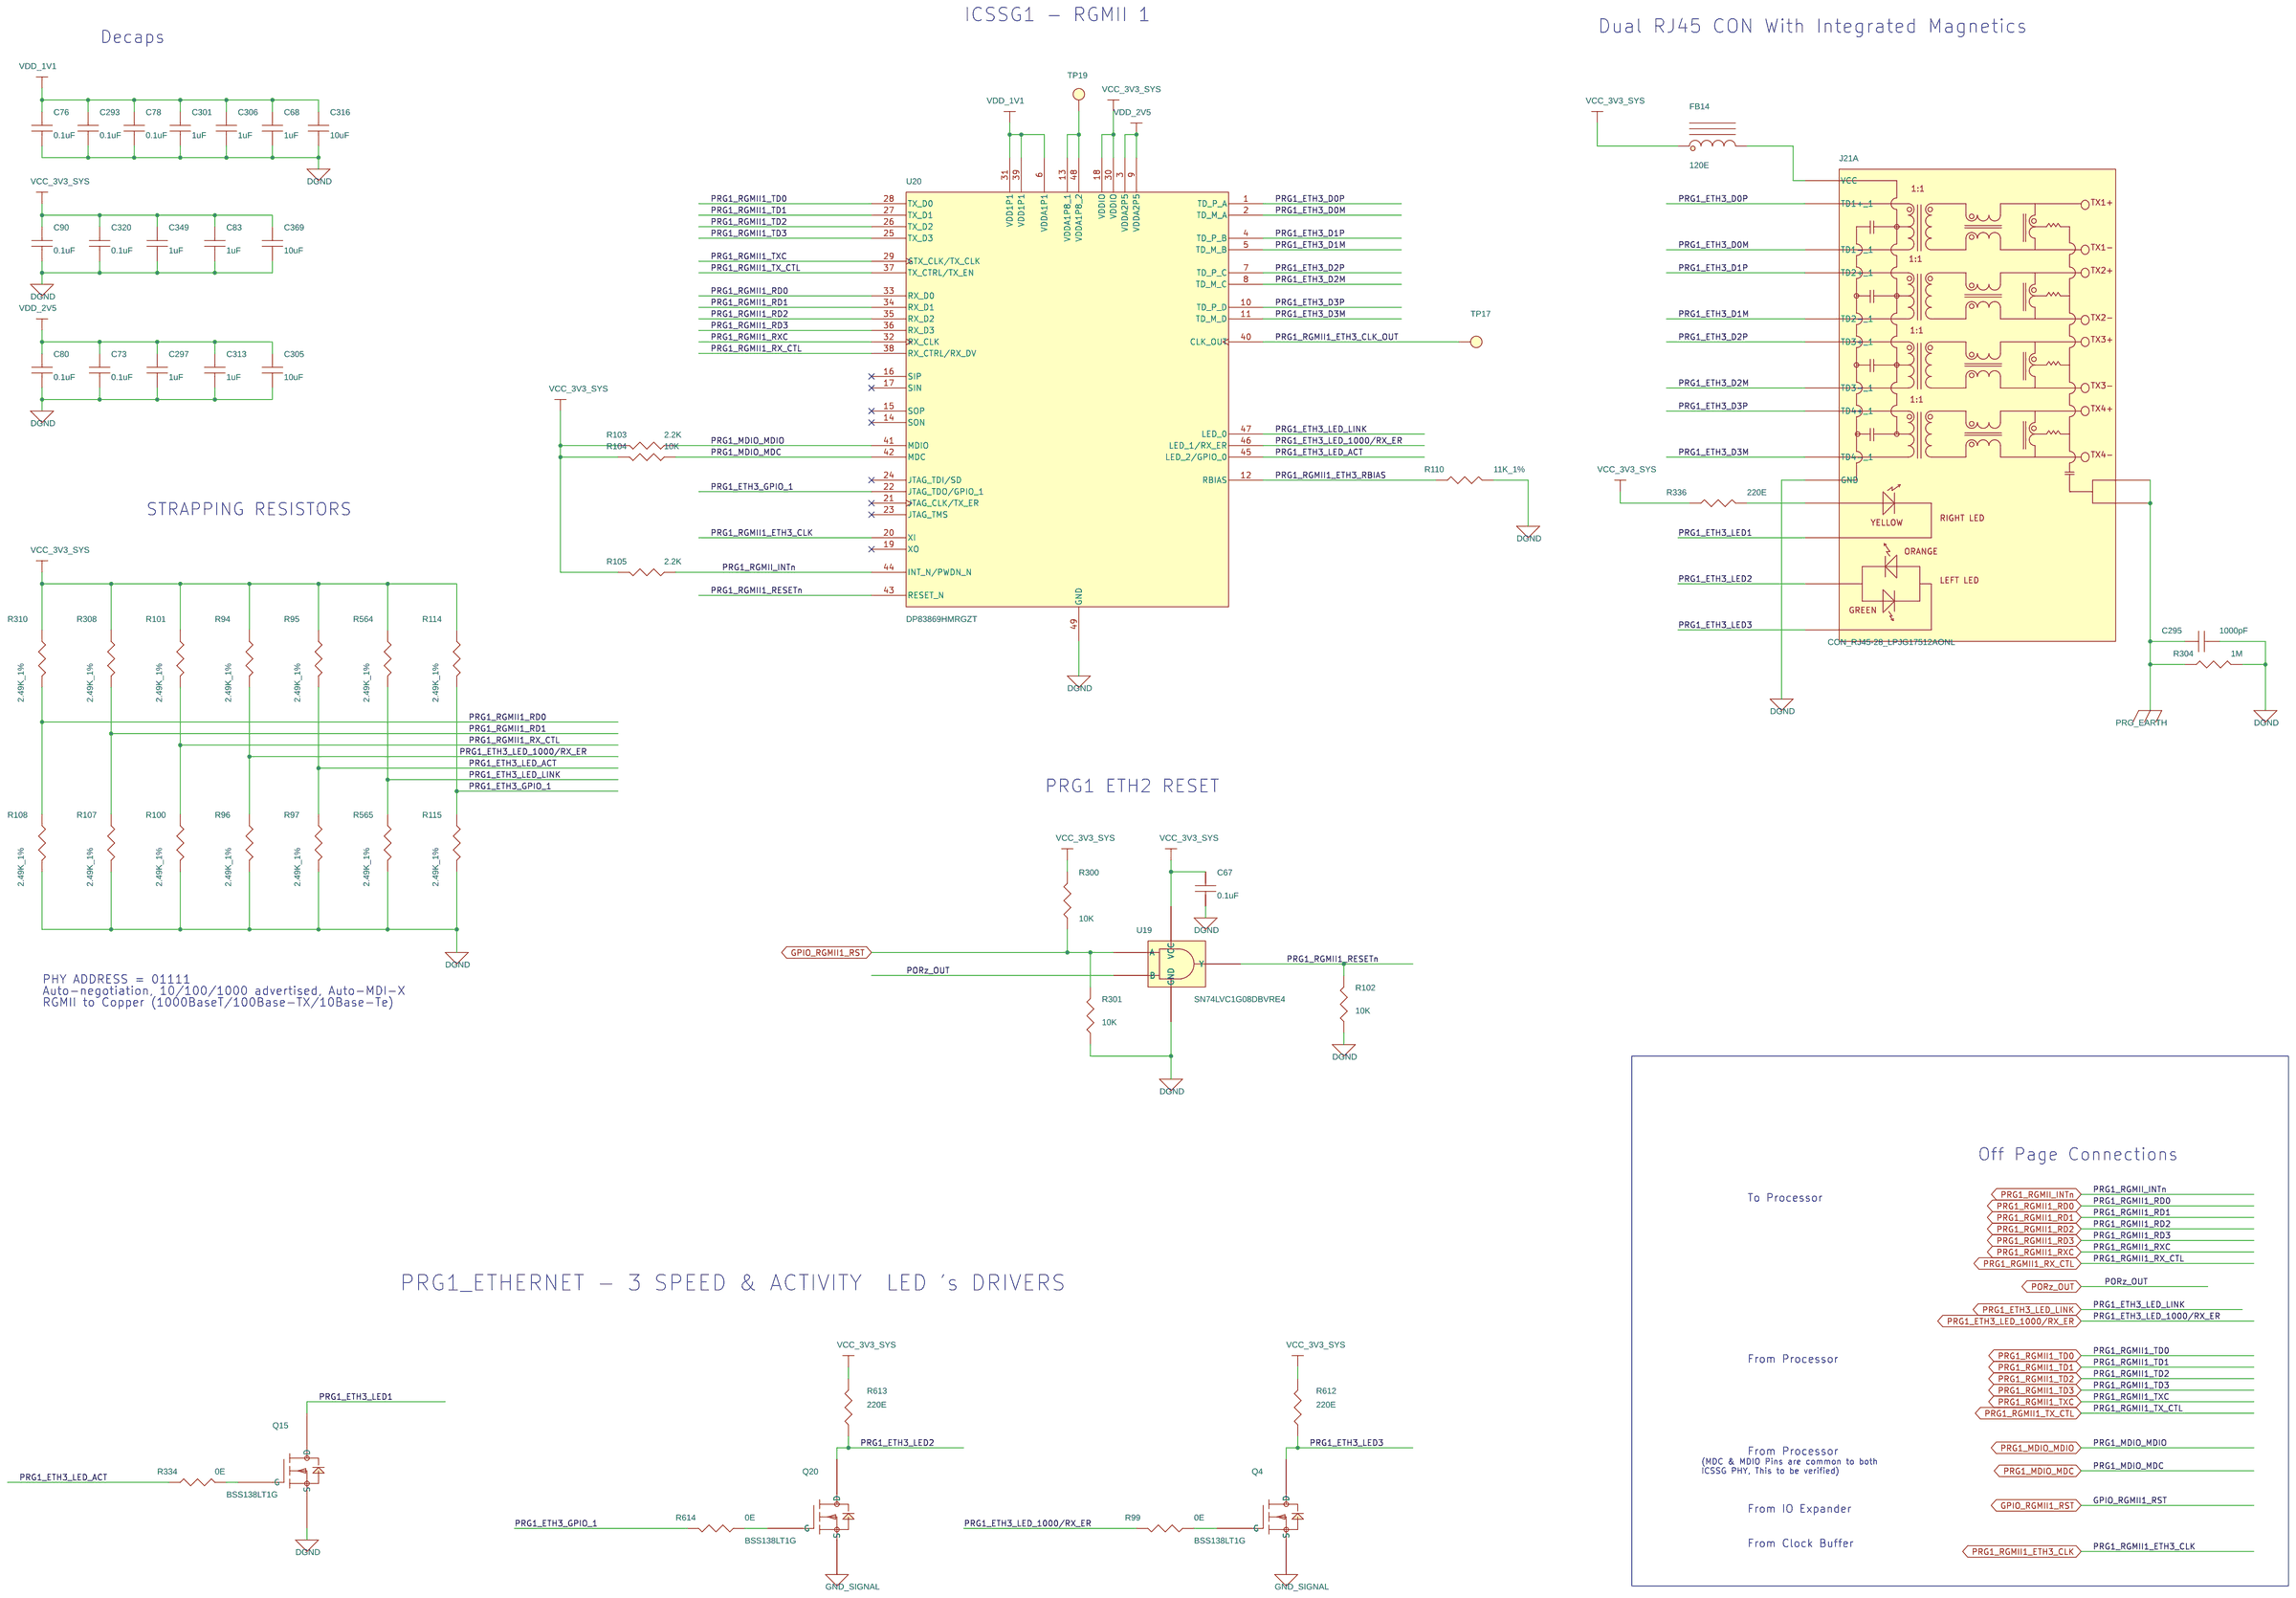
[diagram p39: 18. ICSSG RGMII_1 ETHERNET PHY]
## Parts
sheet 17. ICSSG RGMII_2 ETHERNET PHY
C89  0.1uF  [CAP0402_0-75]
C99  10uF  [CAP0402_0-75]
C101  1uF  [CAP0402_0-75]
C104  0.1uF  [CAP0402_0-75]
C105  10uF  [CAP0402_0-75]
C106  1uF  [CAP0402_0-75]
C110  1uF  [CAP0402_0-75]
C111  10uF  [CAP0402_0-75]
C112  1uF  [CAP0402_0-75]
C114  1uF  [CAP0402_0-75]
C124  0.1uF  [CAP0402_0-75]
C128  0.1uF  [CAP0402_0-75]
C385  0.1uF  [CAP0402_0-75]
C389  1uF  [CAP0402_0-75]
C392  0.1uF  [CAP0402_0-75]
C394  0.1uF  [CAP0402_0-75]
C395  0.1uF  [CAP0402_0-75]
C397  0.1uF  [CAP0402_0-75]
C401  1uF  [CAP0402_0-75]
FB19  120E  [IND0603_1]
J21  CON_RJ45-28_LPJG17512AONL  [CON_RJ45-28_LPJG17512_S_R_T_25-3]  (sections A,B)
Q14  BSS138LT1G  [SOT23-123_1-2]
Q16  BSS138LT1G  [SOT23-123_1-2]
Q21  BSS138LT1G  [SOT23-123_1-2]
R120  10K  [RES0402_0-5]
R121  10K  [RES0402_0-5]
R126  2.49K_1%  [RES0402_0-5]
R128  2.49K_1%  [RES0402_0-5]
R135  2.49K_1%  [RES0402_0-5]
R324  0E  [RES0402_0-5]
R340  2.49K_1%  [RES0402_0-5]
R341  2.49K_1%  [RES0402_0-5]
R343  0E  [RES0402_0-5]
R347  220E  [RES0402_0-5]
R349  11K_1%  [RES0402_0-5]
R359  2.49K_1%  [RES0402_0-5]
R363  2.49K_1%  [RES0402_0-5]
R366  2.49K_1%  [RES0402_0-5]
R367  10K  [RES0402_0-5]
R368  2.2K  [RES0402_0-5]
R369  10K  [RES0402_0-5]
R370  1.5K  [RES0402_0-5]
R371  10K  [RES0402_0-5]
R380  10K  [RES0402_0-5]
R385  2.49K_1%  [RES0402_0-5]
R386  2.49K_1%  [RES0402_0-5]
R387  2.49K_1%  [RES0402_0-5]
R388  2.49K_1%  [RES0402_0-5]
R562  2.49K_1%  [RES0402_0-5]
R563  2.49K_1%  [RES0402_0-5]
R615  220E  [RES0402_0-5]
R616  220E  [RES0402_0-5]
R617  0E  [RES0402_0-5]
TP69  TP20_SMD  [TP20_SMD]
TP78  TP20_SMD  [TP20_SMD]
U27  TMUX154EDGSR  [MSOP10_19-68_120X120_1-1]
U31  SN74LVC1G08DBVRE4  [SOT23-5]
U80  DP83869HMRGZT  [QFN48_19-68_280X280_1_EP4-2]
sheet 18. ICSSG RGMII_1 ETHERNET PHY
C67  0.1uF  [CAP0402_0-75]
C68  1uF  [CAP0402_0-75]
C73  0.1uF  [CAP0402_0-75]
C76  0.1uF  [CAP0402_0-75]
C78  0.1uF  [CAP0402_0-75]
C80  0.1uF  [CAP0402_0-75]
C83  1uF  [CAP0402_0-75]
C90  0.1uF  [CAP0402_0-75]
C293  0.1uF  [CAP0402_0-75]
C295  1000pF  [CAP1206_1-75]
C297  1uF  [CAP0402_0-75]
C301  1uF  [CAP0402_0-75]
C305  10uF  [CAP0402_0-75]
C306  1uF  [CAP0402_0-75]
C313  1uF  [CAP0402_0-75]
C316  10uF  [CAP0402_0-75]
C320  0.1uF  [CAP0402_0-75]
C349  1uF  [CAP0402_0-75]
C369  10uF  [CAP0402_0-75]
FB14  120E  [IND0603_1]
Q4  BSS138LT1G  [SOT23-123_1-2]
Q15  BSS138LT1G  [SOT23-123_1-2]
Q20  BSS138LT1G  [SOT23-123_1-2]
R94  2.49K_1%  [RES0402_0-5]
R95  2.49K_1%  [RES0402_0-5]
R96  2.49K_1%  [RES0402_0-5]
R97  2.49K_1%  [RES0402_0-5]
R99  0E  [RES0402_0-5]
R100  2.49K_1%  [RES0402_0-5]
R101  2.49K_1%  [RES0402_0-5]
R102  10K  [RES0402_0-5]
R103  2.2K  [RES0402_0-5]
R104  10K  [RES0402_0-5]
R105  2.2K  [RES0402_0-5]
R107  2.49K_1%  [RES0402_0-5]
R108  2.49K_1%  [RES0402_0-5]
R110  11K_1%  [RES0402_0-5]
R114  2.49K_1%  [RES0402_0-5]
R115  2.49K_1%  [RES0402_0-5]
R300  10K  [RES0402_0-5]
R301  10K  [RES0402_0-5]
R304  1M  [RES0603_0-75]
R308  2.49K_1%  [RES0402_0-5]
R310  2.49K_1%  [RES0402_0-5]
R334  0E  [RES0402_0-5]
R336  220E  [RES0402_0-5]
R564  2.49K_1%  [RES0402_0-5]
R565  2.49K_1%  [RES0402_0-5]
R612  220E  [RES0402_0-5]
R613  220E  [RES0402_0-5]
R614  0E  [RES0402_0-5]
TP17  TP20_SMD  [TP20_SMD]
TP19  TP20_SMD  [TP20_SMD]
U19  SN74LVC1G08DBVRE4  [SOT23-5]
U20  DP83869HMRGZT  [QFN48_19-68_280X280_1_EP4-2]
sheet 40. HARDWARE SCHEMATICS
ACC1  SPC02SYAN  [NA]
ACC2  SPC02SYAN  [NA]
ACC3  SPC02SYAN  [NA]
ACC4  MNT-103-BK-G  [NA]
ACC7  SPC02SYAN  [NA]
ACC8  SPC02SYAN  [NA]
ACC10  C19874  [BGASKT441_C19874_1190X1190_11]
ACC11  SZZC019i  [NA]
ACC12  SSZZ027  [NA]
ACC13  AM6442ALV
ACC14  SPC02SYAN  [NA]
ACC15  SPC02SYAN  [NA]
FID1  FID_40X80  [FID_40X80]
FID2  FID_40X80  [FID_40X80]
FID3  FID_40X80  [FID_40X80]
LBL1  THT-103-423-10  [NA]
LBL2  THT-103-423-10  [NA]
LBL3  THT-103-423-10  [NA]
Logo1  Texas Intruments  [TI_Stacked_Overlay_Small]
Logo2  For Evaluation only; not FCC approved for resale  [FCC_disclaimer]
Logo3  WEEE Mark  [TI_Stacked_Overlay_Small]
Logo4  CE Mark  [TI_Stacked_Overlay_Small]
M1  728  [NA]
M2  728  [NA]
M3  728  [NA]
M4  728  [NA]
M5  728  [NA]
M6  728  [NA]
M10  PLAIN WASHER_M3  [NA]
M11  PLAIN WASHER_M3  [NA]
M12  PLAIN WASHER_M3  [NA]
M13  PLAIN WASHER_M3  [NA]
M14  PLAIN WASHER_M3  [NA]
M19  PLAIN WASHER_M3  [NA]
MH1  HEX SPACER_M2.5 X 30  [NA]
MH2  HEX SPACER_M2.5 X 30  [NA]
MH3  HEX SPACER_M2.5 X 30  [NA]
MH4  HEX SPACER_M2.5 X 30  [NA]
MH5  HEX SPACER_M2.5 X 30  [NA]
MH6  HEX SPACER_M2.5 X 30  [NA]
MH13  PAN HEAD_M2.5 X 4  [NA]
MH14  PAN HEAD_M2.5 X 4  [NA]
MH15  PAN HEAD_M2.5 X 4  [NA]
MH16  PAN HEAD_M2.5 X 4  [NA]
MH17  PAN HEAD_M2.5 X 4  [NA]
MH18  PAN HEAD_M2.5 X 4  [NA]
MH19  PAN HEAD_M2.5 X 12  [NA]
MH20  PAN HEAD_M2.5 X 12  [NA]
MH21  PAN HEAD_M2.5 X 12  [NA]
MH22  PAN HEAD_M2.5 X 12  [NA]
MH23  PAN HEAD_M2.5 X 12  [NA]
MH24  PAN HEAD_M2.5 X 12  [NA]
PCB1  PROC101

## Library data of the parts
C67 C73 C76 C78 C80 C89 C90 C104 C124 C128 C293 C320 C385 C392 C394 C395 C397 = CAP: CAP CERAMIC 0.1uF 25V 20% X5R 0402; Alt_Mfr_name: YAGEO AMERICA; Alt_Mfr_part_number: CC0402KRX5R8BB104; Chkd/date: MANIRAJA/170820; Crtd /date: ALVY/170820; Custom_Duty: 15%; Customs_HS_Code: 85322990; Distributor_name: DIGIKEY; Distributor_part_number: 732-7495-1-ND; Footprint Path: Y:\MIS_DATABASE\Library\ALTIUM_TOOL\PCB_FOOTPRINTS\Altium_Footprint_Lib.PcbLib; Height: 0.55MM; Library Path: Y:\MIS_DATABASE\Library\ALTIUM_TOOL\SCHEMATICS_PARTS\MS_DISCRETE_Library.schlib; Mfr_name: WURTH ELECTRONICS; Mfr_part_number: 885012105018; Mistral Part No: 120020080003-R; Package: 0402; Part_type: CAPACITORS\CERAMIC; Project: AM64x_EVM_BRD; RoHS: RoHS; Temperature: -55°C+85°C; Tolerance: 20%; Voltage: 25V; Wattage: NA; Weight: 0.65mg; Datasheet: Y:\MIS_DATABASE\DATASHEETS\CAPACITORS\885012105018.PDF
C99 C105 C111 C305 C316 C369 = CAP: CAP CERAMIC 10uF 10V 20% X5R 0402; Chkd/date: MANIRAJA/300520; Crtd /date: ALVY/260520; Custom_Duty: 15%; Customs_HS_Code: 85322990; Distributor_name: DIGIKEY; Distributor_part_number: 490-GRM155R61A106ME11DTR-ND; Footprint Path: Y:\MIS_DATABASE\Library\ALTIUM_TOOL\PCB_FOOTPRINTS\Altium_Footprint_Lib.PcbLib; Height: 0.55MM; Library Path: Y:\MIS_DATABASE\Library\ALTIUM_TOOL\SCHEMATICS_PARTS\MS_DISCRETE_Library.schlib; Mfr_name: MURATA; Mfr_part_number: GRM155R61A106ME11D; Mistral Part No: 120013110019-R; Package: 0402; Part_type: CAPACITORS\CERAMIC; Project: QCS610_NANOSOM; RoHS: RoHS; Temperature: -55°C+85°C; Tolerance: 20%; Voltage: 10V; Wattage: NA; Weight: 3.1mg; Datasheet: Y:\MIS_DATABASE\DATASHEETS\CAPACITORS\MURATA-GXX-SER_NOV17.PDF
C68 C83 C101 C106 C110 C112 C114 C297 C301 C306 C313 C349 C389 C401 = CAP: CAP CERAMIC 1uF 10V 20% X5R 0402; Chkd/date: MANIRAJA/210820; Crtd /date: ALVY/190820; Custom_Duty: 15%; Customs_HS_Code: 85322990; Distributor_name: DIGIKEY; Distributor_part_number: 732-7489-1-ND; Footprint Path: Y:\MIS_DATABASE\Library\ALTIUM_TOOL\PCB_FOOTPRINTS\Altium_Footprint_Lib.PcbLib; Height: 0.55MM; Library Path: Y:\MIS_DATABASE\Library\ALTIUM_TOOL\SCHEMATICS_PARTS\MS_DISCRETE_Library.schlib; Mfr_name: WURTH ELECTRONICS; Mfr_part_number: 885012105012; Mistral Part No: 120020080009-R; Package: 0402; Part_type: CAPACITORS\CERAMIC; Project: AM64x_EVM_BRD; RoHS: RoHS; Temperature: -55°C+85°C; Tolerance: 20%; Voltage: 10V; Wattage: NA; Weight: 0.65mg; Datasheet: Y:\MIS_DATABASE\DATASHEETS\CAPACITORS\885012105012.PDF
FB14 FB19 = INDUCTOR_FERRITE: IND FERRITE BEAD CHIP 120E 2A 0603; Chkd/date: MANIRAJA/180820; Crtd /date: ALVY/180820; Custom_Duty: 24%; Customs_HS_Code: 85437099; Distributor_name: DIGIKEY; Distributor_part_number: 732-782631141CT-ND; Footprint Path: Y:\MIS_DATABASE\Library\ALTIUM_TOOL\PCB_FOOTPRINTS\Altium_Footprint_Lib.PcbLib; Height: 1.00MM; Library Path: Y:\MIS_DATABASE\Library\ALTIUM_TOOL\SCHEMATICS_PARTS\MS_FILTER_Library.schlib; Mfr_name: WURTH ELECTRONICS; Mfr_part_number: 782631141; Mistral Part No: 130020080015-R; Package: 0603; Part_type: INDUCTOR; Project: AM64x_EVM_BRD; RoHS: RoHS; Temperature: -55°C+125°C; Tolerance: 25%; Voltage: NA; Wattage: NA; Weight: NA; Datasheet: Y:\MIS_DATABASE\DATASHEETS\DISCRETES\INDUCTORS\782631141.PDF
J21 = CON_RJ45-28_LPJG17512AONL: CON JACK RJ45 28POS REGISTERED FEMALE RA TH; Chkd/date: MANIRAJA/010817; Crtd /date: MANIRAJA/010817; Custom_Duty: 24%; Customs_HS_Code: 85369090; Distributor_name: NA; Distributor_part_number: NA; Height: 25.30MM; Mfr_name: LINK-PP; Mfr_part_number: LPJG17512AONL; Mistral Part No: 150017080001-R; Package: THRU-HOLE; Part_type: CONNECTOR\JACK; Project: TI_SVB_DUT; RoHS: RoHS; Temperature: 0°C+70°C; Tolerance: NA; Voltage: NA; Wattage: NA; Weight: NA; Datasheet: Y:\MIS_DATABASE\DATASHEETS\CONNECTORS\LPJG17512AONL.PDF
Q4 Q14-Q16 Q20 Q21 = MOSFET_BSS138LT1G: IC MOSFET N-CHANNEL 50V 200mA SOT23-3; Chkd/date: MANIRAJA/250219; Crtd /date: JEBRAN/060416; Custom_Duty: 15%; Customs_HS_Code: 85423100; Distributor_name: DIGIKEY; Distributor_part_number: BSS138LT1GOSCT-ND; Footprint Path: Y:\MIS_DATABASE\Library\ALTIUM_TOOL\PCB_FOOTPRINTS\Altium_Footprint_Lib.PcbLib; Height: 1.11MM; Library Path: Y:\MIS_DATABASE\Library\ALTIUM_TOOL\SCHEMATICS_PARTS\MS_MOSFET_Library.schlib; Library Ref: MOSFET_BSS138W; Mfr_name: ON SEMICONDUCTOR; Mistral Part No: 142016040001-R; Package: SOT23-3; Part_type: ICS\POWER\MOSFET; Project: LRDE_ABCM; RoHS: RoHS; Temperature: -55°C+150°C; Tolerance: NA; Voltage: NA; Wattage: NA; Weight: 8mg; Datasheet: Y:\MIS_DATABASE\DATASHEETS\DISCRETES\TRANSISTORS_FETS\BSS138LT1G.PDF
R102 R104 R120 R121 R300 R301 R367 R369 R371 R380 = RESISTOR: RES 10K 1/16W 5% 0402; Chkd/date: VASANTHA/061216; Crtd /date: MAZHAR/230805; Custom_Duty: 15%; Customs_HS_Code: 85332119; Distributor_name: DIGIKEY; Distributor_part_number: 311-10KJRCT-ND; Footprint Path: Y:\MIS_DATABASE\Library\ALTIUM_TOOL\PCB_FOOTPRINTS\Altium_Footprint_Lib.PcbLib; Height: 0.40MM; Library Path: Y:\MIS_DATABASE\Library\ALTIUM_TOOL\SCHEMATICS_PARTS\MS_DISCRETE_Library.schlib; Mfr_name: YAGEO AMERICA; Mfr_part_number: RC0402JR-0710KL; Mistral Part No: 110011060021-R; Package: 0402; Part_type: RESISTORS\FIXED; Project: HSE; RoHS: RoHS; Temperature: -55°C+155°C; Tolerance: 5%; Voltage: NA; Wattage: 1/16W; Weight: 0.65mg; Datasheet: Y:\MIS_DATABASE\DATASHEETS\RESISTORS\RCXXXXL-SER_MAR18.PDF
R94-R97 R100 R101 R107 R108 R114 R115 R126 R128 R135 R308 R310 R340 R341 R359 R363 R366 R385-R388 R562-R565 = RESISTOR: RES 2.49K 1/16W 1% 0402; Chkd/date: VASANTHA/270516; Crtd /date: VASANTHA/270516; Custom_Duty: 15%; Customs_HS_Code: 85332119; Distributor_name: DIGIKEY; Distributor_part_number: 311-2.49KLRCT-ND; Footprint Path: Y:\MIS_DATABASE\Library\ALTIUM_TOOL\PCB_FOOTPRINTS\Altium_Footprint_Lib.PcbLib; Height: 0.40MM; Library Path: Y:\MIS_DATABASE\Library\ALTIUM_TOOL\SCHEMATICS_PARTS\MS_DISCRETE_Library.schlib; Mfr_name: YAGEO AMERICA; Mfr_part_number: RC0402FR-072K49L; Mistral Part No: 110016050020-R; Package: 0402; Part_type: RESISTORS\FIXED; Project: TMDXCSKCC; RoHS: RoHS; Temperature: -55°C+155°C; Tolerance: 1%; Voltage: NA; Wattage: 1/16W; Weight: 0.65mg; Datasheet: Y:\MIS_DATABASE\DATASHEETS\RESISTORS\RCXXXXL-SER_MAR18.PDF
R99 R324 R334 R343 R614 R617 = RESISTOR: RES 0E 1/16W JUMPER 0402; Chkd/date: VASANTHA/201216; Crtd /date: MUDDU/190810; Custom_Duty: 15%; Customs_HS_Code: 85332119; Distributor_name: DIGIKEY; Distributor_part_number: 541-0.0JCT-ND; Footprint Path: Y:\MIS_DATABASE\Library\ALTIUM_TOOL\PCB_FOOTPRINTS\Altium_Footprint_Lib.PcbLib; Height: 0.40MM; Library Path: Y:\MIS_DATABASE\Library\ALTIUM_TOOL\SCHEMATICS_PARTS\MS_DISCRETE_Library.schlib; Mfr_name: VISHAY; Mfr_part_number: CRCW04020000Z0ED; Mistral Part No: 110010080019-R; Package: 0402; Part_type: RESISTORS\FIXED; Project: PB_BUGBASE; RoHS: RoHS; Temperature: -55°C+155°C; Tolerance: NA; Voltage: NA; Wattage: 1/16W; Weight: 0.65mg; Datasheet: Y:\MIS_DATABASE\DATASHEETS\RESISTORS\CRCW0603.PDF
R336 R347 R612 R613 R615 R616 = RESISTOR: RES 220E 1/10W 5% 0402; Chkd/date: VASANTHA/291216; Crtd /date: GEETHA/260406; Custom_Duty: 15%; Customs_HS_Code: 85332119; Distributor_name: DIGIKEY; Distributor_part_number: P220JCT-ND; Footprint Path: Y:\MIS_DATABASE\Library\ALTIUM_TOOL\PCB_FOOTPRINTS\Altium_Footprint_Lib.PcbLib; Height: 0.40MM; Library Path: Y:\MIS_DATABASE\Library\ALTIUM_TOOL\SCHEMATICS_PARTS\MS_DISCRETE_Library.schlib; Mfr_name: PANASONIC-ECG; Mfr_part_number: ERJ-2GEJ221X; Mistral Part No: 110009030506-R; Package: 0402; Part_type: RESISTORS\FIXED; Project: RED EYE; RoHS: RoHS; Temperature: -55°C+155°C; Tolerance: 5%; Voltage: NA; Wattage: 1/10W; Weight: 0.8mg; Datasheet: Y:\MIS_DATABASE\DATASHEETS\RESISTORS\PAN-ERJSER_NOV17.PDF
R110 R349 = RESISTOR: RES 11K 1/16W 1% 0402; Chkd/date: VASANTHA/251115; Crtd /date: VASANTHA/251115; Custom_Duty: 15%; Customs_HS_Code: 85332119; Distributor_name: DIGIKEY; Distributor_part_number: 311-11.0KLRCT-ND; Footprint Path: Y:\MIS_DATABASE\Library\ALTIUM_TOOL\PCB_FOOTPRINTS\Altium_Footprint_Lib.PcbLib; Height: 0.40MM; Library Path: Y:\MIS_DATABASE\Library\ALTIUM_TOOL\SCHEMATICS_PARTS\MS_DISCRETE_Library.schlib; Mfr_name: YAGEO AMERICA; Mfr_part_number: RC0402FR-0711KL; Mistral Part No: 110015110012-R; Package: 0402; Part_type: RESISTORS\FIXED; Project: TI_VLAN_SWITCH; RoHS: RoHS; Temperature: -55°C+155°C; Tolerance: 1%; Voltage: NA; Wattage: 1/16W; Weight: 0.65mg; Datasheet: Y:\MIS_DATABASE\DATASHEETS\RESISTORS\RCXXXXL-SER_MAR18.PDF
R103 R105 R368 = RESISTOR: RES 2.2K 1/16W 5% 0402; Chkd/date: VASANTHA/061216; Crtd /date: BAVISH/021210; Custom_Duty: 15%; Customs_HS_Code: 85332119; Distributor_name: DIGIKEY; Distributor_part_number: 311-2.2KJRCT-ND; Footprint Path: Y:\MIS_DATABASE\Library\ALTIUM_TOOL\PCB_FOOTPRINTS\Altium_Footprint_Lib.PcbLib; Height: 0.40MM; Library Path: Y:\MIS_DATABASE\Library\ALTIUM_TOOL\SCHEMATICS_PARTS\MS_DISCRETE_Library.schlib; Mfr_name: YAGEO AMERICA; Mfr_part_number: RC0402JR-072K2L; Mistral Part No: 110010120018-R; Package: 0402; Part_type: RESISTORS\FIXED; Project: TE4; RoHS: RoHS; Temperature: -55°C+155°C; Tolerance: 5%; Voltage: NA; Wattage: 1/16W; Weight: 0.65mg; Datasheet: Y:\MIS_DATABASE\DATASHEETS\RESISTORS\RCXXXXL-SER_MAR18.PDF
R370 = RESISTOR: RES 1.5K 1/16W 5% 0402; Chkd/date: MANIRAJA/310718; Crtd /date: BAVISH/021210; Custom_Duty: 15%; Customs_HS_Code: 85332119; Distributor_name: DIGIKEY; Distributor_part_number: 311-1.5KJRCT-ND; Footprint Path: Y:\MIS_DATABASE\Library\ALTIUM_TOOL\PCB_FOOTPRINTS\Altium_Footprint_Lib.PcbLib; Height: 0.40MM; Library Path: Y:\MIS_DATABASE\Library\ALTIUM_TOOL\SCHEMATICS_PARTS\MS_DISCRETE_Library.schlib; Mfr_name: YAGEO AMERICA; Mfr_part_number: RC0402JR-071K5L; Mistral Part No: 110010120012-R; Package: 0402; Part_type: RESISTORS\FIXED; Project: TE4; RoHS: RoHS; Temperature: -55°C+155°C; Tolerance: 5%; Voltage: NA; Wattage: 1/16W; Weight: 0.65mg; Datasheet: Y:\MIS_DATABASE\DATASHEETS\RESISTORS\RCXXXXL-SER_MAR18.PDF
TP17 TP19 TP69 TP78 = TESTPOINT: TESTPOINT CIR 20 SMD; Chkd/date: SHREESHAIL/171006; Crtd /date: MAZHAR/171006; Custom_Duty: NA; Customs_HS_Code: NA; Distributor_name: NA; Distributor_part_number: NA; Footprint Path: Y:\MIS_DATABASE\Library\ALTIUM_TOOL\PCB_FOOTPRINTS\Altium_Footprint_Lib.PcbLib; Height: NA; Library Path: Y:\MIS_DATABASE\Library\ALTIUM_TOOL\SCHEMATICS_PARTS\MS_DISCRETE_Library.schlib; MECHANICAL 3D STEP FILE: NA; Mfr_name: LOCAL; Mistral Part No: NA; Package: SMD; Project: BT MODULE_CSRBC04; RoHS: NA; Temperature: NA; Tolerance: NA; Voltage: NA; Wattage: NA; Weight: NA; Datasheet: NA
U27 = TMUX154EDGSR_VSSOP10: IC ESD PROTECTED 2-CH 2:1 SWITCH WITH POWERED-OFF PROTECTION VSSOP10; Chkd/date: MANIRAJA/040918; Crtd /date: MANIRAJA/040918; Custom_Duty: 15%; Customs_HS_Code: 85423100; Distributor_name: DIGIKEY; Distributor_part_number: 296-48347-1-ND; Footprint Path: Y:\MIS_DATABASE\Library\ALTIUM_TOOL\PCB_FOOTPRINTS\Altium_Footprint_Lib.PcbLib; Height: 1.10MM; Library Path: Y:\MIS_DATABASE\Library\ALTIUM_TOOL\SCHEMATICS_PARTS\MS_ANALOG-APPLICATION_Library.schlib; Mfr_name: TEXAS INSTRUMENTS; Mistral Part No: 140118090001-R; Package: VSSOP10; Part_type: ICS\ANALOG\SWITCH; Project: DLRL_DFP_ATRUC CARD; RoHS: RoHS; Temperature: -40°C+85°C; Tolerance: NA; Voltage: NA; Wattage: NA; Weight: NA; Datasheet: Y:\MIS_DATABASE\DATASHEETS\ICS\ANALOG\TMUX154EXXX.PDF
U19 U31 = SN74LVC1G08DBVRE4_SOT23-5: IC SINGLE 2-INPUT POSITIVE AND GATE SOT23-5; Chkd/date: SUHAS/221010; Crtd /date: USMAN/151008; Custom_Duty: 15%; Customs_HS_Code: 85423100; Distributor_name: DIGIKEY; Distributor_part_number: SN74LVC1G08DBVRE4-ND; Height: 1.45MM; Mfr_name: TEXAS INSTRUMENTS; Mistral Part No: 141009060026-R; Part_type: ICS\DIGITAL\GATES; Project: KHAN_MAIN; RoHS: Sb/ Br FREE; Temperature: -40°C+85°C; Datasheet: Y:\MIS_DATABASE\DATASHEETS\ICS\DIGITAL\GATES\SN74LVC1G08.PDF
U20 U80 = DP83869HM_VQFN48: IC ETHERNET TRANSCEIVER 10/100/1000 WITH COPPER AND FIBRE INTERFACE VQFN48; Chkd/date: MANIRAJA/060519; Crtd /date: ALVY/060519; Custom_Duty: 15%; Customs_HS_Code: 85423100; Distributor_name: DIGIKEY; Distributor_part_number: 296-53377-1-ND; Footprint Path: Y:\MIS_DATABASE\Library\ALTIUM_TOOL\PCB_FOOTPRINTS\Altium_Footprint_Lib.PcbLib; Height: 1.00MM; Library Path: Y:\MIS_DATABASE\Library\ALTIUM_TOOL\SCHEMATICS_PARTS\MS_TELECOM_Library.schlib; Mfr_name: TEXAS INSTRUMENTS; Mistral Part No: 143019050002-R; Package: VQFN48; Part_type: ICS\TELECOM\TRANSCEIVER; Project: J7ES_ENET_DP83869HM_EXP; RoHS: RoHS; Temperature: -40°C+125°C; Tolerance: NA; Voltage: NA; Wattage: NA; Weight: NA; Datasheet: Y:\MIS_DATABASE\DATASHEETS\ICS\TELECOM\DP83869HM.PDF
C295 = CAP: CAP CERAMIC 1000pF 2KV 10% X7R 1206; Chkd/date: SHREESHAIL/291106; Crtd /date: MAZHAR/281106; Custom_Duty: 15%; Customs_HS_Code: 85322990; Distributor_name: DIGIKEY; Distributor_part_number: 478-2956-1-ND; Footprint Path: Y:\MIS_DATABASE\Library\ALTIUM_TOOL\PCB_FOOTPRINTS\Altium_Footprint_Lib.PcbLib; Height: 1.52MM; Library Path: Y:\MIS_DATABASE\Library\ALTIUM_TOOL\SCHEMATICS_PARTS\MS_DISCRETE_Library.schlib; Mfr_name: AVX CORPORATION; Mfr_part_number: 1206GC102KAT1A; Mistral Part No: 120015080006-R; Package: 1206; Part_type: CAPACITORS\CERAMIC; Project: ADR1B; RoHS: RoHS; Temperature: -55°C+125°C; Tolerance: 10%; Voltage: 2KV; Wattage: NA; Weight: 16.2mg; Datasheet: Y:\MIS_DATABASE\DATASHEETS\CAPACITORS\AVX_HV-MLC.PDF
R304 = RESISTOR: RES 1M 1/10W 5% 0603; Chkd/date: VASANTHA/060217; Crtd /date: USMAN/111207; Custom_Duty: 15%; Customs_HS_Code: 85332119; Distributor_name: DIGIKEY; Distributor_part_number: P1.0MGCT-ND; Footprint Path: Y:\MIS_DATABASE\Library\ALTIUM_TOOL\PCB_FOOTPRINTS\Altium_Footprint_Lib.PcbLib; Height: 0.55MM; Library Path: Y:\MIS_DATABASE\Library\ALTIUM_TOOL\SCHEMATICS_PARTS\MS_DISCRETE_Library.schlib; Mfr_name: PANASONIC-ECG; Mfr_part_number: ERJ-3GEYJ105V; Mistral Part No: 110009030413-R; Package: 0603; Part_type: RESISTORS\FIXED; Project: BSN; RoHS: RoHS; Temperature: -55°C+155°C; Tolerance: 5%; Voltage: NA; Wattage: 1/10W; Weight: 2mg; Datasheet: Y:\MIS_DATABASE\DATASHEETS\RESISTORS\PAN-ERJSER_NOV17.PDF
ACC1-ACC3 ACC7 ACC8 ACC14 ACC15 = ACCESSORY: ACCESSORIE JUMPER SHORTING GOLD FLASH; Chkd/date: SUHAS\211010; Crtd /date: USMAN/301208; Distributor_name: DIGIKEY; Distributor_part_number: S9001-ND; Footprint Path: Y:\MIS_DATABASE\Library\ALTIUM_TOOL\PCB_FOOTPRINTS\Altium_Footprint_Lib.PcbLib; Library Path: Y:\MIS_DATABASE\Library\ALTIUM_TOOL\SCHEMATICS_PARTS\MS_MECHANICAL_Library.schlib; Mfr_name: SULLINS CONNECTOR; Mistral Part No: 160009030153-R; Part_type: ACCESSORIES; Project: SMART VIEW_NVR; RoHS: RoHS; Temperature: -55°C+105°C; Datasheet: Y:\MIS_DATABASE\DATASHEETS\MISC\MODULES\SPC02SYAN.PDF
ACC4 = ACCESSORY: ACCESSORIE CONNECTOR SHUNT 2X3 POS EDGE MOUNT SOCKET STRIP; Chkd/date: MANIRAJA/141117; Crtd /date: MANIRAJA/141117; Distributor_name: DIGIKEY; Distributor_part_number: SAM10620-ND; Mfr_name: SAMTEC; Mistral Part No: 160017110050-R; Part_type: ACCESSORIES; Project: TI_MAXIE_CPB; RoHS: RoHS; Temperature: -55°C+125°C; Datasheet: Y:\MIS_DATABASE\DATASHEETS\MISC\ACCESSORIES\SAMTEC-MNT-SER.PDF
ACC10 = ACCESSORY: ACCESSORIE BGA SOCKET AM64x MICROPROCESSOR BGA441; Chkd/date: MANIRAJA/220620; Crtd /date: ALVY/220620; Custom_Duty: NA; Customs_HS_Code: NA; Distributor_name: NA; Distributor_part_number: NA; Footprint Path: NA; Height: 10.93MM; Library Path: NA; Mfr_name: IRONWOOD ELECTRONICS; Mistral Part No: 160020060058; Package: BGA441; Part_type: ACCESSORIES; Project: AM64x-GP_EVM BRD; RoHS: NA; Temperature: -55°C+160°C; Tolerance: NA; Voltage: NA; Wattage: NA; Weight: 39530mg; Datasheet: Y:\MIS_DATABASE\DATASHEETS\MISC\ACCESSORIES\C19874_MAY20.PDF
ACC11 = ACCESSORY: ACCESSORIE TI EVM FLYERS STANDARD TERMS AND CONDITIONS; Chkd/date: MANIRAJA/221020; Crtd /date: ALVY/211020; Mfr_name: TEXAS INSTRUMENTS; Mistral Part No: 160020100056; Part_type: ACCESSORIES; Project: AM64x-IO LINK BRD
ACC12 = ACCESSORY: ACCESSORIE TI EVM FLYERS STANDARD WARRANTY NOTICE-BLACK AND WHITE; Chkd/date: MANIRAJA/221020; Crtd /date: ALVY/211020; Mfr_name: TEXAS INSTRUMENTS; Mistral Part No: 160020100057; Part_type: ACCESSORIES; Project: AM64x-IO LINK BRD
ACC13 = ACCESSORY: IC AM64 SoC MICROPROCESSOR BGA441; Custom_Duty: NA; Customs_HS_Code: NA; Distributor_name: NA; Distributor_part_number: NA; Footprint Path: NA; Height: 2.57MM; Library Path: NA; Mfr_name: TEXAS INSTRUMENTS; Mfr_part_number: AM6442ASFGGAALV; Mistral Part No: 141220040002; Package: BGA441; Part_type: ACCESSORIES; Project: AM64x-GP_EVM BRD; RoHS: NA; Temperature: -55°C+160°C; Tolerance: NA; Voltage: NA; Wattage: NA; Weight: 39530mg; Datasheet: Y:\MIS_DATABASE\DATASHEETS\MISC\ACCESSORIES\C19874_MAY20.PDF
FID1-FID3 = Fiducial
LBL1-LBL3 = ACCESSORY_THT-3-423-10: ACCESSORIE 1 WORKHORSE POLYSTER LABLE 0.25" X 1"; Chkd/date: MANIRAJA/270218; Crtd /date: ALVY/260218; Footprint Path: Y:\MIS_DATABASE\Library\ALTIUM_TOOL\PCB_FOOTPRINTS\Altium_Footprint_Lib.PcbLib; Library Path: Y:\MIS_DATABASE\Library\ALTIUM_TOOL\SCHEMATICS_PARTS\MS_MECHANICAL_Library.schlib; Mfr_name: BRADY; Mistral Part No: 160018020185; Part_type: ACCESSORIES; Project: TI_MAXIE_CPB
Logo1 Logo3 Logo4 = TI_Logo
Logo2 = FCC_disclaimer
M1-M6 = ACCESSORY: ACCESSORIE RECESSED BUMPER 19.05MM DIA; Chkd/date: MANIRAJA/110718; Crtd /date: MANIRAJA/110718; Distributor_name: DIGIKEY; Distributor_part_number: 36-728-ND; Mfr_name: KEYSTONE; Mistral Part No: 160018070042-R; Part_type: ACCESSORIES; Project: TI_MAXIE_CPB; RoHS: RoHS; Weight: 2042mg; Datasheet: Y:\MIS_DATABASE\DATASHEETS\MISC\ACCESSORIES\728.PDF
M10-M14 M19 = WASHER_PLAIN: PLAIN WASHER FOR M3 SS-316; Chkd/date: MANIRAJA/190218; Crtd /date: MANIRAJA/190218; Distributor_name: DIGIKEY; Distributor_part_number: 36-4692-ND; Footprint Path: Y:\MIS_DATABASE\Library\ALTIUM_TOOL\PCB_FOOTPRINTS\Altium_Footprint_Lib.PcbLib; Library Path: Y:\MIS_DATABASE\Library\ALTIUM_TOOL\SCHEMATICS_PARTS\MS_MECHANICAL_Library.schlib; Mfr_name: KEYSTONE; Mfr_part_number: 4692; Mistral Part No: 160018020078-R; Package: SS; Part_type: MECHANICAL\WASHERS; Project: TI_MAXIE_CPB; RoHS: RoHS; Datasheet: Y:\MIS_DATABASE\DATASHEETS\MISC\MECHANICAL\4692.PDF
MH1-MH6 = HEX_SPACER_FF: HEX SPACER FEMALE TO FEMALE M2.5 X 30MM; Chkd/date: MANIRAJA/190218; Crtd /date: MANIRAJA/190218; Distributor_name: DIGIKEY; Distributor_part_number: 732-10626-ND; Footprint Path: Y:\MIS_DATABASE\Library\ALTIUM_TOOL\PCB_FOOTPRINTS\Altium_Footprint_Lib.PcbLib; Height: 30.00MM; Library Path: Y:\MIS_DATABASE\Library\ALTIUM_TOOL\SCHEMATICS_PARTS\MS_MECHANICAL_Library.schlib; Mfr_name: WURTH ELECTRONICS; Mfr_part_number: 970300151; Mistral Part No: 160018020071-R; Package: SS; Part_type: MECHANICAL\SPACER; Project: TI_MAXIE_CPB; RoHS: RoHS; Datasheet: Y:\MIS_DATABASE\DATASHEETS\MISC\MECHANICAL\970XXX1.PDF
MH13-MH18 = SCREW_PAN: PHILLIPS PAN HEAD SCREW - M2.5 X 4 SS-316; Chkd/date: MANIRAJA/190218; Crtd /date: MANIRAJA/190218; Distributor_name: DIGIKEY; Distributor_part_number: 36-29300-ND; Footprint Path: Y:\MIS_DATABASE\Library\ALTIUM_TOOL\PCB_FOOTPRINTS\Altium_Footprint_Lib.PcbLib; Height: 4.00MM; Library Path: Y:\MIS_DATABASE\Library\ALTIUM_TOOL\SCHEMATICS_PARTS\MS_MECHANICAL_Library.schlib; Mfr_name: KEYSTONE; Mfr_part_number: 29300; Mistral Part No: 160018020076-R; Package: SS; Part_type: MECHANICAL\SCREWS; Project: TI_MAXIE_CPB; RoHS: RoHS; Datasheet: Y:\MIS_DATABASE\DATASHEETS\MISC\MECHANICAL\29300.PDF
MH19-MH24 = SCREW_PAN: PHILLIPS PAN HEAD SCREW - M2.5 X 12; Chkd/date: MANIRAJA/110718; Crtd /date: MANIRAJA/110718; Distributor_name: DIGIKEY; Distributor_part_number: 36-29304-ND; Height: 12.00MM; Mfr_name: KEYSTONE; Mfr_part_number: 29304; Mistral Part No: 160018070043-R; Part_type: ACCESSORIES; Project: TI_MAXIE_CPB; RoHS: RoHS; Datasheet: Y:\MIS_DATABASE\DATASHEETS\MISC\MECHANICAL\29304.PDF
PCB1 = PCB: AM64x EVM Bare PCB; Mfr_part_number: PROC101A

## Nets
DGND: C67.2 C68.2 C73.2 C76.2 C78.2 C80.2 C83.2 C89.2 C90.2 C99.2 C101.2 C104.2 C105.2 C106.2 C110.2 C111.2 C112.2 C114.2 C124.2 C128.2 C293.2 C295.2 C297.2 C301.2 C305.2 C306.2 C313.2 C316.2 C320.2 C349.2 C369.2 C385.2 C389.2 C392.2 C394.2 C395.2 C397.2 C401.2 J21.A10(GND) J21.B10(GND) Q4.2(S) Q14.2(S) Q15.2(S) Q16.2(S) Q20.2(S) Q21.2(S) R96.2 R97.2 R100.2 R102.2 R107.2 R108.2 R110.1 R115.2 R120.2 R121.2 R135.2 R301.2 R304.2 R341.2 R349.1 R359.2 R363.2 R367.2 R371.2 R385.2 R386.2 R563.2 R565.2 U19.3(GND) U20.49(GND) U27.5(GND) U31.3(GND) U80.49(GND) ; also on sheet 2 3 4 5 6 7 8 9 10 11 12 13 14 15 16 17 18 19 20 21 22 23 24 25 26 27 28 29 30
VCC_3V3_SYS: C67.1 C83.1 C89.1 C90.1 C99.1 C101.1 C104.1 C128.1 C320.1 C349.1 C369.1 C385.1 C389.1 FB14.1 FB19.1 R94.1 R95.1 R101.1 R103.2 R104.1 R105.2 R114.1 R126.1 R128.1 R300.2 R308.1 R310.1 R336.1 R340.1 R347.1 R366.1 R368.2 R369.1 R370.2 R380.2 R387.1 R388.1 R562.1 R564.1 R612.2 R613.2 R615.2 R616.2 U19.5(VCC) U20.18(VDDIO) U20.30(VDDIO) U27.10(VCC) U31.5(VCC) U80.18(VDDIO) U80.30(VDDIO) ; also on sheet 2 5 6 7 8 10 11 12 13 14 15 16 17 18 19 20 21 23 24 25 26 27 29 30
VDD_1V1: C68.1 C76.1 C78.1 C105.1 C110.1 C112.1 C124.1 C293.1 C301.1 C306.1 C316.1 C394.1 C395.1 C401.1 U20.6(VDDA1P1) U20.31(VDD1P1) U20.39(VDD1P1) U80.6(VDDA1P1) U80.31(VDD1P1) U80.39(VDD1P1) ; also on sheet 16
VDD_2V5: C73.1 C80.1 C106.1 C111.1 C114.1 C297.1 C305.1 C313.1 C392.1 C397.1 U20.3(VDDA2P5) U20.9(VDDA2P5) U80.3(VDDA2P5) U80.9(VDDA2P5) ; also on sheet 2 16
CPSW_RGMII1_MDC: U27.7(B1) ; also on sheet 2 18
CPSW_RGMII1_MDIO: U27.3(A1) ; also on sheet 2 18
GPIO_RGMII1_RST: R300.1 R301.1 U19.1(A) ; also on sheet 13
GPIO_RGMII2_RST: R371.1 R380.1 U31.1(A) ; also on sheet 13
PORz_OUT: U19.2(B) U31.2(B) ; also on sheet 2 12 24 29
PRG1_ETH2_D0M: J21.B2(TD1-_2) U80.2(TD_M_A)
PRG1_ETH2_D0P: J21.B1(TD1+_2) U80.1(TD_P_A)
PRG1_ETH2_D1M: J21.B4(TD2-_2) U80.5(TD_M_B)
PRG1_ETH2_D1P: J21.B3(TD2+_2) U80.4(TD_P_B)
PRG1_ETH2_D2M: J21.B6(TD3-_2) U80.8(TD_M_C)
PRG1_ETH2_D2P: J21.B5(TD3+_2) U80.7(TD_P_C)
PRG1_ETH2_D3M: J21.B8(TD4-_2) U80.11(TD_M_D)
PRG1_ETH2_D3P: J21.B7(TD4+_2) U80.10(TD_P_D)
PRG1_ETH2_GPIO_1: R340.2 R341.1 R617.2 U80.22(JTAG_TDO/GPIO_1)
PRG1_ETH2_LED1: J21.B11 Q14.3(D)
PRG1_ETH2_LED2: J21.B14 Q21.3(D) R616.1
PRG1_ETH2_LED3: J21.B13 Q16.3(D) R615.1
PRG1_ETH2_LED_1000/RX_ER: R343.2 R386.1 R388.2 U80.46(LED_1/RX_ER) ; also on sheet 18
PRG1_ETH2_LED_ACT: R324.1 R385.1 R387.2 U80.45(LED_2/GPIO_0)
PRG1_ETH2_LED_LINK: R562.2 R563.1 U80.47(LED_0) ; also on sheet 18
PRG1_ETH3_D0M: J21.A2(TD1-_1) U20.2(TD_M_A)
PRG1_ETH3_D0P: J21.A1(TD1+_1) U20.1(TD_P_A)
PRG1_ETH3_D1M: J21.A4(TD2-_1) U20.5(TD_M_B)
PRG1_ETH3_D1P: J21.A3(TD2+_1) U20.4(TD_P_B)
PRG1_ETH3_D2M: J21.A6(TD3-_1) U20.8(TD_M_C)
PRG1_ETH3_D2P: J21.A5(TD3+_1) U20.7(TD_P_C)
PRG1_ETH3_D3M: J21.A8(TD4-_1) U20.11(TD_M_D)
PRG1_ETH3_D3P: J21.A7(TD4+_1) U20.10(TD_P_D)
PRG1_ETH3_GPIO_1: R114.2 R115.1 R614.2 U20.22(JTAG_TDO/GPIO_1)
PRG1_ETH3_LED1: J21.A11 Q15.3(D)
PRG1_ETH3_LED2: J21.A14 Q20.3(D) R613.1
PRG1_ETH3_LED3: J21.A13 Q4.3(D) R612.1
PRG1_ETH3_LED_1000/RX_ER: R94.2 R96.1 R99.2 U20.46(LED_1/RX_ER) ; also on sheet 18
PRG1_ETH3_LED_ACT: R95.2 R97.1 R334.1 U20.45(LED_2/GPIO_0)
PRG1_ETH3_LED_LINK: R564.2 R565.1 U20.47(LED_0) ; also on sheet 18
PRG1_MDIO_MDC: R104.2 U20.42(MDC) U27.8(B0) ; also on sheet 18
PRG1_MDIO_MDIO: R103.1 U20.41(MDIO) U27.2(A0) ; also on sheet 18
PRG1_RGMII1_ETH3_CLK: U20.20(XI) ; also on sheet 11
PRG1_RGMII1_ETH3_CLK_OUT: TP17.1(TP) U20.40(CLK_OUT)
PRG1_RGMII1_ETH3_RBIAS: R110.2 U20.12(RBIAS)
PRG1_RGMII1_RD0: R108.1 R310.2 U20.33(RX_D0) ; also on sheet 18
PRG1_RGMII1_RD1: R107.1 R308.2 U20.34(RX_D1) ; also on sheet 18
PRG1_RGMII1_RD2: U20.35(RX_D2) ; also on sheet 18
PRG1_RGMII1_RD3: U20.36(RX_D3) ; also on sheet 18
PRG1_RGMII1_RESETn: R102.1 U19.4(Y) U20.43(RESET_N)
PRG1_RGMII1_RX_CTL: R100.1 R101.2 U20.38(RX_CTRL/RX_DV) ; also on sheet 18
PRG1_RGMII1_RXC: U20.32(RX_CLK) ; also on sheet 18
PRG1_RGMII1_TD0: U20.28(TX_D0) ; also on sheet 18
PRG1_RGMII1_TD1: U20.27(TX_D1) ; also on sheet 18
PRG1_RGMII1_TD2: U20.26(TX_D2) ; also on sheet 18
PRG1_RGMII1_TD3: U20.25(TX_D3) ; also on sheet 18
PRG1_RGMII1_TX_CTL: U20.37(TX_CTRL/TX_EN) ; also on sheet 18
PRG1_RGMII1_TXC: U20.29(GTX_CLK/TX_CLK) ; also on sheet 18
PRG1_RGMII2_ETH2_CLK: U80.20(XI) ; also on sheet 11
PRG1_RGMII2_ETH2_CLK_OUT: TP78.1(TP) U80.40(CLK_OUT)
PRG1_RGMII2_ETH2_RBIAS: R349.2 U80.12(RBIAS)
PRG1_RGMII2_FET_ENn: R121.1 U27.9(~{EN})
PRG1_RGMII2_FET_SEL: R120.1 U27.1(SEL) ; also on sheet 13
PRG1_RGMII2_MDC: R369.2 U27.6(B) U80.42(MDC)
PRG1_RGMII2_MDIO: R370.1 U27.4(A) U80.41(MDIO)
PRG1_RGMII2_RD0: R126.2 R359.1 U80.33(RX_D0) ; also on sheet 18
PRG1_RGMII2_RD1: R128.2 R363.1 U80.34(RX_D1) ; also on sheet 18
PRG1_RGMII2_RD2: U80.35(RX_D2) ; also on sheet 18
PRG1_RGMII2_RD3: U80.36(RX_D3) ; also on sheet 18
PRG1_RGMII2_RESETn: R367.1 U31.4(Y) U80.43(RESET_N)
PRG1_RGMII2_RX_CTL: R135.1 R366.2 U80.38(RX_CTRL/RX_DV) ; also on sheet 18
PRG1_RGMII2_RXC: U80.32(RX_CLK) ; also on sheet 18
PRG1_RGMII2_TD0: U80.28(TX_D0) ; also on sheet 18
PRG1_RGMII2_TD1: U80.27(TX_D1) ; also on sheet 18
PRG1_RGMII2_TD2: U80.26(TX_D2) ; also on sheet 18
PRG1_RGMII2_TD3: U80.25(TX_D3) ; also on sheet 18
PRG1_RGMII2_TX_CTL: U80.37(TX_CTRL/TX_EN) ; also on sheet 18
PRG1_RGMII2_TXC: U80.29(GTX_CLK/TX_CLK) ; also on sheet 18
PRG1_RGMII_INTn: R105.1 R368.1 U20.44(INT_N/PWDN_N) U80.44(INT_N/PWDN_N) ; also on sheet 2 12
PRG_EARTH: C295.1 J21.SH1 J21.SH2 J21.SH3 J21.SH4 R304.1
N18117332: Q14.1(G) R324.2
N18117389: Q16.1(G) R343.1
N24754956: TP69.1(TP) U80.13(VDDA1P8_1) U80.48(VDDA1P8_2)
N24775601: TP19.1(TP) U20.13(VDDA1P8_1) U20.48(VDDA1P8_2)
N24776171: Q15.1(G) R334.2
N24776230: Q4.1(G) R99.1
N27217693: FB19.2 J21.B9(VCC)
N27218087: J21.B12 R347.2
N27219244: FB14.2 J21.A9(VCC)
N27219552: J21.A12 R336.2
N28853998: Q20.1(G) R614.1
N28854850: Q21.1(G) R617.1

Not connected (* = marked no-connect by the designer): U20 14(SON)* 15(SOP)* 16(SIP)* 17(SIN)* 19(XO)* 21(JTAG_CLK/TX_ER)* 23(JTAG_TMS)* 24(JTAG_TDI/SD)*; U80 14(SON)* 15(SOP)* 16(SIP)* 17(SIN)* 19(XO)* 21(JTAG_CLK/TX_ER)* 23(JTAG_TMS)* 24(JTAG_TDI/SD)*

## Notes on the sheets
sheet 31
- HARDWARE SCHEMATICS
- SCREWS
- JUMPERs
- STANDOFFs
- ASSEMBLY NOTES
- 1. All MSL components should be baked as per JEDEC standard.
  2. PCB should be baked at 120 degree for 8 hours.
  3. Board assembly must comply with workmanship standards.
  IPC-A-610 Class 2, unless otherwise specified.
  4. These assemblies are ESD sensitive, ESD precautions
  shall be observed.
  5. These assemblies must be clean and free from flux and
  all contaminants. Use of no clean flux is not acceptable.
  6. Provide serial numbers to the assembled boards for identification.
  7. The assembled board are wrapped in ESD Covers(individual) and
  packed securely before shipment.
- WASHER's
- FIDUCIALS
- RUBBER FEET
- TI EVM FLYERS
- Socket & Processor as Accessories
- BARE PCB
- LABELS
- LOGOs
- ORDERABLE PART NO
- Texas Intruments
- For Evaluation only; not FCC approved for resale
- WEEE Mark
- CE Mark
- Board Serial No.
- Orderable part number
- Variant
- Label Text
- 001
- TMDS64GPEVM
- Assembly Revision
- 002
- TMDS243GPEVM
- 003
- TMDS64HSEVM
- 004
- TMDS64EVM
- 005
- TMDS243EVM
sheet 32
- GPIO  MAPPING TABLE
sheet 33
- I2C TREE
sheet 34
- POWER SEQUENCE
sheet 35
- POWER FLOW DIAGRAM
- CORE SUPPLY
- ARRAY CORE SUPPLY
- STEERING RESISTORS
- 0.75 VDD_CORE
- 0.85 VDDR_CORE&OTHERS
- R2 & R4 INSTALLED
- 0.8 VDD_CORE
- 0.85 VDDR_CORE&OTHERS
- R2 & R4 INSTALLED
- 0.8 VDD_CORE & OTHERS
- 0.85 VDDR_CORE
- R1 & R4 INSTALLED
- 0.85 VDD_CORE,VDDR_CORE&OTHERS
- NONE
- R1 & R3 INSTALLED
sheet 36
- BLOCK DIAGRAM_AM64x_EVM
sheet 37
- AM64x/AM243x  EVM BOARD
- PROC101C
- TABLE OF CONTENTS
- PAGE
- CONTENTS
- PAGE
- CONTENTS
- REV
- C
- 01
- TABLE OF CONTENTS
- 35
- DEBOUNCE CIRCUIT & VOLTAGE SUPERVISOR
- VER
- 1.1
- 02
- REVISION HISTORY
- 36
- MAIN INPUT 12V DC
- 03
- BLOCK DIAGRAM AM64x EVM BOARD
- 37
- DUAL & PRE_REG POWER SUPPLY
- 04
- BLOCK DIAGRAM - XDS110
- 38
- SoC POWER SUPPLY
- 05
- POWER FLOW DIAGRAM
- 39
- PERIPHERAL POWER SUPPLY
- 06
- POWER SEQUENCE
- 40
- HARDWARE SCHEMATICS
- 07
- GPIO MAPPING TABLE
- 08
- I2C TREE
- 09
- SOC POWER
- 10
- SOC POWER CAPS
- 11
- SOC VSS
- 12
- DDR INTERFACE
- 13
- eMMC FLASH AND SDCARD INTERFACE
- 14
- OSPI FLASH
- 15
- EEPROM,PRESENCE DETECTION & TEMP SENSOR
- 16
- CPSW RGMII_1 ETHERNET PHY
- 17
- ICSSG RGMII_2 ETHERNET PHY
- 18
- ICSSG RGMII_1 ETHERNET PHY
- 19
- TEST AUTOMATION
- 20
- BOOT MODE BUFFER & SWITCHES
- 21
- CURRENT MONITORING DEVICES
- 22
- XDS110  DEBUGGER
- 23
- JTAG BUFFER
- 24
- MIPI 60 PIN CONNECTOR
- 25
- USB 2.0 INTERFACE
- 26
- FT4232 UART TO USB BRIDGE
- 27
- HSE BOARD CONNECTOR
- 28
- GPMC & FSI CONNECTOR
- 29
- CAN & DISPLAY INTERFACE
- 30
- PCIe INTERFACE
- 31
- ETHERNET PHY & PCIe CLOCK GENERATOR
- 32
- ETHERNET LEDs
- 33
- IO EXPANDER & TEST HEADER
- 34
- MCU GENERAL&SAFETY CONNECTOR
sheet 38
- REVISION HISTORY
- VER #
- DATE
- DESCRIPTION OF CHANGES
- AUTHOR
- REVIEWED  BY
- APPROVED  BY
- 0.1
- 11th MARCH 2022
- Drafted from "PROC101B_SCH" document.
- Mistral Design Team
- AJIT MB
- AJIT MB
- Removed Voltage Monitor circuit & added RC Delay Circuit for power down
  sequence requirement
  Fixed Power down sequence issue seen on AM243x REV B
- 0.2
- 11th MARCH 2022
- Mistral Design Team
- AJIT MB
- AJIT MB
- 0.3
- 11th MARCH 2022
- Updated schematics to support PG2 Silicon
- Mistral Design Team
- AJIT MB
- AJIT MB
- 1.0
- 30th MARCH 2022
- Baselined and Released
- Mistral Design Team
- AJIT MB
- AJIT MB
- Updated SoC Part Number and OPN Details
- Mistral Design Team
- AJIT MB
- AJIT MB
- 1.1
- 5th AUG 2022
- Updated SoC Symbol for Reserved pins
sheet 39
- ICSSG1 - RGMII 2
- Dual RJ45 CON With Integrated Magnetics
- Decaps
- STRAPPING RESISTORS
- PRG1 ETH2 RESET
- PHY ADDRESS = 00011
- Auto-negotiation, 10/100/1000 advertised, Auto-MDI-X
- RGMII to Copper (1000BaseT/100Base-TX/10Base-Te)
- Off Page Connections
- PRG1 MDC/MDIO FET SWITCH
- To Processor
- PRG1_ETHERNET - 2 SPEED & ACTIVITY  LED 's DRIVERS
- From Processor
- From CPSW SW
- From IO Expander
- TMUX154EDGSR Truth Table
- From Clock Buffer
sheet 40
- ICSSG1 - RGMII 1
- Dual RJ45 CON With Integrated Magnetics
- Decaps
- STRAPPING RESISTORS
- PRG1 ETH2 RESET
- PHY ADDRESS = 01111
- Auto-negotiation, 10/100/1000 advertised, Auto-MDI-X
- RGMII to Copper (1000BaseT/100Base-TX/10Base-Te)
- Off Page Connections
- To Processor
- PRG1_ETHERNET - 3 SPEED & ACTIVITY  LED 's DRIVERS
- From Processor
- From Processor
- (MDC & MDIO Pins are common to both
  ICSSG PHY, This to be verified)
- From IO Expander
- From Clock Buffer
